VERSION 5.8 ;
BUSBITCHARS "[]" ;
DIVIDERCHAR "/" ;
UNITS
    DATABASE MICRONS 1000 ;
END UNITS

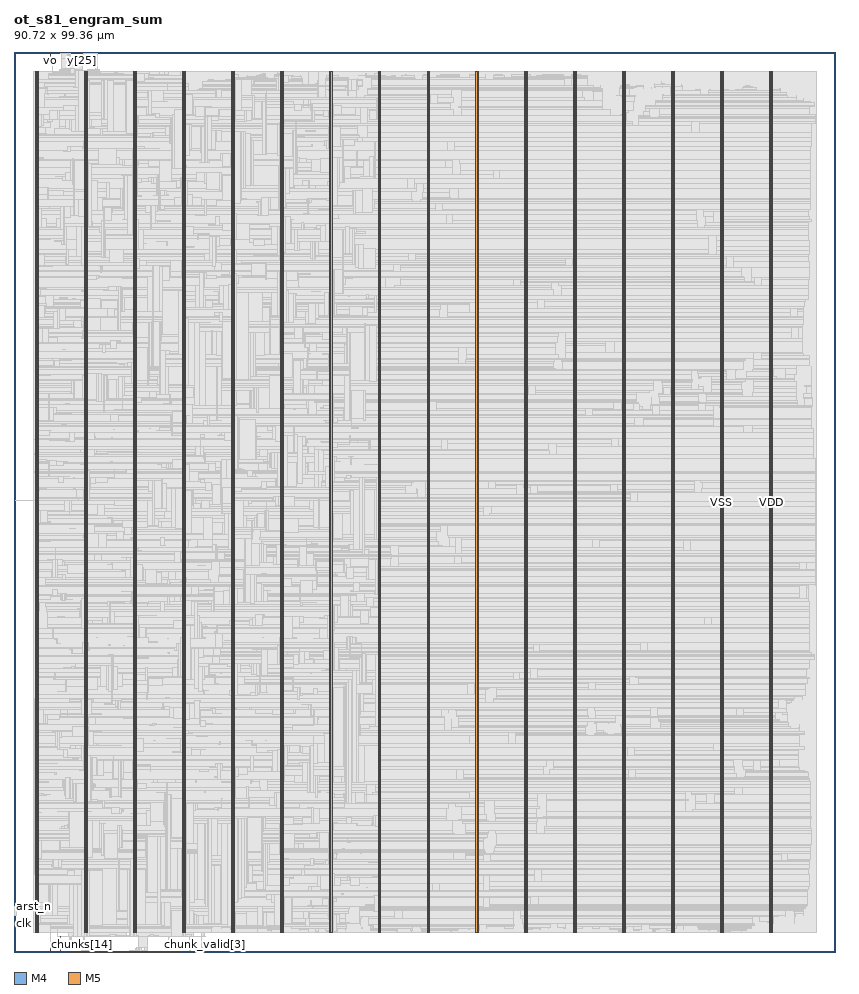
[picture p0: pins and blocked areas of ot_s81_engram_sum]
MACRO ot_s81_engram_sum
  FOREIGN ot_s81_engram_sum 0 0 ;
  CLASS BLOCK ;
  SIZE 90.72 BY 99.36 ;
  PIN arst_n
    DIRECTION INPUT ;
    USE SIGNAL ;
    PORT
      LAYER M4 ;
        RECT  0 4.992 0.084 5.016 ;
    END
  END arst_n
  PIN chunk_fault[0]
    DIRECTION INPUT ;
    USE SIGNAL ;
    PORT
      LAYER M5 ;
        RECT  19.392 0 19.416 0.084 ;
    END
  END chunk_fault[0]
  PIN chunk_fault[1]
    DIRECTION INPUT ;
    USE SIGNAL ;
    PORT
      LAYER M5 ;
        RECT  19.488 0 19.512 0.084 ;
    END
  END chunk_fault[1]
  PIN chunk_fault[2]
    DIRECTION INPUT ;
    USE SIGNAL ;
    PORT
      LAYER M5 ;
        RECT  19.584 0 19.608 0.084 ;
    END
  END chunk_fault[2]
  PIN chunk_fault[3]
    DIRECTION INPUT ;
    USE SIGNAL ;
    PORT
      LAYER M5 ;
        RECT  19.68 0 19.704 0.084 ;
    END
  END chunk_fault[3]
  PIN chunk_valid[0]
    DIRECTION INPUT ;
    USE SIGNAL ;
    PORT
      LAYER M5 ;
        RECT  20.736 0 20.76 0.084 ;
    END
  END chunk_valid[0]
  PIN chunk_valid[1]
    DIRECTION INPUT ;
    USE SIGNAL ;
    PORT
      LAYER M5 ;
        RECT  20.832 0 20.856 0.084 ;
    END
  END chunk_valid[1]
  PIN chunk_valid[2]
    DIRECTION INPUT ;
    USE SIGNAL ;
    PORT
      LAYER M5 ;
        RECT  20.928 0 20.952 0.084 ;
    END
  END chunk_valid[2]
  PIN chunk_valid[3]
    DIRECTION INPUT ;
    USE SIGNAL ;
    PORT
      LAYER M5 ;
        RECT  21.024 0 21.048 0.084 ;
    END
  END chunk_valid[3]
  PIN chunks[0]
    DIRECTION INPUT ;
    USE SIGNAL ;
    PORT
      LAYER M5 ;
        RECT  6.144 0 6.168 0.084 ;
    END
  END chunks[0]
  PIN chunks[100]
    DIRECTION INPUT ;
    USE SIGNAL ;
    PORT
      LAYER M5 ;
        RECT  15.744 0 15.768 0.084 ;
    END
  END chunks[100]
  PIN chunks[101]
    DIRECTION INPUT ;
    USE SIGNAL ;
    PORT
      LAYER M5 ;
        RECT  15.84 0 15.864 0.084 ;
    END
  END chunks[101]
  PIN chunks[102]
    DIRECTION INPUT ;
    USE SIGNAL ;
    PORT
      LAYER M5 ;
        RECT  15.936 0 15.96 0.084 ;
    END
  END chunks[102]
  PIN chunks[103]
    DIRECTION INPUT ;
    USE SIGNAL ;
    PORT
      LAYER M5 ;
        RECT  16.032 0 16.056 0.084 ;
    END
  END chunks[103]
  PIN chunks[104]
    DIRECTION INPUT ;
    USE SIGNAL ;
    PORT
      LAYER M5 ;
        RECT  16.128 0 16.152 0.084 ;
    END
  END chunks[104]
  PIN chunks[105]
    DIRECTION INPUT ;
    USE SIGNAL ;
    PORT
      LAYER M5 ;
        RECT  16.224 0 16.248 0.084 ;
    END
  END chunks[105]
  PIN chunks[106]
    DIRECTION INPUT ;
    USE SIGNAL ;
    PORT
      LAYER M5 ;
        RECT  16.32 0 16.344 0.084 ;
    END
  END chunks[106]
  PIN chunks[107]
    DIRECTION INPUT ;
    USE SIGNAL ;
    PORT
      LAYER M5 ;
        RECT  16.416 0 16.44 0.084 ;
    END
  END chunks[107]
  PIN chunks[108]
    DIRECTION INPUT ;
    USE SIGNAL ;
    PORT
      LAYER M5 ;
        RECT  16.512 0 16.536 0.084 ;
    END
  END chunks[108]
  PIN chunks[109]
    DIRECTION INPUT ;
    USE SIGNAL ;
    PORT
      LAYER M5 ;
        RECT  16.608 0 16.632 0.084 ;
    END
  END chunks[109]
  PIN chunks[10]
    DIRECTION INPUT ;
    USE SIGNAL ;
    PORT
      LAYER M5 ;
        RECT  7.104 0 7.128 0.084 ;
    END
  END chunks[10]
  PIN chunks[110]
    DIRECTION INPUT ;
    USE SIGNAL ;
    PORT
      LAYER M5 ;
        RECT  16.704 0 16.728 0.084 ;
    END
  END chunks[110]
  PIN chunks[111]
    DIRECTION INPUT ;
    USE SIGNAL ;
    PORT
      LAYER M5 ;
        RECT  16.8 0 16.824 0.084 ;
    END
  END chunks[111]
  PIN chunks[112]
    DIRECTION INPUT ;
    USE SIGNAL ;
    PORT
      LAYER M5 ;
        RECT  16.896 0 16.92 0.084 ;
    END
  END chunks[112]
  PIN chunks[113]
    DIRECTION INPUT ;
    USE SIGNAL ;
    PORT
      LAYER M5 ;
        RECT  16.992 0 17.016 0.084 ;
    END
  END chunks[113]
  PIN chunks[114]
    DIRECTION INPUT ;
    USE SIGNAL ;
    PORT
      LAYER M5 ;
        RECT  17.088 0 17.112 0.084 ;
    END
  END chunks[114]
  PIN chunks[115]
    DIRECTION INPUT ;
    USE SIGNAL ;
    PORT
      LAYER M5 ;
        RECT  17.184 0 17.208 0.084 ;
    END
  END chunks[115]
  PIN chunks[116]
    DIRECTION INPUT ;
    USE SIGNAL ;
    PORT
      LAYER M5 ;
        RECT  17.28 0 17.304 0.084 ;
    END
  END chunks[116]
  PIN chunks[117]
    DIRECTION INPUT ;
    USE SIGNAL ;
    PORT
      LAYER M5 ;
        RECT  17.376 0 17.4 0.084 ;
    END
  END chunks[117]
  PIN chunks[118]
    DIRECTION INPUT ;
    USE SIGNAL ;
    PORT
      LAYER M5 ;
        RECT  17.472 0 17.496 0.084 ;
    END
  END chunks[118]
  PIN chunks[119]
    DIRECTION INPUT ;
    USE SIGNAL ;
    PORT
      LAYER M5 ;
        RECT  17.568 0 17.592 0.084 ;
    END
  END chunks[119]
  PIN chunks[11]
    DIRECTION INPUT ;
    USE SIGNAL ;
    PORT
      LAYER M5 ;
        RECT  7.2 0 7.224 0.084 ;
    END
  END chunks[11]
  PIN chunks[120]
    DIRECTION INPUT ;
    USE SIGNAL ;
    PORT
      LAYER M5 ;
        RECT  17.664 0 17.688 0.084 ;
    END
  END chunks[120]
  PIN chunks[121]
    DIRECTION INPUT ;
    USE SIGNAL ;
    PORT
      LAYER M5 ;
        RECT  17.76 0 17.784 0.084 ;
    END
  END chunks[121]
  PIN chunks[122]
    DIRECTION INPUT ;
    USE SIGNAL ;
    PORT
      LAYER M5 ;
        RECT  17.856 0 17.88 0.084 ;
    END
  END chunks[122]
  PIN chunks[123]
    DIRECTION INPUT ;
    USE SIGNAL ;
    PORT
      LAYER M5 ;
        RECT  17.952 0 17.976 0.084 ;
    END
  END chunks[123]
  PIN chunks[124]
    DIRECTION INPUT ;
    USE SIGNAL ;
    PORT
      LAYER M5 ;
        RECT  18.048 0 18.072 0.084 ;
    END
  END chunks[124]
  PIN chunks[125]
    DIRECTION INPUT ;
    USE SIGNAL ;
    PORT
      LAYER M5 ;
        RECT  18.144 0 18.168 0.084 ;
    END
  END chunks[125]
  PIN chunks[126]
    DIRECTION INPUT ;
    USE SIGNAL ;
    PORT
      LAYER M5 ;
        RECT  18.24 0 18.264 0.084 ;
    END
  END chunks[126]
  PIN chunks[127]
    DIRECTION INPUT ;
    USE SIGNAL ;
    PORT
      LAYER M5 ;
        RECT  18.336 0 18.36 0.084 ;
    END
  END chunks[127]
  PIN chunks[12]
    DIRECTION INPUT ;
    USE SIGNAL ;
    PORT
      LAYER M5 ;
        RECT  7.296 0 7.32 0.084 ;
    END
  END chunks[12]
  PIN chunks[13]
    DIRECTION INPUT ;
    USE SIGNAL ;
    PORT
      LAYER M5 ;
        RECT  7.392 0 7.416 0.084 ;
    END
  END chunks[13]
  PIN chunks[14]
    DIRECTION INPUT ;
    USE SIGNAL ;
    PORT
      LAYER M5 ;
        RECT  7.488 0 7.512 0.084 ;
    END
  END chunks[14]
  PIN chunks[15]
    DIRECTION INPUT ;
    USE SIGNAL ;
    PORT
      LAYER M5 ;
        RECT  7.584 0 7.608 0.084 ;
    END
  END chunks[15]
  PIN chunks[16]
    DIRECTION INPUT ;
    USE SIGNAL ;
    PORT
      LAYER M5 ;
        RECT  7.68 0 7.704 0.084 ;
    END
  END chunks[16]
  PIN chunks[17]
    DIRECTION INPUT ;
    USE SIGNAL ;
    PORT
      LAYER M5 ;
        RECT  7.776 0 7.8 0.084 ;
    END
  END chunks[17]
  PIN chunks[18]
    DIRECTION INPUT ;
    USE SIGNAL ;
    PORT
      LAYER M5 ;
        RECT  7.872 0 7.896 0.084 ;
    END
  END chunks[18]
  PIN chunks[19]
    DIRECTION INPUT ;
    USE SIGNAL ;
    PORT
      LAYER M5 ;
        RECT  7.968 0 7.992 0.084 ;
    END
  END chunks[19]
  PIN chunks[1]
    DIRECTION INPUT ;
    USE SIGNAL ;
    PORT
      LAYER M5 ;
        RECT  6.24 0 6.264 0.084 ;
    END
  END chunks[1]
  PIN chunks[20]
    DIRECTION INPUT ;
    USE SIGNAL ;
    PORT
      LAYER M5 ;
        RECT  8.064 0 8.088 0.084 ;
    END
  END chunks[20]
  PIN chunks[21]
    DIRECTION INPUT ;
    USE SIGNAL ;
    PORT
      LAYER M5 ;
        RECT  8.16 0 8.184 0.084 ;
    END
  END chunks[21]
  PIN chunks[22]
    DIRECTION INPUT ;
    USE SIGNAL ;
    PORT
      LAYER M5 ;
        RECT  8.256 0 8.28 0.084 ;
    END
  END chunks[22]
  PIN chunks[23]
    DIRECTION INPUT ;
    USE SIGNAL ;
    PORT
      LAYER M5 ;
        RECT  8.352 0 8.376 0.084 ;
    END
  END chunks[23]
  PIN chunks[24]
    DIRECTION INPUT ;
    USE SIGNAL ;
    PORT
      LAYER M5 ;
        RECT  8.448 0 8.472 0.084 ;
    END
  END chunks[24]
  PIN chunks[25]
    DIRECTION INPUT ;
    USE SIGNAL ;
    PORT
      LAYER M5 ;
        RECT  8.544 0 8.568 0.084 ;
    END
  END chunks[25]
  PIN chunks[26]
    DIRECTION INPUT ;
    USE SIGNAL ;
    PORT
      LAYER M5 ;
        RECT  8.64 0 8.664 0.084 ;
    END
  END chunks[26]
  PIN chunks[27]
    DIRECTION INPUT ;
    USE SIGNAL ;
    PORT
      LAYER M5 ;
        RECT  8.736 0 8.76 0.084 ;
    END
  END chunks[27]
  PIN chunks[28]
    DIRECTION INPUT ;
    USE SIGNAL ;
    PORT
      LAYER M5 ;
        RECT  8.832 0 8.856 0.084 ;
    END
  END chunks[28]
  PIN chunks[29]
    DIRECTION INPUT ;
    USE SIGNAL ;
    PORT
      LAYER M5 ;
        RECT  8.928 0 8.952 0.084 ;
    END
  END chunks[29]
  PIN chunks[2]
    DIRECTION INPUT ;
    USE SIGNAL ;
    PORT
      LAYER M5 ;
        RECT  6.336 0 6.36 0.084 ;
    END
  END chunks[2]
  PIN chunks[30]
    DIRECTION INPUT ;
    USE SIGNAL ;
    PORT
      LAYER M5 ;
        RECT  9.024 0 9.048 0.084 ;
    END
  END chunks[30]
  PIN chunks[31]
    DIRECTION INPUT ;
    USE SIGNAL ;
    PORT
      LAYER M5 ;
        RECT  9.12 0 9.144 0.084 ;
    END
  END chunks[31]
  PIN chunks[32]
    DIRECTION INPUT ;
    USE SIGNAL ;
    PORT
      LAYER M5 ;
        RECT  9.216 0 9.24 0.084 ;
    END
  END chunks[32]
  PIN chunks[33]
    DIRECTION INPUT ;
    USE SIGNAL ;
    PORT
      LAYER M5 ;
        RECT  9.312 0 9.336 0.084 ;
    END
  END chunks[33]
  PIN chunks[34]
    DIRECTION INPUT ;
    USE SIGNAL ;
    PORT
      LAYER M5 ;
        RECT  9.408 0 9.432 0.084 ;
    END
  END chunks[34]
  PIN chunks[35]
    DIRECTION INPUT ;
    USE SIGNAL ;
    PORT
      LAYER M5 ;
        RECT  9.504 0 9.528 0.084 ;
    END
  END chunks[35]
  PIN chunks[36]
    DIRECTION INPUT ;
    USE SIGNAL ;
    PORT
      LAYER M5 ;
        RECT  9.6 0 9.624 0.084 ;
    END
  END chunks[36]
  PIN chunks[37]
    DIRECTION INPUT ;
    USE SIGNAL ;
    PORT
      LAYER M5 ;
        RECT  9.696 0 9.72 0.084 ;
    END
  END chunks[37]
  PIN chunks[38]
    DIRECTION INPUT ;
    USE SIGNAL ;
    PORT
      LAYER M5 ;
        RECT  9.792 0 9.816 0.084 ;
    END
  END chunks[38]
  PIN chunks[39]
    DIRECTION INPUT ;
    USE SIGNAL ;
    PORT
      LAYER M5 ;
        RECT  9.888 0 9.912 0.084 ;
    END
  END chunks[39]
  PIN chunks[3]
    DIRECTION INPUT ;
    USE SIGNAL ;
    PORT
      LAYER M5 ;
        RECT  6.432 0 6.456 0.084 ;
    END
  END chunks[3]
  PIN chunks[40]
    DIRECTION INPUT ;
    USE SIGNAL ;
    PORT
      LAYER M5 ;
        RECT  9.984 0 10.008 0.084 ;
    END
  END chunks[40]
  PIN chunks[41]
    DIRECTION INPUT ;
    USE SIGNAL ;
    PORT
      LAYER M5 ;
        RECT  10.08 0 10.104 0.084 ;
    END
  END chunks[41]
  PIN chunks[42]
    DIRECTION INPUT ;
    USE SIGNAL ;
    PORT
      LAYER M5 ;
        RECT  10.176 0 10.2 0.084 ;
    END
  END chunks[42]
  PIN chunks[43]
    DIRECTION INPUT ;
    USE SIGNAL ;
    PORT
      LAYER M5 ;
        RECT  10.272 0 10.296 0.084 ;
    END
  END chunks[43]
  PIN chunks[44]
    DIRECTION INPUT ;
    USE SIGNAL ;
    PORT
      LAYER M5 ;
        RECT  10.368 0 10.392 0.084 ;
    END
  END chunks[44]
  PIN chunks[45]
    DIRECTION INPUT ;
    USE SIGNAL ;
    PORT
      LAYER M5 ;
        RECT  10.464 0 10.488 0.084 ;
    END
  END chunks[45]
  PIN chunks[46]
    DIRECTION INPUT ;
    USE SIGNAL ;
    PORT
      LAYER M5 ;
        RECT  10.56 0 10.584 0.084 ;
    END
  END chunks[46]
  PIN chunks[47]
    DIRECTION INPUT ;
    USE SIGNAL ;
    PORT
      LAYER M5 ;
        RECT  10.656 0 10.68 0.084 ;
    END
  END chunks[47]
  PIN chunks[48]
    DIRECTION INPUT ;
    USE SIGNAL ;
    PORT
      LAYER M5 ;
        RECT  10.752 0 10.776 0.084 ;
    END
  END chunks[48]
  PIN chunks[49]
    DIRECTION INPUT ;
    USE SIGNAL ;
    PORT
      LAYER M5 ;
        RECT  10.848 0 10.872 0.084 ;
    END
  END chunks[49]
  PIN chunks[4]
    DIRECTION INPUT ;
    USE SIGNAL ;
    PORT
      LAYER M5 ;
        RECT  6.528 0 6.552 0.084 ;
    END
  END chunks[4]
  PIN chunks[50]
    DIRECTION INPUT ;
    USE SIGNAL ;
    PORT
      LAYER M5 ;
        RECT  10.944 0 10.968 0.084 ;
    END
  END chunks[50]
  PIN chunks[51]
    DIRECTION INPUT ;
    USE SIGNAL ;
    PORT
      LAYER M5 ;
        RECT  11.04 0 11.064 0.084 ;
    END
  END chunks[51]
  PIN chunks[52]
    DIRECTION INPUT ;
    USE SIGNAL ;
    PORT
      LAYER M5 ;
        RECT  11.136 0 11.16 0.084 ;
    END
  END chunks[52]
  PIN chunks[53]
    DIRECTION INPUT ;
    USE SIGNAL ;
    PORT
      LAYER M5 ;
        RECT  11.232 0 11.256 0.084 ;
    END
  END chunks[53]
  PIN chunks[54]
    DIRECTION INPUT ;
    USE SIGNAL ;
    PORT
      LAYER M5 ;
        RECT  11.328 0 11.352 0.084 ;
    END
  END chunks[54]
  PIN chunks[55]
    DIRECTION INPUT ;
    USE SIGNAL ;
    PORT
      LAYER M5 ;
        RECT  11.424 0 11.448 0.084 ;
    END
  END chunks[55]
  PIN chunks[56]
    DIRECTION INPUT ;
    USE SIGNAL ;
    PORT
      LAYER M5 ;
        RECT  11.52 0 11.544 0.084 ;
    END
  END chunks[56]
  PIN chunks[57]
    DIRECTION INPUT ;
    USE SIGNAL ;
    PORT
      LAYER M5 ;
        RECT  11.616 0 11.64 0.084 ;
    END
  END chunks[57]
  PIN chunks[58]
    DIRECTION INPUT ;
    USE SIGNAL ;
    PORT
      LAYER M5 ;
        RECT  11.712 0 11.736 0.084 ;
    END
  END chunks[58]
  PIN chunks[59]
    DIRECTION INPUT ;
    USE SIGNAL ;
    PORT
      LAYER M5 ;
        RECT  11.808 0 11.832 0.084 ;
    END
  END chunks[59]
  PIN chunks[5]
    DIRECTION INPUT ;
    USE SIGNAL ;
    PORT
      LAYER M5 ;
        RECT  6.624 0 6.648 0.084 ;
    END
  END chunks[5]
  PIN chunks[60]
    DIRECTION INPUT ;
    USE SIGNAL ;
    PORT
      LAYER M5 ;
        RECT  11.904 0 11.928 0.084 ;
    END
  END chunks[60]
  PIN chunks[61]
    DIRECTION INPUT ;
    USE SIGNAL ;
    PORT
      LAYER M5 ;
        RECT  12 0 12.024 0.084 ;
    END
  END chunks[61]
  PIN chunks[62]
    DIRECTION INPUT ;
    USE SIGNAL ;
    PORT
      LAYER M5 ;
        RECT  12.096 0 12.12 0.084 ;
    END
  END chunks[62]
  PIN chunks[63]
    DIRECTION INPUT ;
    USE SIGNAL ;
    PORT
      LAYER M5 ;
        RECT  12.192 0 12.216 0.084 ;
    END
  END chunks[63]
  PIN chunks[64]
    DIRECTION INPUT ;
    USE SIGNAL ;
    PORT
      LAYER M5 ;
        RECT  12.288 0 12.312 0.084 ;
    END
  END chunks[64]
  PIN chunks[65]
    DIRECTION INPUT ;
    USE SIGNAL ;
    PORT
      LAYER M5 ;
        RECT  12.384 0 12.408 0.084 ;
    END
  END chunks[65]
  PIN chunks[66]
    DIRECTION INPUT ;
    USE SIGNAL ;
    PORT
      LAYER M5 ;
        RECT  12.48 0 12.504 0.084 ;
    END
  END chunks[66]
  PIN chunks[67]
    DIRECTION INPUT ;
    USE SIGNAL ;
    PORT
      LAYER M5 ;
        RECT  12.576 0 12.6 0.084 ;
    END
  END chunks[67]
  PIN chunks[68]
    DIRECTION INPUT ;
    USE SIGNAL ;
    PORT
      LAYER M5 ;
        RECT  12.672 0 12.696 0.084 ;
    END
  END chunks[68]
  PIN chunks[69]
    DIRECTION INPUT ;
    USE SIGNAL ;
    PORT
      LAYER M5 ;
        RECT  12.768 0 12.792 0.084 ;
    END
  END chunks[69]
  PIN chunks[6]
    DIRECTION INPUT ;
    USE SIGNAL ;
    PORT
      LAYER M5 ;
        RECT  6.72 0 6.744 0.084 ;
    END
  END chunks[6]
  PIN chunks[70]
    DIRECTION INPUT ;
    USE SIGNAL ;
    PORT
      LAYER M5 ;
        RECT  12.864 0 12.888 0.084 ;
    END
  END chunks[70]
  PIN chunks[71]
    DIRECTION INPUT ;
    USE SIGNAL ;
    PORT
      LAYER M5 ;
        RECT  12.96 0 12.984 0.084 ;
    END
  END chunks[71]
  PIN chunks[72]
    DIRECTION INPUT ;
    USE SIGNAL ;
    PORT
      LAYER M5 ;
        RECT  13.056 0 13.08 0.084 ;
    END
  END chunks[72]
  PIN chunks[73]
    DIRECTION INPUT ;
    USE SIGNAL ;
    PORT
      LAYER M5 ;
        RECT  13.152 0 13.176 0.084 ;
    END
  END chunks[73]
  PIN chunks[74]
    DIRECTION INPUT ;
    USE SIGNAL ;
    PORT
      LAYER M5 ;
        RECT  13.248 0 13.272 0.084 ;
    END
  END chunks[74]
  PIN chunks[75]
    DIRECTION INPUT ;
    USE SIGNAL ;
    PORT
      LAYER M5 ;
        RECT  13.344 0 13.368 0.084 ;
    END
  END chunks[75]
  PIN chunks[76]
    DIRECTION INPUT ;
    USE SIGNAL ;
    PORT
      LAYER M5 ;
        RECT  13.44 0 13.464 0.084 ;
    END
  END chunks[76]
  PIN chunks[77]
    DIRECTION INPUT ;
    USE SIGNAL ;
    PORT
      LAYER M5 ;
        RECT  13.536 0 13.56 0.084 ;
    END
  END chunks[77]
  PIN chunks[78]
    DIRECTION INPUT ;
    USE SIGNAL ;
    PORT
      LAYER M5 ;
        RECT  13.632 0 13.656 0.084 ;
    END
  END chunks[78]
  PIN chunks[79]
    DIRECTION INPUT ;
    USE SIGNAL ;
    PORT
      LAYER M5 ;
        RECT  13.728 0 13.752 0.084 ;
    END
  END chunks[79]
  PIN chunks[7]
    DIRECTION INPUT ;
    USE SIGNAL ;
    PORT
      LAYER M5 ;
        RECT  6.816 0 6.84 0.084 ;
    END
  END chunks[7]
  PIN chunks[80]
    DIRECTION INPUT ;
    USE SIGNAL ;
    PORT
      LAYER M5 ;
        RECT  13.824 0 13.848 0.084 ;
    END
  END chunks[80]
  PIN chunks[81]
    DIRECTION INPUT ;
    USE SIGNAL ;
    PORT
      LAYER M5 ;
        RECT  13.92 0 13.944 0.084 ;
    END
  END chunks[81]
  PIN chunks[82]
    DIRECTION INPUT ;
    USE SIGNAL ;
    PORT
      LAYER M5 ;
        RECT  14.016 0 14.04 0.084 ;
    END
  END chunks[82]
  PIN chunks[83]
    DIRECTION INPUT ;
    USE SIGNAL ;
    PORT
      LAYER M5 ;
        RECT  14.112 0 14.136 0.084 ;
    END
  END chunks[83]
  PIN chunks[84]
    DIRECTION INPUT ;
    USE SIGNAL ;
    PORT
      LAYER M5 ;
        RECT  14.208 0 14.232 0.084 ;
    END
  END chunks[84]
  PIN chunks[85]
    DIRECTION INPUT ;
    USE SIGNAL ;
    PORT
      LAYER M5 ;
        RECT  14.304 0 14.328 0.084 ;
    END
  END chunks[85]
  PIN chunks[86]
    DIRECTION INPUT ;
    USE SIGNAL ;
    PORT
      LAYER M5 ;
        RECT  14.4 0 14.424 0.084 ;
    END
  END chunks[86]
  PIN chunks[87]
    DIRECTION INPUT ;
    USE SIGNAL ;
    PORT
      LAYER M5 ;
        RECT  14.496 0 14.52 0.084 ;
    END
  END chunks[87]
  PIN chunks[88]
    DIRECTION INPUT ;
    USE SIGNAL ;
    PORT
      LAYER M5 ;
        RECT  14.592 0 14.616 0.084 ;
    END
  END chunks[88]
  PIN chunks[89]
    DIRECTION INPUT ;
    USE SIGNAL ;
    PORT
      LAYER M5 ;
        RECT  14.688 0 14.712 0.084 ;
    END
  END chunks[89]
  PIN chunks[8]
    DIRECTION INPUT ;
    USE SIGNAL ;
    PORT
      LAYER M5 ;
        RECT  6.912 0 6.936 0.084 ;
    END
  END chunks[8]
  PIN chunks[90]
    DIRECTION INPUT ;
    USE SIGNAL ;
    PORT
      LAYER M5 ;
        RECT  14.784 0 14.808 0.084 ;
    END
  END chunks[90]
  PIN chunks[91]
    DIRECTION INPUT ;
    USE SIGNAL ;
    PORT
      LAYER M5 ;
        RECT  14.88 0 14.904 0.084 ;
    END
  END chunks[91]
  PIN chunks[92]
    DIRECTION INPUT ;
    USE SIGNAL ;
    PORT
      LAYER M5 ;
        RECT  14.976 0 15 0.084 ;
    END
  END chunks[92]
  PIN chunks[93]
    DIRECTION INPUT ;
    USE SIGNAL ;
    PORT
      LAYER M5 ;
        RECT  15.072 0 15.096 0.084 ;
    END
  END chunks[93]
  PIN chunks[94]
    DIRECTION INPUT ;
    USE SIGNAL ;
    PORT
      LAYER M5 ;
        RECT  15.168 0 15.192 0.084 ;
    END
  END chunks[94]
  PIN chunks[95]
    DIRECTION INPUT ;
    USE SIGNAL ;
    PORT
      LAYER M5 ;
        RECT  15.264 0 15.288 0.084 ;
    END
  END chunks[95]
  PIN chunks[96]
    DIRECTION INPUT ;
    USE SIGNAL ;
    PORT
      LAYER M5 ;
        RECT  15.36 0 15.384 0.084 ;
    END
  END chunks[96]
  PIN chunks[97]
    DIRECTION INPUT ;
    USE SIGNAL ;
    PORT
      LAYER M5 ;
        RECT  15.456 0 15.48 0.084 ;
    END
  END chunks[97]
  PIN chunks[98]
    DIRECTION INPUT ;
    USE SIGNAL ;
    PORT
      LAYER M5 ;
        RECT  15.552 0 15.576 0.084 ;
    END
  END chunks[98]
  PIN chunks[99]
    DIRECTION INPUT ;
    USE SIGNAL ;
    PORT
      LAYER M5 ;
        RECT  15.648 0 15.672 0.084 ;
    END
  END chunks[99]
  PIN chunks[9]
    DIRECTION INPUT ;
    USE SIGNAL ;
    PORT
      LAYER M5 ;
        RECT  7.008 0 7.032 0.084 ;
    END
  END chunks[9]
  PIN clk
    DIRECTION INPUT ;
    USE SIGNAL ;
    PORT
      LAYER M4 ;
        RECT  0 4.032 0.084 4.056 ;
    END
  END clk
  PIN fault
    DIRECTION OUTPUT ;
    USE SIGNAL ;
    PORT
      LAYER M5 ;
        RECT  9.12 99.276 9.144 99.36 ;
    END
    PORT
      LAYER M5 ;
        RECT  9.12 99.251 9.144 99.344 ;
    END
  END fault
  PIN go
    DIRECTION INPUT ;
    USE SIGNAL ;
    PORT
      LAYER M5 ;
        RECT  4.032 0 4.056 0.084 ;
    END
    PORT
      LAYER M5 ;
        RECT  4.032 0.016 4.056 0.611 ;
    END
  END go
  PIN v
    DIRECTION INPUT ;
    USE SIGNAL ;
    PORT
      LAYER M5 ;
        RECT  5.088 0 5.112 0.084 ;
    END
    PORT
      LAYER M5 ;
        RECT  5.088 0.016 5.112 1.763 ;
    END
  END v
  PIN vo
    DIRECTION OUTPUT ;
    USE SIGNAL ;
    PORT
      LAYER M5 ;
        RECT  4.032 99.276 4.056 99.36 ;
    END
    PORT
      LAYER M5 ;
        RECT  4.032 98.053 4.056 99.344 ;
    END
  END vo
  PIN y[0]
    DIRECTION OUTPUT ;
    USE SIGNAL ;
    PORT
      LAYER M5 ;
        RECT  5.088 99.276 5.112 99.36 ;
    END
  END y[0]
  PIN y[10]
    DIRECTION OUTPUT ;
    USE SIGNAL ;
    PORT
      LAYER M5 ;
        RECT  6.048 99.276 6.072 99.36 ;
    END
  END y[10]
  PIN y[11]
    DIRECTION OUTPUT ;
    USE SIGNAL ;
    PORT
      LAYER M5 ;
        RECT  6.144 99.276 6.168 99.36 ;
    END
  END y[11]
  PIN y[12]
    DIRECTION OUTPUT ;
    USE SIGNAL ;
    PORT
      LAYER M5 ;
        RECT  6.24 99.276 6.264 99.36 ;
    END
  END y[12]
  PIN y[13]
    DIRECTION OUTPUT ;
    USE SIGNAL ;
    PORT
      LAYER M5 ;
        RECT  6.336 99.276 6.36 99.36 ;
    END
  END y[13]
  PIN y[14]
    DIRECTION OUTPUT ;
    USE SIGNAL ;
    PORT
      LAYER M5 ;
        RECT  6.432 99.276 6.456 99.36 ;
    END
  END y[14]
  PIN y[15]
    DIRECTION OUTPUT ;
    USE SIGNAL ;
    PORT
      LAYER M5 ;
        RECT  6.528 99.276 6.552 99.36 ;
    END
  END y[15]
  PIN y[16]
    DIRECTION OUTPUT ;
    USE SIGNAL ;
    PORT
      LAYER M5 ;
        RECT  6.624 99.276 6.648 99.36 ;
    END
  END y[16]
  PIN y[17]
    DIRECTION OUTPUT ;
    USE SIGNAL ;
    PORT
      LAYER M5 ;
        RECT  6.72 99.276 6.744 99.36 ;
    END
  END y[17]
  PIN y[18]
    DIRECTION OUTPUT ;
    USE SIGNAL ;
    PORT
      LAYER M5 ;
        RECT  6.816 99.276 6.84 99.36 ;
    END
  END y[18]
  PIN y[19]
    DIRECTION OUTPUT ;
    USE SIGNAL ;
    PORT
      LAYER M5 ;
        RECT  6.912 99.276 6.936 99.36 ;
    END
  END y[19]
  PIN y[1]
    DIRECTION OUTPUT ;
    USE SIGNAL ;
    PORT
      LAYER M5 ;
        RECT  5.184 99.276 5.208 99.36 ;
    END
  END y[1]
  PIN y[20]
    DIRECTION OUTPUT ;
    USE SIGNAL ;
    PORT
      LAYER M5 ;
        RECT  7.008 99.276 7.032 99.36 ;
    END
  END y[20]
  PIN y[21]
    DIRECTION OUTPUT ;
    USE SIGNAL ;
    PORT
      LAYER M5 ;
        RECT  7.104 99.276 7.128 99.36 ;
    END
  END y[21]
  PIN y[22]
    DIRECTION OUTPUT ;
    USE SIGNAL ;
    PORT
      LAYER M5 ;
        RECT  7.2 99.276 7.224 99.36 ;
    END
  END y[22]
  PIN y[23]
    DIRECTION OUTPUT ;
    USE SIGNAL ;
    PORT
      LAYER M5 ;
        RECT  7.296 99.276 7.32 99.36 ;
    END
  END y[23]
  PIN y[24]
    DIRECTION OUTPUT ;
    USE SIGNAL ;
    PORT
      LAYER M5 ;
        RECT  7.392 99.276 7.416 99.36 ;
    END
  END y[24]
  PIN y[25]
    DIRECTION OUTPUT ;
    USE SIGNAL ;
    PORT
      LAYER M5 ;
        RECT  7.488 99.276 7.512 99.36 ;
    END
  END y[25]
  PIN y[26]
    DIRECTION OUTPUT ;
    USE SIGNAL ;
    PORT
      LAYER M5 ;
        RECT  7.584 99.276 7.608 99.36 ;
    END
  END y[26]
  PIN y[27]
    DIRECTION OUTPUT ;
    USE SIGNAL ;
    PORT
      LAYER M5 ;
        RECT  7.68 99.276 7.704 99.36 ;
    END
  END y[27]
  PIN y[28]
    DIRECTION OUTPUT ;
    USE SIGNAL ;
    PORT
      LAYER M5 ;
        RECT  7.776 99.276 7.8 99.36 ;
    END
  END y[28]
  PIN y[29]
    DIRECTION OUTPUT ;
    USE SIGNAL ;
    PORT
      LAYER M5 ;
        RECT  7.872 99.276 7.896 99.36 ;
    END
  END y[29]
  PIN y[2]
    DIRECTION OUTPUT ;
    USE SIGNAL ;
    PORT
      LAYER M5 ;
        RECT  5.28 99.276 5.304 99.36 ;
    END
  END y[2]
  PIN y[30]
    DIRECTION OUTPUT ;
    USE SIGNAL ;
    PORT
      LAYER M5 ;
        RECT  7.968 99.276 7.992 99.36 ;
    END
  END y[30]
  PIN y[31]
    DIRECTION OUTPUT ;
    USE SIGNAL ;
    PORT
      LAYER M5 ;
        RECT  8.064 99.276 8.088 99.36 ;
    END
  END y[31]
  PIN y[3]
    DIRECTION OUTPUT ;
    USE SIGNAL ;
    PORT
      LAYER M5 ;
        RECT  5.376 99.276 5.4 99.36 ;
    END
  END y[3]
  PIN y[4]
    DIRECTION OUTPUT ;
    USE SIGNAL ;
    PORT
      LAYER M5 ;
        RECT  5.472 99.276 5.496 99.36 ;
    END
  END y[4]
  PIN y[5]
    DIRECTION OUTPUT ;
    USE SIGNAL ;
    PORT
      LAYER M5 ;
        RECT  5.568 99.276 5.592 99.36 ;
    END
  END y[5]
  PIN y[6]
    DIRECTION OUTPUT ;
    USE SIGNAL ;
    PORT
      LAYER M5 ;
        RECT  5.664 99.276 5.688 99.36 ;
    END
  END y[6]
  PIN y[7]
    DIRECTION OUTPUT ;
    USE SIGNAL ;
    PORT
      LAYER M5 ;
        RECT  5.76 99.276 5.784 99.36 ;
    END
  END y[7]
  PIN y[8]
    DIRECTION OUTPUT ;
    USE SIGNAL ;
    PORT
      LAYER M5 ;
        RECT  5.856 99.276 5.88 99.36 ;
    END
  END y[8]
  PIN y[9]
    DIRECTION OUTPUT ;
    USE SIGNAL ;
    PORT
      LAYER M5 ;
        RECT  5.952 99.276 5.976 99.36 ;
    END
  END y[9]
  PIN VDD
    DIRECTION INOUT ;
    USE POWER ;
    PORT
      LAYER M5 ;
        RECT  83.592 2.151 83.712 97.209 ;
        RECT  78.192 2.151 78.312 97.209 ;
        RECT  72.792 2.151 72.912 97.209 ;
        RECT  67.392 2.151 67.512 97.209 ;
        RECT  61.992 2.151 62.112 97.209 ;
        RECT  56.592 2.151 56.712 97.209 ;
        RECT  51.192 2.151 51.312 97.209 ;
        RECT  45.792 2.151 45.912 97.209 ;
        RECT  40.392 2.151 40.512 97.209 ;
        RECT  34.992 2.151 35.112 97.209 ;
        RECT  29.592 2.151 29.712 97.209 ;
        RECT  24.192 2.151 24.312 97.209 ;
        RECT  18.792 2.151 18.912 97.209 ;
        RECT  13.392 2.151 13.512 97.209 ;
        RECT  7.992 2.151 8.112 97.209 ;
        RECT  2.592 2.151 2.712 97.209 ;
    END
  END VDD
  PIN VSS
    DIRECTION INOUT ;
    USE GROUND ;
    PORT
      LAYER M5 ;
        RECT  83.4 2.137 83.52 97.223 ;
        RECT  78 2.137 78.12 97.223 ;
        RECT  72.6 2.137 72.72 97.223 ;
        RECT  67.2 2.137 67.32 97.223 ;
        RECT  61.8 2.137 61.92 97.223 ;
        RECT  56.4 2.137 56.52 97.223 ;
        RECT  51 2.137 51.12 97.223 ;
        RECT  45.6 2.137 45.72 97.223 ;
        RECT  40.2 2.137 40.32 97.223 ;
        RECT  34.8 2.137 34.92 97.223 ;
        RECT  29.4 2.137 29.52 97.223 ;
        RECT  24 2.137 24.12 97.223 ;
        RECT  18.6 2.137 18.72 97.223 ;
        RECT  13.2 2.137 13.32 97.223 ;
        RECT  7.8 2.137 7.92 97.223 ;
        RECT  2.4 2.137 2.52 97.223 ;
    END
  END VSS
  # OT_OBS_CLOSED layer=M5 d_um=1.536 added=496
  OBS
    LAYER RVTN ;
     RECT  2.16 2.16 88.56 2.295 ;
     RECT  2.16 2.565 88.56 2.835 ;
     RECT  2.16 3.105 88.56 3.375 ;
     RECT  2.16 3.645 88.56 3.915 ;
     RECT  2.16 4.185 88.56 4.455 ;
     RECT  2.16 4.725 88.56 4.995 ;
     RECT  2.16 5.265 88.56 5.535 ;
     RECT  2.16 5.805 88.56 6.075 ;
     RECT  2.16 6.345 88.56 6.615 ;
     RECT  2.16 6.885 88.56 7.155 ;
     RECT  2.16 7.425 88.56 7.695 ;
     RECT  2.16 7.965 88.56 8.235 ;
     RECT  2.16 8.505 88.56 8.775 ;
     RECT  2.16 9.045 88.56 9.315 ;
     RECT  2.16 9.585 88.56 9.855 ;
     RECT  2.16 10.125 88.56 10.395 ;
     RECT  2.16 10.665 88.56 10.935 ;
     RECT  2.16 11.205 88.56 11.475 ;
     RECT  2.16 11.745 88.56 12.015 ;
     RECT  2.16 12.285 88.56 12.555 ;
     RECT  2.16 12.825 88.56 13.095 ;
     RECT  2.16 13.365 88.56 13.635 ;
     RECT  2.16 13.905 88.56 14.175 ;
     RECT  2.16 14.445 88.56 14.715 ;
     RECT  2.16 14.985 88.56 15.255 ;
     RECT  2.16 15.525 88.56 15.795 ;
     RECT  2.16 16.065 88.56 16.335 ;
     RECT  2.16 16.605 88.56 16.875 ;
     RECT  2.16 17.145 88.56 17.415 ;
     RECT  2.16 17.685 88.56 17.955 ;
     RECT  2.16 18.225 88.56 18.495 ;
     RECT  2.16 18.765 88.56 19.035 ;
     RECT  2.16 19.305 88.56 19.575 ;
     RECT  2.16 19.845 88.56 20.115 ;
     RECT  2.16 20.385 88.56 20.655 ;
     RECT  2.16 20.925 88.56 21.195 ;
     RECT  2.16 21.465 88.56 21.735 ;
     RECT  2.16 22.005 88.56 22.275 ;
     RECT  2.16 22.545 88.56 22.815 ;
     RECT  2.16 23.085 88.56 23.355 ;
     RECT  2.16 23.625 88.56 23.895 ;
     RECT  2.16 24.165 88.56 24.435 ;
     RECT  2.16 24.705 88.56 24.975 ;
     RECT  2.16 25.245 88.56 25.515 ;
     RECT  2.16 25.785 88.56 26.055 ;
     RECT  2.16 26.325 88.56 26.595 ;
     RECT  2.16 26.865 88.56 27.135 ;
     RECT  2.16 27.405 88.56 27.675 ;
     RECT  2.16 27.945 88.56 28.215 ;
     RECT  2.16 28.485 88.56 28.755 ;
     RECT  2.16 29.025 88.56 29.295 ;
     RECT  2.16 29.565 88.56 29.835 ;
     RECT  2.16 30.105 88.56 30.375 ;
     RECT  2.16 30.645 88.56 30.915 ;
     RECT  2.16 31.185 88.56 31.455 ;
     RECT  2.16 31.725 88.56 31.995 ;
     RECT  2.16 32.265 88.56 32.535 ;
     RECT  2.16 32.805 88.56 33.075 ;
     RECT  2.16 33.345 88.56 33.615 ;
     RECT  2.16 33.885 88.56 34.155 ;
     RECT  2.16 34.425 88.56 34.695 ;
     RECT  2.16 34.965 88.56 35.235 ;
     RECT  2.16 35.505 88.56 35.775 ;
     RECT  2.16 36.045 88.56 36.315 ;
     RECT  2.16 36.585 88.56 36.855 ;
     RECT  2.16 37.125 88.56 37.395 ;
     RECT  2.16 37.665 88.56 37.935 ;
     RECT  2.16 38.205 88.56 38.475 ;
     RECT  2.16 38.745 88.56 39.015 ;
     RECT  2.16 39.285 88.56 39.555 ;
     RECT  2.16 39.825 88.56 40.095 ;
     RECT  2.16 40.365 88.56 40.635 ;
     RECT  2.16 40.905 88.56 41.175 ;
     RECT  2.16 41.445 88.56 41.715 ;
     RECT  2.16 41.985 88.56 42.255 ;
     RECT  2.16 42.525 88.56 42.795 ;
     RECT  2.16 43.065 88.56 43.335 ;
     RECT  2.16 43.605 88.56 43.875 ;
     RECT  2.16 44.145 88.56 44.415 ;
     RECT  2.16 44.685 88.56 44.955 ;
     RECT  2.16 45.225 88.56 45.495 ;
     RECT  2.16 45.765 88.56 46.035 ;
     RECT  2.16 46.305 88.56 46.575 ;
     RECT  2.16 46.845 88.56 47.115 ;
     RECT  2.16 47.385 88.56 47.655 ;
     RECT  2.16 47.925 88.56 48.195 ;
     RECT  2.16 48.465 88.56 48.735 ;
     RECT  2.16 49.005 88.56 49.275 ;
     RECT  2.16 49.545 88.56 49.815 ;
     RECT  2.16 50.085 88.56 50.355 ;
     RECT  2.16 50.625 88.56 50.895 ;
     RECT  2.16 51.165 88.56 51.435 ;
     RECT  2.16 51.705 88.56 51.975 ;
     RECT  2.16 52.245 88.56 52.515 ;
     RECT  2.16 52.785 88.56 53.055 ;
     RECT  2.16 53.325 88.56 53.595 ;
     RECT  2.16 53.865 88.56 54.135 ;
     RECT  2.16 54.405 88.56 54.675 ;
     RECT  2.16 54.945 88.56 55.215 ;
     RECT  2.16 55.485 88.56 55.755 ;
     RECT  2.16 56.025 88.56 56.295 ;
     RECT  2.16 56.565 88.56 56.835 ;
     RECT  2.16 57.105 88.56 57.375 ;
     RECT  2.16 57.645 88.56 57.915 ;
     RECT  2.16 58.185 88.56 58.455 ;
     RECT  2.16 58.725 88.56 58.995 ;
     RECT  2.16 59.265 88.56 59.535 ;
     RECT  2.16 59.805 88.56 60.075 ;
     RECT  2.16 60.345 88.56 60.615 ;
     RECT  2.16 60.885 88.56 61.155 ;
     RECT  2.16 61.425 88.56 61.695 ;
     RECT  2.16 61.965 88.56 62.235 ;
     RECT  2.16 62.505 88.56 62.775 ;
     RECT  2.16 63.045 88.56 63.315 ;
     RECT  2.16 63.585 88.56 63.855 ;
     RECT  2.16 64.125 88.56 64.395 ;
     RECT  2.16 64.665 88.56 64.935 ;
     RECT  2.16 65.205 88.56 65.475 ;
     RECT  2.16 65.745 88.56 66.015 ;
     RECT  2.16 66.285 88.56 66.555 ;
     RECT  2.16 66.825 88.56 67.095 ;
     RECT  2.16 67.365 88.56 67.635 ;
     RECT  2.16 67.905 88.56 68.175 ;
     RECT  2.16 68.445 88.56 68.715 ;
     RECT  2.16 68.985 88.56 69.255 ;
     RECT  2.16 69.525 88.56 69.795 ;
     RECT  2.16 70.065 88.56 70.335 ;
     RECT  2.16 70.605 88.56 70.875 ;
     RECT  2.16 71.145 88.56 71.415 ;
     RECT  2.16 71.685 88.56 71.955 ;
     RECT  2.16 72.225 88.56 72.495 ;
     RECT  2.16 72.765 88.56 73.035 ;
     RECT  2.16 73.305 88.56 73.575 ;
     RECT  2.16 73.845 88.56 74.115 ;
     RECT  2.16 74.385 88.56 74.655 ;
     RECT  2.16 74.925 88.56 75.195 ;
     RECT  2.16 75.465 88.56 75.735 ;
     RECT  2.16 76.005 88.56 76.275 ;
     RECT  2.16 76.545 88.56 76.815 ;
     RECT  2.16 77.085 88.56 77.355 ;
     RECT  2.16 77.625 88.56 77.895 ;
     RECT  2.16 78.165 88.56 78.435 ;
     RECT  2.16 78.705 88.56 78.975 ;
     RECT  2.16 79.245 88.56 79.515 ;
     RECT  2.16 79.785 88.56 80.055 ;
     RECT  2.16 80.325 88.56 80.595 ;
     RECT  2.16 80.865 88.56 81.135 ;
     RECT  2.16 81.405 88.56 81.675 ;
     RECT  2.16 81.945 88.56 82.215 ;
     RECT  2.16 82.485 88.56 82.755 ;
     RECT  2.16 83.025 88.56 83.295 ;
     RECT  2.16 83.565 88.56 83.835 ;
     RECT  2.16 84.105 88.56 84.375 ;
     RECT  2.16 84.645 88.56 84.915 ;
     RECT  2.16 85.185 88.56 85.455 ;
     RECT  2.16 85.725 88.56 85.995 ;
     RECT  2.16 86.265 88.56 86.535 ;
     RECT  2.16 86.805 88.56 87.075 ;
     RECT  2.16 87.345 88.56 87.615 ;
     RECT  2.16 87.885 88.56 88.155 ;
     RECT  2.16 88.425 88.56 88.695 ;
     RECT  2.16 88.965 88.56 89.235 ;
     RECT  2.16 89.505 88.56 89.775 ;
     RECT  2.16 90.045 88.56 90.315 ;
     RECT  2.16 90.585 88.56 90.855 ;
     RECT  2.16 91.125 88.56 91.395 ;
     RECT  2.16 91.665 88.56 91.935 ;
     RECT  2.16 92.205 88.56 92.475 ;
     RECT  2.16 92.745 88.56 93.015 ;
     RECT  2.16 93.285 88.56 93.555 ;
     RECT  2.16 93.825 88.56 94.095 ;
     RECT  2.16 94.365 88.56 94.635 ;
     RECT  2.16 94.905 88.56 95.175 ;
     RECT  2.16 95.445 88.56 95.715 ;
     RECT  2.16 95.985 88.56 96.255 ;
     RECT  2.16 96.525 88.56 96.795 ;
     RECT  2.16 97.065 88.56 97.2 ;
    LAYER RVTP ;
     RECT  2.16 2.295 88.56 2.565 ;
     RECT  2.16 2.835 88.56 3.105 ;
     RECT  2.16 3.375 88.56 3.645 ;
     RECT  2.16 3.915 88.56 4.185 ;
     RECT  2.16 4.455 88.56 4.725 ;
     RECT  2.16 4.995 88.56 5.265 ;
     RECT  2.16 5.535 88.56 5.805 ;
     RECT  2.16 6.075 88.56 6.345 ;
     RECT  2.16 6.615 88.56 6.885 ;
     RECT  2.16 7.155 88.56 7.425 ;
     RECT  2.16 7.695 88.56 7.965 ;
     RECT  2.16 8.235 88.56 8.505 ;
     RECT  2.16 8.775 88.56 9.045 ;
     RECT  2.16 9.315 88.56 9.585 ;
     RECT  2.16 9.855 88.56 10.125 ;
     RECT  2.16 10.395 88.56 10.665 ;
     RECT  2.16 10.935 88.56 11.205 ;
     RECT  2.16 11.475 88.56 11.745 ;
     RECT  2.16 12.015 88.56 12.285 ;
     RECT  2.16 12.555 88.56 12.825 ;
     RECT  2.16 13.095 88.56 13.365 ;
     RECT  2.16 13.635 88.56 13.905 ;
     RECT  2.16 14.175 88.56 14.445 ;
     RECT  2.16 14.715 88.56 14.985 ;
     RECT  2.16 15.255 88.56 15.525 ;
     RECT  2.16 15.795 88.56 16.065 ;
     RECT  2.16 16.335 88.56 16.605 ;
     RECT  2.16 16.875 88.56 17.145 ;
     RECT  2.16 17.415 88.56 17.685 ;
     RECT  2.16 17.955 88.56 18.225 ;
     RECT  2.16 18.495 88.56 18.765 ;
     RECT  2.16 19.035 88.56 19.305 ;
     RECT  2.16 19.575 88.56 19.845 ;
     RECT  2.16 20.115 88.56 20.385 ;
     RECT  2.16 20.655 88.56 20.925 ;
     RECT  2.16 21.195 88.56 21.465 ;
     RECT  2.16 21.735 88.56 22.005 ;
     RECT  2.16 22.275 88.56 22.545 ;
     RECT  2.16 22.815 88.56 23.085 ;
     RECT  2.16 23.355 88.56 23.625 ;
     RECT  2.16 23.895 88.56 24.165 ;
     RECT  2.16 24.435 88.56 24.705 ;
     RECT  2.16 24.975 88.56 25.245 ;
     RECT  2.16 25.515 88.56 25.785 ;
     RECT  2.16 26.055 88.56 26.325 ;
     RECT  2.16 26.595 88.56 26.865 ;
     RECT  2.16 27.135 88.56 27.405 ;
     RECT  2.16 27.675 88.56 27.945 ;
     RECT  2.16 28.215 88.56 28.485 ;
     RECT  2.16 28.755 88.56 29.025 ;
     RECT  2.16 29.295 88.56 29.565 ;
     RECT  2.16 29.835 88.56 30.105 ;
     RECT  2.16 30.375 88.56 30.645 ;
     RECT  2.16 30.915 88.56 31.185 ;
     RECT  2.16 31.455 88.56 31.725 ;
     RECT  2.16 31.995 88.56 32.265 ;
     RECT  2.16 32.535 88.56 32.805 ;
     RECT  2.16 33.075 88.56 33.345 ;
     RECT  2.16 33.615 88.56 33.885 ;
     RECT  2.16 34.155 88.56 34.425 ;
     RECT  2.16 34.695 88.56 34.965 ;
     RECT  2.16 35.235 88.56 35.505 ;
     RECT  2.16 35.775 88.56 36.045 ;
     RECT  2.16 36.315 88.56 36.585 ;
     RECT  2.16 36.855 88.56 37.125 ;
     RECT  2.16 37.395 88.56 37.665 ;
     RECT  2.16 37.935 88.56 38.205 ;
     RECT  2.16 38.475 88.56 38.745 ;
     RECT  2.16 39.015 88.56 39.285 ;
     RECT  2.16 39.555 88.56 39.825 ;
     RECT  2.16 40.095 88.56 40.365 ;
     RECT  2.16 40.635 88.56 40.905 ;
     RECT  2.16 41.175 88.56 41.445 ;
     RECT  2.16 41.715 88.56 41.985 ;
     RECT  2.16 42.255 88.56 42.525 ;
     RECT  2.16 42.795 88.56 43.065 ;
     RECT  2.16 43.335 88.56 43.605 ;
     RECT  2.16 43.875 88.56 44.145 ;
     RECT  2.16 44.415 88.56 44.685 ;
     RECT  2.16 44.955 88.56 45.225 ;
     RECT  2.16 45.495 88.56 45.765 ;
     RECT  2.16 46.035 88.56 46.305 ;
     RECT  2.16 46.575 88.56 46.845 ;
     RECT  2.16 47.115 88.56 47.385 ;
     RECT  2.16 47.655 88.56 47.925 ;
     RECT  2.16 48.195 88.56 48.465 ;
     RECT  2.16 48.735 88.56 49.005 ;
     RECT  2.16 49.275 88.56 49.545 ;
     RECT  2.16 49.815 88.56 50.085 ;
     RECT  2.16 50.355 88.56 50.625 ;
     RECT  2.16 50.895 88.56 51.165 ;
     RECT  2.16 51.435 88.56 51.705 ;
     RECT  2.16 51.975 88.56 52.245 ;
     RECT  2.16 52.515 88.56 52.785 ;
     RECT  2.16 53.055 88.56 53.325 ;
     RECT  2.16 53.595 88.56 53.865 ;
     RECT  2.16 54.135 88.56 54.405 ;
     RECT  2.16 54.675 88.56 54.945 ;
     RECT  2.16 55.215 88.56 55.485 ;
     RECT  2.16 55.755 88.56 56.025 ;
     RECT  2.16 56.295 88.56 56.565 ;
     RECT  2.16 56.835 88.56 57.105 ;
     RECT  2.16 57.375 88.56 57.645 ;
     RECT  2.16 57.915 88.56 58.185 ;
     RECT  2.16 58.455 88.56 58.725 ;
     RECT  2.16 58.995 88.56 59.265 ;
     RECT  2.16 59.535 88.56 59.805 ;
     RECT  2.16 60.075 88.56 60.345 ;
     RECT  2.16 60.615 88.56 60.885 ;
     RECT  2.16 61.155 88.56 61.425 ;
     RECT  2.16 61.695 88.56 61.965 ;
     RECT  2.16 62.235 88.56 62.505 ;
     RECT  2.16 62.775 88.56 63.045 ;
     RECT  2.16 63.315 88.56 63.585 ;
     RECT  2.16 63.855 88.56 64.125 ;
     RECT  2.16 64.395 88.56 64.665 ;
     RECT  2.16 64.935 88.56 65.205 ;
     RECT  2.16 65.475 88.56 65.745 ;
     RECT  2.16 66.015 88.56 66.285 ;
     RECT  2.16 66.555 88.56 66.825 ;
     RECT  2.16 67.095 88.56 67.365 ;
     RECT  2.16 67.635 88.56 67.905 ;
     RECT  2.16 68.175 88.56 68.445 ;
     RECT  2.16 68.715 88.56 68.985 ;
     RECT  2.16 69.255 88.56 69.525 ;
     RECT  2.16 69.795 88.56 70.065 ;
     RECT  2.16 70.335 88.56 70.605 ;
     RECT  2.16 70.875 88.56 71.145 ;
     RECT  2.16 71.415 88.56 71.685 ;
     RECT  2.16 71.955 88.56 72.225 ;
     RECT  2.16 72.495 88.56 72.765 ;
     RECT  2.16 73.035 88.56 73.305 ;
     RECT  2.16 73.575 88.56 73.845 ;
     RECT  2.16 74.115 88.56 74.385 ;
     RECT  2.16 74.655 88.56 74.925 ;
     RECT  2.16 75.195 88.56 75.465 ;
     RECT  2.16 75.735 88.56 76.005 ;
     RECT  2.16 76.275 88.56 76.545 ;
     RECT  2.16 76.815 88.56 77.085 ;
     RECT  2.16 77.355 88.56 77.625 ;
     RECT  2.16 77.895 88.56 78.165 ;
     RECT  2.16 78.435 88.56 78.705 ;
     RECT  2.16 78.975 88.56 79.245 ;
     RECT  2.16 79.515 88.56 79.785 ;
     RECT  2.16 80.055 88.56 80.325 ;
     RECT  2.16 80.595 88.56 80.865 ;
     RECT  2.16 81.135 88.56 81.405 ;
     RECT  2.16 81.675 88.56 81.945 ;
     RECT  2.16 82.215 88.56 82.485 ;
     RECT  2.16 82.755 88.56 83.025 ;
     RECT  2.16 83.295 88.56 83.565 ;
     RECT  2.16 83.835 88.56 84.105 ;
     RECT  2.16 84.375 88.56 84.645 ;
     RECT  2.16 84.915 88.56 85.185 ;
     RECT  2.16 85.455 88.56 85.725 ;
     RECT  2.16 85.995 88.56 86.265 ;
     RECT  2.16 86.535 88.56 86.805 ;
     RECT  2.16 87.075 88.56 87.345 ;
     RECT  2.16 87.615 88.56 87.885 ;
     RECT  2.16 88.155 88.56 88.425 ;
     RECT  2.16 88.695 88.56 88.965 ;
     RECT  2.16 89.235 88.56 89.505 ;
     RECT  2.16 89.775 88.56 90.045 ;
     RECT  2.16 90.315 88.56 90.585 ;
     RECT  2.16 90.855 88.56 91.125 ;
     RECT  2.16 91.395 88.56 91.665 ;
     RECT  2.16 91.935 88.56 92.205 ;
     RECT  2.16 92.475 88.56 92.745 ;
     RECT  2.16 93.015 88.56 93.285 ;
     RECT  2.16 93.555 88.56 93.825 ;
     RECT  2.16 94.095 88.56 94.365 ;
     RECT  2.16 94.635 88.56 94.905 ;
     RECT  2.16 95.175 88.56 95.445 ;
     RECT  2.16 95.715 88.56 95.985 ;
     RECT  2.16 96.255 88.56 96.525 ;
     RECT  2.16 96.795 88.56 97.065 ;
    LAYER M1 ;
     RECT  2.16 2.151 88.56 97.209 ;
    LAYER M2 ;
     RECT  5.863 98.586 6.251 98.604 ;
     RECT  2.16 2.151 15.007 97.209 ;
     RECT  15.007 2.106 16.583 97.209 ;
     RECT  16.583 2.151 18.391 97.209 ;
     RECT  18.391 2.106 18.815 97.209 ;
     RECT  18.815 2.151 32.539 97.209 ;
     RECT  32.539 2.106 33.575 97.209 ;
     RECT  33.575 2.151 88.56 97.209 ;
    LAYER M3 ;
     RECT  7.776 0.091 7.794 0.139 ;
     RECT  14.4 0.091 14.418 0.139 ;
     RECT  7.776 0.139 8.37 0.187 ;
     RECT  7.776 0.187 8.442 0.365 ;
     RECT  7.776 0.365 7.794 0.523 ;
     RECT  14.4 0.139 14.706 0.523 ;
     RECT  6.12 0.571 6.39 1.675 ;
     RECT  6.12 1.675 6.93 1.723 ;
     RECT  7.668 0.523 7.794 1.723 ;
     RECT  13.752 0.523 14.706 1.723 ;
     RECT  17.136 1.147 17.154 1.723 ;
     RECT  19.404 0.091 19.422 1.723 ;
     RECT  20.736 0.523 20.754 1.723 ;
     RECT  4.824 1.723 4.842 2.191 ;
     RECT  6.012 1.723 12.402 2.191 ;
     RECT  13.176 1.723 19.854 2.191 ;
     RECT  20.736 1.723 21.078 2.191 ;
     RECT  33.552 2.101 33.57 2.227 ;
     RECT  34.815 2.143 34.905 2.227 ;
     RECT  34.488 2.227 34.905 2.251 ;
     RECT  35.712 2.191 35.73 2.251 ;
     RECT  78.015 2.143 78.105 2.293 ;
     RECT  24.015 2.143 24.105 2.299 ;
     RECT  42.3 2.227 42.318 2.299 ;
     RECT  45.615 2.143 45.705 2.299 ;
     RECT  51.015 2.143 51.105 2.299 ;
     RECT  67.215 2.143 67.305 2.299 ;
     RECT  78.015 2.293 78.426 2.299 ;
     RECT  28.404 2.191 28.422 2.335 ;
     RECT  40.215 2.143 40.305 2.335 ;
     RECT  43.92 2.299 43.938 2.335 ;
     RECT  45.036 2.299 45.705 2.335 ;
     RECT  48.24 2.299 48.33 2.335 ;
     RECT  72.615 2.143 72.705 2.335 ;
     RECT  80.352 2.299 80.37 2.335 ;
     RECT  4.032 0.571 4.05 2.371 ;
     RECT  34.488 2.251 35.73 2.371 ;
     RECT  39.816 2.335 40.305 2.371 ;
     RECT  41.184 2.335 41.202 2.371 ;
     RECT  42.264 2.299 42.318 2.371 ;
     RECT  43.776 2.335 43.938 2.371 ;
     RECT  45.036 2.335 46.314 2.371 ;
     RECT  47.988 2.335 48.33 2.371 ;
     RECT  51.015 2.299 51.174 2.371 ;
     RECT  69.048 2.335 69.066 2.371 ;
     RECT  70.488 2.299 70.794 2.371 ;
     RECT  77.652 2.299 79.11 2.371 ;
     RECT  80.352 2.335 80.874 2.371 ;
     RECT  2.415 2.143 2.505 2.413 ;
     RECT  29.415 2.143 29.505 2.413 ;
     RECT  39.384 2.371 40.305 2.413 ;
     RECT  41.184 2.371 42.318 2.413 ;
     RECT  56.415 2.143 56.505 2.413 ;
     RECT  61.815 2.143 61.905 2.413 ;
     RECT  66.708 2.299 67.305 2.413 ;
     RECT  72.072 2.335 72.705 2.413 ;
     RECT  83.415 2.143 83.505 2.413 ;
     RECT  28.008 2.335 28.422 2.461 ;
     RECT  45.036 2.371 48.942 2.461 ;
     RECT  70.488 2.371 70.866 2.461 ;
     RECT  77.652 2.371 80.874 2.461 ;
     RECT  68.364 2.371 69.066 2.491 ;
     RECT  28.008 2.461 28.494 2.497 ;
     RECT  29.415 2.413 29.697 2.497 ;
     RECT  31.536 2.371 31.554 2.497 ;
     RECT  39.384 2.413 42.318 2.497 ;
     RECT  56.415 2.413 56.697 2.497 ;
     RECT  76.68 2.371 76.77 2.497 ;
     RECT  77.508 2.461 80.874 2.497 ;
     RECT  24.015 2.299 24.462 2.533 ;
     RECT  31.464 2.497 31.554 2.533 ;
     RECT  32.544 2.101 32.562 2.533 ;
     RECT  58.032 2.497 58.05 2.533 ;
     RECT  66.708 2.413 67.497 2.533 ;
     RECT  75.816 2.497 75.834 2.533 ;
     RECT  76.572 2.497 80.874 2.533 ;
     RECT  23.94 2.533 24.462 2.569 ;
     RECT  26.856 2.299 26.874 2.569 ;
     RECT  28.008 2.497 29.697 2.569 ;
     RECT  39.384 2.497 42.39 2.569 ;
     RECT  61.815 2.413 62.097 2.569 ;
     RECT  72.072 2.413 72.897 2.569 ;
     RECT  31.464 2.533 32.562 2.605 ;
     RECT  39.384 2.569 42.858 2.605 ;
     RECT  43.776 2.371 43.974 2.605 ;
     RECT  45 2.461 49.122 2.605 ;
     RECT  50.22 2.497 50.238 2.605 ;
     RECT  51.015 2.371 51.354 2.605 ;
     RECT  65.7 2.533 67.497 2.605 ;
     RECT  70.488 2.461 71.298 2.605 ;
     RECT  72.072 2.569 73.17 2.605 ;
     RECT  75.528 2.533 80.874 2.605 ;
     RECT  3.996 2.371 4.05 2.641 ;
     RECT  4.824 2.191 21.762 2.641 ;
     RECT  23.904 2.569 25.182 2.641 ;
     RECT  26.352 2.569 26.91 2.641 ;
     RECT  28.008 2.569 29.79 2.641 ;
     RECT  30.6 2.605 32.562 2.641 ;
     RECT  33.3 2.227 33.57 2.641 ;
     RECT  34.344 2.371 35.73 2.641 ;
     RECT  36.576 2.371 36.594 2.641 ;
     RECT  54.72 2.605 55.134 2.641 ;
     RECT  56.415 2.497 57.294 2.641 ;
     RECT  58.032 2.533 58.086 2.641 ;
     RECT  60.624 2.605 60.642 2.641 ;
     RECT  64.584 2.569 64.602 2.641 ;
     RECT  70.344 2.605 73.17 2.641 ;
     RECT  75.528 2.605 81.234 2.641 ;
     RECT  58.968 2.641 58.986 2.725 ;
     RECT  3.996 2.641 21.798 2.731 ;
     RECT  22.896 2.641 22.914 2.731 ;
     RECT  23.904 2.641 29.79 2.731 ;
     RECT  56.232 2.641 58.086 2.731 ;
     RECT  58.968 2.725 59.202 2.731 ;
     RECT  60.624 2.641 60.894 2.731 ;
     RECT  75.528 2.641 81.378 2.731 ;
     RECT  38.412 2.641 38.43 2.759 ;
     RECT  3.996 2.731 21.942 2.767 ;
     RECT  54.144 2.641 55.134 2.767 ;
     RECT  61.815 2.569 62.73 2.767 ;
     RECT  63.864 2.641 64.602 2.767 ;
     RECT  3.996 2.767 22.158 2.803 ;
     RECT  22.896 2.731 29.79 2.803 ;
     RECT  30.6 2.641 36.738 2.803 ;
     RECT  39.384 2.605 43.974 2.803 ;
     RECT  44.856 2.605 51.354 2.803 ;
     RECT  65.7 2.605 67.59 2.803 ;
     RECT  68.364 2.491 69.282 2.803 ;
     RECT  52.164 2.641 52.182 2.839 ;
     RECT  53.388 2.767 55.134 2.839 ;
     RECT  61.815 2.767 64.926 2.839 ;
     RECT  65.7 2.803 69.282 2.839 ;
     RECT  75.456 2.731 81.378 2.839 ;
     RECT  73.944 2.497 73.962 2.875 ;
     RECT  75.456 2.839 81.45 2.875 ;
     RECT  39.384 2.803 51.354 2.911 ;
     RECT  52.164 2.839 55.134 2.911 ;
     RECT  70.2 2.641 73.17 2.911 ;
     RECT  73.944 2.875 81.702 2.911 ;
     RECT  39.132 2.911 51.354 3.019 ;
     RECT  52.164 2.911 55.242 3.019 ;
     RECT  56.232 2.731 59.202 3.019 ;
     RECT  61.815 2.839 69.282 3.019 ;
     RECT  70.2 2.911 81.702 3.019 ;
     RECT  39.132 3.019 55.242 3.029 ;
     RECT  3.996 2.803 36.738 3.037 ;
     RECT  2.415 2.413 2.697 3.073 ;
     RECT  3.636 3.037 36.738 3.073 ;
     RECT  59.976 2.731 60.894 3.109 ;
     RECT  38.268 2.875 38.286 3.145 ;
     RECT  56.196 3.019 59.202 3.145 ;
     RECT  59.94 3.109 60.894 3.145 ;
     RECT  83.415 2.413 83.697 3.145 ;
     RECT  61.815 3.019 81.702 3.173 ;
     RECT  2.415 3.073 36.738 3.181 ;
     RECT  56.196 3.145 60.894 3.181 ;
     RECT  61.815 3.173 81.522 3.181 ;
     RECT  37.98 3.145 38.286 3.197 ;
     RECT  2.415 3.181 37.026 3.245 ;
     RECT  83.415 3.145 83.826 3.307 ;
     RECT  83.232 3.307 83.826 3.343 ;
     RECT  82.656 3.343 83.826 3.415 ;
     RECT  56.124 3.181 81.522 3.649 ;
     RECT  39.132 3.029 55.134 3.677 ;
     RECT  2.415 3.245 36.63 3.685 ;
     RECT  56.016 3.649 81.522 3.685 ;
     RECT  38.088 3.197 38.286 3.721 ;
     RECT  2.34 3.685 36.63 3.725 ;
     RECT  55.872 3.685 81.522 3.725 ;
     RECT  38.088 3.721 38.322 3.883 ;
     RECT  39.132 3.677 41.994 3.883 ;
     RECT  55.908 3.725 81.522 3.955 ;
     RECT  82.26 3.415 83.826 3.955 ;
     RECT  86.148 3.181 86.166 3.955 ;
     RECT  55.908 3.955 84.366 4.081 ;
     RECT  85.176 3.955 85.194 4.081 ;
     RECT  32.652 3.725 36.63 4.261 ;
     RECT  86.148 3.955 86.274 4.261 ;
     RECT  87.12 4.081 87.138 4.261 ;
     RECT  2.34 3.725 31.914 4.459 ;
     RECT  32.652 4.261 36.918 4.459 ;
     RECT  86.148 4.261 87.138 4.495 ;
     RECT  42.84 3.677 55.134 4.531 ;
     RECT  55.908 4.081 85.194 4.531 ;
     RECT  42.84 4.531 85.194 4.603 ;
     RECT  86.076 4.495 87.138 4.603 ;
     RECT  38.088 3.883 41.994 4.621 ;
     RECT  42.84 4.603 87.138 4.621 ;
     RECT  38.088 4.621 87.138 4.729 ;
     RECT  2.34 4.459 36.918 4.765 ;
     RECT  2.304 4.765 36.918 4.801 ;
     RECT  38.088 4.729 87.21 4.801 ;
     RECT  38.088 4.801 87.354 4.919 ;
     RECT  2.304 4.801 36.99 5.063 ;
     RECT  2.415 5.063 36.99 5.071 ;
     RECT  38.088 4.919 51.786 5.071 ;
     RECT  52.524 4.919 87.354 5.071 ;
     RECT  52.524 5.071 87.498 5.161 ;
     RECT  52.524 5.161 87.57 5.189 ;
     RECT  52.524 5.189 57.042 5.297 ;
     RECT  2.415 5.071 51.786 6.007 ;
     RECT  52.524 5.297 56.97 6.007 ;
     RECT  2.415 6.007 56.97 6.115 ;
     RECT  2.415 6.115 57.078 6.151 ;
     RECT  57.888 5.189 87.57 6.151 ;
     RECT  2.415 6.151 87.606 6.691 ;
     RECT  2.415 6.691 87.642 6.809 ;
     RECT  52.524 6.809 87.642 6.853 ;
     RECT  52.524 6.853 87.75 7.231 ;
     RECT  2.415 6.809 46.206 7.591 ;
     RECT  47.016 6.809 51.786 7.591 ;
     RECT  52.524 7.231 87.786 7.763 ;
     RECT  2.415 7.591 51.786 8.473 ;
     RECT  52.524 7.763 57.474 8.473 ;
     RECT  58.212 7.763 87.786 8.501 ;
     RECT  2.415 8.473 57.474 8.509 ;
     RECT  2.304 8.509 57.474 9.085 ;
     RECT  58.212 8.501 87.75 9.085 ;
     RECT  2.304 9.085 87.75 9.247 ;
     RECT  2.304 9.247 87.786 9.661 ;
     RECT  2.304 9.661 87.822 9.959 ;
     RECT  52.596 9.959 87.822 10.049 ;
     RECT  85.428 10.049 87.822 10.201 ;
     RECT  2.304 9.959 51.822 10.253 ;
     RECT  49.824 10.253 51.822 10.705 ;
     RECT  49.824 10.705 51.858 10.741 ;
     RECT  52.596 10.049 84.69 10.741 ;
     RECT  49.824 10.741 84.69 10.831 ;
     RECT  85.428 10.201 87.93 10.831 ;
     RECT  49.824 10.831 87.93 10.895 ;
     RECT  2.304 10.253 48.546 11.011 ;
     RECT  49.824 10.895 52.038 11.011 ;
     RECT  2.304 11.011 52.038 11.129 ;
     RECT  52.884 10.895 87.93 11.129 ;
     RECT  2.304 11.129 51.966 11.201 ;
     RECT  2.304 11.201 51.93 11.273 ;
     RECT  53.028 11.129 87.93 11.543 ;
     RECT  53.208 11.543 87.93 11.741 ;
     RECT  53.28 11.741 87.93 11.911 ;
     RECT  2.304 11.273 51.822 12.253 ;
     RECT  2.304 12.253 51.858 12.289 ;
     RECT  2.232 12.289 51.858 12.487 ;
     RECT  2.232 12.487 52.002 12.551 ;
     RECT  2.304 12.551 52.002 12.631 ;
     RECT  2.304 12.631 52.326 13.019 ;
     RECT  49.824 13.019 52.326 13.051 ;
     RECT  2.304 13.019 48.582 13.055 ;
     RECT  53.28 11.911 88.002 13.055 ;
     RECT  53.28 13.055 57.726 13.063 ;
     RECT  2.304 13.055 48.51 13.091 ;
     RECT  53.136 13.063 57.726 13.091 ;
     RECT  49.824 13.051 52.398 13.199 ;
     RECT  2.304 13.091 48.366 13.441 ;
     RECT  49.86 13.199 52.398 13.441 ;
     RECT  53.136 13.091 57.69 13.441 ;
     RECT  58.572 13.055 88.002 13.441 ;
     RECT  58.572 13.441 88.074 13.595 ;
     RECT  58.572 13.595 87.966 13.865 ;
     RECT  58.716 13.865 87.966 13.901 ;
     RECT  49.86 13.441 57.69 14.215 ;
     RECT  49.536 14.215 57.69 14.369 ;
     RECT  53.136 14.369 57.69 14.377 ;
     RECT  2.232 13.441 48.366 14.491 ;
     RECT  49.536 14.369 52.362 14.491 ;
     RECT  2.232 14.491 52.362 14.525 ;
     RECT  49.032 14.525 52.362 14.549 ;
     RECT  49.032 14.549 52.11 14.639 ;
     RECT  58.752 13.901 87.966 14.719 ;
     RECT  2.232 14.525 47.79 14.747 ;
     RECT  53.136 14.377 57.762 14.779 ;
     RECT  58.752 14.719 88.038 14.779 ;
     RECT  53.136 14.779 88.038 14.819 ;
     RECT  58.428 14.819 88.038 14.909 ;
     RECT  2.304 14.747 47.79 14.945 ;
     RECT  49.428 14.639 52.11 15.179 ;
     RECT  53.136 14.819 57.654 15.331 ;
     RECT  58.788 14.909 87.93 15.521 ;
     RECT  74.952 15.521 87.93 15.719 ;
     RECT  2.304 14.945 47.754 15.871 ;
     RECT  53.028 15.331 57.654 15.871 ;
     RECT  53.028 15.871 57.978 16.025 ;
     RECT  49.428 15.179 51.894 16.027 ;
     RECT  49.032 16.027 51.894 16.069 ;
     RECT  48.96 16.069 51.894 16.105 ;
     RECT  75.204 15.719 87.93 16.367 ;
     RECT  2.304 15.871 47.97 16.411 ;
     RECT  48.744 16.105 51.894 16.411 ;
     RECT  2.304 16.411 51.894 16.501 ;
     RECT  77.292 16.367 87.93 16.529 ;
     RECT  75.204 16.367 76.482 16.637 ;
     RECT  2.304 16.501 51.93 16.673 ;
     RECT  39.6 16.673 51.93 16.681 ;
     RECT  53.028 16.025 57.798 16.681 ;
     RECT  58.788 15.521 74.106 16.681 ;
     RECT  58.788 16.681 74.466 16.877 ;
     RECT  39.6 16.681 57.798 16.943 ;
     RECT  50.976 16.943 57.798 16.951 ;
     RECT  77.364 16.529 87.93 17.339 ;
     RECT  75.204 16.637 76.41 17.347 ;
     RECT  80.388 17.339 87.93 17.375 ;
     RECT  74.844 17.347 76.41 17.467 ;
     RECT  77.364 17.339 79.542 17.467 ;
     RECT  50.976 16.951 57.834 17.491 ;
     RECT  58.788 16.877 74.106 17.491 ;
     RECT  39.6 16.943 50.238 17.609 ;
     RECT  39.96 17.609 50.238 17.761 ;
     RECT  50.976 17.491 74.106 17.761 ;
     RECT  74.844 17.467 79.542 17.761 ;
     RECT  2.304 16.673 38.862 17.879 ;
     RECT  27.972 17.879 38.862 18.121 ;
     RECT  39.96 17.761 79.542 18.121 ;
     RECT  80.424 17.375 87.93 18.121 ;
     RECT  2.304 17.879 27.198 18.149 ;
     RECT  27.972 18.121 38.898 18.535 ;
     RECT  39.96 18.121 87.93 18.535 ;
     RECT  27.972 18.535 87.93 18.797 ;
     RECT  27.972 18.797 87.786 18.995 ;
     RECT  2.304 18.149 27.09 19.075 ;
     RECT  27.972 18.995 48.798 19.075 ;
     RECT  49.608 18.995 87.786 19.103 ;
     RECT  49.608 19.103 87.678 19.229 ;
     RECT  49.608 19.229 79.794 19.265 ;
     RECT  80.676 19.229 87.678 19.337 ;
     RECT  49.608 19.265 67.806 19.643 ;
     RECT  68.58 19.265 79.794 19.679 ;
     RECT  80.712 19.337 87.678 19.841 ;
     RECT  80.712 19.841 87.642 19.913 ;
     RECT  80.712 19.913 87.246 20.039 ;
     RECT  82.44 20.039 87.246 20.075 ;
     RECT  59.148 19.643 67.806 20.119 ;
     RECT  68.58 19.679 79.578 20.119 ;
     RECT  2.304 19.075 48.798 20.152 ;
     RECT  49.608 19.643 58.41 20.152 ;
     RECT  59.148 20.119 79.578 20.183 ;
     RECT  80.712 20.039 81.594 20.191 ;
     RECT  59.58 20.183 79.578 20.345 ;
     RECT  82.44 20.075 86.706 20.381 ;
     RECT  80.496 20.191 81.594 20.425 ;
     RECT  59.58 20.345 79.542 20.453 ;
     RECT  2.304 20.152 58.41 20.461 ;
     RECT  82.44 20.381 86.562 20.489 ;
     RECT  2.304 20.461 58.77 21.091 ;
     RECT  59.58 20.453 79.47 21.091 ;
     RECT  80.424 20.425 81.594 21.127 ;
     RECT  82.44 20.489 83.79 21.127 ;
     RECT  80.424 21.127 83.79 21.235 ;
     RECT  84.528 20.489 86.562 21.235 ;
     RECT  2.304 21.091 79.47 21.271 ;
     RECT  80.424 21.235 86.562 21.271 ;
     RECT  2.304 21.271 86.562 21.659 ;
     RECT  68.544 21.659 86.562 21.775 ;
     RECT  68.544 21.775 86.634 22.235 ;
     RECT  78.015 22.235 86.634 22.351 ;
     RECT  68.544 22.235 77.202 22.549 ;
     RECT  2.304 21.659 67.77 22.621 ;
     RECT  68.508 22.549 77.202 22.621 ;
     RECT  78.015 22.351 87.282 22.739 ;
     RECT  2.304 22.621 77.202 22.981 ;
     RECT  78.015 22.739 86.742 22.981 ;
     RECT  2.304 22.981 86.742 23.009 ;
     RECT  2.304 23.009 54.594 23.045 ;
     RECT  55.404 23.009 86.742 23.855 ;
     RECT  2.304 23.045 50.274 23.863 ;
     RECT  51.015 23.045 54.594 23.863 ;
     RECT  55.404 23.855 63.27 23.963 ;
     RECT  64.08 23.855 86.742 23.963 ;
     RECT  66.24 23.963 86.742 24.061 ;
     RECT  66.24 24.061 87.282 24.089 ;
     RECT  64.08 23.963 65.502 24.125 ;
     RECT  66.24 24.089 66.258 24.131 ;
     RECT  64.296 24.125 65.502 24.161 ;
     RECT  55.404 23.963 63.126 24.169 ;
     RECT  67.068 24.089 87.282 24.173 ;
     RECT  2.304 23.863 54.594 24.205 ;
     RECT  55.368 24.169 63.126 24.205 ;
     RECT  64.296 24.161 65.25 24.233 ;
     RECT  67.068 24.173 87.246 24.359 ;
     RECT  2.304 24.205 63.126 24.503 ;
     RECT  64.296 24.233 65.034 24.503 ;
     RECT  67.068 24.359 86.706 24.665 ;
     RECT  48.312 24.503 63.126 24.737 ;
     RECT  86.616 24.665 86.706 24.773 ;
     RECT  67.068 24.665 70.29 24.871 ;
     RECT  71.424 24.665 85.77 24.899 ;
     RECT  49.104 24.737 63.126 24.907 ;
     RECT  49.104 24.907 63.198 25.051 ;
     RECT  2.304 24.503 47.538 25.079 ;
     RECT  71.424 24.899 85.554 25.079 ;
     RECT  86.688 24.773 86.706 25.079 ;
     RECT  66.96 24.871 70.29 25.169 ;
     RECT  71.424 25.079 85.518 25.169 ;
     RECT  64.296 24.503 64.314 25.213 ;
     RECT  64.08 25.213 64.314 25.285 ;
     RECT  65.628 25.249 65.646 25.285 ;
     RECT  71.424 25.169 85.482 25.313 ;
     RECT  64.08 25.285 64.89 25.321 ;
     RECT  65.628 25.285 66.402 25.321 ;
     RECT  71.424 25.313 85.374 25.411 ;
     RECT  71.172 25.411 85.374 25.439 ;
     RECT  49.104 25.051 63.306 25.483 ;
     RECT  64.08 25.321 66.402 25.483 ;
     RECT  71.172 25.439 84.51 25.555 ;
     RECT  48.312 24.737 48.33 25.709 ;
     RECT  71.1 25.555 84.51 25.709 ;
     RECT  49.104 25.483 66.402 25.781 ;
     RECT  2.304 25.079 8.226 25.861 ;
     RECT  8.964 25.079 47.538 25.861 ;
     RECT  67.215 25.169 70.29 25.861 ;
     RECT  71.1 25.709 84.078 25.861 ;
     RECT  2.304 25.861 47.538 25.979 ;
     RECT  67.215 25.861 84.078 25.979 ;
     RECT  49.104 25.781 63.378 25.987 ;
     RECT  5.94 25.979 47.538 26.015 ;
     RECT  71.064 25.979 84.078 26.087 ;
     RECT  48.852 25.987 63.378 26.093 ;
     RECT  64.224 25.781 66.402 26.095 ;
     RECT  67.215 25.979 70.29 26.095 ;
     RECT  85.356 25.439 85.374 26.257 ;
     RECT  84.888 26.257 85.374 26.401 ;
     RECT  84.888 26.401 85.446 26.477 ;
     RECT  80.496 26.087 84.078 26.491 ;
     RECT  84.888 26.477 85.338 26.491 ;
     RECT  64.224 26.095 70.29 26.635 ;
     RECT  48.852 26.093 63.306 26.671 ;
     RECT  5.94 26.015 47.142 26.761 ;
     RECT  47.916 26.401 47.934 26.761 ;
     RECT  48.708 26.671 63.306 26.761 ;
     RECT  5.904 26.761 47.142 26.779 ;
     RECT  47.916 26.761 63.306 26.779 ;
     RECT  2.304 25.979 5.166 26.797 ;
     RECT  5.904 26.779 63.306 26.797 ;
     RECT  80.496 26.491 85.338 26.861 ;
     RECT  71.064 26.087 79.758 26.905 ;
     RECT  80.496 26.861 84.402 26.905 ;
     RECT  2.304 26.797 63.306 26.941 ;
     RECT  64.116 26.635 70.29 26.941 ;
     RECT  71.064 26.905 84.402 26.941 ;
     RECT  85.32 26.861 85.338 27.481 ;
     RECT  85.32 27.481 85.662 27.595 ;
     RECT  2.304 26.941 84.402 27.599 ;
     RECT  85.32 27.595 85.842 27.715 ;
     RECT  85.176 27.715 85.842 27.751 ;
     RECT  52.884 27.599 84.402 27.841 ;
     RECT  85.176 27.751 86.022 27.841 ;
     RECT  52.884 27.841 86.022 27.941 ;
     RECT  2.304 27.599 52.038 27.977 ;
     RECT  53.244 27.941 86.022 27.985 ;
     RECT  53.244 27.985 86.13 28.255 ;
     RECT  87.048 27.883 87.066 28.255 ;
     RECT  53.244 28.255 87.066 28.291 ;
     RECT  2.415 27.977 52.038 28.409 ;
     RECT  50.868 28.409 52.038 28.957 ;
     RECT  53.244 28.291 87.39 28.985 ;
     RECT  50.868 28.957 52.254 29.101 ;
     RECT  50.868 29.101 52.506 29.191 ;
     RECT  53.244 28.985 63.45 29.191 ;
     RECT  2.415 28.409 50.094 29.489 ;
     RECT  64.188 28.985 87.39 29.525 ;
     RECT  2.415 29.489 24.678 29.549 ;
     RECT  25.488 29.489 50.094 29.605 ;
     RECT  50.868 29.191 63.45 29.605 ;
     RECT  68.976 29.525 87.39 29.659 ;
     RECT  25.488 29.605 63.45 29.707 ;
     RECT  64.188 29.525 67.914 29.707 ;
     RECT  25.488 29.707 67.914 30.065 ;
     RECT  68.976 29.659 87.57 30.145 ;
     RECT  68.976 30.145 87.642 30.181 ;
     RECT  55.836 30.065 67.914 30.209 ;
     RECT  2.415 29.549 24.297 30.271 ;
     RECT  68.976 30.181 87.786 30.299 ;
     RECT  68.976 30.299 87.498 30.307 ;
     RECT  2.415 30.271 24.354 30.343 ;
     RECT  2.415 30.343 24.426 30.379 ;
     RECT  57.78 30.209 67.914 30.415 ;
     RECT  68.652 30.307 87.498 30.415 ;
     RECT  2.415 30.379 24.714 30.451 ;
     RECT  25.488 30.065 55.098 30.451 ;
     RECT  2.415 30.451 55.098 30.883 ;
     RECT  55.836 30.209 57.042 30.883 ;
     RECT  57.78 30.415 87.498 31.189 ;
     RECT  57.78 31.189 87.57 31.261 ;
     RECT  2.415 30.883 57.042 31.339 ;
     RECT  57.78 31.261 87.786 31.339 ;
     RECT  2.415 31.339 87.786 31.805 ;
     RECT  22.68 31.805 87.786 32.341 ;
     RECT  2.415 31.805 21.906 32.575 ;
     RECT  22.68 32.341 88.326 32.575 ;
     RECT  2.415 32.575 88.326 32.729 ;
     RECT  22.824 32.729 88.326 32.801 ;
     RECT  22.824 32.801 88.038 33.035 ;
     RECT  22.824 33.035 87.786 33.143 ;
     RECT  58.068 33.143 87.786 33.305 ;
     RECT  2.415 32.729 22.014 33.511 ;
     RECT  22.824 33.143 57.33 33.511 ;
     RECT  2.415 33.511 57.33 33.611 ;
     RECT  22.968 33.611 57.33 33.925 ;
     RECT  58.068 33.305 69.138 33.925 ;
     RECT  22.968 33.925 69.138 34.117 ;
     RECT  69.912 33.305 87.786 34.117 ;
     RECT  2.415 33.611 22.194 35.203 ;
     RECT  22.968 34.117 87.786 35.203 ;
     RECT  2.415 35.203 87.786 35.741 ;
     RECT  3.672 35.741 87.786 35.851 ;
     RECT  3.672 35.851 87.822 36.149 ;
     RECT  3.672 36.149 76.266 36.931 ;
     RECT  77.04 36.149 87.822 36.931 ;
     RECT  3.672 36.931 87.822 37.561 ;
     RECT  2.415 35.741 2.697 37.705 ;
     RECT  3.6 37.561 87.822 37.859 ;
     RECT  3.6 37.859 19.35 38.137 ;
     RECT  20.232 37.859 87.822 38.165 ;
     RECT  20.232 38.165 38.862 38.399 ;
     RECT  3.528 38.137 19.35 38.435 ;
     RECT  2.415 37.705 2.79 38.551 ;
     RECT  3.528 38.435 17.694 38.551 ;
     RECT  37.116 38.399 38.862 38.669 ;
     RECT  39.672 38.165 87.822 38.717 ;
     RECT  18.576 38.435 19.35 38.779 ;
     RECT  20.232 38.399 36.342 38.779 ;
     RECT  39.672 38.717 87.714 38.975 ;
     RECT  38.664 38.669 38.862 39.181 ;
     RECT  39.672 38.975 86.706 39.181 ;
     RECT  2.415 38.551 17.694 39.289 ;
     RECT  18.576 38.779 36.342 39.289 ;
     RECT  2.415 39.289 36.342 39.325 ;
     RECT  37.116 38.669 37.818 39.325 ;
     RECT  2.415 39.325 37.818 39.515 ;
     RECT  20.412 39.515 37.818 39.559 ;
     RECT  38.664 39.181 86.706 39.559 ;
     RECT  87.516 38.975 87.714 40.219 ;
     RECT  2.415 39.515 19.638 40.369 ;
     RECT  20.412 39.559 86.706 40.369 ;
     RECT  2.415 40.369 86.706 40.441 ;
     RECT  87.48 40.219 87.714 40.441 ;
     RECT  2.415 40.441 87.714 40.469 ;
     RECT  3.456 40.469 87.714 40.559 ;
     RECT  3.492 40.559 87.714 40.603 ;
     RECT  88.488 40.441 88.506 40.603 ;
     RECT  3.492 40.603 88.506 40.829 ;
     RECT  3.492 40.829 21.69 41.135 ;
     RECT  3.492 41.135 21.474 41.171 ;
     RECT  2.415 40.469 2.697 41.371 ;
     RECT  3.492 41.171 17.082 41.371 ;
     RECT  22.572 40.829 88.506 41.405 ;
     RECT  22.572 41.405 35.766 41.513 ;
     RECT  22.716 41.513 35.766 41.639 ;
     RECT  2.415 41.371 17.082 42.061 ;
     RECT  17.82 41.171 21.474 42.061 ;
     RECT  36.612 41.405 88.506 42.151 ;
     RECT  2.415 42.061 21.474 42.187 ;
     RECT  36.18 42.151 88.506 42.215 ;
     RECT  36.18 42.215 86.706 42.323 ;
     RECT  22.716 41.639 35.442 42.421 ;
     RECT  36.18 42.323 36.378 42.421 ;
     RECT  37.188 42.323 86.706 42.593 ;
     RECT  42.48 42.593 86.706 42.863 ;
     RECT  49.356 42.863 86.706 42.961 ;
     RECT  87.516 42.215 88.506 42.961 ;
     RECT  2.415 42.187 21.762 43.025 ;
     RECT  18.432 43.025 21.762 43.105 ;
     RECT  22.716 42.421 36.378 43.105 ;
     RECT  2.415 43.025 17.694 43.169 ;
     RECT  18.432 43.105 36.378 43.243 ;
     RECT  18.432 43.243 36.45 43.331 ;
     RECT  23.184 43.331 36.45 43.411 ;
     RECT  37.188 42.593 41.598 43.411 ;
     RECT  23.184 43.411 41.598 43.483 ;
     RECT  23.184 43.483 41.634 43.609 ;
     RECT  42.48 42.863 48.618 43.609 ;
     RECT  49.356 42.961 88.506 43.609 ;
     RECT  23.184 43.609 88.506 43.799 ;
     RECT  23.184 43.799 41.634 43.835 ;
     RECT  2.415 43.169 8.91 43.915 ;
     RECT  9.684 43.169 17.694 43.915 ;
     RECT  2.415 43.915 17.694 43.951 ;
     RECT  42.48 43.799 88.506 43.979 ;
     RECT  18.432 43.331 22.266 44.149 ;
     RECT  23.184 43.835 41.598 44.149 ;
     RECT  2.376 43.951 17.694 44.221 ;
     RECT  18.432 44.149 41.598 44.221 ;
     RECT  49.428 43.979 88.506 44.339 ;
     RECT  49.428 44.339 73.89 44.609 ;
     RECT  2.376 44.221 41.598 44.645 ;
     RECT  20.016 44.645 41.598 44.681 ;
     RECT  20.016 44.681 26.19 44.753 ;
     RECT  27.108 44.681 41.598 44.789 ;
     RECT  42.48 43.979 48.69 44.789 ;
     RECT  27.324 44.789 41.598 44.875 ;
     RECT  42.48 44.789 47.286 44.875 ;
     RECT  27.324 44.875 47.286 44.915 ;
     RECT  27.324 44.915 46.818 45.329 ;
     RECT  2.376 44.645 19.278 45.391 ;
     RECT  64.656 44.609 73.89 45.463 ;
     RECT  74.664 44.339 88.506 45.463 ;
     RECT  2.376 45.391 19.494 45.491 ;
     RECT  12.06 45.491 19.494 45.499 ;
     RECT  20.232 44.753 26.19 45.499 ;
     RECT  27.324 45.329 46.638 45.535 ;
     RECT  12.06 45.499 26.19 45.571 ;
     RECT  27.252 45.535 46.638 45.571 ;
     RECT  49.428 44.609 63.918 45.571 ;
     RECT  64.656 45.463 88.506 45.571 ;
     RECT  27.144 45.571 46.638 45.725 ;
     RECT  48.06 44.789 48.69 45.769 ;
     RECT  47.952 45.769 48.69 45.805 ;
     RECT  49.428 45.571 88.506 45.805 ;
     RECT  47.952 45.805 88.506 45.931 ;
     RECT  2.376 45.491 11.286 45.959 ;
     RECT  12.06 45.571 26.37 46.067 ;
     RECT  2.415 45.959 11.286 46.253 ;
     RECT  8.856 46.253 11.286 46.381 ;
     RECT  12.06 46.067 12.222 46.381 ;
     RECT  12.96 46.067 26.37 46.381 ;
     RECT  27.216 45.725 46.638 46.381 ;
     RECT  12.96 46.381 26.442 46.651 ;
     RECT  27.216 46.381 47.034 46.651 ;
     RECT  8.856 46.381 12.222 46.921 ;
     RECT  12.96 46.651 47.034 46.921 ;
     RECT  8.856 46.921 47.034 47.047 ;
     RECT  47.88 45.931 88.506 47.047 ;
     RECT  2.415 46.253 8.097 47.155 ;
     RECT  8.856 47.047 88.506 47.155 ;
     RECT  2.412 47.155 88.506 47.357 ;
     RECT  2.415 47.357 88.506 47.885 ;
     RECT  17.388 47.885 88.506 48.191 ;
     RECT  2.415 47.885 16.65 48.227 ;
     RECT  2.415 48.227 9.198 48.271 ;
     RECT  52.524 48.191 88.506 48.425 ;
     RECT  10.044 48.227 16.65 48.661 ;
     RECT  17.388 48.191 51.786 48.661 ;
     RECT  10.044 48.661 51.786 48.929 ;
     RECT  20.556 48.929 51.786 49.171 ;
     RECT  52.74 48.425 88.506 49.171 ;
     RECT  2.376 48.271 9.198 49.351 ;
     RECT  10.044 48.929 19.818 49.351 ;
     RECT  20.556 49.171 88.506 49.739 ;
     RECT  2.376 49.351 19.818 49.855 ;
     RECT  20.556 49.739 68.058 49.855 ;
     RECT  2.376 49.855 68.058 50.045 ;
     RECT  2.415 50.045 68.058 50.153 ;
     RECT  45.468 50.153 68.058 50.549 ;
     RECT  56.304 50.549 68.058 50.585 ;
     RECT  7.632 50.153 44.55 50.657 ;
     RECT  57.78 50.585 68.058 50.701 ;
     RECT  68.796 49.739 88.506 50.701 ;
     RECT  57.78 50.701 88.506 50.729 ;
     RECT  57.78 50.729 75.114 50.855 ;
     RECT  44.388 50.657 44.55 51.005 ;
     RECT  2.415 50.153 6.894 51.061 ;
     RECT  7.632 50.657 43.254 51.061 ;
     RECT  44.388 51.005 44.442 51.089 ;
     RECT  66.636 50.855 75.114 51.089 ;
     RECT  44.388 51.089 44.406 51.125 ;
     RECT  45.468 50.549 55.458 51.125 ;
     RECT  75.888 50.729 88.506 51.125 ;
     RECT  2.415 51.061 43.254 51.293 ;
     RECT  56.304 50.585 57.006 51.331 ;
     RECT  33.912 51.293 43.254 51.475 ;
     RECT  33.912 51.475 43.398 51.511 ;
     RECT  53.208 51.125 55.458 51.511 ;
     RECT  56.232 51.331 57.006 51.511 ;
     RECT  57.78 50.855 65.862 51.511 ;
     RECT  53.208 51.511 55.494 51.601 ;
     RECT  56.232 51.511 65.862 51.601 ;
     RECT  53.208 51.601 65.862 51.637 ;
     RECT  66.636 51.089 75.078 51.637 ;
     RECT  33.912 51.511 43.938 51.871 ;
     RECT  75.996 51.125 88.506 51.871 ;
     RECT  33.912 51.871 44.154 51.899 ;
     RECT  34.02 51.899 44.154 51.907 ;
     RECT  34.02 51.907 44.37 51.943 ;
     RECT  45.468 51.125 52.434 51.943 ;
     RECT  53.208 51.637 75.078 51.943 ;
     RECT  34.02 51.943 52.434 51.979 ;
     RECT  53.172 51.943 75.078 51.979 ;
     RECT  34.02 51.979 75.078 52.051 ;
     RECT  75.816 51.871 88.506 52.051 ;
     RECT  2.415 51.293 33.174 52.321 ;
     RECT  2.376 52.321 33.174 52.825 ;
     RECT  2.34 52.825 33.174 52.861 ;
     RECT  34.02 52.051 88.506 52.861 ;
     RECT  2.34 52.861 88.506 52.979 ;
     RECT  2.34 52.979 33.174 53.015 ;
     RECT  2.34 53.015 21.438 53.021 ;
     RECT  22.248 53.015 33.174 53.021 ;
     RECT  33.948 52.979 88.506 53.021 ;
     RECT  22.248 53.021 32.418 53.159 ;
     RECT  2.376 53.021 21.438 53.249 ;
     RECT  2.415 53.249 21.438 53.905 ;
     RECT  22.248 53.159 26.946 53.905 ;
     RECT  28.008 53.159 32.418 53.905 ;
     RECT  2.415 53.905 32.418 54.031 ;
     RECT  33.156 53.021 33.174 54.031 ;
     RECT  34.2 53.021 88.506 54.437 ;
     RECT  2.415 54.031 33.174 54.707 ;
     RECT  2.415 54.707 27.126 54.955 ;
     RECT  34.2 54.437 88.254 54.977 ;
     RECT  27.936 54.707 33.174 55.049 ;
     RECT  2.34 54.955 27.126 55.175 ;
     RECT  34.2 54.977 59.166 55.409 ;
     RECT  34.2 55.409 59.022 55.417 ;
     RECT  33.984 55.417 59.022 55.445 ;
     RECT  2.415 55.175 27.126 55.489 ;
     RECT  27.936 55.049 32.418 55.489 ;
     RECT  33.984 55.445 58.986 55.517 ;
     RECT  33.156 55.049 33.174 55.525 ;
     RECT  33.984 55.517 47.142 55.525 ;
     RECT  2.415 55.489 32.418 55.831 ;
     RECT  33.156 55.525 47.142 55.831 ;
     RECT  59.904 54.977 88.254 55.859 ;
     RECT  47.88 55.517 58.986 56.191 ;
     RECT  59.904 55.859 66.006 56.191 ;
     RECT  2.415 55.831 47.142 56.533 ;
     RECT  47.88 56.191 66.006 56.533 ;
     RECT  2.415 56.533 66.006 56.587 ;
     RECT  2.376 56.587 66.006 56.731 ;
     RECT  66.78 55.859 88.254 56.731 ;
     RECT  2.376 56.731 88.254 57.371 ;
     RECT  81.54 57.371 88.254 57.839 ;
     RECT  2.376 57.371 80.55 58.019 ;
     RECT  2.376 58.019 77.202 58.109 ;
     RECT  77.976 58.019 80.55 58.117 ;
     RECT  81.54 57.839 88.074 58.117 ;
     RECT  2.415 58.109 68.526 58.379 ;
     RECT  2.415 58.379 18.99 58.559 ;
     RECT  69.48 58.109 77.202 58.765 ;
     RECT  77.976 58.117 88.074 58.765 ;
     RECT  69.48 58.765 88.074 58.919 ;
     RECT  19.728 58.379 68.526 58.963 ;
     RECT  69.48 58.919 77.238 58.963 ;
     RECT  19.728 58.963 77.238 58.973 ;
     RECT  11.484 58.559 18.99 59.189 ;
     RECT  19.728 58.973 77.202 59.225 ;
     RECT  19.728 59.225 63.054 59.297 ;
     RECT  63.828 59.225 77.202 59.333 ;
     RECT  2.415 58.559 10.602 59.341 ;
     RECT  11.484 59.189 18.897 59.341 ;
     RECT  19.728 59.297 32.49 59.369 ;
     RECT  2.415 59.341 18.897 59.611 ;
     RECT  33.408 59.297 63.054 59.729 ;
     RECT  63.828 59.333 70.47 59.765 ;
     RECT  2.376 59.611 18.897 59.789 ;
     RECT  71.208 59.333 77.202 59.801 ;
     RECT  69.084 59.765 70.47 59.837 ;
     RECT  63.828 59.765 68.346 59.873 ;
     RECT  19.728 59.369 32.382 59.999 ;
     RECT  46.656 59.729 63.054 60.043 ;
     RECT  63.828 59.873 66.15 60.043 ;
     RECT  77.976 58.919 88.074 60.151 ;
     RECT  77.94 60.151 88.074 60.241 ;
     RECT  69.084 59.837 69.354 60.269 ;
     RECT  76.32 59.801 77.202 60.349 ;
     RECT  77.94 60.241 88.11 60.349 ;
     RECT  76.32 60.349 88.11 60.377 ;
     RECT  70.236 59.837 70.47 60.379 ;
     RECT  71.208 59.801 75.546 60.379 ;
     RECT  69.084 60.269 69.102 60.413 ;
     RECT  70.236 60.379 75.546 60.413 ;
     RECT  70.38 60.413 75.546 60.419 ;
     RECT  2.415 59.789 18.897 60.427 ;
     RECT  19.728 59.999 32.346 60.427 ;
     RECT  67.068 59.873 68.346 60.523 ;
     RECT  71.208 60.419 75.546 60.547 ;
     RECT  76.32 60.377 86.49 60.547 ;
     RECT  71.208 60.547 86.49 60.575 ;
     RECT  67.068 60.523 68.994 60.653 ;
     RECT  33.408 59.729 45.897 60.655 ;
     RECT  46.656 60.043 66.15 60.691 ;
     RECT  67.068 60.653 68.67 60.691 ;
     RECT  71.244 60.575 86.49 60.719 ;
     RECT  33.228 60.655 45.897 60.763 ;
     RECT  46.656 60.691 68.67 60.763 ;
     RECT  71.244 60.719 75.69 60.809 ;
     RECT  76.5 60.719 86.49 60.917 ;
     RECT  2.415 60.427 32.346 60.925 ;
     RECT  33.228 60.763 68.67 60.925 ;
     RECT  2.415 60.925 68.67 60.953 ;
     RECT  2.415 60.953 18.897 60.961 ;
     RECT  2.376 60.961 18.897 61.079 ;
     RECT  87.228 60.377 88.11 61.159 ;
     RECT  70.38 60.419 70.398 61.259 ;
     RECT  87.192 61.159 88.11 61.259 ;
     RECT  76.5 60.917 86.382 61.277 ;
     RECT  71.244 60.809 75.618 61.339 ;
     RECT  19.8 60.953 68.67 61.493 ;
     RECT  71.1 61.339 75.618 61.493 ;
     RECT  76.5 61.277 80.478 61.501 ;
     RECT  71.1 61.493 71.694 61.619 ;
     RECT  87.192 61.259 88.074 61.619 ;
     RECT  19.8 61.493 56.754 61.655 ;
     RECT  72.432 61.493 75.618 61.663 ;
     RECT  76.356 61.501 80.478 61.663 ;
     RECT  57.6 61.493 68.67 61.735 ;
     RECT  72.432 61.663 80.478 61.757 ;
     RECT  57.6 61.735 69.102 61.771 ;
     RECT  81.54 61.277 86.382 61.799 ;
     RECT  2.376 61.079 14.958 61.861 ;
     RECT  15.732 61.079 18.897 61.861 ;
     RECT  2.376 61.861 18.897 61.889 ;
     RECT  57.6 61.771 70.11 62.041 ;
     RECT  76.968 61.757 80.478 62.045 ;
     RECT  72.432 61.757 76.086 62.069 ;
     RECT  81.612 61.799 86.382 62.159 ;
     RECT  2.415 61.889 18.897 62.275 ;
     RECT  19.8 61.655 32.346 62.275 ;
     RECT  71.64 61.619 71.694 62.275 ;
     RECT  72.432 62.069 74.79 62.275 ;
     RECT  75.528 62.069 76.086 62.429 ;
     RECT  75.528 62.429 75.762 62.435 ;
     RECT  81.684 62.159 86.382 62.437 ;
     RECT  87.48 61.619 88.074 62.437 ;
     RECT  87.228 62.437 88.074 62.537 ;
     RECT  33.192 61.655 56.754 62.545 ;
     RECT  57.6 62.041 70.614 62.545 ;
     RECT  87.228 62.537 87.246 62.573 ;
     RECT  2.415 62.275 32.346 62.581 ;
     RECT  33.192 62.545 70.614 62.581 ;
     RECT  71.64 62.275 74.79 62.581 ;
     RECT  76.968 62.045 80.334 62.609 ;
     RECT  75.528 62.435 75.546 62.699 ;
     RECT  2.415 62.581 70.614 62.815 ;
     RECT  71.604 62.581 74.79 62.851 ;
     RECT  77.004 62.609 80.334 62.851 ;
     RECT  81.684 62.437 86.418 62.969 ;
     RECT  71.46 62.851 74.79 63.013 ;
     RECT  77.004 62.851 80.406 63.013 ;
     RECT  2.376 62.815 70.614 63.049 ;
     RECT  71.46 63.013 74.862 63.049 ;
     RECT  2.376 63.049 74.862 63.197 ;
     RECT  77.004 63.013 80.766 63.211 ;
     RECT  81.684 62.969 86.202 63.211 ;
     RECT  77.004 63.211 86.202 63.239 ;
     RECT  79.632 63.239 86.202 63.275 ;
     RECT  80.892 63.275 86.202 63.311 ;
     RECT  85.068 63.311 86.202 63.347 ;
     RECT  75.6 63.319 75.834 63.391 ;
     RECT  77.004 63.239 78.606 63.553 ;
     RECT  80.892 63.311 84.15 63.581 ;
     RECT  75.6 63.391 75.87 63.589 ;
     RECT  76.968 63.553 78.606 63.589 ;
     RECT  2.376 63.197 74.754 63.779 ;
     RECT  85.14 63.347 86.202 63.787 ;
     RECT  75.6 63.589 78.606 63.823 ;
     RECT  80.892 63.581 83.898 64.049 ;
     RECT  75.492 63.823 78.606 64.057 ;
     RECT  14.688 63.779 74.754 64.201 ;
     RECT  75.492 64.057 78.678 64.201 ;
     RECT  79.632 63.275 79.65 64.201 ;
     RECT  14.688 64.201 78.678 64.301 ;
     RECT  60.588 64.301 78.678 64.315 ;
     RECT  79.632 64.201 79.722 64.315 ;
     RECT  2.376 63.779 13.95 64.355 ;
     RECT  81.54 64.049 83.898 64.355 ;
     RECT  60.588 64.315 79.722 64.363 ;
     RECT  85.14 63.787 86.382 64.459 ;
     RECT  14.688 64.301 59.814 64.463 ;
     RECT  81.612 64.355 83.898 64.471 ;
     RECT  84.996 64.459 86.382 64.471 ;
     RECT  2.415 64.355 13.95 64.555 ;
     RECT  14.688 64.463 59.598 64.555 ;
     RECT  88.056 62.537 88.074 64.589 ;
     RECT  2.415 64.555 59.598 64.625 ;
     RECT  81.612 64.471 86.382 64.741 ;
     RECT  4.968 64.625 59.598 65.021 ;
     RECT  60.588 64.363 80.586 65.209 ;
     RECT  49.896 65.021 59.598 65.245 ;
     RECT  60.444 65.209 80.586 65.281 ;
     RECT  49.896 65.245 59.634 65.371 ;
     RECT  60.444 65.281 80.766 65.371 ;
     RECT  4.968 65.021 49.122 65.399 ;
     RECT  49.896 65.371 80.766 65.399 ;
     RECT  81.612 64.741 87.786 65.399 ;
     RECT  81.612 65.399 81.774 65.435 ;
     RECT  50.004 65.399 80.766 65.479 ;
     RECT  81.612 65.435 81.63 65.479 ;
     RECT  50.004 65.479 81.63 65.549 ;
     RECT  2.415 64.625 4.23 65.551 ;
     RECT  4.968 65.399 49.086 65.551 ;
     RECT  82.548 65.399 87.786 65.551 ;
     RECT  82.548 65.551 87.858 65.813 ;
     RECT  50.004 65.549 60.138 65.975 ;
     RECT  82.548 65.813 87.138 66.083 ;
     RECT  60.876 65.549 81.63 66.181 ;
     RECT  82.548 66.083 87.066 66.181 ;
     RECT  60.876 66.181 87.066 66.209 ;
     RECT  2.415 65.551 49.086 66.245 ;
     RECT  33.408 66.245 49.086 66.715 ;
     RECT  50.004 65.975 59.778 66.715 ;
     RECT  60.876 66.209 65.25 66.991 ;
     RECT  2.415 66.245 32.67 67.171 ;
     RECT  33.408 66.715 59.778 67.171 ;
     RECT  60.876 66.991 65.286 67.171 ;
     RECT  2.415 67.171 59.778 67.243 ;
     RECT  66.348 66.209 87.066 67.405 ;
     RECT  60.876 67.171 65.322 67.441 ;
     RECT  66.096 67.405 87.066 67.441 ;
     RECT  60.876 67.441 87.066 67.709 ;
     RECT  2.415 67.243 60.03 67.981 ;
     RECT  2.415 67.981 60.102 68.251 ;
     RECT  2.376 68.251 60.102 68.341 ;
     RECT  60.876 67.709 85.842 68.341 ;
     RECT  2.376 68.341 85.842 68.369 ;
     RECT  2.415 68.369 85.842 68.971 ;
     RECT  86.616 67.709 87.066 68.971 ;
     RECT  2.415 68.971 87.066 68.981 ;
     RECT  7.452 68.981 87.066 69.017 ;
     RECT  2.415 68.981 6.714 69.089 ;
     RECT  2.415 69.089 6.57 69.331 ;
     RECT  7.488 69.017 87.066 69.331 ;
     RECT  2.34 69.331 6.57 69.835 ;
     RECT  7.488 69.331 87.138 69.835 ;
     RECT  2.34 69.835 87.138 70.097 ;
     RECT  2.34 70.097 46.998 70.109 ;
     RECT  2.415 70.109 46.998 70.133 ;
     RECT  47.844 70.097 87.138 70.133 ;
     RECT  47.844 70.133 85.77 70.565 ;
     RECT  86.508 70.133 87.138 70.681 ;
     RECT  11.124 70.133 46.998 70.951 ;
     RECT  86.508 70.681 87.174 70.951 ;
     RECT  2.415 70.133 10.314 71.041 ;
     RECT  51.015 70.565 85.77 71.069 ;
     RECT  58.536 71.069 85.77 71.077 ;
     RECT  86.508 70.951 87.21 71.077 ;
     RECT  2.376 71.041 10.314 71.117 ;
     RECT  2.415 71.117 10.314 71.221 ;
     RECT  11.124 70.951 47.07 71.221 ;
     RECT  58.536 71.077 87.21 71.221 ;
     RECT  2.415 71.221 47.07 71.249 ;
     RECT  47.844 70.565 50.274 71.455 ;
     RECT  4.32 71.249 47.07 71.467 ;
     RECT  47.808 71.455 50.274 71.467 ;
     RECT  2.415 71.249 3.546 71.609 ;
     RECT  4.32 71.467 50.274 71.645 ;
     RECT  4.356 71.645 50.274 71.689 ;
     RECT  51.015 71.069 57.798 71.689 ;
     RECT  58.536 71.221 87.282 71.761 ;
     RECT  4.356 71.689 57.798 72.031 ;
     RECT  58.536 71.761 87.426 72.031 ;
     RECT  2.415 71.609 3.438 72.391 ;
     RECT  4.356 72.031 87.678 72.455 ;
     RECT  2.376 72.391 3.438 72.461 ;
     RECT  2.415 72.461 3.438 72.499 ;
     RECT  4.356 72.455 59.598 72.499 ;
     RECT  2.415 72.499 59.598 73.085 ;
     RECT  60.48 72.455 87.678 73.273 ;
     RECT  2.415 73.085 59.382 73.373 ;
     RECT  60.444 73.273 87.678 73.531 ;
     RECT  41.976 73.373 59.382 73.535 ;
     RECT  60.156 73.531 87.678 73.535 ;
     RECT  41.976 73.535 55.134 73.607 ;
     RECT  55.872 73.535 59.382 73.921 ;
     RECT  60.156 73.535 81.738 73.921 ;
     RECT  55.872 73.921 81.738 74.039 ;
     RECT  82.476 73.535 87.678 74.281 ;
     RECT  42.696 73.607 55.134 74.299 ;
     RECT  55.872 74.039 80.658 74.299 ;
     RECT  2.415 73.373 41.022 74.425 ;
     RECT  81.396 74.039 81.738 74.425 ;
     RECT  82.476 74.281 87.786 74.425 ;
     RECT  2.415 74.425 41.346 74.461 ;
     RECT  42.696 74.299 80.658 74.461 ;
     RECT  2.415 74.461 80.658 74.489 ;
     RECT  2.415 74.489 80.514 74.621 ;
     RECT  2.415 74.621 80.37 75.155 ;
     RECT  2.415 75.155 41.922 75.227 ;
     RECT  42.696 75.155 80.37 75.533 ;
     RECT  79.416 75.533 80.37 75.541 ;
     RECT  81.396 74.425 87.786 75.541 ;
     RECT  2.415 75.227 22.122 75.821 ;
     RECT  42.696 75.533 78.606 75.821 ;
     RECT  22.86 75.227 41.922 75.901 ;
     RECT  42.696 75.821 60.894 75.901 ;
     RECT  3.42 75.821 22.122 76.171 ;
     RECT  22.86 75.901 60.894 76.171 ;
     RECT  79.416 75.541 87.786 76.271 ;
     RECT  3.42 76.171 60.894 76.301 ;
     RECT  44.352 76.301 60.894 76.585 ;
     RECT  61.632 75.821 78.606 76.585 ;
     RECT  44.352 76.585 78.606 76.819 ;
     RECT  79.416 76.271 87.75 76.819 ;
     RECT  3.42 76.301 43.542 76.829 ;
     RECT  44.352 76.819 87.75 77.009 ;
     RECT  77.58 77.009 87.75 77.017 ;
     RECT  2.415 75.821 2.697 77.035 ;
     RECT  3.42 76.829 37.674 77.035 ;
     RECT  38.448 76.829 43.542 77.089 ;
     RECT  44.352 77.009 76.662 77.089 ;
     RECT  2.415 77.035 37.674 77.125 ;
     RECT  77.58 77.017 87.786 77.431 ;
     RECT  2.376 77.125 37.674 77.557 ;
     RECT  38.448 77.089 76.662 77.557 ;
     RECT  77.58 77.431 87.822 77.891 ;
     RECT  77.58 77.891 87.786 78.539 ;
     RECT  2.376 77.557 76.662 78.773 ;
     RECT  2.415 78.773 76.662 79.051 ;
     RECT  77.58 78.539 87.75 79.051 ;
     RECT  2.415 79.051 87.75 79.745 ;
     RECT  2.415 79.745 87.714 79.979 ;
     RECT  76.212 79.979 87.714 80.249 ;
     RECT  2.415 79.979 75.474 80.381 ;
     RECT  76.356 80.249 87.714 80.591 ;
     RECT  77.976 80.591 87.714 80.671 ;
     RECT  48.456 80.381 75.474 80.789 ;
     RECT  77.976 80.671 88.002 80.825 ;
     RECT  77.976 80.825 87.786 81.203 ;
     RECT  76.356 80.591 77.202 81.211 ;
     RECT  2.415 80.381 47.718 81.373 ;
     RECT  48.456 80.789 75.294 81.373 ;
     RECT  76.104 81.211 77.202 81.715 ;
     RECT  77.976 81.203 87.714 81.715 ;
     RECT  2.415 81.373 75.294 81.869 ;
     RECT  47.304 81.869 75.294 82.021 ;
     RECT  76.104 81.715 87.714 82.021 ;
     RECT  2.415 81.869 46.566 82.109 ;
     RECT  2.415 82.109 39.006 82.283 ;
     RECT  39.78 82.109 46.566 82.687 ;
     RECT  47.304 82.021 87.894 82.687 ;
     RECT  39.78 82.687 87.894 82.829 ;
     RECT  2.415 82.283 8.19 83.029 ;
     RECT  9.072 82.283 39.006 83.029 ;
     RECT  39.78 82.829 44.046 83.029 ;
     RECT  2.415 83.029 44.046 83.069 ;
     RECT  44.856 82.829 87.894 83.129 ;
     RECT  45.144 83.129 87.894 83.219 ;
     RECT  45.144 83.219 48.186 83.261 ;
     RECT  45.144 83.261 48.114 83.837 ;
     RECT  2.415 83.069 43.866 83.995 ;
     RECT  45.252 83.837 48.114 84.331 ;
     RECT  49.032 83.219 87.894 84.331 ;
     RECT  2.415 83.995 44.442 84.335 ;
     RECT  44.244 84.335 44.442 84.811 ;
     RECT  45.252 84.331 87.894 84.811 ;
     RECT  2.415 84.335 43.434 85.351 ;
     RECT  44.244 84.811 87.894 85.351 ;
     RECT  2.415 85.351 87.894 85.379 ;
     RECT  2.415 85.379 52.902 85.793 ;
     RECT  49.32 85.793 52.902 86.305 ;
     RECT  53.64 85.379 87.894 86.305 ;
     RECT  2.415 85.793 48.402 86.621 ;
     RECT  49.32 86.305 87.894 87.079 ;
     RECT  2.415 86.621 47.646 87.421 ;
     RECT  48.384 86.621 48.402 87.421 ;
     RECT  2.415 87.421 48.402 87.547 ;
     RECT  49.212 87.079 87.894 87.547 ;
     RECT  2.415 87.547 87.894 88.493 ;
     RECT  48.672 88.493 87.894 88.897 ;
     RECT  2.415 88.493 47.898 89.437 ;
     RECT  48.672 88.897 88.002 89.437 ;
     RECT  2.415 89.437 88.002 89.885 ;
     RECT  2.415 89.885 38.142 90.113 ;
     RECT  2.415 90.113 38.034 90.239 ;
     RECT  2.415 90.239 3.546 90.311 ;
     RECT  39.06 89.885 88.002 90.419 ;
     RECT  4.428 90.239 37.926 90.959 ;
     RECT  2.415 90.311 3.438 91.057 ;
     RECT  5.076 90.959 37.926 91.157 ;
     RECT  39.06 90.419 74.754 91.193 ;
     RECT  9.648 91.157 37.926 91.195 ;
     RECT  39.06 91.193 68.238 91.195 ;
     RECT  68.976 91.193 74.754 91.201 ;
     RECT  75.672 90.419 88.002 91.471 ;
     RECT  9.648 91.195 68.238 91.499 ;
     RECT  2.415 91.057 4.014 91.589 ;
     RECT  68.976 91.201 74.826 91.705 ;
     RECT  75.672 91.471 88.434 91.705 ;
     RECT  38.988 91.499 68.238 91.733 ;
     RECT  3.744 91.589 4.014 91.741 ;
     RECT  3.744 91.741 4.302 91.861 ;
     RECT  5.076 91.157 8.586 91.861 ;
     RECT  3.744 91.861 8.586 91.939 ;
     RECT  9.648 91.499 38.214 91.939 ;
     RECT  68.976 91.705 88.434 91.975 ;
     RECT  68.94 91.975 88.434 92.129 ;
     RECT  68.94 92.129 70.29 92.273 ;
     RECT  71.1 92.129 88.434 92.273 ;
     RECT  38.988 91.733 67.626 92.309 ;
     RECT  68.94 92.273 70.182 92.381 ;
     RECT  2.415 91.589 3.006 92.395 ;
     RECT  3.744 91.939 38.214 92.395 ;
     RECT  38.988 92.309 48.546 92.399 ;
     RECT  49.428 92.309 67.626 92.399 ;
     RECT  66.996 92.399 67.626 92.435 ;
     RECT  71.316 92.273 88.434 92.471 ;
     RECT  67.215 92.435 67.626 92.641 ;
     RECT  69.48 92.381 70.182 92.813 ;
     RECT  67.215 92.641 67.842 92.947 ;
     RECT  49.428 92.399 65.826 92.975 ;
     RECT  49.428 92.975 65.43 93.047 ;
     RECT  38.988 92.399 48.474 93.053 ;
     RECT  69.768 92.813 70.182 93.091 ;
     RECT  71.316 92.471 87.822 93.091 ;
     RECT  2.415 92.395 38.214 93.209 ;
     RECT  3.42 93.209 38.214 93.217 ;
     RECT  38.988 93.053 48.222 93.217 ;
     RECT  3.42 93.217 48.222 93.245 ;
     RECT  49.428 93.047 64.926 93.253 ;
     RECT  69.768 93.091 87.822 93.361 ;
     RECT  49.032 93.253 64.926 93.389 ;
     RECT  69.768 93.361 88.326 93.479 ;
     RECT  70.092 93.479 88.326 93.485 ;
     RECT  32.688 93.245 48.222 93.659 ;
     RECT  46.764 93.659 48.222 93.793 ;
     RECT  70.812 93.485 88.326 93.821 ;
     RECT  67.215 92.947 68.382 93.901 ;
     RECT  70.812 93.821 87.894 93.929 ;
     RECT  49.428 93.389 64.926 94.019 ;
     RECT  70.812 93.929 87.21 94.019 ;
     RECT  70.812 94.019 70.83 94.055 ;
     RECT  71.64 94.019 87.21 94.055 ;
     RECT  3.42 93.245 31.914 94.063 ;
     RECT  32.688 93.659 45.99 94.063 ;
     RECT  87.192 94.055 87.21 94.199 ;
     RECT  3.42 94.063 45.99 94.289 ;
     RECT  46.764 93.793 48.474 94.289 ;
     RECT  49.428 94.019 62.982 94.289 ;
     RECT  71.64 94.055 86.382 94.361 ;
     RECT  67.215 93.901 68.526 94.405 ;
     RECT  67.104 94.405 68.634 94.555 ;
     RECT  38.7 94.289 45.99 94.559 ;
     RECT  66.564 94.555 68.634 94.559 ;
     RECT  71.64 94.361 85.446 94.559 ;
     RECT  86.364 94.361 86.382 94.559 ;
     RECT  66.564 94.559 68.526 94.595 ;
     RECT  72.432 94.559 85.446 94.595 ;
     RECT  71.64 94.559 71.658 94.637 ;
     RECT  72.432 94.595 85.338 94.637 ;
     RECT  38.988 94.559 45.99 94.651 ;
     RECT  46.764 94.289 48.258 94.651 ;
     RECT  3.42 94.289 33.534 94.739 ;
     RECT  76.68 94.637 85.338 94.937 ;
     RECT  63.972 94.019 64.926 94.945 ;
     RECT  3.456 94.739 33.534 95.099 ;
     RECT  76.68 94.937 84.654 95.099 ;
     RECT  72.432 94.637 75.798 95.135 ;
     RECT  76.68 95.099 78.93 95.135 ;
     RECT  79.668 95.099 82.206 95.135 ;
     RECT  49.428 94.289 62.802 95.143 ;
     RECT  63.9 94.945 64.926 95.143 ;
     RECT  75.204 95.135 75.798 95.171 ;
     RECT  76.752 95.135 76.914 95.171 ;
     RECT  78.015 95.135 78.858 95.171 ;
     RECT  79.704 95.135 81.99 95.171 ;
     RECT  83.376 95.099 84.654 95.171 ;
     RECT  38.988 94.651 48.258 95.179 ;
     RECT  20.268 95.099 33.534 95.207 ;
     RECT  34.344 94.289 37.854 95.215 ;
     RECT  75.204 95.171 75.222 95.243 ;
     RECT  76.896 95.171 76.914 95.243 ;
     RECT  78.015 95.171 78.606 95.243 ;
     RECT  83.415 95.171 84.654 95.243 ;
     RECT  38.988 95.179 48.366 95.251 ;
     RECT  49.428 95.143 64.926 95.251 ;
     RECT  66.816 94.595 67.986 95.341 ;
     RECT  20.52 95.207 33.534 95.369 ;
     RECT  38.988 95.251 64.926 95.369 ;
     RECT  84.456 95.243 84.654 95.369 ;
     RECT  66.816 95.341 68.022 95.371 ;
     RECT  39.42 95.369 64.782 95.405 ;
     RECT  66.816 95.371 68.418 95.405 ;
     RECT  70.344 95.368 70.362 95.405 ;
     RECT  80.388 95.171 81.99 95.405 ;
     RECT  80.388 95.405 81.486 95.477 ;
     RECT  66.996 95.405 68.418 95.485 ;
     RECT  66.996 95.485 68.742 95.513 ;
     RECT  72.432 95.135 73.854 95.513 ;
     RECT  80.532 95.477 81.486 95.513 ;
     RECT  3.456 95.099 19.314 95.521 ;
     RECT  20.772 95.369 33.534 95.521 ;
     RECT  34.344 95.215 38.07 95.521 ;
     RECT  68.724 95.513 68.742 95.521 ;
     RECT  69.48 95.341 69.498 95.521 ;
     RECT  70.704 95.449 70.794 95.521 ;
     RECT  71.568 95.467 71.586 95.521 ;
     RECT  72.432 95.513 72.954 95.521 ;
     RECT  80.748 95.513 81.486 95.549 ;
     RECT  20.772 95.521 38.43 95.639 ;
     RECT  39.42 95.405 63.99 95.639 ;
     RECT  64.764 95.405 64.782 95.639 ;
     RECT  66.996 95.513 67.95 95.639 ;
     RECT  68.724 95.521 69.498 95.639 ;
     RECT  80.748 95.549 81.198 95.639 ;
     RECT  39.42 95.639 60.786 95.675 ;
     RECT  68.976 95.639 69.426 95.675 ;
     RECT  73.692 95.513 73.854 95.675 ;
     RECT  20.772 95.639 33.498 95.747 ;
     RECT  67.215 95.639 67.95 95.747 ;
     RECT  70.704 95.521 72.954 95.747 ;
     RECT  73.692 95.675 73.71 95.747 ;
     RECT  20.772 95.747 32.526 95.819 ;
     RECT  3.42 95.521 19.314 95.909 ;
     RECT  33.264 95.747 33.498 95.909 ;
     RECT  70.704 95.747 70.722 95.909 ;
     RECT  71.46 95.747 71.838 95.909 ;
     RECT  2.415 93.209 2.697 96.025 ;
     RECT  3.42 95.909 18.897 96.025 ;
     RECT  71.46 95.909 71.478 96.053 ;
     RECT  20.772 95.819 31.806 96.089 ;
     RECT  34.416 95.639 38.43 96.179 ;
     RECT  21.348 96.089 31.806 96.251 ;
     RECT  33.48 95.909 33.498 96.251 ;
     RECT  21.42 96.251 22.05 96.287 ;
     RECT  39.42 95.675 60.75 96.287 ;
     RECT  34.416 96.179 37.062 96.317 ;
     RECT  2.415 96.025 18.897 96.323 ;
     RECT  21.42 96.287 21.438 96.323 ;
     RECT  23.4 96.251 31.806 96.323 ;
     RECT  37.872 96.179 38.43 96.323 ;
     RECT  39.42 96.287 52.038 96.323 ;
     RECT  23.724 96.323 31.806 96.359 ;
     RECT  34.416 96.317 36.99 96.359 ;
     RECT  34.416 96.359 36.918 96.449 ;
     RECT  37.872 96.323 37.89 96.449 ;
     RECT  52.956 96.287 60.75 96.457 ;
     RECT  61.56 95.639 63.306 96.457 ;
     RECT  3.78 96.323 18.897 96.485 ;
     RECT  24.015 96.359 31.806 96.485 ;
     RECT  39.42 96.323 44.334 96.485 ;
     RECT  39.42 96.485 44.226 96.493 ;
     RECT  38.808 96.493 44.226 96.509 ;
     RECT  24.015 96.485 28.026 96.521 ;
     RECT  45.072 96.323 52.038 96.521 ;
     RECT  34.488 96.449 36.918 96.557 ;
     RECT  50.184 96.521 51.297 96.557 ;
     RECT  24.015 96.521 27.738 96.593 ;
     RECT  45.072 96.521 49.158 96.593 ;
     RECT  52.956 96.457 63.306 96.593 ;
     RECT  46.62 96.593 49.158 96.605 ;
     RECT  25.668 96.593 27.738 96.629 ;
     RECT  28.8 96.485 31.734 96.629 ;
     RECT  38.808 96.509 42.066 96.629 ;
     RECT  54.936 96.593 63.306 96.629 ;
     RECT  3.816 96.485 18.897 96.719 ;
     RECT  25.74 96.629 25.758 96.719 ;
     RECT  28.8 96.629 30.834 96.719 ;
     RECT  31.608 96.629 31.626 96.719 ;
     RECT  34.488 96.557 35.874 96.719 ;
     RECT  38.808 96.629 40.986 96.719 ;
     RECT  41.724 96.629 42.066 96.719 ;
     RECT  42.804 96.509 44.226 96.719 ;
     RECT  50.256 96.557 51.297 96.719 ;
     RECT  52.956 96.593 54.126 96.719 ;
     RECT  61.524 96.629 63.306 96.719 ;
     RECT  17.892 96.719 18.897 96.755 ;
     RECT  26.748 96.629 27.738 96.755 ;
     RECT  30.636 96.719 30.654 96.755 ;
     RECT  34.488 96.719 35.097 96.755 ;
     RECT  41.724 96.719 41.742 96.755 ;
     RECT  42.804 96.719 43.326 96.755 ;
     RECT  44.208 96.719 44.226 96.755 ;
     RECT  52.956 96.719 54.018 96.755 ;
     RECT  61.56 96.719 63.306 96.755 ;
     RECT  38.808 96.719 40.77 96.791 ;
     RECT  45.072 96.593 45.897 96.791 ;
     RECT  57.708 96.629 60.678 96.791 ;
     RECT  46.656 96.605 49.158 96.8 ;
     RECT  3.816 96.719 17.082 96.827 ;
     RECT  47.088 96.8 49.158 96.827 ;
     RECT  52.02 96.521 52.038 96.827 ;
     RECT  53.028 96.755 53.946 96.827 ;
     RECT  54.936 96.629 56.97 96.827 ;
     RECT  58.392 96.791 60.678 96.845 ;
     RECT  3.816 96.827 13.77 96.863 ;
     RECT  14.544 96.827 16.074 96.863 ;
     RECT  27.108 96.755 27.738 96.863 ;
     RECT  47.16 96.827 47.43 96.863 ;
     RECT  48.744 96.827 49.158 96.863 ;
     RECT  50.292 96.719 51.297 96.863 ;
     RECT  53.028 96.827 53.406 96.863 ;
     RECT  54.936 96.827 56.718 96.863 ;
     RECT  58.788 96.845 60.678 96.863 ;
     RECT  61.56 96.755 62.514 96.863 ;
     RECT  45.18 96.791 45.897 96.893 ;
     RECT  54.936 96.863 56.697 96.893 ;
     RECT  3.816 96.863 13.698 96.899 ;
     RECT  24.015 96.593 24.822 96.899 ;
     RECT  27.144 96.863 27.738 96.899 ;
     RECT  28.8 96.719 29.697 96.899 ;
     RECT  43.2 96.755 43.326 96.899 ;
     RECT  47.16 96.863 47.178 96.899 ;
     RECT  49.14 96.863 49.158 96.899 ;
     RECT  53.172 96.863 53.19 96.899 ;
     RECT  54.936 96.893 54.954 96.899 ;
     RECT  55.908 96.893 56.697 96.899 ;
     RECT  58.788 96.863 59.706 96.899 ;
     RECT  60.516 96.863 60.678 96.899 ;
     RECT  61.815 96.863 62.514 96.899 ;
     RECT  13.215 96.899 13.698 96.941 ;
     RECT  2.415 96.323 2.697 96.947 ;
     RECT  18.615 96.755 18.897 96.947 ;
     RECT  24.015 96.899 24.297 96.947 ;
     RECT  29.088 96.899 29.697 96.947 ;
     RECT  34.815 96.755 35.097 96.947 ;
     RECT  39.744 96.791 40.497 96.947 ;
     RECT  45.615 96.893 45.897 96.947 ;
     RECT  51.015 96.863 51.297 96.947 ;
     RECT  56.415 96.899 56.697 96.947 ;
     RECT  61.815 96.899 62.097 96.947 ;
     RECT  67.215 95.747 67.497 96.947 ;
     RECT  72.615 95.747 72.897 96.947 ;
     RECT  78.015 95.243 78.297 96.947 ;
     RECT  83.415 95.243 83.697 96.947 ;
     RECT  3.816 96.899 12.114 96.989 ;
     RECT  14.544 96.863 14.85 96.989 ;
     RECT  27.432 96.899 27.738 96.989 ;
     RECT  38.808 96.791 38.97 96.989 ;
     RECT  39.744 96.947 40.305 96.989 ;
     RECT  3.816 96.989 9.558 97.025 ;
     RECT  13.215 96.941 13.554 97.025 ;
     RECT  27.72 96.989 27.738 97.025 ;
     RECT  38.808 96.989 38.826 97.025 ;
     RECT  40.14 96.989 40.305 97.025 ;
     RECT  4.212 97.025 9.558 97.061 ;
     RECT  16.056 96.863 16.074 97.061 ;
     RECT  11.124 96.989 11.394 97.097 ;
     RECT  40.176 97.025 40.305 97.097 ;
     RECT  17.064 96.827 17.082 97.133 ;
     RECT  5.076 97.061 9.558 97.169 ;
     RECT  29.088 96.947 29.505 97.169 ;
     RECT  2.415 96.947 2.505 97.217 ;
     RECT  13.215 97.025 13.305 97.217 ;
     RECT  18.615 96.947 18.705 97.217 ;
     RECT  24.015 96.947 24.105 97.217 ;
     RECT  29.415 97.169 29.505 97.217 ;
     RECT  34.815 96.947 34.905 97.217 ;
     RECT  40.215 97.097 40.305 97.217 ;
     RECT  45.615 96.947 45.705 97.217 ;
     RECT  51.015 96.947 51.105 97.217 ;
     RECT  56.415 96.947 56.505 97.217 ;
     RECT  61.815 96.947 61.905 97.217 ;
     RECT  67.215 96.947 67.305 97.217 ;
     RECT  72.615 96.947 72.705 97.217 ;
     RECT  78.015 96.947 78.105 97.217 ;
     RECT  83.415 96.947 83.505 97.217 ;
     RECT  5.076 97.169 9.414 97.325 ;
     RECT  8.532 97.325 9.414 97.373 ;
     RECT  5.076 97.325 7.542 97.469 ;
     RECT  8.532 97.373 9.198 97.469 ;
     RECT  4.212 97.061 4.23 98.093 ;
     RECT  5.22 97.469 7.542 98.669 ;
     RECT  9 97.469 9.198 99.197 ;
     RECT  5.22 98.669 6.246 99.245 ;
     RECT  9.18 99.197 9.198 99.245 ;
    LAYER M4 ;
     RECT  0.06 4.032 0.227 5.016 ;
     RECT  0.227 4.992 2.365 5.016 ;
     RECT  2.293 52.992 2.365 53.016 ;
     RECT  2.365 4.128 2.408 5.016 ;
     RECT  2.293 14.64 2.408 14.664 ;
     RECT  2.401 47.328 2.408 47.352 ;
     RECT  2.365 48.672 2.408 48.696 ;
     RECT  0.181 49.824 2.408 49.848 ;
     RECT  2.365 52.464 2.408 53.016 ;
     RECT  2.293 54.96 2.408 54.984 ;
     RECT  2.293 56.592 2.408 56.616 ;
     RECT  2.365 59.76 2.408 59.784 ;
     RECT  2.365 61.632 2.408 61.656 ;
     RECT  2.329 70.08 2.408 70.104 ;
     RECT  2.365 71.088 2.408 71.112 ;
     RECT  2.365 72.432 2.408 72.456 ;
     RECT  2.408 2.148 2.512 97.212 ;
     RECT  2.512 2.418 2.704 96.942 ;
     RECT  2.704 50.928 2.819 51.24 ;
     RECT  2.704 75.648 2.819 75.816 ;
     RECT  2.704 77.04 2.819 77.064 ;
     RECT  2.704 3.12 2.915 4.152 ;
     RECT  2.704 72.432 2.915 73.272 ;
     RECT  2.704 47.328 2.945 48.696 ;
     RECT  2.915 3.12 2.953 4.008 ;
     RECT  2.704 15.408 2.981 15.432 ;
     RECT  2.704 17.232 2.981 17.496 ;
     RECT  2.704 79.968 3.004 82.104 ;
     RECT  2.704 91.152 3.017 92.424 ;
     RECT  2.704 10.368 3.053 12.264 ;
     RECT  2.704 67.248 3.197 68.856 ;
     RECT  3.017 91.2 3.241 92.424 ;
     RECT  2.981 17.28 3.269 17.496 ;
     RECT  2.704 25.2 3.305 26.808 ;
     RECT  2.704 87.648 3.305 87.672 ;
     RECT  2.704 70.08 3.377 71.352 ;
     RECT  3.377 70.464 3.436 71.352 ;
     RECT  3.305 25.2 3.493 26.232 ;
     RECT  3.269 17.28 3.557 17.4 ;
     RECT  3.004 79.968 3.557 80.952 ;
     RECT  2.819 51.216 3.587 51.24 ;
     RECT  2.704 54.192 3.593 54.408 ;
     RECT  2.915 73.248 3.629 73.272 ;
     RECT  2.704 83.616 3.685 84.36 ;
     RECT  2.704 43.248 3.733 43.272 ;
     RECT  2.704 95.376 3.733 95.4 ;
     RECT  3.493 25.2 3.737 26.184 ;
     RECT  2.945 47.472 3.737 48.696 ;
     RECT  3.733 94.704 3.737 95.4 ;
     RECT  2.704 58.656 3.769 60.168 ;
     RECT  2.704 61.632 3.769 61.656 ;
     RECT  3.685 83.184 3.772 84.36 ;
     RECT  2.704 52.464 3.788 52.488 ;
     RECT  2.704 32.64 3.809 32.664 ;
     RECT  3.788 52.464 3.836 52.584 ;
     RECT  3.593 54.192 3.836 54.216 ;
     RECT  2.704 5.52 3.841 7.464 ;
     RECT  2.704 18.768 3.845 18.792 ;
     RECT  3.197 67.296 3.845 68.856 ;
     RECT  3.772 83.472 3.845 84.36 ;
     RECT  3.737 94.704 3.845 94.728 ;
     RECT  2.704 56.976 3.881 57.576 ;
     RECT  3.836 52.464 3.923 54.216 ;
     RECT  3.841 5.28 3.949 7.464 ;
     RECT  3.004 82.08 3.949 82.104 ;
     RECT  3.241 91.92 3.949 92.424 ;
     RECT  3.769 58.656 3.961 61.656 ;
     RECT  3.737 47.472 3.985 47.496 ;
     RECT  3.949 4.992 3.989 7.464 ;
     RECT  2.704 38.928 3.989 39.336 ;
     RECT  2.704 63.648 3.989 63.672 ;
     RECT  3.557 17.376 4.025 17.4 ;
     RECT  2.704 45.36 4.025 45.384 ;
     RECT  3.985 47.28 4.025 47.496 ;
     RECT  2.704 78.624 4.025 78.648 ;
     RECT  2.704 41.376 4.093 41.4 ;
     RECT  3.697 14.736 4.097 14.76 ;
     RECT  4.021 0.576 4.105 0.6 ;
     RECT  2.704 19.776 4.129 19.8 ;
     RECT  4.129 9.648 4.165 9.672 ;
     RECT  3.881 57.552 4.169 57.576 ;
     RECT  4.165 9.456 4.201 9.672 ;
     RECT  2.704 34.608 4.237 34.632 ;
     RECT  2.704 35.712 4.237 35.736 ;
     RECT  4.093 41.376 4.237 42.168 ;
     RECT  3.733 43.248 4.237 43.368 ;
     RECT  4.021 98.064 4.241 98.088 ;
     RECT  2.953 3.984 4.273 4.008 ;
     RECT  3.989 4.992 4.273 7.416 ;
     RECT  3.989 39.312 4.273 39.336 ;
     RECT  2.819 75.648 4.277 75.672 ;
     RECT  3.961 58.656 4.313 60.168 ;
     RECT  4.201 9.456 4.345 10.2 ;
     RECT  4.237 34.608 4.349 35.736 ;
     RECT  4.025 47.28 4.349 47.304 ;
     RECT  2.704 64.752 4.357 65.352 ;
     RECT  4.345 30.192 4.381 30.216 ;
     RECT  3.845 68.832 4.381 68.856 ;
     RECT  3.436 70.464 4.381 70.68 ;
     RECT  2.704 28.416 4.403 28.44 ;
     RECT  4.129 63.216 4.403 63.24 ;
     RECT  4.381 30.048 4.417 30.216 ;
     RECT  4.357 64.56 4.444 65.352 ;
     RECT  4.129 19.776 4.453 19.848 ;
     RECT  4.349 34.608 4.489 34.632 ;
     RECT  4.417 30.048 4.529 30.792 ;
     RECT  2.704 22.704 4.549 22.728 ;
     RECT  4.237 41.376 4.549 43.368 ;
     RECT  4.237 44.688 4.549 44.712 ;
     RECT  4.549 22.704 4.597 23.208 ;
     RECT  4.237 24.336 4.597 24.36 ;
     RECT  4.549 41.376 4.601 44.712 ;
     RECT  4.601 44.304 4.636 44.712 ;
     RECT  3.923 53.664 4.637 54.216 ;
     RECT  4.453 19.584 4.673 19.848 ;
     RECT  3.557 79.968 4.705 80.088 ;
     RECT  4.673 19.584 4.709 19.608 ;
     RECT  4.313 59.424 4.709 60.168 ;
     RECT  4.489 34.512 4.741 34.632 ;
     RECT  4.597 22.704 4.777 24.36 ;
     RECT  3.845 67.296 4.78 67.8 ;
     RECT  4.273 3.984 4.781 7.416 ;
     RECT  4.381 68.832 4.813 70.68 ;
     RECT  3.949 91.92 4.813 92.952 ;
     RECT  4.741 34.08 4.817 34.632 ;
     RECT  4.273 39.312 4.817 40.056 ;
     RECT  4.601 41.376 4.817 43.32 ;
     RECT  2.704 20.832 4.835 20.856 ;
     RECT  3.923 52.464 4.921 52.488 ;
     RECT  4.345 9.312 4.957 10.2 ;
     RECT  3.053 11.232 4.993 12.264 ;
     RECT  4.813 68.832 5.033 71.064 ;
     RECT  4.813 91.872 5.033 92.952 ;
     RECT  3.737 25.632 5.069 26.184 ;
     RECT  4.78 67.296 5.069 67.32 ;
     RECT  4.777 22.32 5.075 24.36 ;
     RECT  5.069 26.16 5.101 26.184 ;
     RECT  4.705 79.968 5.101 81 ;
     RECT  3.949 82.08 5.101 82.296 ;
     RECT  4.817 39.312 5.137 39.528 ;
     RECT  5.101 79.968 5.137 82.296 ;
     RECT  4.993 11.232 5.141 12.312 ;
     RECT  5.101 26.16 5.141 26.28 ;
     RECT  4.817 34.08 5.177 34.104 ;
     RECT  5.137 38.928 5.209 39.528 ;
     RECT  4.957 9.312 5.213 10.248 ;
     RECT  5.075 23.712 5.249 24.36 ;
     RECT  5.065 97.44 5.269 97.464 ;
     RECT  4.993 13.584 5.281 13.608 ;
     RECT  4.525 78.48 5.281 78.504 ;
     RECT  5.209 38.832 5.317 39.528 ;
     RECT  4.633 85.632 5.353 85.656 ;
     RECT  5.213 10.128 5.357 10.248 ;
     RECT  4.817 42.72 5.357 43.32 ;
     RECT  5.269 97.44 5.365 97.512 ;
     RECT  5.101 19.056 5.389 19.08 ;
     RECT  4.817 41.376 5.389 41.64 ;
     RECT  3.845 83.472 5.411 84.024 ;
     RECT  5.281 78.096 5.425 78.504 ;
     RECT  5.137 79.728 5.425 82.296 ;
     RECT  5.365 97.44 5.425 97.56 ;
     RECT  4.921 51.84 5.465 52.488 ;
     RECT  5.389 18.144 5.497 19.08 ;
     RECT  5.075 22.32 5.497 22.344 ;
     RECT  4.309 88.512 5.497 88.536 ;
     RECT  5.033 92.928 5.497 92.952 ;
     RECT  4.637 53.664 5.501 54.168 ;
     RECT  4.777 37.056 5.537 37.08 ;
     RECT  5.357 42.72 5.537 43.128 ;
     RECT  5.497 17.952 5.569 19.08 ;
     RECT  5.317 38.784 5.573 39.528 ;
     RECT  5.281 13.584 5.605 13.896 ;
     RECT  3.737 48.672 5.605 48.696 ;
     RECT  2.704 49.824 5.605 49.848 ;
     RECT  4.993 94.416 5.605 94.44 ;
     RECT  5.425 78.096 5.609 82.296 ;
     RECT  5.569 17.232 5.641 19.08 ;
     RECT  5.353 85.152 5.641 85.656 ;
     RECT  5.357 10.224 5.645 10.248 ;
     RECT  5.573 38.832 5.645 39.528 ;
     RECT  5.389 41.136 5.645 41.64 ;
     RECT  5.033 69.696 5.645 71.064 ;
     RECT  5.641 16.944 5.677 19.08 ;
     RECT  4.057 76.752 5.677 76.776 ;
     RECT  5.033 91.872 5.677 91.896 ;
     RECT  3.913 56.496 5.701 56.52 ;
     RECT  4.777 28.752 5.713 28.776 ;
     RECT  4.529 30.048 5.713 30.072 ;
     RECT  5.165 99.216 5.716 99.24 ;
     RECT  5.389 66.48 5.717 66.504 ;
     RECT  5.605 94.416 5.717 94.632 ;
     RECT  5.713 28.752 5.753 30.072 ;
     RECT  5.645 38.928 5.753 39.528 ;
     RECT  5.209 58.176 5.753 58.2 ;
     RECT  5.677 75.936 5.756 76.776 ;
     RECT  5.609 78.096 5.756 80.088 ;
     RECT  5.756 75.936 5.843 80.088 ;
     RECT  5.605 13.584 5.857 13.992 ;
     RECT  5.537 42.72 5.857 42.744 ;
     RECT  5.497 88.368 5.857 88.536 ;
     RECT  5.501 54.144 5.861 54.168 ;
     RECT  4.781 3.984 5.893 4.008 ;
     RECT  5.716 99.168 5.893 99.24 ;
     RECT  5.065 72.192 5.897 72.216 ;
     RECT  5.497 21.456 5.933 22.344 ;
     RECT  5.857 13.584 5.965 14.088 ;
     RECT  4.789 15.504 5.965 15.528 ;
     RECT  5.893 98.64 6.037 99.24 ;
     RECT  5.843 75.936 6.041 77.592 ;
     RECT  5.965 13.584 6.073 15.528 ;
     RECT  5.425 97.392 6.073 97.56 ;
     RECT  5.677 60.48 6.077 60.504 ;
     RECT  5.605 48.672 6.085 49.848 ;
     RECT  6.073 96.96 6.133 97.56 ;
     RECT  6.037 98.592 6.133 99.24 ;
     RECT  5.893 3.072 6.145 4.008 ;
     RECT  4.781 4.992 6.145 7.416 ;
     RECT  5.677 16.944 6.145 19.224 ;
     RECT  5.701 56.4 6.145 56.52 ;
     RECT  5.465 52.464 6.149 52.488 ;
     RECT  6.085 48.24 6.172 49.848 ;
     RECT  5.141 11.52 6.181 12.312 ;
     RECT  6.073 13.536 6.181 15.528 ;
     RECT  6.145 27.696 6.181 27.72 ;
     RECT  5.677 90.912 6.181 91.896 ;
     RECT  5.609 81.12 6.185 82.296 ;
     RECT  6.181 22.464 6.217 22.488 ;
     RECT  5.857 88.368 6.221 88.92 ;
     RECT  6.145 16.944 6.257 19.32 ;
     RECT  6.133 96.96 6.257 99.24 ;
     RECT  3.961 61.632 6.277 61.656 ;
     RECT  6.109 0.576 6.289 0.6 ;
     RECT  4.813 1.728 6.289 1.752 ;
     RECT  5.641 85.152 6.289 86.04 ;
     RECT  6.217 87.36 6.289 87.384 ;
     RECT  6.172 48.672 6.293 49.848 ;
     RECT  4.444 65.328 6.323 65.352 ;
     RECT  5.425 31.392 6.325 31.416 ;
     RECT  6.181 90.816 6.325 91.896 ;
     RECT  6.325 31.392 6.361 31.512 ;
     RECT  6.073 33.36 6.361 33.384 ;
     RECT  6.277 61.632 6.361 61.752 ;
     RECT  6.277 63.072 6.361 63.096 ;
     RECT  6.289 0.576 6.373 1.752 ;
     RECT  4.709 59.424 6.401 59.448 ;
     RECT  6.289 85.152 6.433 87.384 ;
     RECT  6.373 0.576 6.467 0.6 ;
     RECT  5.933 21.456 6.469 21.48 ;
     RECT  5.753 38.928 6.473 38.952 ;
     RECT  6.373 1.68 6.505 1.752 ;
     RECT  5.249 23.808 6.505 24.36 ;
     RECT  6.257 16.944 6.509 19.08 ;
     RECT  6.361 32.976 6.509 33.384 ;
     RECT  6.505 1.68 6.541 1.8 ;
     RECT  6.145 3.072 6.541 7.416 ;
     RECT  6.509 16.944 6.541 18.6 ;
     RECT  6.361 61.632 6.541 63.096 ;
     RECT  6.433 84.72 6.545 87.624 ;
     RECT  5.411 83.472 6.565 83.496 ;
     RECT  6.545 84.72 6.565 87.384 ;
     RECT  6.185 81.312 6.613 82.296 ;
     RECT  6.565 83.472 6.613 87.384 ;
     RECT  5.893 8.448 6.649 9.048 ;
     RECT  6.565 59.808 6.653 59.832 ;
     RECT  6.145 56.4 6.659 57.384 ;
     RECT  6.257 96.96 6.659 97.56 ;
     RECT  6.613 81.312 6.689 87.384 ;
     RECT  6.613 52.416 6.697 52.44 ;
     RECT  6.659 56.544 6.697 57.384 ;
     RECT  6.541 60.96 6.707 63.096 ;
     RECT  6.659 96.96 6.709 97.512 ;
     RECT  6.361 31.248 6.725 31.512 ;
     RECT  6.709 96.912 6.725 97.512 ;
     RECT  6.541 51.168 6.761 51.192 ;
     RECT  6.505 72.144 6.761 72.168 ;
     RECT  6.217 22.464 6.793 22.776 ;
     RECT  6.325 90.624 6.793 91.896 ;
     RECT  6.577 95.472 6.805 95.496 ;
     RECT  6.725 96.912 6.805 97.32 ;
     RECT  6.541 16.656 6.829 18.6 ;
     RECT  6.725 31.392 6.829 31.512 ;
     RECT  6.793 90.576 6.829 91.896 ;
     RECT  5.497 92.928 6.829 93.432 ;
     RECT  6.109 46.752 6.841 46.776 ;
     RECT  6.829 16.608 6.901 18.6 ;
     RECT  6.041 76.752 6.901 77.592 ;
     RECT  5.843 78.624 6.901 80.088 ;
     RECT  6.541 1.68 7.043 7.416 ;
     RECT  5.717 94.416 7.093 94.44 ;
     RECT  6.805 95.472 7.093 97.32 ;
     RECT  6.469 21.408 7.117 21.48 ;
     RECT  6.293 49.824 7.153 49.848 ;
     RECT  6.689 81.312 7.153 83.064 ;
     RECT  6.829 90.576 7.153 93.432 ;
     RECT  7.093 94.416 7.153 97.32 ;
     RECT  7.045 37.92 7.189 37.944 ;
     RECT  7.117 20.16 7.225 20.184 ;
     RECT  6.181 27.696 7.297 27.912 ;
     RECT  7.189 37.056 7.297 37.944 ;
     RECT  6.109 71.136 7.297 71.16 ;
     RECT  6.469 55.152 7.369 55.176 ;
     RECT  7.043 1.728 7.405 7.416 ;
     RECT  6.649 8.448 7.405 9.096 ;
     RECT  7.117 21.168 7.405 21.48 ;
     RECT  6.793 22.464 7.405 22.824 ;
     RECT  6.901 76.752 7.405 80.088 ;
     RECT  5.645 69.696 7.436 70.104 ;
     RECT  5.141 26.256 7.441 26.28 ;
     RECT  7.297 27.696 7.441 27.96 ;
     RECT  4.349 35.712 7.441 35.736 ;
     RECT  7.297 37.056 7.441 38.808 ;
     RECT  7.441 35.712 7.477 38.808 ;
     RECT  6.509 32.976 7.513 33 ;
     RECT  7.441 67.776 7.513 67.8 ;
     RECT  6.257 98.64 7.573 98.664 ;
     RECT  7.513 32.976 7.585 33.288 ;
     RECT  6.707 61.056 7.585 63.096 ;
     RECT  6.221 88.896 7.585 88.92 ;
     RECT  7.153 49.824 7.621 50.04 ;
     RECT  7.585 88.704 7.621 88.92 ;
     RECT  7.477 0.096 7.628 0.12 ;
     RECT  7.225 20.064 7.657 20.184 ;
     RECT  7.405 21.168 7.657 22.824 ;
     RECT  7.513 67.776 7.657 68.664 ;
     RECT  7.436 69.648 7.657 70.104 ;
     RECT  7.573 98.64 7.669 99.096 ;
     RECT  7.549 45.744 7.693 45.768 ;
     RECT  7.477 72.96 7.693 73.032 ;
     RECT  7.628 0.096 7.715 0.552 ;
     RECT  7.715 0.096 7.805 0.36 ;
     RECT  7.405 1.728 7.808 9.096 ;
     RECT  6.181 11.52 7.808 15.528 ;
     RECT  6.901 16.56 7.808 18.6 ;
     RECT  7.657 20.064 7.808 22.824 ;
     RECT  6.505 23.808 7.808 24.936 ;
     RECT  7.441 26.256 7.808 27.96 ;
     RECT  5.753 29.328 7.808 30.072 ;
     RECT  6.829 31.392 7.808 31.8 ;
     RECT  7.585 32.976 7.808 34.152 ;
     RECT  7.477 35.712 7.808 39 ;
     RECT  5.857 41.76 7.808 42.744 ;
     RECT  4.636 44.688 7.808 44.712 ;
     RECT  7.693 45.744 7.808 46.248 ;
     RECT  6.293 48.672 7.808 48.696 ;
     RECT  7.621 49.824 7.808 50.664 ;
     RECT  7.333 53.808 7.808 53.832 ;
     RECT  7.369 55.152 7.808 55.512 ;
     RECT  6.697 56.832 7.808 57.384 ;
     RECT  7.585 61.056 7.808 63.624 ;
     RECT  7.657 67.776 7.808 70.104 ;
     RECT  7.297 71.136 7.808 71.928 ;
     RECT  7.693 72.96 7.808 73.128 ;
     RECT  7.405 75.84 7.808 80.088 ;
     RECT  7.153 81.168 7.808 83.064 ;
     RECT  6.689 84.192 7.808 87.384 ;
     RECT  7.621 88.704 7.808 89.544 ;
     RECT  7.153 90.576 7.808 97.32 ;
     RECT  7.669 98.64 7.907 99.24 ;
     RECT  7.808 1.728 8.053 97.32 ;
     RECT  8.053 1.728 8.104 97.368 ;
     RECT  8.104 97.296 8.129 97.368 ;
     RECT  8.129 97.344 8.149 97.368 ;
     RECT  8.104 10.464 8.165 15.528 ;
     RECT  7.907 99.12 8.195 99.24 ;
     RECT  8.104 22.8 8.201 24.936 ;
     RECT  8.104 33.264 8.201 34.152 ;
     RECT  8.104 36.24 8.201 36.648 ;
     RECT  8.104 80.064 8.237 87.384 ;
     RECT  8.104 1.728 8.291 9.048 ;
     RECT  8.104 49.824 8.304 53.112 ;
     RECT  8.304 50.832 8.309 53.112 ;
     RECT  8.104 90.864 8.309 96.264 ;
     RECT  8.201 33.264 8.345 33.624 ;
     RECT  8.309 51.216 8.345 53.112 ;
     RECT  8.309 92.64 8.381 96.264 ;
     RECT  7.805 0.144 8.425 0.36 ;
     RECT  8.425 0.192 8.453 0.36 ;
     RECT  8.104 16.608 8.453 21.72 ;
     RECT  8.453 0.192 8.483 0.312 ;
     RECT  8.345 51.216 8.489 52.44 ;
     RECT  8.483 0.192 8.497 0.216 ;
     RECT  8.104 26.256 8.525 27.912 ;
     RECT  8.237 80.064 8.561 87 ;
     RECT  8.149 97.344 8.561 97.464 ;
     RECT  8.561 80.064 8.579 85.944 ;
     RECT  8.165 15.504 8.597 15.528 ;
     RECT  8.453 16.608 8.597 21.432 ;
     RECT  8.579 81.84 8.597 85.944 ;
     RECT  8.597 17.904 8.633 21.432 ;
     RECT  8.201 36.24 8.669 36.6 ;
     RECT  8.165 10.464 8.705 14.472 ;
     RECT  8.579 80.064 8.705 80.664 ;
     RECT  8.633 17.904 8.741 18.552 ;
     RECT  8.201 22.8 8.741 24.312 ;
     RECT  8.525 27.696 8.777 27.912 ;
     RECT  8.777 27.696 8.813 27.72 ;
     RECT  8.104 54.672 8.849 55.512 ;
     RECT  8.741 18.192 8.885 18.552 ;
     RECT  8.104 56.592 8.885 57.336 ;
     RECT  8.309 90.864 8.885 91.08 ;
     RECT  8.885 18.192 8.993 18.456 ;
     RECT  8.489 51.696 8.993 52.44 ;
     RECT  8.104 47.856 9.029 47.88 ;
     RECT  8.885 56.592 9.029 56.904 ;
     RECT  8.195 99.168 9.029 99.24 ;
     RECT  8.849 55.008 9.101 55.512 ;
     RECT  8.104 74.208 9.101 74.664 ;
     RECT  8.741 22.8 9.109 23.016 ;
     RECT  8.104 60.96 9.133 63.816 ;
     RECT  9.029 56.592 9.137 56.616 ;
     RECT  8.633 19.536 9.155 21.432 ;
     RECT  9.155 19.536 9.173 21.144 ;
     RECT  8.104 28.992 9.173 30.36 ;
     RECT  9.173 29.088 9.209 30.36 ;
     RECT  9.029 99.216 9.209 99.24 ;
     RECT  8.597 16.608 9.245 16.824 ;
     RECT  8.993 18.192 9.245 18.216 ;
     RECT  9.097 34.752 9.245 34.776 ;
     RECT  8.597 81.84 9.245 85.224 ;
     RECT  8.561 86.976 9.277 87 ;
     RECT  8.104 88.704 9.277 88.728 ;
     RECT  9.109 22.752 9.281 23.016 ;
     RECT  8.104 44.688 9.317 46.248 ;
     RECT  9.133 60.816 9.349 63.816 ;
     RECT  9.101 74.352 9.353 74.664 ;
     RECT  8.104 66.576 9.385 66.6 ;
     RECT  9.353 74.496 9.389 74.664 ;
     RECT  8.104 65.04 9.421 65.064 ;
     RECT  8.705 11.424 9.425 14.472 ;
     RECT  8.561 97.344 9.425 97.368 ;
     RECT  8.741 24.192 9.453 24.312 ;
     RECT  8.345 33.6 9.461 33.624 ;
     RECT  9.389 74.592 9.461 74.664 ;
     RECT  8.705 80.064 9.493 80.136 ;
     RECT  8.104 68.64 9.529 70.008 ;
     RECT  9.421 75.648 9.529 75.672 ;
     RECT  8.885 90.864 9.529 90.888 ;
     RECT  9.209 29.328 9.565 30.36 ;
     RECT  8.104 31.44 9.565 31.608 ;
     RECT  8.104 71.088 9.569 72.12 ;
     RECT  9.529 74.976 9.641 75.672 ;
     RECT  8.104 77.376 9.665 78.408 ;
     RECT  9.425 11.424 9.673 14.232 ;
     RECT  8.381 92.64 9.673 95.784 ;
     RECT  9.569 71.088 9.677 72.024 ;
     RECT  9.493 79.44 9.685 80.136 ;
     RECT  9.665 76.704 9.709 78.408 ;
     RECT  9.685 79.44 9.709 80.76 ;
     RECT  9.673 92.064 9.709 95.784 ;
     RECT  9.453 24.288 9.713 24.312 ;
     RECT  8.525 26.256 9.713 26.28 ;
     RECT  9.349 60.816 9.713 63.864 ;
     RECT  9.641 75.12 9.731 75.672 ;
     RECT  9.421 64.992 9.749 65.064 ;
     RECT  8.291 2.88 9.781 9.048 ;
     RECT  9.245 81.84 9.785 83.256 ;
     RECT  9.529 90.192 9.785 90.888 ;
     RECT  9.245 16.608 9.817 16.68 ;
     RECT  8.669 36.24 9.817 36.552 ;
     RECT  9.385 66.576 9.817 67.08 ;
     RECT  9.781 2.88 9.821 9.192 ;
     RECT  9.709 92.064 9.853 96.264 ;
     RECT  9.673 10.608 9.857 14.232 ;
     RECT  9.173 19.536 9.857 21.096 ;
     RECT  8.104 59.568 9.877 59.592 ;
     RECT  9.713 60.816 9.877 63.768 ;
     RECT  9.709 76.704 9.889 80.76 ;
     RECT  9.785 81.84 9.889 82.2 ;
     RECT  9.877 59.568 9.893 63.768 ;
     RECT  9.817 15.936 9.965 16.68 ;
     RECT  9.889 76.704 9.965 82.2 ;
     RECT  9.893 59.568 9.997 63.624 ;
     RECT  9.853 92.016 9.997 96.264 ;
     RECT  9.997 59.52 10.001 63.624 ;
     RECT  9.997 91.872 10.021 96.264 ;
     RECT  9.857 10.608 10.033 13.08 ;
     RECT  8.291 1.728 10.044 1.8 ;
     RECT  10.069 18 10.105 18.024 ;
     RECT  9.857 14.208 10.109 14.232 ;
     RECT  9.817 66.24 10.145 67.08 ;
     RECT  9.965 76.704 10.145 79.752 ;
     RECT  9.565 29.328 10.177 31.608 ;
     RECT  9.317 44.688 10.217 46.152 ;
     RECT  10.001 60.864 10.217 63.624 ;
     RECT  9.785 83.232 10.249 83.256 ;
     RECT  9.245 84.288 10.249 84.936 ;
     RECT  10.217 46.128 10.289 46.152 ;
     RECT  8.993 51.888 10.289 52.44 ;
     RECT  10.217 60.912 10.289 63.624 ;
     RECT  9.853 38.16 10.321 38.184 ;
     RECT  9.785 90.528 10.321 90.888 ;
     RECT  10.021 91.872 10.321 96.36 ;
     RECT  9.817 36.24 10.325 36.984 ;
     RECT  9.101 55.008 10.361 55.272 ;
     RECT  10.321 90.528 10.361 96.36 ;
     RECT  10.177 28.944 10.393 31.608 ;
     RECT  9.853 73.008 10.393 73.032 ;
     RECT  10.289 60.912 10.397 63.24 ;
     RECT  10.044 1.728 10.501 1.848 ;
     RECT  10.001 59.52 10.505 59.544 ;
     RECT  10.249 83.232 10.505 84.936 ;
     RECT  10.105 17.904 10.537 18.024 ;
     RECT  9.997 27.36 10.537 27.384 ;
     RECT  10.325 36.288 10.573 36.984 ;
     RECT  10.321 38.16 10.573 38.712 ;
     RECT  10.145 76.704 10.573 77.592 ;
     RECT  10.465 33.888 10.613 33.912 ;
     RECT  10.573 36.288 10.613 38.712 ;
     RECT  10.537 17.088 10.645 18.024 ;
     RECT  10.145 66.576 10.681 67.08 ;
     RECT  10.537 27.36 10.717 27.432 ;
     RECT  10.393 28.752 10.717 31.608 ;
     RECT  9.965 80.736 10.721 82.2 ;
     RECT  10.717 27.36 10.753 31.608 ;
     RECT  10.393 32.784 10.753 32.808 ;
     RECT  10.645 17.088 10.757 18.168 ;
     RECT  9.965 15.936 10.789 16.008 ;
     RECT  10.357 42.768 10.789 42.792 ;
     RECT  10.285 47.904 10.789 47.928 ;
     RECT  10.789 42.768 10.825 42.984 ;
     RECT  9.749 65.04 10.825 65.064 ;
     RECT  10.721 81.648 10.829 82.2 ;
     RECT  10.789 47.232 10.835 47.928 ;
     RECT  9.857 19.776 10.861 21.096 ;
     RECT  10.753 27.36 10.865 32.808 ;
     RECT  10.609 54.144 10.865 54.168 ;
     RECT  10.865 27.36 10.901 27.816 ;
     RECT  10.825 42.24 10.901 42.984 ;
     RECT  10.753 56.832 10.901 56.856 ;
     RECT  10.861 19.2 10.933 21.096 ;
     RECT  10.865 28.944 10.937 32.808 ;
     RECT  10.835 47.232 10.937 47.688 ;
     RECT  10.361 90.528 10.937 96.264 ;
     RECT  10.937 32.784 10.973 32.808 ;
     RECT  10.933 19.2 11.017 21.672 ;
     RECT  10.825 35.136 11.081 35.16 ;
     RECT  10.289 52.416 11.113 52.44 ;
     RECT  10.613 36.288 11.117 37.608 ;
     RECT  11.113 52.416 11.123 53.256 ;
     RECT  11.036 57.696 11.123 57.72 ;
     RECT  8.304 49.824 11.149 49.848 ;
     RECT  10.901 27.36 11.185 27.72 ;
     RECT  10.501 1.728 11.221 1.896 ;
     RECT  10.393 73.008 11.269 73.464 ;
     RECT  9.731 75.12 11.315 75.144 ;
     RECT  11.221 1.728 11.333 1.944 ;
     RECT  9.821 3.072 11.333 9.192 ;
     RECT  10.825 64.992 11.333 65.064 ;
     RECT  10.681 66.576 11.333 67.464 ;
     RECT  9.277 86.976 11.333 88.728 ;
     RECT  10.397 61.152 11.365 63.24 ;
     RECT  10.033 10.368 11.401 13.08 ;
     RECT  10.937 28.944 11.405 31.512 ;
     RECT  9.529 68.64 11.437 70.104 ;
     RECT  9.677 71.088 11.437 71.976 ;
     RECT  11.401 10.368 11.441 13.992 ;
     RECT  11.185 27.12 11.473 27.72 ;
     RECT  11.405 28.944 11.477 30.744 ;
     RECT  10.757 17.136 11.509 18.168 ;
     RECT  11.017 19.2 11.509 21.096 ;
     RECT  11.333 4.56 11.516 9.192 ;
     RECT  11.365 61.056 11.545 63.24 ;
     RECT  11.437 68.64 11.545 71.976 ;
     RECT  11.269 73.008 11.545 73.512 ;
     RECT  9.281 22.752 11.557 22.776 ;
     RECT  11.473 26.928 11.581 27.72 ;
     RECT  11.333 86.976 11.593 87.672 ;
     RECT  11.516 4.56 11.603 10.344 ;
     RECT  11.603 4.56 11.621 9.144 ;
     RECT  10.789 15.264 11.657 16.008 ;
     RECT  11.557 22.752 11.657 22.824 ;
     RECT  10.901 42.24 11.689 42.264 ;
     RECT  10.361 55.248 11.689 55.272 ;
     RECT  11.441 11.376 11.693 13.992 ;
     RECT  11.509 17.136 11.725 21.096 ;
     RECT  10.829 82.176 11.725 82.2 ;
     RECT  10.505 83.232 11.725 84.312 ;
     RECT  11.545 68.64 11.747 73.512 ;
     RECT  11.581 26.784 11.801 27.72 ;
     RECT  11.333 67.44 11.801 67.464 ;
     RECT  11.689 42.192 11.833 42.264 ;
     RECT  11.657 15.264 11.837 15.864 ;
     RECT  11.693 11.52 11.843 13.992 ;
     RECT  11.801 27.696 11.869 27.72 ;
     RECT  11.725 17.04 11.873 21.096 ;
     RECT  11.747 70.704 11.873 73.512 ;
     RECT  11.873 18 11.881 21.096 ;
     RECT  11.657 22.752 11.909 22.776 ;
     RECT  10.937 47.664 11.941 47.688 ;
     RECT  11.077 59.856 11.941 59.88 ;
     RECT  11.545 61.056 11.941 63.528 ;
     RECT  11.593 86.976 11.977 87.48 ;
     RECT  11.843 11.52 11.981 13.56 ;
     RECT  11.837 15.504 11.981 15.864 ;
     RECT  11.477 29.28 11.981 30.744 ;
     RECT  11.725 82.176 12.013 84.312 ;
     RECT  11.981 12.288 12.017 13.56 ;
     RECT  11.689 55.2 12.017 55.272 ;
     RECT  11.873 70.704 12.017 73.272 ;
     RECT  11.941 59.856 12.025 63.528 ;
     RECT  10.573 76.128 12.035 77.592 ;
     RECT  11.981 15.504 12.053 15.768 ;
     RECT  12.013 81.936 12.085 84.312 ;
     RECT  11.833 85.68 12.085 85.704 ;
     RECT  11.881 19.2 12.089 21.096 ;
     RECT  11.653 64.896 12.157 64.92 ;
     RECT  11.977 80.88 12.157 80.904 ;
     RECT  12.085 81.936 12.157 85.704 ;
     RECT  12.025 61.44 12.161 63.528 ;
     RECT  10.613 38.688 12.229 38.712 ;
     RECT  11.123 53.232 12.229 53.256 ;
     RECT  11.977 86.832 12.229 87.48 ;
     RECT  12.121 33.84 12.233 33.864 ;
     RECT  12.017 70.704 12.233 72.264 ;
     RECT  11.833 42.096 12.301 42.264 ;
     RECT  12.229 53.232 12.301 53.304 ;
     RECT  10.937 90.528 12.337 95.784 ;
     RECT  11.869 43.536 12.409 43.56 ;
     RECT  12.301 53.088 12.409 53.304 ;
     RECT  12.337 90.528 12.409 96.264 ;
     RECT  12.157 64.656 12.553 64.92 ;
     RECT  10.145 79.248 12.553 79.752 ;
     RECT  12.157 80.88 12.553 85.704 ;
     RECT  11.333 3.072 12.565 3.576 ;
     RECT  11.621 4.56 12.565 9.096 ;
     RECT  12.565 3.072 12.581 9.096 ;
     RECT  11.333 1.728 12.697 1.8 ;
     RECT  12.581 2.832 12.697 9.096 ;
     RECT  12.697 1.728 12.812 9.096 ;
     RECT  11.603 10.32 12.812 10.344 ;
     RECT  12.301 41.376 12.841 42.264 ;
     RECT  12.409 43.248 12.841 43.56 ;
     RECT  12.229 38.496 12.877 38.712 ;
     RECT  12.877 38.496 12.949 38.808 ;
     RECT  11.869 39.792 12.949 39.816 ;
     RECT  12.161 62.736 13.021 63.528 ;
     RECT  12.553 64.656 13.021 65.064 ;
     RECT  12.229 86.784 13.045 87.48 ;
     RECT  11.333 88.704 13.045 88.728 ;
     RECT  12.089 19.872 13.093 21.096 ;
     RECT  12.949 38.496 13.093 39.816 ;
     RECT  11.747 68.64 13.093 69.528 ;
     RECT  12.553 79.248 13.093 85.704 ;
     RECT  13.045 86.784 13.093 88.728 ;
     RECT  11.149 49.248 13.165 49.848 ;
     RECT  13.021 62.736 13.201 65.064 ;
     RECT  12.913 66.288 13.201 66.312 ;
     RECT  12.812 1.728 13.208 10.344 ;
     RECT  12.017 12.288 13.208 13.032 ;
     RECT  12.913 15.312 13.208 15.336 ;
     RECT  11.881 18 13.208 18.024 ;
     RECT  13.093 19.056 13.208 21.096 ;
     RECT  12.049 25.728 13.208 25.752 ;
     RECT  11.869 27.696 13.208 27.912 ;
     RECT  11.981 30.048 13.208 30.744 ;
     RECT  12.553 34.8 13.208 34.824 ;
     RECT  11.117 36.288 13.208 37.08 ;
     RECT  13.093 38.16 13.208 39.816 ;
     RECT  12.841 41.376 13.208 43.56 ;
     RECT  10.217 44.688 13.208 44.712 ;
     RECT  12.877 45.696 13.208 45.72 ;
     RECT  11.941 46.896 13.208 47.688 ;
     RECT  13.165 48.672 13.208 49.848 ;
     RECT  12.409 52.8 13.208 53.304 ;
     RECT  12.017 55.2 13.208 55.224 ;
     RECT  12.025 59.856 13.208 59.88 ;
     RECT  12.161 61.44 13.208 61.464 ;
     RECT  13.201 62.736 13.208 66.312 ;
     RECT  13.093 68.208 13.208 69.528 ;
     RECT  12.233 70.896 13.208 72.264 ;
     RECT  12.017 73.248 13.208 73.272 ;
     RECT  11.977 74.4 13.208 74.472 ;
     RECT  12.035 76.512 13.208 76.584 ;
     RECT  12.035 77.568 13.208 77.592 ;
     RECT  13.093 79.248 13.208 88.728 ;
     RECT  12.409 90.336 13.208 96.264 ;
     RECT  13.208 1.728 13.312 97.212 ;
     RECT  12.757 0.144 13.429 0.168 ;
     RECT  13.312 1.728 13.504 96.942 ;
     RECT  13.429 0.144 13.525 0.36 ;
     RECT  13.504 53.376 13.565 53.4 ;
     RECT  13.504 62.976 13.565 66.744 ;
     RECT  13.504 55.2 13.601 55.224 ;
     RECT  13.504 83.424 13.601 87.384 ;
     RECT  13.504 18 13.619 19.08 ;
     RECT  13.504 24.624 13.619 24.648 ;
     RECT  13.601 83.424 13.619 85.416 ;
     RECT  13.601 86.448 13.637 87.384 ;
     RECT  13.504 45.552 13.667 45.576 ;
     RECT  13.504 90.048 13.673 92.28 ;
     RECT  13.504 44.352 13.708 44.568 ;
     RECT  13.637 86.832 13.709 87.384 ;
     RECT  13.504 1.728 13.715 1.8 ;
     RECT  13.525 0.144 13.741 0.456 ;
     RECT  13.504 57.504 13.745 57.528 ;
     RECT  13.673 91.584 13.745 92.28 ;
     RECT  13.504 34.752 13.763 37.128 ;
     RECT  13.504 77.568 13.781 80.904 ;
     RECT  13.763 34.752 13.804 36.12 ;
     RECT  13.741 0.144 13.813 0.552 ;
     RECT  13.504 75.408 13.817 76.536 ;
     RECT  13.619 83.424 14.033 83.544 ;
     RECT  13.813 0.096 14.051 0.552 ;
     RECT  14.033 83.52 14.069 83.544 ;
     RECT  13.619 84.96 14.069 85.416 ;
     RECT  13.504 60.72 14.092 61.272 ;
     RECT  13.708 44.352 14.105 44.376 ;
     RECT  13.504 41.04 14.141 42.792 ;
     RECT  14.141 41.04 14.285 42.504 ;
     RECT  13.504 22.128 14.291 23.544 ;
     RECT  13.781 77.568 14.339 79.752 ;
     RECT  13.504 88.704 14.357 88.92 ;
     RECT  13.504 96.144 14.357 96.936 ;
     RECT  14.051 0.096 14.429 0.168 ;
     RECT  13.504 10.416 14.497 11.16 ;
     RECT  13.504 12.768 14.497 12.888 ;
     RECT  13.504 30 14.497 30.6 ;
     RECT  13.504 82.272 14.497 82.44 ;
     RECT  13.504 3.072 14.501 9.144 ;
     RECT  14.285 41.04 14.533 42.264 ;
     RECT  13.804 34.752 14.537 35.88 ;
     RECT  13.504 33.648 14.573 33.672 ;
     RECT  14.537 34.752 14.579 35.688 ;
     RECT  14.339 78.192 14.579 78.216 ;
     RECT  13.817 75.792 14.581 76.344 ;
     RECT  13.504 13.92 14.605 15.336 ;
     RECT  13.504 28.656 14.605 28.68 ;
     RECT  13.619 18 14.609 18.552 ;
     RECT  14.501 6.528 14.641 9.144 ;
     RECT  14.497 10.416 14.641 12.888 ;
     RECT  13.504 93.312 14.677 93.336 ;
     RECT  14.605 27.888 14.689 28.68 ;
     RECT  13.504 46.896 14.713 47.544 ;
     RECT  13.504 48.672 14.713 49.848 ;
     RECT  13.504 70.656 14.713 72.216 ;
     RECT  13.504 73.392 14.713 73.416 ;
     RECT  14.429 0.144 14.717 0.168 ;
     RECT  14.497 30 14.723 31.368 ;
     RECT  14.713 46.896 14.753 49.848 ;
     RECT  13.565 63.072 14.76 66.744 ;
     RECT  14.689 28.656 14.773 28.68 ;
     RECT  14.723 30 14.773 30.168 ;
     RECT  14.713 70.656 14.785 73.416 ;
     RECT  14.497 74.592 14.785 74.616 ;
     RECT  13.504 94.32 14.785 94.872 ;
     RECT  14.641 6.528 14.789 12.888 ;
     RECT  13.504 38.16 14.789 38.52 ;
     RECT  14.357 96.48 14.819 96.936 ;
     RECT  14.76 62.688 14.821 66.744 ;
     RECT  13.504 67.824 14.821 69.528 ;
     RECT  13.709 87.024 14.821 87.384 ;
     RECT  14.785 94.32 14.821 94.968 ;
     RECT  14.579 34.752 14.857 34.776 ;
     RECT  14.789 38.496 14.857 38.52 ;
     RECT  13.504 51.36 14.857 52.008 ;
     RECT  14.069 85.104 14.857 85.416 ;
     RECT  14.677 92.496 14.857 93.336 ;
     RECT  14.821 94.32 14.857 95.16 ;
     RECT  14.819 96.48 14.861 96.84 ;
     RECT  13.715 1.728 14.869 1.752 ;
     RECT  14.821 62.688 14.889 69.528 ;
     RECT  14.773 28.656 14.897 30.168 ;
     RECT  13.504 32.448 14.897 32.472 ;
     RECT  14.857 34.224 14.897 34.776 ;
     RECT  14.889 63.168 14.905 69.528 ;
     RECT  14.869 1.728 14.965 1.8 ;
     RECT  13.504 20.64 15.001 20.664 ;
     RECT  15.001 20.496 15.02 20.664 ;
     RECT  14.605 13.92 15.041 15.672 ;
     RECT  14.929 57.744 15.041 57.768 ;
     RECT  14.965 1.728 15.061 1.848 ;
     RECT  15.041 14.448 15.061 15.672 ;
     RECT  14.339 79.728 15.068 79.752 ;
     RECT  15.02 19.968 15.107 20.664 ;
     RECT  15.068 79.728 15.109 80.184 ;
     RECT  14.497 81.6 15.109 82.44 ;
     RECT  13.673 90.048 15.116 90.36 ;
     RECT  15.109 79.728 15.149 82.44 ;
     RECT  15.149 80.16 15.155 82.44 ;
     RECT  14.905 64.656 15.181 69.528 ;
     RECT  14.857 85.104 15.181 85.464 ;
     RECT  14.857 92.496 15.203 95.16 ;
     RECT  14.965 25.056 15.289 25.08 ;
     RECT  14.785 70.656 15.289 74.616 ;
     RECT  14.581 75.792 15.289 75.816 ;
     RECT  14.753 47.088 15.325 49.848 ;
     RECT  14.857 50.832 15.325 52.008 ;
     RECT  15.181 64.656 15.325 69.576 ;
     RECT  15.289 70.656 15.325 75.816 ;
     RECT  15.116 89.952 15.325 90.36 ;
     RECT  15.181 84.816 15.349 85.464 ;
     RECT  15.325 89.952 15.395 90.504 ;
     RECT  15.061 1.728 15.401 1.896 ;
     RECT  15.217 18.672 15.433 18.696 ;
     RECT  15.325 64.656 15.437 75.816 ;
     RECT  14.861 96.48 15.437 96.504 ;
     RECT  15.289 25.056 15.545 25.272 ;
     RECT  15.325 47.088 15.545 52.008 ;
     RECT  15.155 80.4 15.581 82.44 ;
     RECT  15.203 92.496 15.613 92.52 ;
     RECT  15.397 23.328 15.653 23.352 ;
     RECT  15.545 25.248 15.689 25.272 ;
     RECT  14.533 40.656 15.689 42.264 ;
     RECT  14.092 61.056 15.721 61.272 ;
     RECT  15.361 83.52 15.757 83.544 ;
     RECT  15.349 84.816 15.757 85.512 ;
     RECT  13.763 37.104 15.761 37.128 ;
     RECT  15.721 61.056 15.761 61.56 ;
     RECT  14.501 3.072 15.829 5.496 ;
     RECT  14.789 6.528 15.829 12.792 ;
     RECT  15.433 18.672 15.833 19.032 ;
     RECT  14.905 63.168 15.865 63.576 ;
     RECT  15.757 83.52 15.865 85.512 ;
     RECT  15.581 80.4 15.869 80.712 ;
     RECT  15.581 81.792 15.869 82.44 ;
     RECT  14.897 34.224 15.877 34.248 ;
     RECT  15.545 47.088 15.901 47.88 ;
     RECT  15.901 46.848 15.905 47.88 ;
     RECT  15.905 46.848 15.941 47.736 ;
     RECT  15.869 81.984 15.973 82.44 ;
     RECT  15.865 83.52 15.973 85.704 ;
     RECT  15.401 1.728 15.977 1.848 ;
     RECT  14.357 88.704 16.013 88.728 ;
     RECT  15.761 61.536 16.021 61.56 ;
     RECT  15.865 62.64 16.021 63.576 ;
     RECT  15.437 64.656 16.021 69.576 ;
     RECT  15.757 57.6 16.045 57.624 ;
     RECT  15.973 81.984 16.049 85.704 ;
     RECT  16.045 57.552 16.081 57.624 ;
     RECT  16.049 85.104 16.081 85.704 ;
     RECT  14.821 86.688 16.081 87.384 ;
     RECT  15.437 70.656 16.085 75.816 ;
     RECT  15.613 92.16 16.085 92.52 ;
     RECT  15.829 3.072 16.121 12.792 ;
     RECT  16.021 61.536 16.157 69.576 ;
     RECT  16.049 81.984 16.157 84.12 ;
     RECT  14.857 38.496 16.189 38.712 ;
     RECT  16.121 6.48 16.193 12.792 ;
     RECT  16.189 44.88 16.225 44.904 ;
     RECT  15.941 46.848 16.265 47.544 ;
     RECT  15.545 48.96 16.297 52.008 ;
     RECT  16.157 67.536 16.3 69.576 ;
     RECT  15.689 40.656 16.301 41.928 ;
     RECT  16.121 3.072 16.309 5.448 ;
     RECT  15.793 53.856 16.333 53.88 ;
     RECT  16.297 26.88 16.369 26.904 ;
     RECT  14.897 29.472 16.373 30.168 ;
     RECT  16.085 70.656 16.373 75.672 ;
     RECT  16.373 70.656 16.409 73.08 ;
     RECT  16.3 68.16 16.441 69.576 ;
     RECT  16.409 70.656 16.441 73.032 ;
     RECT  16.297 48.96 16.445 52.2 ;
     RECT  15.061 14.448 16.477 16.536 ;
     RECT  16.373 30.144 16.481 30.168 ;
     RECT  16.369 26.832 16.517 27.384 ;
     RECT  15.203 93.888 16.517 95.16 ;
     RECT  15.107 20.496 16.589 20.52 ;
     RECT  16.189 37.584 16.589 38.712 ;
     RECT  16.225 44.88 16.589 45.816 ;
     RECT  16.477 14.112 16.604 16.536 ;
     RECT  16.604 13.872 16.621 16.536 ;
     RECT  15.685 17.616 16.621 17.64 ;
     RECT  16.517 26.832 16.621 27.096 ;
     RECT  16.157 83.52 16.622 84.12 ;
     RECT  16.309 2.88 16.652 5.448 ;
     RECT  16.157 81.984 16.661 82.44 ;
     RECT  15.395 90.096 16.693 90.504 ;
     RECT  16.589 44.88 16.697 44.904 ;
     RECT  16.193 6.912 16.757 12.792 ;
     RECT  16.621 13.872 16.757 17.64 ;
     RECT  16.157 61.536 16.769 66.36 ;
     RECT  16.757 6.912 16.789 17.64 ;
     RECT  15.833 18.672 16.789 18.696 ;
     RECT  16.445 48.96 16.841 51.72 ;
     RECT  16.841 48.96 16.873 51.144 ;
     RECT  16.333 53.52 16.873 53.88 ;
     RECT  15.685 78.432 16.873 78.456 ;
     RECT  16.622 83.568 16.877 84.12 ;
     RECT  16.789 6.912 16.913 18.696 ;
     RECT  16.661 82.272 16.913 82.44 ;
     RECT  16.301 40.656 16.945 41.112 ;
     RECT  16.517 95.136 16.945 95.16 ;
     RECT  16.873 78 16.949 78.456 ;
     RECT  16.589 38.4 16.981 38.712 ;
     RECT  16.949 78 16.985 78.024 ;
     RECT  16.517 93.888 16.985 93.912 ;
     RECT  16.945 95.136 16.985 95.928 ;
     RECT  16.981 34.608 17.068 34.632 ;
     RECT  15.977 1.728 17.077 1.752 ;
     RECT  16.981 33.072 17.077 33.096 ;
     RECT  16.873 53.424 17.089 53.88 ;
     RECT  16.769 61.536 17.093 64.68 ;
     RECT  16.877 83.568 17.093 83.592 ;
     RECT  16.945 40.608 17.123 41.112 ;
     RECT  16.373 74.112 17.129 75.672 ;
     RECT  16.621 26.784 17.161 27.096 ;
     RECT  16.693 90.096 17.161 91.176 ;
     RECT  17.077 32.976 17.164 33.096 ;
     RECT  16.981 38.4 17.164 39.288 ;
     RECT  17.077 1.152 17.165 1.752 ;
     RECT  17.161 25.872 17.165 27.096 ;
     RECT  17.123 40.608 17.165 40.68 ;
     RECT  16.769 66 17.165 66.36 ;
     RECT  16.513 60.528 17.197 60.552 ;
     RECT  17.093 61.536 17.197 61.56 ;
     RECT  16.765 28.128 17.201 28.152 ;
     RECT  16.652 2.832 17.229 5.448 ;
     RECT  17.089 53.328 17.237 53.88 ;
     RECT  17.197 60.528 17.237 61.56 ;
     RECT  15.869 80.688 17.237 80.712 ;
     RECT  17.165 40.608 17.273 40.632 ;
     RECT  17.129 74.592 17.273 75.672 ;
     RECT  17.273 75.12 17.276 75.672 ;
     RECT  17.276 75.12 17.305 75.96 ;
     RECT  17.161 89.28 17.305 91.176 ;
     RECT  16.085 92.16 17.305 92.184 ;
     RECT  16.913 6.912 17.309 17.352 ;
     RECT  16.081 57.552 17.317 57.864 ;
     RECT  17.305 59.328 17.317 59.352 ;
     RECT  17.309 12.624 17.345 17.352 ;
     RECT  17.237 60.528 17.363 61.08 ;
     RECT  17.165 1.728 17.365 1.752 ;
     RECT  17.229 2.832 17.365 4.536 ;
     RECT  16.265 46.848 17.377 47.496 ;
     RECT  16.873 48.672 17.377 51.144 ;
     RECT  17.317 57.552 17.377 59.352 ;
     RECT  16.081 85.104 17.377 87.384 ;
     RECT  17.305 89.28 17.377 92.184 ;
     RECT  17.377 85.104 17.417 92.184 ;
     RECT  17.377 57.024 17.489 59.352 ;
     RECT  16.657 30.432 17.521 30.456 ;
     RECT  17.237 53.424 17.521 53.88 ;
     RECT  17.489 58.512 17.521 59.352 ;
     RECT  17.417 86.496 17.521 92.184 ;
     RECT  17.165 25.872 17.557 27.048 ;
     RECT  16.92 35.664 17.593 35.688 ;
     RECT  17.593 35.664 17.633 36.648 ;
     RECT  17.521 86.496 17.701 92.424 ;
     RECT  16.913 82.416 17.737 82.44 ;
     RECT  17.701 86.496 17.737 92.76 ;
     RECT  17.377 46.848 17.845 51.144 ;
     RECT  16.913 18.672 17.881 18.696 ;
     RECT  17.417 85.104 17.941 85.128 ;
     RECT  17.737 33.312 17.953 33.624 ;
     RECT  17.521 30.432 18.025 31.416 ;
     RECT  17.309 6.912 18.097 11.4 ;
     RECT  16.441 68.16 18.133 73.032 ;
     RECT  17.165 66 18.169 66.024 ;
     RECT  18.133 67.488 18.169 73.032 ;
     RECT  18.025 30.432 18.205 32.28 ;
     RECT  17.953 33.312 18.205 34.104 ;
     RECT  18.205 30.432 18.332 34.104 ;
     RECT  18.332 30.432 18.373 34.44 ;
     RECT  17.485 22.08 18.385 22.104 ;
     RECT  16.801 23.52 18.385 23.544 ;
     RECT  17.941 84.432 18.385 85.128 ;
     RECT  17.737 82.416 18.457 83.256 ;
     RECT  18.385 84.432 18.457 85.512 ;
     RECT  17.305 75.12 18.469 76.392 ;
     RECT  18.097 6.864 18.493 11.4 ;
     RECT  17.164 38.4 18.565 38.712 ;
     RECT  17.365 1.728 18.608 4.536 ;
     RECT  18.493 6.288 18.608 11.4 ;
     RECT  17.345 12.624 18.608 16.92 ;
     RECT  17.881 18.672 18.608 19.032 ;
     RECT  18.385 22.08 18.608 23.544 ;
     RECT  17.593 24.768 18.608 24.792 ;
     RECT  17.557 25.776 18.608 27.048 ;
     RECT  17.953 28.416 18.608 28.44 ;
     RECT  18.373 30.432 18.608 34.68 ;
     RECT  17.633 35.712 18.608 36.648 ;
     RECT  18.565 38.16 18.608 38.712 ;
     RECT  18.349 40.896 18.608 40.92 ;
     RECT  17.845 46.8 18.608 51.144 ;
     RECT  17.521 53.424 18.608 54.408 ;
     RECT  17.489 57.024 18.608 57.192 ;
     RECT  17.521 58.512 18.608 59.64 ;
     RECT  17.093 62.64 18.608 64.68 ;
     RECT  18.169 66 18.608 73.032 ;
     RECT  18.469 74.4 18.608 76.392 ;
     RECT  17.125 79.056 18.608 79.08 ;
     RECT  18.601 80.112 18.608 80.136 ;
     RECT  18.457 82.416 18.608 85.512 ;
     RECT  17.737 86.496 18.608 93.048 ;
     RECT  16.985 95.904 18.608 95.928 ;
     RECT  18.608 1.728 18.712 97.212 ;
     RECT  18.712 1.728 18.904 96.942 ;
     RECT  18.904 87.936 18.929 94.632 ;
     RECT  18.904 77.76 18.965 80.136 ;
     RECT  18.904 82.416 18.965 85.512 ;
     RECT  18.904 3.024 19.001 16.392 ;
     RECT  18.904 40.896 19.001 41.4 ;
     RECT  19.001 41.376 19.037 41.4 ;
     RECT  18.904 86.592 19.073 86.856 ;
     RECT  18.965 82.416 19.181 85.128 ;
     RECT  18.904 24.096 19.261 24.504 ;
     RECT  18.904 62.544 19.276 69.96 ;
     RECT  18.929 87.936 19.361 91.368 ;
     RECT  18.904 25.632 19.369 27.48 ;
     RECT  18.904 59.184 19.379 59.208 ;
     RECT  19.001 3.024 19.397 10.872 ;
     RECT  18.904 51.984 19.427 53.784 ;
     RECT  19.349 0.096 19.433 0.12 ;
     RECT  18.904 30.048 19.469 36.024 ;
     RECT  19.073 86.592 19.505 86.616 ;
     RECT  18.904 21.744 19.541 22.584 ;
     RECT  18.904 37.152 19.541 38.808 ;
     RECT  19.361 88.56 19.577 91.368 ;
     RECT  18.904 46.176 19.613 50.952 ;
     RECT  19.577 88.752 19.613 91.368 ;
     RECT  18.904 1.728 19.649 1.944 ;
     RECT  19.469 30.048 19.649 33.624 ;
     RECT  19.261 24.096 19.685 24.12 ;
     RECT  19.613 49.296 19.721 50.952 ;
     RECT  19.181 82.416 19.721 83.64 ;
     RECT  18.929 92.448 19.721 94.632 ;
     RECT  19.721 92.448 19.793 94.104 ;
     RECT  19.721 49.536 19.829 50.952 ;
     RECT  18.965 77.76 19.829 77.88 ;
     RECT  19.397 3.024 19.865 4.536 ;
     RECT  19.001 11.952 19.865 16.392 ;
     RECT  18.965 79.152 19.865 80.136 ;
     RECT  19.369 25.728 19.897 27.48 ;
     RECT  19.649 30.048 19.897 33.528 ;
     RECT  19.469 34.656 19.897 36.024 ;
     RECT  19.541 37.152 19.897 38.712 ;
     RECT  18.904 54.864 19.897 54.888 ;
     RECT  19.397 5.52 19.901 10.872 ;
     RECT  18.904 60.432 19.909 61.224 ;
     RECT  19.909 60.288 19.933 61.224 ;
     RECT  19.276 62.544 19.933 69.528 ;
     RECT  19.865 3.024 19.937 4.248 ;
     RECT  19.829 77.856 19.937 77.88 ;
     RECT  18.904 76.368 19.973 76.392 ;
     RECT  18.904 19.008 20.005 19.032 ;
     RECT  19.865 15.648 20.009 16.392 ;
     RECT  19.897 54.864 20.041 55.176 ;
     RECT  18.904 71.136 20.077 71.832 ;
     RECT  18.904 72.96 20.077 73.56 ;
     RECT  19.793 92.448 20.077 93.336 ;
     RECT  19.829 49.536 20.081 50.04 ;
     RECT  19.937 3.024 20.117 4.104 ;
     RECT  20.005 18.768 20.117 19.032 ;
     RECT  19.181 85.104 20.149 85.128 ;
     RECT  20.117 19.008 20.153 19.032 ;
     RECT  19.865 79.152 20.221 79.272 ;
     RECT  19.901 5.808 20.257 10.872 ;
     RECT  19.865 11.952 20.257 14.136 ;
     RECT  20.009 15.696 20.261 16.392 ;
     RECT  19.897 34.656 20.297 38.712 ;
     RECT  19.897 29.088 20.329 33.528 ;
     RECT  20.257 42.624 20.365 42.648 ;
     RECT  19.427 51.984 20.369 53.016 ;
     RECT  20.221 78.624 20.369 79.272 ;
     RECT  20.117 3.024 20.405 4.008 ;
     RECT  20.329 28.8 20.405 33.528 ;
     RECT  19.933 60.288 20.441 69.528 ;
     RECT  20.365 20.112 20.473 20.136 ;
     RECT  19.897 25.728 20.473 27.72 ;
     RECT  20.077 71.136 20.473 73.56 ;
     RECT  18.904 74.832 20.473 75.048 ;
     RECT  20.473 25.248 20.477 27.72 ;
     RECT  20.297 34.656 20.477 37.176 ;
     RECT  20.041 54.864 20.54 55.752 ;
     RECT  19.541 21.744 20.549 22.344 ;
     RECT  20.477 25.248 20.549 26.712 ;
     RECT  20.549 25.248 20.581 25.512 ;
     RECT  20.369 51.984 20.581 52.2 ;
     RECT  19.613 88.752 20.581 91.176 ;
     RECT  20.477 27.696 20.585 27.72 ;
     RECT  20.54 54.864 20.617 56.664 ;
     RECT  20.617 54.864 20.627 57.144 ;
     RECT  20.509 87.168 20.689 87.192 ;
     RECT  20.581 88.224 20.689 91.176 ;
     RECT  20.477 34.656 20.693 36.36 ;
     RECT  19.721 82.416 20.693 83.352 ;
     RECT  20.081 49.536 20.725 49.848 ;
     RECT  20.684 0.528 20.771 0.552 ;
     RECT  20.405 28.8 20.837 31.512 ;
     RECT  20.693 34.656 20.837 36.168 ;
     RECT  20.837 28.8 20.869 29.016 ;
     RECT  19.613 46.176 20.869 47.928 ;
     RECT  20.627 54.864 20.869 55.752 ;
     RECT  20.405 32.544 20.873 33.528 ;
     RECT  20.365 42.624 20.873 42.696 ;
     RECT  20.473 95.136 20.873 95.16 ;
     RECT  19.649 1.728 20.88 1.752 ;
     RECT  18.904 58.128 20.905 58.152 ;
     RECT  20.837 34.656 20.909 34.824 ;
     RECT  20.869 54.48 20.909 55.752 ;
     RECT  20.405 3.072 20.915 4.008 ;
     RECT  20.869 28.56 20.915 29.016 ;
     RECT  20.473 71.136 20.945 75.048 ;
     RECT  20.869 77.136 20.977 77.16 ;
     RECT  20.077 81.312 20.977 81.336 ;
     RECT  20.693 82.416 20.977 83.112 ;
     RECT  20.689 87.168 20.977 91.176 ;
     RECT  20.077 92.256 20.977 93.336 ;
     RECT  20.88 1.728 20.981 1.8 ;
     RECT  20.627 56.832 20.981 57.144 ;
     RECT  20.401 39.888 21.013 39.912 ;
     RECT  20.581 51.792 21.017 52.2 ;
     RECT  20.981 57.024 21.017 57.144 ;
     RECT  20.945 73.488 21.017 75.048 ;
     RECT  20.915 28.56 21.053 28.92 ;
     RECT  20.837 30.048 21.053 31.512 ;
     RECT  20.257 5.808 21.085 14.136 ;
     RECT  20.909 54.48 21.085 55.176 ;
     RECT  20.149 85.104 21.085 86.04 ;
     RECT  20.981 1.728 21.089 1.752 ;
     RECT  21.085 54.144 21.109 55.176 ;
     RECT  21.013 17.664 21.125 17.688 ;
     RECT  20.549 22.32 21.125 22.344 ;
     RECT  20.909 34.656 21.125 34.68 ;
     RECT  20.945 71.136 21.125 72.456 ;
     RECT  20.977 87.168 21.125 93.336 ;
     RECT  21.109 53.952 21.155 55.176 ;
     RECT  21.017 51.792 21.157 51.816 ;
     RECT  20.581 24.864 21.161 25.512 ;
     RECT  20.837 35.904 21.161 36.168 ;
     RECT  20.873 42.672 21.161 42.696 ;
     RECT  20.441 60.288 21.161 68.52 ;
     RECT  21.085 5.376 21.193 14.136 ;
     RECT  20.977 81.312 21.197 83.112 ;
     RECT  21.017 74.4 21.269 75.048 ;
     RECT  20.261 15.696 21.301 15.72 ;
     RECT  21.085 84.864 21.301 86.04 ;
     RECT  21.161 35.904 21.341 35.928 ;
     RECT  20.905 58.128 21.373 58.728 ;
     RECT  20.185 23.76 21.377 23.784 ;
     RECT  21.193 5.04 21.409 14.136 ;
     RECT  21.125 87.168 21.413 92.28 ;
     RECT  20.297 38.448 21.445 38.712 ;
     RECT  21.301 15.696 21.449 15.768 ;
     RECT  21.053 28.896 21.449 28.92 ;
     RECT  20.915 3.168 21.481 4.008 ;
     RECT  21.409 5.04 21.481 14.712 ;
     RECT  20.473 19.968 21.485 20.136 ;
     RECT  21.053 30.576 21.517 31.512 ;
     RECT  20.369 79.248 21.553 79.272 ;
     RECT  21.155 55.152 21.557 55.176 ;
     RECT  20.977 76.368 21.589 77.16 ;
     RECT  21.553 78.912 21.589 79.272 ;
     RECT  21.517 30.576 21.593 31.896 ;
     RECT  20.725 49.008 21.593 49.848 ;
     RECT  21.373 58.128 21.593 59.256 ;
     RECT  21.589 76.368 21.593 79.272 ;
     RECT  21.413 87.168 21.593 87.432 ;
     RECT  20.549 26.64 21.733 26.712 ;
     RECT  20.441 69.504 21.737 69.528 ;
     RECT  21.445 38.448 21.769 38.76 ;
     RECT  21.593 31.776 21.773 31.896 ;
     RECT  21.157 50.976 21.773 51.816 ;
     RECT  21.413 88.608 21.773 92.28 ;
     RECT  21.481 3.168 21.809 14.712 ;
     RECT  21.125 93.312 21.809 93.336 ;
     RECT  21.161 66 21.836 68.52 ;
     RECT  21.733 26.64 21.877 26.904 ;
     RECT  21.125 71.136 21.881 71.88 ;
     RECT  21.877 44.208 21.913 44.232 ;
     RECT  20.869 45.552 21.913 47.928 ;
     RECT  21.593 49.44 21.913 49.848 ;
     RECT  21.773 50.976 21.913 51.624 ;
     RECT  21.161 25.248 21.917 25.272 ;
     RECT  21.913 44.208 21.923 47.928 ;
     RECT  21.836 66 21.923 68.664 ;
     RECT  21.593 76.368 21.949 78.936 ;
     RECT  21.923 44.208 21.953 47.592 ;
     RECT  21.013 39.888 21.985 40.056 ;
     RECT  21.769 37.584 22.057 38.76 ;
     RECT  21.985 39.744 22.057 40.056 ;
     RECT  22.057 37.584 22.076 40.056 ;
     RECT  22.076 37.584 22.097 40.44 ;
     RECT  22.097 38.4 22.163 40.44 ;
     RECT  21.809 3.168 22.165 9.528 ;
     RECT  21.449 15.744 22.165 15.768 ;
     RECT  21.593 30.576 22.165 30.6 ;
     RECT  22.093 70.56 22.165 70.584 ;
     RECT  22.165 29.616 22.211 30.6 ;
     RECT  21.625 20.352 22.237 20.472 ;
     RECT  21.953 44.208 22.237 45 ;
     RECT  21.155 53.952 22.237 54.168 ;
     RECT  22.201 94.56 22.237 94.584 ;
     RECT  21.949 75.648 22.259 78.936 ;
     RECT  21.445 80.256 22.261 80.28 ;
     RECT  21.877 26.352 22.277 26.904 ;
     RECT  21.773 88.608 22.277 90.744 ;
     RECT  21.197 82.416 22.307 83.112 ;
     RECT  21.593 58.704 22.309 59.256 ;
     RECT  21.161 60.288 22.309 64.68 ;
     RECT  21.923 66 22.309 68.52 ;
     RECT  22.237 94.32 22.309 95.112 ;
     RECT  22.237 43.248 22.313 45 ;
     RECT  21.269 74.4 22.313 74.664 ;
     RECT  22.259 76.176 22.313 78.936 ;
     RECT  22.313 74.64 22.349 74.664 ;
     RECT  22.313 77.136 22.349 78.936 ;
     RECT  22.277 89.424 22.349 90.744 ;
     RECT  22.129 35.328 22.381 35.352 ;
     RECT  22.381 35.328 22.421 36.12 ;
     RECT  22.309 58.704 22.421 64.68 ;
     RECT  21.809 10.608 22.457 14.712 ;
     RECT  22.313 43.248 22.457 44.664 ;
     RECT  22.421 60.192 22.457 64.68 ;
     RECT  22.165 15.744 22.46 16.008 ;
     RECT  22.129 19.296 22.489 19.368 ;
     RECT  22.237 20.352 22.489 20.76 ;
     RECT  21.773 91.776 22.529 92.28 ;
     RECT  22.46 15.6 22.547 16.008 ;
     RECT  21.881 71.616 22.561 71.88 ;
     RECT  22.021 72.912 22.561 72.936 ;
     RECT  22.211 29.616 22.565 29.64 ;
     RECT  22.529 92.208 22.597 92.28 ;
     RECT  21.301 84.144 22.633 86.04 ;
     RECT  22.349 77.904 22.637 78.936 ;
     RECT  22.261 80.256 22.643 81.24 ;
     RECT  22.597 92.208 22.673 93 ;
     RECT  22.637 77.904 22.681 78.024 ;
     RECT  22.597 22.896 22.705 22.92 ;
     RECT  22.417 56.976 22.705 57 ;
     RECT  22.165 70.224 22.705 70.584 ;
     RECT  22.561 71.616 22.741 72.936 ;
     RECT  22.705 22.896 22.745 23.208 ;
     RECT  22.237 53.472 22.777 54.168 ;
     RECT  22.165 3.12 22.813 9.528 ;
     RECT  21.913 49.44 22.813 51.624 ;
     RECT  22.777 52.896 22.813 54.168 ;
     RECT  21.593 87.408 22.813 87.432 ;
     RECT  22.489 19.056 22.817 20.76 ;
     RECT  22.745 23.184 22.817 23.208 ;
     RECT  22.813 3.12 22.849 9.624 ;
     RECT  22.457 43.248 22.853 43.272 ;
     RECT  22.457 60.384 22.853 64.68 ;
     RECT  22.633 84.096 22.853 86.04 ;
     RECT  22.349 89.472 22.853 90.744 ;
     RECT  22.309 94.32 22.853 95.208 ;
     RECT  21.773 31.776 22.885 31.8 ;
     RECT  22.421 58.704 22.889 58.728 ;
     RECT  22.547 15.984 22.892 16.008 ;
     RECT  22.885 48.432 22.921 48.456 ;
     RECT  22.813 49.44 22.921 54.168 ;
     RECT  22.921 48.432 22.925 54.168 ;
     RECT  22.849 3.072 22.957 9.624 ;
     RECT  22.457 10.608 22.957 14.136 ;
     RECT  22.925 52.32 22.957 54.168 ;
     RECT  22.705 56.976 22.957 57.144 ;
     RECT  22.853 63.36 22.957 64.68 ;
     RECT  22.309 65.904 22.957 68.52 ;
     RECT  22.892 15.984 22.961 16.968 ;
     RECT  22.277 26.352 22.961 26.376 ;
     RECT  22.813 30.72 22.961 30.744 ;
     RECT  22.961 16.944 22.979 16.968 ;
     RECT  22.957 63.36 22.993 68.52 ;
     RECT  22.705 69.552 22.993 70.584 ;
     RECT  22.817 20.064 22.997 20.76 ;
     RECT  22.925 48.432 23.027 51.288 ;
     RECT  21.953 46.176 23.029 47.4 ;
     RECT  22.643 80.256 23.029 80.376 ;
     RECT  22.813 87.408 23.029 88.104 ;
     RECT  22.993 63.36 23.033 70.584 ;
     RECT  22.307 82.992 23.065 83.112 ;
     RECT  22.853 84.096 23.065 85.752 ;
     RECT  23.027 48.432 23.101 48.456 ;
     RECT  22.741 71.616 23.101 73.608 ;
     RECT  22.163 38.4 23.137 39.816 ;
     RECT  22.957 56.976 23.209 57.336 ;
     RECT  23.029 46.128 23.221 47.4 ;
     RECT  23.101 48.384 23.221 48.456 ;
     RECT  22.957 52.32 23.461 54.36 ;
     RECT  22.885 31.728 23.533 31.8 ;
     RECT  22.957 3.072 23.569 14.136 ;
     RECT  23.101 70.896 23.641 73.608 ;
     RECT  22.457 44.448 23.701 44.664 ;
     RECT  23.221 46.128 23.701 48.456 ;
     RECT  23.137 38.4 23.749 39.864 ;
     RECT  22.421 36.096 23.785 36.12 ;
     RECT  22.921 74.736 23.785 74.76 ;
     RECT  23.785 28.8 23.821 28.824 ;
     RECT  22.681 78 23.893 78.024 ;
     RECT  23.029 86.736 23.893 88.104 ;
     RECT  23.893 78 23.965 78.648 ;
     RECT  23.893 86.736 24.001 88.152 ;
     RECT  22.853 89.472 24.001 90.552 ;
     RECT  22.853 94.32 24.001 95.16 ;
     RECT  23.569 2.784 24.008 14.136 ;
     RECT  22.885 18.768 24.008 18.792 ;
     RECT  22.997 20.064 24.008 20.376 ;
     RECT  23.821 28.272 24.008 28.824 ;
     RECT  23.533 31.488 24.008 31.8 ;
     RECT  23.209 34.368 24.008 34.392 ;
     RECT  23.785 36.096 24.008 36.6 ;
     RECT  23.749 38.4 24.008 40.392 ;
     RECT  23.965 43.344 24.008 43.368 ;
     RECT  23.701 44.448 24.008 48.456 ;
     RECT  23.027 49.488 24.008 51.288 ;
     RECT  23.461 52.32 24.008 54.408 ;
     RECT  23.209 56.448 24.008 57.336 ;
     RECT  22.853 60.384 24.008 61.992 ;
     RECT  23.033 63.36 24.008 69.576 ;
     RECT  23.641 70.896 24.008 73.704 ;
     RECT  23.785 74.736 24.008 75.24 ;
     RECT  23.965 77.04 24.008 78.648 ;
     RECT  23.029 79.68 24.008 80.376 ;
     RECT  23.065 82.992 24.008 85.752 ;
     RECT  24.001 86.736 24.008 90.552 ;
     RECT  22.673 92.256 24.008 93 ;
     RECT  24.001 94.32 24.008 95.784 ;
     RECT  24.008 2.148 24.112 97.212 ;
     RECT  24.112 2.418 24.304 96.942 ;
     RECT  24.304 63.216 24.329 77.544 ;
     RECT  24.304 16.992 24.401 20.376 ;
     RECT  24.304 91.632 24.401 96.312 ;
     RECT  24.304 2.88 24.419 4.392 ;
     RECT  24.401 92.832 24.437 96.312 ;
     RECT  24.304 21.696 24.473 21.72 ;
     RECT  24.304 60.384 24.515 61.944 ;
     RECT  24.329 75.984 24.545 77.544 ;
     RECT  24.329 63.216 24.563 74.904 ;
     RECT  24.304 78.624 24.563 81.48 ;
     RECT  24.304 26.784 24.581 26.856 ;
     RECT  24.563 63.216 24.581 74.664 ;
     RECT  24.563 78.624 24.604 81.432 ;
     RECT  24.304 28.272 24.653 31.896 ;
     RECT  24.304 38.4 24.653 40.104 ;
     RECT  24.653 28.272 24.689 29.544 ;
     RECT  24.689 29.52 24.707 29.544 ;
     RECT  24.304 5.472 24.725 14.712 ;
     RECT  24.304 53.28 24.725 59.256 ;
     RECT  24.581 73.824 24.761 74.664 ;
     RECT  24.401 19.392 24.769 20.376 ;
     RECT  24.725 53.28 24.797 58.92 ;
     RECT  24.725 5.568 24.833 14.712 ;
     RECT  24.797 54.384 24.941 58.92 ;
     RECT  24.304 82.656 24.995 90.552 ;
     RECT  24.653 30.816 25.049 31.896 ;
     RECT  24.833 5.856 25.091 14.712 ;
     RECT  24.545 75.984 25.091 76.392 ;
     RECT  24.995 82.992 25.091 90.552 ;
     RECT  25.091 6 25.121 14.712 ;
     RECT  24.304 50.88 25.121 51.24 ;
     RECT  24.797 53.28 25.121 53.352 ;
     RECT  24.437 92.928 25.121 96.312 ;
     RECT  24.545 77.52 25.129 77.544 ;
     RECT  25.121 92.928 25.157 93.24 ;
     RECT  24.761 74.448 25.193 74.664 ;
     RECT  25.091 84.288 25.301 90.552 ;
     RECT  24.653 38.64 25.333 40.104 ;
     RECT  24.304 41.088 25.333 42.216 ;
     RECT  24.304 46.848 25.337 49.848 ;
     RECT  24.304 15.888 25.405 15.912 ;
     RECT  25.121 53.28 25.409 53.304 ;
     RECT  25.333 38.64 25.441 42.216 ;
     RECT  24.304 43.344 25.441 45.624 ;
     RECT  24.401 91.632 25.441 91.704 ;
     RECT  25.157 92.928 25.441 92.952 ;
     RECT  25.405 15.888 25.445 16.008 ;
     RECT  25.121 51.168 25.445 51.24 ;
     RECT  25.121 6.048 25.481 14.712 ;
     RECT  25.481 6.048 25.517 6.072 ;
     RECT  25.301 84.336 25.517 90.552 ;
     RECT  25.441 38.64 25.571 45.624 ;
     RECT  25.481 7.152 25.625 14.712 ;
     RECT  25.337 46.848 25.625 48.168 ;
     RECT  24.419 2.88 25.657 4.248 ;
     RECT  24.401 16.992 25.669 18.216 ;
     RECT  25.091 83.04 25.697 83.208 ;
     RECT  25.441 91.632 25.697 92.952 ;
     RECT  25.625 7.728 25.769 14.712 ;
     RECT  25.769 11.136 25.801 14.712 ;
     RECT  25.769 7.728 25.805 10.152 ;
     RECT  24.769 19.632 25.805 20.376 ;
     RECT  25.091 75.984 25.873 76.008 ;
     RECT  25.669 16.992 25.877 18.264 ;
     RECT  25.445 15.984 25.909 16.008 ;
     RECT  25.877 16.992 25.909 17.064 ;
     RECT  25.805 7.728 25.913 9.912 ;
     RECT  25.337 49.2 25.913 49.848 ;
     RECT  24.581 63.216 25.913 72.84 ;
     RECT  25.909 15.984 25.955 17.064 ;
     RECT  24.304 36.528 25.981 36.6 ;
     RECT  25.955 16.56 25.996 17.064 ;
     RECT  24.604 78.624 26.005 80.376 ;
     RECT  25.049 31.68 26.017 31.896 ;
     RECT  25.981 36.528 26.017 36.696 ;
     RECT  24.515 60.528 26.017 61.944 ;
     RECT  26.005 78.384 26.021 80.376 ;
     RECT  26.021 78.384 26.051 80.28 ;
     RECT  24.581 26.784 26.053 26.808 ;
     RECT  25.517 84.624 26.057 90.312 ;
     RECT  26.017 60 26.089 61.944 ;
     RECT  25.913 63.216 26.093 68.424 ;
     RECT  25.805 19.968 26.161 20.376 ;
     RECT  26.125 21.648 26.161 21.672 ;
     RECT  24.689 28.272 26.161 28.296 ;
     RECT  25.571 38.64 26.161 41.64 ;
     RECT  26.053 26.784 26.165 26.952 ;
     RECT  25.697 91.776 26.173 92.952 ;
     RECT  25.571 42.72 26.197 45.624 ;
     RECT  25.625 46.848 26.197 47.592 ;
     RECT  25.193 74.64 26.197 74.664 ;
     RECT  25.873 75.936 26.197 76.008 ;
     RECT  26.057 84.624 26.201 89.88 ;
     RECT  25.585 23.376 26.225 23.4 ;
     RECT  26.017 31.536 26.233 31.896 ;
     RECT  26.089 60 26.233 61.992 ;
     RECT  26.197 74.64 26.237 76.008 ;
     RECT  26.089 18.624 26.243 18.984 ;
     RECT  26.197 42.72 26.243 47.592 ;
     RECT  25.913 49.536 26.273 49.848 ;
     RECT  25.121 94.512 26.273 96.312 ;
     RECT  26.243 18.816 26.284 18.984 ;
     RECT  26.225 22.752 26.291 23.4 ;
     RECT  26.243 46.224 26.309 47.592 ;
     RECT  25.765 52.464 26.309 53.112 ;
     RECT  26.173 91.968 26.341 92.952 ;
     RECT  26.273 94.512 26.341 94.584 ;
     RECT  25.913 7.728 26.345 9.576 ;
     RECT  26.017 36.048 26.377 36.696 ;
     RECT  26.093 63.504 26.417 68.424 ;
     RECT  26.201 84.624 26.417 89.544 ;
     RECT  26.233 60 26.449 62.04 ;
     RECT  26.273 95.808 26.453 96.312 ;
     RECT  26.233 30.672 26.485 31.896 ;
     RECT  26.051 78.384 26.485 78.744 ;
     RECT  26.161 19.968 26.489 21.672 ;
     RECT  26.485 78.048 26.489 78.744 ;
     RECT  26.449 60 26.521 62.232 ;
     RECT  26.161 38.448 26.561 41.64 ;
     RECT  26.341 91.968 26.561 94.584 ;
     RECT  26.453 95.904 26.561 96.312 ;
     RECT  26.309 46.848 26.593 47.592 ;
     RECT  26.165 26.784 26.629 26.808 ;
     RECT  26.417 63.504 26.633 68.376 ;
     RECT  26.161 28.272 26.665 28.632 ;
     RECT  26.665 28.272 26.701 28.68 ;
     RECT  26.377 36.048 26.701 36.936 ;
     RECT  26.309 52.464 26.705 52.824 ;
     RECT  24.941 54.384 26.705 58.824 ;
     RECT  26.291 22.752 26.725 22.92 ;
     RECT  26.345 7.728 26.737 7.8 ;
     RECT  26.593 46.848 26.737 47.976 ;
     RECT  26.521 60 26.737 62.328 ;
     RECT  26.705 54.384 26.741 58.056 ;
     RECT  26.725 21.984 26.771 22.92 ;
     RECT  26.485 30.624 26.773 31.896 ;
     RECT  26.741 56.016 26.777 58.056 ;
     RECT  26.377 33.408 26.809 33.432 ;
     RECT  26.561 38.688 26.813 41.64 ;
     RECT  26.777 56.016 26.813 56.952 ;
     RECT  26.633 63.504 26.813 64.68 ;
     RECT  26.561 96.288 26.813 96.312 ;
     RECT  25.657 2.88 26.845 4.488 ;
     RECT  26.701 28.272 26.849 29.544 ;
     RECT  24.604 81.408 26.881 81.432 ;
     RECT  26.737 46.848 26.917 48.312 ;
     RECT  26.705 52.464 26.921 52.488 ;
     RECT  26.813 56.592 26.921 56.952 ;
     RECT  26.881 81.36 27.025 81.432 ;
     RECT  26.773 82.8 27.025 82.824 ;
     RECT  26.737 59.616 27.029 62.328 ;
     RECT  26.849 28.512 27.061 29.544 ;
     RECT  26.773 30.576 27.061 31.896 ;
     RECT  26.284 18.816 27.065 18.84 ;
     RECT  26.813 41.616 27.065 41.64 ;
     RECT  27.061 28.512 27.101 31.896 ;
     RECT  26.243 42.72 27.101 45.144 ;
     RECT  27.101 28.608 27.173 31.896 ;
     RECT  26.921 56.928 27.209 56.952 ;
     RECT  25.445 51.168 27.241 51.192 ;
     RECT  27.025 81.36 27.241 82.824 ;
     RECT  27.173 30.576 27.277 31.896 ;
     RECT  26.809 33.168 27.277 33.432 ;
     RECT  26.345 8.976 27.313 9.576 ;
     RECT  25.801 11.136 27.313 14.808 ;
     RECT  27.241 51.168 27.313 51.432 ;
     RECT  27.241 81.36 27.313 83.064 ;
     RECT  26.561 91.968 27.313 93.864 ;
     RECT  26.813 38.688 27.317 40.632 ;
     RECT  27.101 42.96 27.317 45.144 ;
     RECT  27.313 8.928 27.349 14.808 ;
     RECT  26.417 88.032 27.385 89.544 ;
     RECT  27.349 8.928 27.389 14.856 ;
     RECT  26.701 36.048 27.389 37.224 ;
     RECT  25.913 69.6 27.389 72.84 ;
     RECT  27.385 88.032 27.389 90.36 ;
     RECT  26.845 2.88 27.425 5.064 ;
     RECT  27.389 88.08 27.457 90.36 ;
     RECT  27.313 91.872 27.457 93.864 ;
     RECT  26.737 6.912 27.493 7.8 ;
     RECT  27.389 8.928 27.493 11.976 ;
     RECT  27.425 2.88 27.529 4.392 ;
     RECT  26.741 54.384 27.529 54.408 ;
     RECT  27.389 13.296 27.533 14.856 ;
     RECT  27.317 38.688 27.533 40.536 ;
     RECT  27.421 34.752 27.569 34.776 ;
     RECT  27.389 36.864 27.569 37.224 ;
     RECT  27.317 43.056 27.569 45.144 ;
     RECT  26.917 46.848 27.601 48.456 ;
     RECT  27.569 37.056 27.605 37.224 ;
     RECT  26.633 65.856 27.605 68.376 ;
     RECT  26.489 78.048 27.641 78.648 ;
     RECT  27.533 13.584 27.713 14.856 ;
     RECT  27.457 88.08 27.733 93.864 ;
     RECT  27.493 6.912 27.749 11.976 ;
     RECT  27.601 46.848 27.781 48.792 ;
     RECT  26.237 74.64 27.781 75.96 ;
     RECT  27.713 13.584 27.785 14.808 ;
     RECT  27.529 2.832 27.821 4.392 ;
     RECT  27.173 28.608 27.821 29.544 ;
     RECT  27.313 51.168 27.821 51.96 ;
     RECT  27.781 74.208 27.821 75.96 ;
     RECT  27.821 74.208 27.827 75.672 ;
     RECT  27.733 88.08 27.827 94.824 ;
     RECT  27.781 46.512 27.845 48.792 ;
     RECT  26.273 49.824 27.845 49.848 ;
     RECT  27.313 41.712 27.857 41.736 ;
     RECT  27.827 74.208 27.865 75.144 ;
     RECT  27.853 5.76 27.889 5.88 ;
     RECT  27.827 88.176 27.889 94.824 ;
     RECT  27.817 23.328 27.901 23.352 ;
     RECT  27.569 43.056 27.901 45 ;
     RECT  27.889 88.176 27.923 95.16 ;
     RECT  27.845 46.512 27.929 49.848 ;
     RECT  27.923 88.176 27.929 92.328 ;
     RECT  27.923 93.6 27.929 95.16 ;
     RECT  27.529 54.144 27.961 54.408 ;
     RECT  27.889 57.984 27.961 58.008 ;
     RECT  27.929 92.304 27.964 92.328 ;
     RECT  27.533 38.688 27.965 39.912 ;
     RECT  26.771 21.984 27.997 22.008 ;
     RECT  27.749 7.344 28.001 11.976 ;
     RECT  27.821 28.608 28.001 28.632 ;
     RECT  27.277 30.576 28.037 33.432 ;
     RECT  27.929 46.512 28.073 48.792 ;
     RECT  27.313 81.36 28.109 83.256 ;
     RECT  25.996 17.04 28.177 17.064 ;
     RECT  26.051 79.824 28.181 80.28 ;
     RECT  26.813 63.504 28.213 63.528 ;
     RECT  27.605 66 28.213 68.376 ;
     RECT  27.389 69.6 28.213 71.16 ;
     RECT  27.961 54.144 28.249 54.984 ;
     RECT  27.029 60 28.249 62.328 ;
     RECT  28.213 63.504 28.249 63.624 ;
     RECT  28.001 9.936 28.259 11.976 ;
     RECT  28.249 53.52 28.285 54.984 ;
     RECT  28.109 81.936 28.289 83.256 ;
     RECT  28.213 66 28.3 71.16 ;
     RECT  27.965 39.888 28.361 39.912 ;
     RECT  27.889 5.76 28.393 6.312 ;
     RECT  26.489 19.968 28.405 20.376 ;
     RECT  28.285 53.52 28.429 55.128 ;
     RECT  28.3 70.272 28.429 71.16 ;
     RECT  27.389 72.288 28.429 72.84 ;
     RECT  27.641 78.144 28.429 78.648 ;
     RECT  28.181 79.824 28.429 80.04 ;
     RECT  27.929 49.824 28.501 49.848 ;
     RECT  26.629 26.304 28.537 26.808 ;
     RECT  27.961 56.544 28.537 56.568 ;
     RECT  27.961 57.552 28.537 58.008 ;
     RECT  28.405 19.968 28.549 20.424 ;
     RECT  27.997 21.984 28.549 22.248 ;
     RECT  28.501 49.824 28.609 49.944 ;
     RECT  27.901 43.056 28.681 43.704 ;
     RECT  28.429 53.328 28.717 55.128 ;
     RECT  28.177 16.128 28.748 17.064 ;
     RECT  27.821 2.88 28.753 4.392 ;
     RECT  28.393 5.424 28.753 6.312 ;
     RECT  27.821 51.36 28.825 51.96 ;
     RECT  28.537 56.544 28.837 58.008 ;
     RECT  28.837 56.496 28.861 58.008 ;
     RECT  28.861 56.352 28.885 58.008 ;
     RECT  28.609 49.824 28.897 50.328 ;
     RECT  28.825 51.36 28.969 52.2 ;
     RECT  26.813 64.656 28.969 64.68 ;
     RECT  27.929 95.136 28.969 95.16 ;
     RECT  28.321 96.432 28.969 96.456 ;
     RECT  28.748 16.128 29.029 17.592 ;
     RECT  28.681 42.768 29.029 43.704 ;
     RECT  27.901 44.976 29.029 45 ;
     RECT  28.037 31.728 29.036 33.432 ;
     RECT  28.969 51.36 29.041 52.296 ;
     RECT  28.717 53.328 29.041 55.176 ;
     RECT  28.429 70.272 29.041 72.84 ;
     RECT  27.865 74.304 29.041 75.144 ;
     RECT  27.929 88.176 29.041 91.32 ;
     RECT  28.549 19.968 29.077 22.248 ;
     RECT  28.429 78.144 29.077 80.04 ;
     RECT  26.449 76.944 29.125 76.968 ;
     RECT  29.077 78 29.125 80.04 ;
     RECT  28.289 81.984 29.149 83.256 ;
     RECT  26.417 84.624 29.149 86.856 ;
     RECT  28.969 64.608 29.185 64.68 ;
     RECT  28.897 49.296 29.221 50.328 ;
     RECT  28.969 95.136 29.221 96.456 ;
     RECT  28.259 10.8 29.269 11.976 ;
     RECT  27.785 13.584 29.269 14.232 ;
     RECT  29.149 81.984 29.293 86.856 ;
     RECT  29.041 87.936 29.293 91.32 ;
     RECT  28.3 66 29.329 68.952 ;
     RECT  29.041 70.272 29.329 75.144 ;
     RECT  29.036 31.728 29.365 33.816 ;
     RECT  29.125 76.944 29.365 80.04 ;
     RECT  29.293 81.984 29.365 91.32 ;
     RECT  28.753 2.88 29.408 6.312 ;
     RECT  28.001 7.344 29.408 8.52 ;
     RECT  29.269 10.8 29.408 14.232 ;
     RECT  29.029 15.84 29.408 17.592 ;
     RECT  28.933 18.816 29.408 18.84 ;
     RECT  29.077 19.968 29.408 22.344 ;
     RECT  28.537 26.208 29.408 26.808 ;
     RECT  28.037 30.576 29.408 30.744 ;
     RECT  29.365 31.728 29.408 34.776 ;
     RECT  27.605 37.056 29.408 37.08 ;
     RECT  27.965 38.688 29.408 38.712 ;
     RECT  28.969 40.416 29.408 40.44 ;
     RECT  29.029 42.768 29.408 45 ;
     RECT  28.073 46.512 29.408 47.88 ;
     RECT  29.221 49.248 29.408 50.328 ;
     RECT  29.041 51.36 29.408 55.176 ;
     RECT  28.885 56.352 29.408 58.152 ;
     RECT  28.249 60 29.408 63.624 ;
     RECT  29.185 64.608 29.408 64.968 ;
     RECT  29.329 66 29.408 75.144 ;
     RECT  29.365 76.464 29.408 80.04 ;
     RECT  29.365 81.984 29.408 91.608 ;
     RECT  27.929 93.6 29.408 93.864 ;
     RECT  29.221 95.136 29.408 96.744 ;
     RECT  29.408 2.148 29.512 97.212 ;
     RECT  29.512 2.418 29.704 96.942 ;
     RECT  29.704 10.32 29.729 13.08 ;
     RECT  29.704 77.28 29.729 86.472 ;
     RECT  29.704 91.584 29.765 93.864 ;
     RECT  29.704 63.408 29.801 66.6 ;
     RECT  29.765 92.784 29.801 93.864 ;
     RECT  29.704 60 29.837 60.456 ;
     RECT  29.704 3.072 29.873 6.024 ;
     RECT  29.765 91.584 29.873 91.752 ;
     RECT  29.704 18.816 29.909 22.824 ;
     RECT  29.729 77.28 29.981 81.24 ;
     RECT  29.729 82.224 29.981 86.472 ;
     RECT  29.704 44.976 30.053 45 ;
     RECT  29.981 82.224 30.089 82.776 ;
     RECT  29.704 69.456 30.125 75.144 ;
     RECT  30.089 82.224 30.131 82.728 ;
     RECT  29.704 51.36 30.179 57 ;
     RECT  29.909 20.544 30.227 22.824 ;
     RECT  29.704 32.832 30.233 33.048 ;
     RECT  30.125 69.456 30.275 73.08 ;
     RECT  29.729 10.32 30.341 10.344 ;
     RECT  29.704 95.952 30.341 96.744 ;
     RECT  29.704 7.392 30.419 8.184 ;
     RECT  30.227 22.032 30.449 22.824 ;
     RECT  29.981 83.76 30.449 86.472 ;
     RECT  29.981 78.192 30.563 81.24 ;
     RECT  30.563 78.192 30.593 80.904 ;
     RECT  29.873 3.12 30.629 6.024 ;
     RECT  29.704 40.368 30.629 41.256 ;
     RECT  29.837 60.432 30.629 60.456 ;
     RECT  30.593 80.832 30.629 80.904 ;
     RECT  30.341 96.336 30.665 96.744 ;
     RECT  29.704 28.8 30.697 28.824 ;
     RECT  29.704 30.24 30.697 30.264 ;
     RECT  29.704 61.632 30.697 62.136 ;
     RECT  30.629 3.12 30.701 5.88 ;
     RECT  29.704 24.48 30.709 24.792 ;
     RECT  30.701 3.12 30.737 5.832 ;
     RECT  29.801 63.408 30.748 66.024 ;
     RECT  30.709 24.48 30.755 25.08 ;
     RECT  29.704 87.84 30.757 90.408 ;
     RECT  30.737 5.808 30.773 5.832 ;
     RECT  29.704 34.656 30.773 37.08 ;
     RECT  30.419 8.16 30.805 8.184 ;
     RECT  30.697 28.8 30.805 30.264 ;
     RECT  29.704 31.44 30.805 31.464 ;
     RECT  30.233 32.832 30.805 32.856 ;
     RECT  29.704 14.112 30.809 14.808 ;
     RECT  30.805 28.8 30.809 30.456 ;
     RECT  30.275 69.456 30.809 72.648 ;
     RECT  30.629 80.88 30.809 80.904 ;
     RECT  30.805 8.16 30.845 8.52 ;
     RECT  29.801 93.6 30.845 93.864 ;
     RECT  30.805 31.44 30.851 32.856 ;
     RECT  30.449 84.384 30.851 86.472 ;
     RECT  30.697 61.632 30.853 62.28 ;
     RECT  30.748 63.408 30.853 65.352 ;
     RECT  30.179 55.152 30.86 57 ;
     RECT  29.704 58.128 30.86 58.152 ;
     RECT  29.704 26.304 30.877 26.76 ;
     RECT  30.851 85.968 30.901 86.472 ;
     RECT  30.757 87.84 30.901 90.696 ;
     RECT  29.704 67.68 30.913 68.184 ;
     RECT  29.704 49.2 30.917 50.28 ;
     RECT  30.86 55.152 30.947 58.152 ;
     RECT  29.909 18.816 30.949 19.512 ;
     RECT  29.729 11.376 30.953 13.08 ;
     RECT  30.851 84.384 30.995 84.648 ;
     RECT  30.593 78.192 31.021 79.752 ;
     RECT  30.877 26.304 31.025 26.808 ;
     RECT  30.901 85.968 31.045 90.696 ;
     RECT  29.873 91.728 31.045 91.752 ;
     RECT  30.901 59.856 31.061 59.88 ;
     RECT  30.809 70.08 31.097 72.648 ;
     RECT  30.805 95.136 31.097 95.16 ;
     RECT  30.179 51.36 31.133 54.024 ;
     RECT  31.097 72.48 31.133 72.648 ;
     RECT  31.097 70.08 31.169 71.4 ;
     RECT  31.133 72.48 31.169 72.504 ;
     RECT  31.045 85.968 31.169 91.752 ;
     RECT  30.665 96.336 31.169 96.36 ;
     RECT  31.169 85.968 31.187 90.168 ;
     RECT  30.773 34.656 31.205 34.68 ;
     RECT  30.947 58.128 31.205 58.152 ;
     RECT  31.187 90 31.241 90.168 ;
     RECT  31.133 51.744 31.265 54.024 ;
     RECT  30.947 55.152 31.265 57.144 ;
     RECT  31.021 77.472 31.313 79.752 ;
     RECT  30.125 74.112 31.331 75.144 ;
     RECT  31.187 85.968 31.331 88.92 ;
     RECT  30.809 28.8 31.333 29.208 ;
     RECT  29.704 42.816 31.333 43.32 ;
     RECT  31.265 51.744 31.349 57.144 ;
     RECT  31.331 87.216 31.349 88.92 ;
     RECT  31.331 74.112 31.381 74.856 ;
     RECT  30.953 11.376 31.385 11.976 ;
     RECT  31.333 42.48 31.42 43.32 ;
     RECT  29.704 46.32 31.421 47.88 ;
     RECT  31.381 73.488 31.427 74.856 ;
     RECT  30.851 31.728 31.457 32.856 ;
     RECT  31.427 73.488 31.468 73.512 ;
     RECT  31.42 42.672 31.477 43.32 ;
     RECT  30.697 44.736 31.477 44.76 ;
     RECT  29.704 15.984 31.484 16.008 ;
     RECT  31.457 31.872 31.484 32.856 ;
     RECT  30.629 40.368 31.489 40.392 ;
     RECT  31.025 26.736 31.493 26.808 ;
     RECT  31.333 27.888 31.493 29.208 ;
     RECT  30.227 20.544 31.525 20.856 ;
     RECT  30.449 22.032 31.525 22.776 ;
     RECT  31.349 87.216 31.529 87.768 ;
     RECT  29.704 38.688 31.532 38.856 ;
     RECT  30.773 35.856 31.565 37.08 ;
     RECT  31.313 77.472 31.565 78.456 ;
     RECT  31.484 15.984 31.571 16.44 ;
     RECT  31.484 31.872 31.571 33.528 ;
     RECT  31.532 38.688 31.573 39.192 ;
     RECT  31.489 40.272 31.573 40.392 ;
     RECT  30.853 61.632 31.612 65.352 ;
     RECT  31.573 38.688 31.621 40.392 ;
     RECT  31.241 90 31.637 90.072 ;
     RECT  31.621 38.208 31.667 41.064 ;
     RECT  31.525 21.984 31.673 22.776 ;
     RECT  31.493 28.368 31.673 29.208 ;
     RECT  30.809 30.432 31.673 30.456 ;
     RECT  30.845 8.496 31.741 8.52 ;
     RECT  30.921 92.928 31.745 93.528 ;
     RECT  31.313 79.728 31.765 79.752 ;
     RECT  30.809 14.112 31.813 14.232 ;
     RECT  30.949 18.672 31.813 19.512 ;
     RECT  31.525 20.544 31.813 20.952 ;
     RECT  31.673 21.984 31.813 22.68 ;
     RECT  30.913 67.68 31.813 69 ;
     RECT  31.349 51.744 31.817 56.904 ;
     RECT  31.612 61.632 31.841 63.24 ;
     RECT  31.817 51.744 31.853 54.696 ;
     RECT  31.813 14.112 31.859 14.808 ;
     RECT  31.673 28.368 31.859 28.488 ;
     RECT  31.667 38.208 31.859 38.568 ;
     RECT  30.995 84.576 31.885 84.648 ;
     RECT  31.612 64.32 31.921 65.352 ;
     RECT  31.385 11.376 31.925 11.928 ;
     RECT  31.841 61.536 31.925 63.24 ;
     RECT  31.565 36.336 31.961 37.08 ;
     RECT  31.925 62.112 31.961 63.192 ;
     RECT  31.813 67.296 31.961 69 ;
     RECT  30.737 3.696 31.997 4.488 ;
     RECT  31.961 36.336 31.997 36.36 ;
     RECT  31.921 64.32 31.997 65.544 ;
     RECT  31.765 79.728 31.997 80.52 ;
     RECT  31.571 31.872 32.033 33.144 ;
     RECT  31.637 90.048 32.033 90.072 ;
     RECT  31.997 79.728 32.044 80.328 ;
     RECT  31.741 8.496 32.065 9.144 ;
     RECT  32.065 8.496 32.101 9.528 ;
     RECT  31.961 67.296 32.101 68.28 ;
     RECT  32.101 8.4 32.105 9.528 ;
     RECT  31.817 55.872 32.141 56.904 ;
     RECT  32.101 66.72 32.141 68.28 ;
     RECT  31.853 52.704 32.147 54.696 ;
     RECT  31.169 70.08 32.173 70.728 ;
     RECT  32.147 54.672 32.177 54.696 ;
     RECT  31.997 3.696 32.209 3.72 ;
     RECT  31.997 64.416 32.249 65.544 ;
     RECT  31.477 42.672 32.252 44.76 ;
     RECT  30.131 82.656 32.281 82.728 ;
     RECT  32.141 55.872 32.285 56.424 ;
     RECT  31.529 87.216 32.285 87.576 ;
     RECT  32.252 42.672 32.339 45.672 ;
     RECT  31.925 11.376 32.389 11.4 ;
     RECT  32.285 56.208 32.393 56.424 ;
     RECT  31.957 81.504 32.425 81.528 ;
     RECT  32.281 82.656 32.425 83.064 ;
     RECT  32.147 52.704 32.429 53.592 ;
     RECT  32.249 64.656 32.429 65.544 ;
     RECT  32.417 17.664 32.437 17.688 ;
     RECT  31.813 18.672 32.437 20.952 ;
     RECT  32.429 65.328 32.437 65.544 ;
     RECT  32.141 66.72 32.437 66.744 ;
     RECT  32.437 65.328 32.483 66.744 ;
     RECT  31.741 27.312 32.497 27.336 ;
     RECT  32.105 8.4 32.501 8.52 ;
     RECT  31.961 62.592 32.501 63.192 ;
     RECT  32.425 81.504 32.509 83.208 ;
     RECT  32.483 65.328 32.531 66.12 ;
     RECT  32.141 68.16 32.531 68.28 ;
     RECT  31.669 6.816 32.533 6.84 ;
     RECT  32.173 69.408 32.533 70.728 ;
     RECT  31.885 84.576 32.533 85.128 ;
     RECT  31.169 91.728 32.533 91.752 ;
     RECT  32.393 56.208 32.537 56.232 ;
     RECT  32.437 17.664 32.569 20.952 ;
     RECT  31.813 21.936 32.569 22.68 ;
     RECT  32.509 81.504 32.573 81.528 ;
     RECT  32.533 84.336 32.579 85.128 ;
     RECT  30.953 13.056 32.605 13.08 ;
     RECT  32.209 2.832 32.609 3.72 ;
     RECT  32.033 32.304 32.609 33.144 ;
     RECT  32.044 79.728 32.609 79.752 ;
     RECT  32.509 82.656 32.609 83.208 ;
     RECT  30.917 49.2 32.641 49.848 ;
     RECT  31.565 77.52 32.713 78.456 ;
     RECT  32.531 66.096 32.717 66.12 ;
     RECT  32.569 17.664 32.725 22.68 ;
     RECT  32.497 26.784 32.725 27.336 ;
     RECT  32.105 9.504 32.749 9.528 ;
     RECT  31.745 93.504 32.749 93.528 ;
     RECT  31.427 74.832 32.753 74.856 ;
     RECT  32.437 15.888 32.773 15.912 ;
     RECT  32.389 5.136 32.78 5.16 ;
     RECT  32.533 6.816 32.789 7.272 ;
     RECT  32.533 91.728 32.821 91.848 ;
     RECT  32.749 92.928 32.821 93.528 ;
     RECT  32.339 45.024 32.825 45.288 ;
     RECT  32.609 82.704 32.825 83.208 ;
     RECT  31.349 88.896 32.828 88.92 ;
     RECT  32.78 5.136 32.867 5.736 ;
     RECT  32.725 30.72 32.867 30.744 ;
     RECT  31.859 14.208 32.869 14.808 ;
     RECT  32.773 15.888 32.869 15.96 ;
     RECT  31.331 86.208 32.869 86.232 ;
     RECT  32.285 87.216 32.869 87.48 ;
     RECT  32.725 26.16 32.897 27.336 ;
     RECT  32.828 88.896 32.915 89.112 ;
     RECT  32.821 91.728 32.915 93.528 ;
     RECT  32.713 76.56 32.929 78.456 ;
     RECT  32.725 33.648 32.933 33.672 ;
     RECT  32.867 5.136 32.972 5.16 ;
     RECT  31.667 39.6 33.005 41.064 ;
     RECT  32.915 88.896 33.005 88.92 ;
     RECT  31.421 47.04 33.013 47.88 ;
     RECT  32.972 4.848 33.059 5.16 ;
     RECT  32.725 17.664 33.059 22.824 ;
     RECT  33.059 20.832 33.061 22.824 ;
     RECT  32.929 23.904 33.061 23.928 ;
     RECT  30.755 25.056 33.061 25.08 ;
     RECT  32.897 26.16 33.061 26.76 ;
     RECT  32.609 32.304 33.061 32.376 ;
     RECT  31.859 28.464 33.073 28.488 ;
     RECT  33.013 46.848 33.073 47.88 ;
     RECT  32.641 48.864 33.073 49.848 ;
     RECT  32.749 9.504 33.107 10.296 ;
     RECT  33.061 20.832 33.107 23.928 ;
     RECT  33.061 31.872 33.107 32.376 ;
     RECT  33.107 9.504 33.113 10.2 ;
     RECT  32.869 14.208 33.113 15.96 ;
     RECT  33.061 25.056 33.113 26.76 ;
     RECT  32.339 42.672 33.113 43.944 ;
     RECT  33.113 9.696 33.149 10.2 ;
     RECT  33.113 25.104 33.149 26.76 ;
     RECT  33.107 31.872 33.149 32.328 ;
     RECT  32.929 76.32 33.185 78.456 ;
     RECT  32.915 91.728 33.221 92.952 ;
     RECT  33.113 42.672 33.253 43.368 ;
     RECT  32.209 90.624 33.257 90.648 ;
     RECT  33.185 76.56 33.293 78.456 ;
     RECT  33.059 17.664 33.325 19.512 ;
     RECT  32.609 2.832 33.329 2.856 ;
     RECT  32.533 69.408 33.329 71.64 ;
     RECT  32.579 84.336 33.329 84.6 ;
     RECT  33.145 79.824 33.361 79.992 ;
     RECT  33.005 39.984 33.397 41.064 ;
     RECT  33.253 42.144 33.397 43.368 ;
     RECT  32.605 12.624 33.433 13.08 ;
     RECT  32.501 63.168 33.433 63.192 ;
     RECT  31.859 38.544 33.437 38.568 ;
     RECT  32.825 83.04 33.437 83.208 ;
     RECT  33.397 39.984 33.443 43.368 ;
     RECT  33.325 17.088 33.473 19.512 ;
     RECT  32.825 45.024 33.473 45.048 ;
     RECT  33.443 40.416 33.484 42.168 ;
     RECT  33.433 12.624 33.493 13.176 ;
     RECT  32.789 7.248 33.505 7.272 ;
     RECT  32.501 8.4 33.505 8.424 ;
     RECT  33.433 63.168 33.505 64.152 ;
     RECT  33.073 28.464 33.509 29.064 ;
     RECT  33.473 17.664 33.545 19.512 ;
     RECT  33.107 20.832 33.545 23.064 ;
     RECT  33.149 25.104 33.545 26.04 ;
     RECT  33.505 63.072 33.545 64.152 ;
     RECT  33.073 46.848 33.577 49.848 ;
     RECT  33.545 25.68 33.617 26.04 ;
     RECT  33.329 69.936 33.617 71.64 ;
     RECT  33.293 76.896 33.635 78.456 ;
     RECT  33.577 46.704 33.644 49.848 ;
     RECT  32.389 11.328 33.653 11.4 ;
     RECT  33.653 11.376 33.683 11.4 ;
     RECT  33.545 18.768 33.683 19.512 ;
     RECT  33.493 12.528 33.685 13.176 ;
     RECT  33.061 34.56 33.685 34.584 ;
     RECT  33.113 14.208 33.689 15.816 ;
     RECT  33.644 46.704 33.689 50.136 ;
     RECT  33.685 34.56 33.731 35.736 ;
     RECT  33.689 46.848 33.731 50.136 ;
     RECT  32.531 68.16 33.757 68.184 ;
     RECT  33.505 7.248 33.793 8.424 ;
     RECT  33.635 78.432 33.793 78.456 ;
     RECT  33.361 79.824 33.793 80.232 ;
     RECT  33.545 17.664 33.797 17.688 ;
     RECT  33.361 74.592 33.797 74.616 ;
     RECT  32.869 86.208 33.829 87.48 ;
     RECT  32.821 72.912 33.833 72.936 ;
     RECT  33.829 56.352 33.901 56.376 ;
     RECT  33.793 60.048 33.937 60.072 ;
     RECT  33.545 63.072 34.009 63.096 ;
     RECT  33.059 5.136 34.021 5.16 ;
     RECT  33.757 68.16 34.045 68.424 ;
     RECT  33.149 32.256 34.117 32.328 ;
     RECT  33.937 60.048 34.153 60.12 ;
     RECT  34.045 66 34.153 66.024 ;
     RECT  33.149 9.696 34.165 9.72 ;
     RECT  33.221 92.496 34.189 92.952 ;
     RECT  33.545 20.928 34.261 23.064 ;
     RECT  34.153 24.096 34.261 24.12 ;
     RECT  33.685 36.768 34.297 36.792 ;
     RECT  34.153 88.992 34.297 89.016 ;
     RECT  34.297 36.768 34.333 36.888 ;
     RECT  33.617 70.32 34.333 71.64 ;
     RECT  33.901 31.104 34.369 31.128 ;
     RECT  33.505 51.264 34.369 51.288 ;
     RECT  32.429 52.704 34.369 53.016 ;
     RECT  33.793 78.432 34.369 80.232 ;
     RECT  34.165 9.696 34.405 9.96 ;
     RECT  34.369 51.264 34.405 53.016 ;
     RECT  34.117 58.704 34.405 58.728 ;
     RECT  33.437 83.088 34.477 83.208 ;
     RECT  34.297 88.992 34.549 89.544 ;
     RECT  33.731 34.656 34.585 35.736 ;
     RECT  34.333 36.768 34.585 37.128 ;
     RECT  33.329 84.576 34.621 84.6 ;
     RECT  34.333 70.32 34.693 72.84 ;
     RECT  34.549 88.752 34.693 89.544 ;
     RECT  33.545 64.128 34.729 64.152 ;
     RECT  34.153 65.952 34.729 66.024 ;
     RECT  34.657 3.984 34.765 4.008 ;
     RECT  34.021 5.136 34.765 5.88 ;
     RECT  34.405 9.696 34.765 10.104 ;
     RECT  33.685 11.424 34.765 13.176 ;
     RECT  34.693 88.752 34.765 90.36 ;
     RECT  34.189 92.208 34.765 92.952 ;
     RECT  33.613 81.984 34.801 82.008 ;
     RECT  34.477 82.992 34.801 83.208 ;
     RECT  34.477 2.256 34.808 2.28 ;
     RECT  34.765 3.6 34.808 5.88 ;
     RECT  33.793 6.864 34.808 8.424 ;
     RECT  34.765 9.696 34.808 13.176 ;
     RECT  33.689 14.784 34.808 15.816 ;
     RECT  34.477 17.616 34.808 17.64 ;
     RECT  33.683 19.344 34.808 19.512 ;
     RECT  34.261 20.928 34.808 24.12 ;
     RECT  33.617 26.016 34.808 26.04 ;
     RECT  33.509 28.464 34.808 28.728 ;
     RECT  34.369 29.76 34.808 29.784 ;
     RECT  34.369 31.104 34.808 31.224 ;
     RECT  34.117 32.256 34.808 33.288 ;
     RECT  34.585 34.656 34.808 37.128 ;
     RECT  33.484 40.416 34.808 40.44 ;
     RECT  33.484 41.952 34.808 42.168 ;
     RECT  33.443 43.248 34.808 43.368 ;
     RECT  33.731 46.848 34.808 49.848 ;
     RECT  34.405 51.264 34.808 53.592 ;
     RECT  33.901 56.256 34.808 56.376 ;
     RECT  34.405 58.416 34.808 58.728 ;
     RECT  34.153 60.048 34.808 60.312 ;
     RECT  34.009 62.496 34.808 63.096 ;
     RECT  34.729 64.128 34.808 66.024 ;
     RECT  34.045 67.584 34.808 68.424 ;
     RECT  34.693 70.08 34.808 72.84 ;
     RECT  33.635 76.896 34.808 77.112 ;
     RECT  34.369 78.432 34.808 80.376 ;
     RECT  34.801 81.984 34.808 83.208 ;
     RECT  34.621 84.576 34.808 85.032 ;
     RECT  33.829 86.016 34.808 87.576 ;
     RECT  34.765 88.752 34.808 91.176 ;
     RECT  34.765 92.16 34.808 92.952 ;
     RECT  34.693 95.136 34.808 95.16 ;
     RECT  34.808 2.148 34.912 97.212 ;
     RECT  34.912 2.256 35.104 96.942 ;
     RECT  35.104 17.088 35.165 17.64 ;
     RECT  35.104 2.256 35.219 5.928 ;
     RECT  35.104 13.488 35.219 14.28 ;
     RECT  35.104 18.768 35.219 29.16 ;
     RECT  35.104 58.416 35.219 61.512 ;
     RECT  35.104 70.08 35.219 75.384 ;
     RECT  35.104 92.16 35.219 93.528 ;
     RECT  35.219 60 35.237 61.512 ;
     RECT  35.104 10.272 35.267 10.872 ;
     RECT  35.104 45.36 35.267 48.408 ;
     RECT  35.219 92.496 35.273 93.528 ;
     RECT  35.104 31.104 35.309 38.232 ;
     RECT  35.309 31.104 35.345 34.152 ;
     RECT  35.219 70.32 35.345 75.384 ;
     RECT  35.165 17.088 35.353 17.544 ;
     RECT  35.104 51.984 35.363 54.696 ;
     RECT  35.363 53.568 35.381 54.696 ;
     RECT  35.237 60 35.381 60.072 ;
     RECT  35.104 7.392 35.389 8.664 ;
     RECT  35.309 35.52 35.417 38.232 ;
     RECT  35.219 5.616 35.555 5.928 ;
     RECT  35.267 10.272 35.569 10.824 ;
     RECT  35.219 2.256 35.597 4.104 ;
     RECT  35.381 54.144 35.603 54.696 ;
     RECT  35.345 70.32 35.633 71.64 ;
     RECT  35.104 55.728 35.669 56.28 ;
     RECT  35.417 36.336 35.699 38.232 ;
     RECT  35.104 82.416 35.74 87.672 ;
     RECT  35.219 58.416 35.741 59.016 ;
     RECT  35.219 14.208 35.747 14.28 ;
     RECT  35.569 10.8 35.749 10.824 ;
     RECT  35.345 31.104 35.813 33.624 ;
     RECT  35.104 80.928 35.849 81.384 ;
     RECT  35.813 31.104 35.885 32.376 ;
     RECT  35.74 84.528 35.891 87.672 ;
     RECT  35.597 3.168 35.921 4.104 ;
     RECT  35.849 80.928 35.921 80.952 ;
     RECT  35.389 7.392 36.035 8.232 ;
     RECT  35.603 54.144 36.065 54.168 ;
     RECT  35.104 88.944 36.065 91.176 ;
     RECT  35.699 37.056 36.092 38.232 ;
     RECT  36.092 37.056 36.097 38.424 ;
     RECT  35.273 92.496 36.101 93.48 ;
     RECT  35.219 18.768 36.169 19.368 ;
     RECT  35.104 44.304 36.205 44.328 ;
     RECT  36.065 91.152 36.245 91.176 ;
     RECT  35.104 68.16 36.277 68.424 ;
     RECT  35.891 84.912 36.277 87.672 ;
     RECT  36.065 88.944 36.277 89.688 ;
     RECT  35.345 72.72 36.313 75.384 ;
     RECT  35.104 76.704 36.313 79.752 ;
     RECT  35.267 45.696 36.317 48.408 ;
     RECT  36.277 84.912 36.323 89.688 ;
     RECT  35.741 58.704 36.349 59.016 ;
     RECT  35.381 60.048 36.349 60.072 ;
     RECT  36.313 72.72 36.353 79.752 ;
     RECT  36.323 88.608 36.364 89.688 ;
     RECT  36.205 6.384 36.371 6.408 ;
     RECT  35.104 41.904 36.38 42.744 ;
     RECT  35.219 20.448 36.385 29.16 ;
     RECT  36.353 72.72 36.389 74.424 ;
     RECT  36.353 75.936 36.389 79.752 ;
     RECT  35.353 17.088 36.421 17.4 ;
     RECT  36.389 73.392 36.425 74.424 ;
     RECT  36.169 18.672 36.457 19.368 ;
     RECT  36.385 20.448 36.457 29.304 ;
     RECT  36.349 58.704 36.457 60.072 ;
     RECT  35.237 61.2 36.457 61.512 ;
     RECT  35.104 62.592 36.457 63.624 ;
     RECT  36.38 41.904 36.467 43.272 ;
     RECT  35.104 15.984 36.493 16.008 ;
     RECT  36.421 17.088 36.493 17.448 ;
     RECT  35.104 64.992 36.529 66.12 ;
     RECT  36.313 11.376 36.533 11.4 ;
     RECT  36.493 15.984 36.533 17.448 ;
     RECT  35.363 51.984 36.533 52.44 ;
     RECT  36.323 84.912 36.533 86.712 ;
     RECT  35.104 95.136 36.565 95.16 ;
     RECT  36.425 73.728 36.605 74.424 ;
     RECT  36.533 16.368 36.637 17.448 ;
     RECT  36.457 18.672 36.637 29.304 ;
     RECT  36.389 77.088 36.637 79.752 ;
     RECT  35.813 33.36 36.661 33.624 ;
     RECT  36.529 64.992 36.673 67.08 ;
     RECT  36.277 68.16 36.673 68.904 ;
     RECT  35.885 31.104 36.707 31.272 ;
     RECT  35.747 14.208 36.709 14.232 ;
     RECT  36.637 16.368 36.709 29.688 ;
     RECT  36.661 33.36 36.709 34.344 ;
     RECT  36.467 41.904 36.709 42.744 ;
     RECT  36.533 52.224 36.745 52.44 ;
     RECT  36.709 41.232 36.755 42.744 ;
     RECT  36.709 33.36 36.781 34.776 ;
     RECT  36.565 95.136 36.781 95.496 ;
     RECT  36.035 7.92 36.805 8.232 ;
     RECT  36.781 12.528 36.817 12.552 ;
     RECT  36.781 94.608 36.817 95.496 ;
     RECT  36.673 64.992 36.821 68.904 ;
     RECT  36.817 12.096 36.865 12.552 ;
     RECT  36.817 94.608 36.893 96.312 ;
     RECT  36.709 16.368 36.901 29.784 ;
     RECT  35.633 71.616 36.929 71.64 ;
     RECT  36.097 37.056 36.947 39.384 ;
     RECT  35.921 3.168 36.956 3.192 ;
     RECT  36.205 44.304 36.961 44.568 ;
     RECT  35.669 56.016 37.001 56.28 ;
     RECT  35.885 32.352 37.033 32.376 ;
     RECT  36.781 33.36 37.033 34.824 ;
     RECT  35.633 70.32 37.033 70.344 ;
     RECT  37.033 32.352 37.036 34.824 ;
     RECT  36.956 3.168 37.043 3.24 ;
     RECT  37.001 56.208 37.045 56.28 ;
     RECT  35.104 49.824 37.069 50.856 ;
     RECT  36.457 58.704 37.069 63.624 ;
     RECT  36.821 64.992 37.069 68.424 ;
     RECT  36.805 7.92 37.073 8.376 ;
     RECT  36.961 44.304 37.073 45 ;
     RECT  36.961 72.384 37.073 72.408 ;
     RECT  36.637 77.088 37.091 80.136 ;
     RECT  37.073 7.92 37.105 8.232 ;
     RECT  36.533 85.344 37.109 86.712 ;
     RECT  37.045 56.208 37.132 57.048 ;
     RECT  37.036 32.448 37.145 34.824 ;
     RECT  36.745 52.224 37.145 52.632 ;
     RECT  37.109 85.44 37.145 86.712 ;
     RECT  36.317 46.08 37.177 48.408 ;
     RECT  37.069 49.824 37.177 51 ;
     RECT  37.069 58.704 37.181 68.424 ;
     RECT  36.865 12.096 37.187 12.12 ;
     RECT  36.947 37.056 37.189 38.808 ;
     RECT  36.925 54.72 37.196 54.744 ;
     RECT  37.181 58.704 37.213 61.944 ;
     RECT  36.709 14.208 37.217 14.856 ;
     RECT  36.901 16.368 37.253 30.12 ;
     RECT  37.145 52.416 37.253 52.632 ;
     RECT  37.196 53.808 37.283 54.744 ;
     RECT  37.213 57.744 37.283 61.944 ;
     RECT  36.893 95.088 37.289 96.312 ;
     RECT  37.253 18.672 37.321 30.12 ;
     RECT  36.707 31.104 37.321 31.128 ;
     RECT  37.145 34.08 37.325 34.824 ;
     RECT  37.189 37.056 37.331 38.232 ;
     RECT  36.605 74.4 37.361 74.424 ;
     RECT  35.74 82.416 37.381 83.496 ;
     RECT  36.389 75.936 37.393 76.104 ;
     RECT  37.091 77.088 37.393 79.848 ;
     RECT  37.283 54.72 37.433 54.744 ;
     RECT  37.177 46.08 37.465 51 ;
     RECT  37.381 82.416 37.465 84.024 ;
     RECT  36.755 41.232 37.469 42.504 ;
     RECT  37.177 39.84 37.501 39.864 ;
     RECT  37.073 44.448 37.501 45 ;
     RECT  37.465 46.08 37.501 51.096 ;
     RECT  36.364 89.04 37.577 89.688 ;
     RECT  37.393 75.936 37.613 79.848 ;
     RECT  37.253 16.368 37.649 17.592 ;
     RECT  36.101 92.496 37.649 93.24 ;
     RECT  37.465 81.456 37.667 84.024 ;
     RECT  37.613 75.936 37.669 78.12 ;
     RECT  37.325 34.08 37.685 34.776 ;
     RECT  37.685 34.08 37.793 34.68 ;
     RECT  37.145 86.688 37.825 86.712 ;
     RECT  37.789 88.32 37.825 88.344 ;
     RECT  37.321 18.672 37.829 31.128 ;
     RECT  37.217 14.208 37.861 14.232 ;
     RECT  37.289 95.136 37.861 96.312 ;
     RECT  37.829 29.52 37.865 31.128 ;
     RECT  37.613 79.296 37.865 79.848 ;
     RECT  37.861 95.136 37.865 96.36 ;
     RECT  37.577 89.424 37.897 89.688 ;
     RECT  37.132 56.208 37.901 56.52 ;
     RECT  37.861 13.92 37.907 14.232 ;
     RECT  37.865 95.52 37.945 96.36 ;
     RECT  37.825 86.688 37.973 88.344 ;
     RECT  37.829 18.672 38.003 28.488 ;
     RECT  37.283 57.744 38.009 57.912 ;
     RECT  37.669 75.552 38.041 78.12 ;
     RECT  37.945 95.52 38.099 95.544 ;
     RECT  37.501 44.448 38.113 51.096 ;
     RECT  37.253 52.416 38.113 52.44 ;
     RECT  37.865 29.568 38.117 31.128 ;
     RECT  37.145 85.44 38.117 85.512 ;
     RECT  38.117 29.76 38.149 31.128 ;
     RECT  37.145 32.448 38.149 32.472 ;
     RECT  37.105 7.392 38.153 8.232 ;
     RECT  38.003 23.952 38.153 28.488 ;
     RECT  37.501 39.84 38.195 40.824 ;
     RECT  38.153 23.952 38.225 25.08 ;
     RECT  38.041 92.304 38.225 92.328 ;
     RECT  37.331 37.056 38.257 37.752 ;
     RECT  38.153 26.256 38.261 28.488 ;
     RECT  37.043 3.168 38.297 3.192 ;
     RECT  38.149 29.76 38.329 32.472 ;
     RECT  37.793 34.08 38.329 34.104 ;
     RECT  38.257 10.848 38.369 10.872 ;
     RECT  38.329 29.76 38.405 34.104 ;
     RECT  38.113 44.448 38.473 52.44 ;
     RECT  37.667 81.648 38.473 84.024 ;
     RECT  37.033 70.32 38.477 71.256 ;
     RECT  38.405 29.76 38.513 33.144 ;
     RECT  38.437 91.2 38.521 91.224 ;
     RECT  37.897 89.424 38.524 89.88 ;
     RECT  37.283 58.944 38.545 61.944 ;
     RECT  38.261 26.544 38.585 28.488 ;
     RECT  38.221 85.632 38.617 85.656 ;
     RECT  37.973 86.688 38.617 87.384 ;
     RECT  38.041 75.408 38.621 78.12 ;
     RECT  38.003 18.672 38.657 22.824 ;
     RECT  38.473 43.872 38.657 52.44 ;
     RECT  37.181 63.072 38.684 68.424 ;
     RECT  37.649 16.512 38.693 17.592 ;
     RECT  38.657 46.128 38.729 52.44 ;
     RECT  38.513 29.76 38.765 33 ;
     RECT  38.545 58.704 38.765 61.944 ;
     RECT  38.684 63.072 38.771 69.336 ;
     RECT  38.765 59.04 38.801 61.944 ;
     RECT  37.865 79.296 38.833 79.512 ;
     RECT  38.693 16.512 38.869 17.4 ;
     RECT  38.761 72.144 38.869 72.168 ;
     RECT  37.469 41.904 38.905 42.504 ;
     RECT  38.765 29.76 38.909 32.808 ;
     RECT  38.869 7.104 39.017 7.128 ;
     RECT  38.477 70.32 39.017 71.112 ;
     RECT  38.905 41.136 39.085 42.504 ;
     RECT  38.657 43.872 39.085 44.472 ;
     RECT  38.257 36.24 39.089 37.752 ;
     RECT  38.869 72.144 39.089 72.552 ;
     RECT  39.085 41.136 39.125 44.472 ;
     RECT  37.901 56.208 39.157 56.424 ;
     RECT  39.157 55.392 39.193 56.424 ;
     RECT  38.225 24.624 39.197 25.08 ;
     RECT  39.125 44.448 39.197 44.472 ;
     RECT  38.771 63.072 39.265 69.144 ;
     RECT  39.193 92.832 39.265 92.856 ;
     RECT  38.617 85.632 39.301 87.384 ;
     RECT  39.089 37.056 39.373 37.752 ;
     RECT  39.193 55.392 39.409 56.472 ;
     RECT  38.053 96.72 39.409 96.744 ;
     RECT  37.907 13.92 39.481 13.944 ;
     RECT  39.157 9.888 39.553 9.912 ;
     RECT  38.585 28.464 39.553 28.488 ;
     RECT  38.909 29.76 39.553 30.12 ;
     RECT  38.473 81.648 39.553 84.312 ;
     RECT  39.481 13.92 39.589 14.136 ;
     RECT  39.445 2.832 39.625 2.856 ;
     RECT  38.153 8.208 39.625 8.232 ;
     RECT  39.589 13.92 39.661 14.856 ;
     RECT  39.625 2.592 39.733 2.856 ;
     RECT  38.797 5.184 39.733 5.208 ;
     RECT  39.301 85.632 39.733 87.816 ;
     RECT  38.195 39.84 39.769 39.864 ;
     RECT  38.729 46.128 39.769 51.096 ;
     RECT  39.733 85.488 39.769 87.816 ;
     RECT  38.524 89.424 39.769 89.448 ;
     RECT  39.017 70.56 39.805 71.112 ;
     RECT  39.089 72.144 39.805 72.504 ;
     RECT  39.733 4.512 39.829 5.208 ;
     RECT  39.692 6.24 39.829 6.264 ;
     RECT  39.661 13.92 39.877 15.048 ;
     RECT  39.197 24.864 39.877 25.08 ;
     RECT  38.585 26.544 39.877 27.432 ;
     RECT  39.553 28.464 39.877 30.12 ;
     RECT  38.909 31.104 39.877 32.808 ;
     RECT  39.769 39.504 39.877 39.864 ;
     RECT  39.125 41.136 39.877 43.368 ;
     RECT  38.621 75.408 39.877 77.688 ;
     RECT  39.769 85.488 39.877 89.448 ;
     RECT  39.769 45.504 39.985 51.096 ;
     RECT  38.729 52.176 39.985 52.44 ;
     RECT  39.265 62.976 39.985 69.144 ;
     RECT  39.805 70.56 39.985 72.504 ;
     RECT  39.265 91.872 40.021 92.856 ;
     RECT  39.949 94.32 40.021 94.344 ;
     RECT  39.877 39.504 40.093 43.368 ;
     RECT  40.021 91.872 40.165 94.344 ;
     RECT  39.733 2.592 40.201 3.048 ;
     RECT  38.657 18.816 40.201 22.824 ;
     RECT  40.093 39.504 40.201 43.416 ;
     RECT  39.985 45.504 40.201 52.44 ;
     RECT  38.689 53.808 40.201 53.832 ;
     RECT  40.201 2.592 40.208 3.144 ;
     RECT  39.829 4.512 40.208 6.264 ;
     RECT  39.625 8.208 40.208 8.328 ;
     RECT  39.553 9.84 40.208 9.912 ;
     RECT  39.877 13.872 40.208 15.048 ;
     RECT  38.869 16.464 40.208 17.4 ;
     RECT  40.201 18.816 40.208 23.064 ;
     RECT  39.877 24.864 40.208 32.808 ;
     RECT  39.913 33.936 40.208 33.96 ;
     RECT  39.373 37.056 40.208 37.992 ;
     RECT  40.201 39.504 40.208 43.848 ;
     RECT  40.201 45.504 40.208 53.832 ;
     RECT  39.409 55.392 40.208 57.432 ;
     RECT  38.801 59.376 40.208 61.944 ;
     RECT  39.985 62.976 40.208 72.504 ;
     RECT  39.877 75.408 40.208 78.216 ;
     RECT  38.833 79.296 40.208 80.376 ;
     RECT  39.553 81.6 40.208 84.312 ;
     RECT  39.877 85.488 40.208 90.408 ;
     RECT  40.165 91.872 40.208 94.392 ;
     RECT  39.409 95.952 40.208 96.744 ;
     RECT  40.208 2.148 40.312 97.212 ;
     RECT  40.312 2.418 40.504 96.942 ;
     RECT  40.504 57.408 40.565 57.912 ;
     RECT  40.504 75.168 40.565 78.168 ;
     RECT  40.504 36.48 40.601 40.632 ;
     RECT  40.504 45.504 40.637 48.216 ;
     RECT  40.504 49.2 40.637 54.072 ;
     RECT  40.601 36.48 40.643 40.488 ;
     RECT  40.565 75.168 40.673 78.12 ;
     RECT  40.504 81.6 40.673 83.784 ;
     RECT  40.504 79.2 40.709 80.28 ;
     RECT  40.504 95.952 40.745 96.744 ;
     RECT  40.504 17.136 40.781 18.984 ;
     RECT  40.673 75.168 40.781 78.072 ;
     RECT  40.504 94.848 40.787 94.872 ;
     RECT  40.643 36.48 40.817 38.808 ;
     RECT  40.504 41.904 40.817 43.848 ;
     RECT  40.781 17.136 40.889 18.84 ;
     RECT  40.504 58.896 40.889 68.184 ;
     RECT  40.889 17.376 40.961 18.744 ;
     RECT  40.817 37.632 40.969 38.808 ;
     RECT  40.504 12.288 40.997 15.048 ;
     RECT  40.637 49.824 40.997 54.072 ;
     RECT  40.504 32.304 41.027 32.328 ;
     RECT  40.504 33.792 41.027 35.064 ;
     RECT  40.504 69.264 41.033 71.64 ;
     RECT  40.504 87.888 41.033 90.504 ;
     RECT  40.969 38.064 41.069 38.808 ;
     RECT  40.504 2.544 41.075 4.824 ;
     RECT  40.781 75.168 41.075 76.872 ;
     RECT  40.504 85.296 41.141 86.712 ;
     RECT  41.033 87.888 41.141 90.072 ;
     RECT  40.997 12.288 41.177 14.232 ;
     RECT  40.997 49.824 41.213 53.16 ;
     RECT  40.504 55.728 41.213 56.04 ;
     RECT  40.781 77.856 41.213 78.072 ;
     RECT  40.961 17.376 41.293 18.504 ;
     RECT  40.504 6.672 41.357 9.096 ;
     RECT  40.504 11.136 41.393 11.16 ;
     RECT  41.177 13.92 41.393 14.232 ;
     RECT  40.889 58.896 41.465 61.032 ;
     RECT  41.213 55.728 41.509 55.752 ;
     RECT  40.565 57.6 41.533 57.912 ;
     RECT  41.465 58.896 41.533 60.216 ;
     RECT  41.213 52.272 41.555 53.16 ;
     RECT  40.817 36.48 41.567 36.504 ;
     RECT  41.177 12.288 41.573 12.936 ;
     RECT  41.533 57.6 41.601 60.216 ;
     RECT  41.075 4.656 41.605 4.824 ;
     RECT  40.709 80.256 41.605 80.28 ;
     RECT  41.141 89.28 41.609 90.072 ;
     RECT  41.509 55.104 41.641 55.752 ;
     RECT  41.605 4.656 41.645 5.448 ;
     RECT  41.027 33.792 41.645 34.776 ;
     RECT  41.601 57.6 41.645 60.168 ;
     RECT  41.567 35.904 41.651 36.504 ;
     RECT  40.504 91.68 41.677 93.336 ;
     RECT  41.645 57.648 41.681 60.168 ;
     RECT  41.645 4.704 41.717 5.448 ;
     RECT  41.573 12.288 41.753 12.792 ;
     RECT  40.745 96.288 41.753 96.744 ;
     RECT  41.069 38.784 41.861 38.808 ;
     RECT  41.681 57.648 41.861 58.68 ;
     RECT  41.681 60.048 41.861 60.168 ;
     RECT  41.141 85.296 41.893 85.8 ;
     RECT  40.643 39.888 41.9 40.488 ;
     RECT  40.637 45.552 41.929 48.216 ;
     RECT  41.9 39.6 41.987 40.488 ;
     RECT  40.673 82.032 41.989 83.784 ;
     RECT  41.893 85.104 41.989 85.8 ;
     RECT  41.533 94.992 42.037 95.016 ;
     RECT  41.717 4.704 42.041 4.776 ;
     RECT  40.504 20.064 42.109 23.544 ;
     RECT  40.504 24.72 42.109 31.128 ;
     RECT  41.033 69.264 42.109 71.112 ;
     RECT  40.889 62.592 42.145 68.184 ;
     RECT  42.109 69.168 42.145 71.496 ;
     RECT  41.677 91.296 42.145 93.336 ;
     RECT  41.645 33.792 42.179 33.816 ;
     RECT  41.357 6.672 42.181 8.376 ;
     RECT  41.929 45.552 42.181 48.312 ;
     RECT  42.145 62.592 42.181 71.496 ;
     RECT  41.987 40.176 42.188 40.488 ;
     RECT  40.817 41.904 42.188 42.504 ;
     RECT  41.555 52.464 42.217 53.16 ;
     RECT  41.075 2.544 42.221 3.48 ;
     RECT  42.109 20.064 42.227 31.128 ;
     RECT  42.181 45.552 42.229 48.408 ;
     RECT  42.227 25.728 42.253 31.128 ;
     RECT  41.785 87.792 42.253 87.816 ;
     RECT  42.037 94.848 42.257 95.016 ;
     RECT  42.188 40.176 42.275 42.504 ;
     RECT  41.293 18.384 42.289 18.504 ;
     RECT  42.133 32.448 42.293 32.472 ;
     RECT  42.229 44.88 42.293 48.408 ;
     RECT  42.293 44.88 42.316 48.312 ;
     RECT  42.181 6.624 42.325 8.376 ;
     RECT  42.253 9.6 42.325 9.624 ;
     RECT  42.217 52.464 42.325 53.352 ;
     RECT  41.641 54.48 42.325 55.752 ;
     RECT  41.213 78.048 42.325 78.072 ;
     RECT  40.709 79.2 42.325 79.224 ;
     RECT  41.989 82.032 42.361 85.8 ;
     RECT  41.075 75.408 42.373 76.872 ;
     RECT  42.325 78.048 42.373 79.224 ;
     RECT  41.609 89.28 42.397 89.928 ;
     RECT  42.221 2.544 42.401 3.384 ;
     RECT  42.257 94.944 42.433 95.016 ;
     RECT  41.753 96.288 42.433 96.504 ;
     RECT  42.289 18.384 42.437 18.84 ;
     RECT  41.393 13.92 42.467 14.184 ;
     RECT  42.325 6.624 42.473 9.624 ;
     RECT  42.253 25.728 42.473 31.368 ;
     RECT  42.473 25.824 42.505 31.368 ;
     RECT  42.473 7.92 42.545 9.624 ;
     RECT  42.289 10.896 42.577 10.92 ;
     RECT  42.373 75.408 42.577 79.224 ;
     RECT  41.605 80.256 42.577 80.712 ;
     RECT  42.361 82.032 42.577 86.04 ;
     RECT  42.437 18.384 42.581 18.504 ;
     RECT  42.467 14.064 42.617 14.184 ;
     RECT  42.275 40.176 42.617 40.488 ;
     RECT  42.577 82.032 42.617 86.616 ;
     RECT  42.145 91.296 42.617 93.768 ;
     RECT  41.651 35.904 42.649 35.928 ;
     RECT  41.293 17.376 42.661 17.4 ;
     RECT  41.213 49.824 42.685 51.24 ;
     RECT  42.325 52.464 42.685 55.752 ;
     RECT  40.504 73.488 42.685 73.512 ;
     RECT  42.617 82.032 42.689 84.312 ;
     RECT  42.577 75.408 42.709 80.712 ;
     RECT  42.685 49.824 42.721 55.752 ;
     RECT  42.181 61.872 42.725 71.496 ;
     RECT  42.685 73.488 42.725 73.656 ;
     RECT  42.649 35.328 42.733 36.36 ;
     RECT  42.689 82.032 42.757 83.064 ;
     RECT  42.433 94.944 42.76 96.504 ;
     RECT  42.545 8.208 42.761 9.624 ;
     RECT  42.721 49.632 42.761 55.752 ;
     RECT  42.709 75.216 42.761 80.712 ;
     RECT  42.617 85.296 42.761 86.616 ;
     RECT  42.253 87.792 42.761 87.96 ;
     RECT  42.617 91.392 42.761 93.768 ;
     RECT  42.76 94.944 42.793 96.552 ;
     RECT  42.761 85.296 42.797 85.608 ;
     RECT  42.793 94.944 42.797 96.744 ;
     RECT  42.397 89.136 42.829 89.928 ;
     RECT  42.725 61.872 42.833 66.552 ;
     RECT  42.761 8.352 42.869 9.624 ;
     RECT  42.733 35.904 42.869 36.36 ;
     RECT  42.761 49.632 42.869 54.12 ;
     RECT  42.757 81.936 42.869 83.064 ;
     RECT  42.833 62.256 42.905 66.552 ;
     RECT  42.761 75.216 42.905 78.744 ;
     RECT  42.793 33.696 42.937 33.72 ;
     RECT  42.617 14.064 42.941 14.136 ;
     RECT  42.797 94.992 42.941 96.744 ;
     RECT  42.649 15.6 42.973 15.624 ;
     RECT  42.865 37.872 42.973 37.896 ;
     RECT  42.869 49.632 42.973 50.04 ;
     RECT  42.725 73.632 42.973 73.656 ;
     RECT  42.905 62.256 42.977 64.968 ;
     RECT  42.905 75.216 42.977 75.384 ;
     RECT  42.797 85.584 42.977 85.608 ;
     RECT  42.829 89.136 42.977 89.976 ;
     RECT  42.973 15.6 43.009 15.768 ;
     RECT  42.761 79.728 43.045 80.712 ;
     RECT  42.905 76.368 43.049 78.744 ;
     RECT  40.817 43.488 43.081 43.512 ;
     RECT  42.473 6.624 43.085 6.936 ;
     RECT  42.869 8.448 43.085 9.624 ;
     RECT  42.577 10.896 43.085 10.968 ;
     RECT  42.316 45.408 43.085 48.312 ;
     RECT  43.085 47.952 43.121 48.312 ;
     RECT  43.049 76.368 43.121 76.392 ;
     RECT  42.761 55.104 43.157 55.752 ;
     RECT  42.941 96 43.157 96.744 ;
     RECT  43.157 96.288 43.189 96.744 ;
     RECT  43.009 15.6 43.225 16.296 ;
     RECT  41.861 57.648 43.225 58.248 ;
     RECT  42.937 33.648 43.297 33.72 ;
     RECT  42.275 41.856 43.297 42.504 ;
     RECT  43.081 43.488 43.297 43.944 ;
     RECT  42.041 4.704 43.333 4.728 ;
     RECT  41.753 12.72 43.333 12.792 ;
     RECT  43.297 33.408 43.333 33.72 ;
     RECT  42.973 37.872 43.333 38.76 ;
     RECT  42.725 67.536 43.337 71.496 ;
     RECT  43.045 79.728 43.337 81.192 ;
     RECT  43.121 48 43.369 48.312 ;
     RECT  42.973 49.44 43.369 50.04 ;
     RECT  42.505 25.824 43.373 31.8 ;
     RECT  42.973 73.632 43.373 74.184 ;
     RECT  43.085 9.264 43.409 9.624 ;
     RECT  43.373 29.568 43.445 31.8 ;
     RECT  42.227 20.064 43.513 24.744 ;
     RECT  43.373 25.824 43.513 28.488 ;
     RECT  43.225 57.648 43.517 58.728 ;
     RECT  41.861 60.144 43.589 60.168 ;
     RECT  42.977 64.416 43.589 64.968 ;
     RECT  43.337 67.536 43.589 71.208 ;
     RECT  43.513 20.064 43.619 28.488 ;
     RECT  42.661 17.376 43.621 17.976 ;
     RECT  43.297 41.856 43.621 43.944 ;
     RECT  42.617 40.416 43.625 40.488 ;
     RECT  43.369 48 43.625 50.04 ;
     RECT  42.977 62.256 43.625 63.432 ;
     RECT  42.689 84.288 43.625 84.312 ;
     RECT  43.225 15.552 43.661 16.296 ;
     RECT  43.049 77.616 43.697 78.744 ;
     RECT  43.337 79.728 43.697 80.856 ;
     RECT  43.333 33.168 43.729 33.72 ;
     RECT  43.621 41.856 43.733 44.04 ;
     RECT  43.697 80.256 43.733 80.664 ;
     RECT  43.333 12.72 43.801 12.984 ;
     RECT  43.733 42.48 43.837 44.04 ;
     RECT  43.333 37.776 43.841 38.808 ;
     RECT  43.589 70.224 43.841 71.208 ;
     RECT  42.761 92.688 43.841 93.768 ;
     RECT  43.801 12.72 43.873 13.08 ;
     RECT  42.941 14.064 43.873 14.088 ;
     RECT  43.661 15.744 43.877 16.296 ;
     RECT  43.619 20.064 43.877 28.344 ;
     RECT  42.869 52.032 43.877 54.12 ;
     RECT  43.517 58.032 43.901 58.728 ;
     RECT  43.877 52.224 43.909 54.12 ;
     RECT  43.157 55.104 43.909 55.416 ;
     RECT  43.841 70.32 43.913 71.208 ;
     RECT  43.729 33.072 43.949 33.72 ;
     RECT  43.841 92.688 43.949 92.712 ;
     RECT  43.909 52.224 43.955 55.416 ;
     RECT  43.625 62.256 43.957 63.048 ;
     RECT  42.977 75.312 43.981 75.384 ;
     RECT  43.877 16.272 43.985 16.296 ;
     RECT  43.841 37.776 43.985 38.76 ;
     RECT  43.955 52.512 43.985 55.416 ;
     RECT  43.901 58.032 43.985 59.016 ;
     RECT  43.589 67.536 43.985 68.904 ;
     RECT  43.981 75.312 43.985 76.296 ;
     RECT  42.761 91.392 43.985 91.704 ;
     RECT  43.985 52.512 43.996 54.552 ;
     RECT  43.625 40.416 44.021 40.44 ;
     RECT  42.977 89.136 44.021 89.448 ;
     RECT  43.957 61.776 44.044 63.048 ;
     RECT  43.085 10.896 44.053 10.92 ;
     RECT  43.621 17.376 44.053 18.216 ;
     RECT  43.373 73.632 44.053 74.088 ;
     RECT  42.869 82.32 44.057 83.064 ;
     RECT  44.053 10.896 44.089 11.256 ;
     RECT  42.401 2.832 44.093 3.384 ;
     RECT  42.869 35.904 44.093 35.928 ;
     RECT  43.873 86.592 44.125 86.616 ;
     RECT  43.085 45.408 44.161 46.872 ;
     RECT  43.625 48 44.161 49.848 ;
     RECT  43.877 23.76 44.165 28.344 ;
     RECT  43.985 37.872 44.165 38.76 ;
     RECT  43.985 58.032 44.173 58.728 ;
     RECT  43.985 76.272 44.197 76.296 ;
     RECT  43.697 77.616 44.197 78.12 ;
     RECT  43.873 12.72 44.201 14.088 ;
     RECT  44.165 24.72 44.201 28.344 ;
     RECT  44.165 37.872 44.201 37.896 ;
     RECT  44.173 58.032 44.237 58.536 ;
     RECT  43.837 42.48 44.269 44.376 ;
     RECT  42.905 66.24 44.269 66.552 ;
     RECT  43.985 67.536 44.269 68.28 ;
     RECT  44.053 73.536 44.269 74.088 ;
     RECT  44.197 90.048 44.281 90.072 ;
     RECT  44.201 24.72 44.309 25.08 ;
     RECT  43.733 80.256 44.339 80.28 ;
     RECT  44.269 42.48 44.341 44.424 ;
     RECT  44.161 45.408 44.341 49.848 ;
     RECT  44.237 58.032 44.345 58.44 ;
     RECT  44.269 66.24 44.345 68.28 ;
     RECT  44.089 10.704 44.377 11.256 ;
     RECT  43.589 64.608 44.377 64.968 ;
     RECT  44.057 82.32 44.377 82.824 ;
     RECT  43.877 20.064 44.381 22.776 ;
     RECT  44.125 85.392 44.387 86.616 ;
     RECT  42.761 87.792 44.387 87.816 ;
     RECT  44.377 64.608 44.413 65.112 ;
     RECT  43.333 4.704 44.453 5.064 ;
     RECT  44.269 73.104 44.453 74.088 ;
     RECT  44.201 13.824 44.489 14.088 ;
     RECT  43.445 29.76 44.489 31.8 ;
     RECT  44.453 73.536 44.489 74.088 ;
     RECT  42.941 94.992 44.521 95.016 ;
     RECT  44.377 10.32 44.557 11.256 ;
     RECT  44.201 12.72 44.557 12.792 ;
     RECT  43.909 50.832 44.561 51 ;
     RECT  43.985 91.68 44.561 91.704 ;
     RECT  44.453 4.704 44.581 4.824 ;
     RECT  44.044 62.16 44.593 63.048 ;
     RECT  44.413 64.608 44.593 65.256 ;
     RECT  44.345 66.24 44.593 68.232 ;
     RECT  44.345 58.032 44.633 58.056 ;
     RECT  44.581 4.608 44.701 4.824 ;
     RECT  44.197 76.272 44.701 78.12 ;
     RECT  44.201 26.064 44.773 28.344 ;
     RECT  44.489 29.76 44.773 31.128 ;
     RECT  43.409 9.264 44.845 9.288 ;
     RECT  44.557 10.32 44.845 12.792 ;
     RECT  44.845 9.024 44.881 12.792 ;
     RECT  43.913 70.32 44.881 70.92 ;
     RECT  43.996 52.512 44.953 54.024 ;
     RECT  43.841 93.744 44.953 93.768 ;
     RECT  44.521 94.848 44.953 95.016 ;
     RECT  44.093 2.832 44.965 2.856 ;
     RECT  44.881 70.32 44.965 71.064 ;
     RECT  44.953 80.928 45.013 80.952 ;
     RECT  44.377 82.032 45.013 82.824 ;
     RECT  44.917 36.24 45.025 36.264 ;
     RECT  44.252 84 45.069 84.024 ;
     RECT  44.953 52.464 45.133 54.024 ;
     RECT  44.593 39.84 45.205 39.864 ;
     RECT  44.737 87.936 45.241 88.776 ;
     RECT  44.965 91.824 45.277 91.848 ;
     RECT  45.069 83.808 45.313 84.024 ;
     RECT  44.881 8.496 45.349 12.792 ;
     RECT  44.965 70.32 45.349 71.112 ;
     RECT  45.313 83.808 45.349 84.072 ;
     RECT  44.387 85.392 45.349 86.328 ;
     RECT  44.953 93.744 45.349 95.016 ;
     RECT  43.189 96.288 45.349 96.888 ;
     RECT  45.349 8.496 45.385 13.08 ;
     RECT  44.965 2.544 45.421 2.856 ;
     RECT  44.701 3.84 45.421 4.824 ;
     RECT  44.309 24.72 45.457 24.744 ;
     RECT  44.593 62.16 45.457 68.232 ;
     RECT  45.349 83.808 45.457 86.328 ;
     RECT  45.241 87.936 45.457 88.968 ;
     RECT  44.377 60.624 45.493 60.648 ;
     RECT  44.489 73.632 45.565 74.088 ;
     RECT  45.457 83.808 45.565 88.968 ;
     RECT  44.341 42.48 45.601 49.848 ;
     RECT  45.421 2.544 45.608 4.824 ;
     RECT  43.085 6.624 45.608 6.648 ;
     RECT  45.385 7.968 45.608 13.08 ;
     RECT  44.629 14.16 45.608 14.184 ;
     RECT  44.053 16.848 45.608 18.216 ;
     RECT  44.381 20.064 45.608 20.424 ;
     RECT  44.381 21.792 45.608 22.776 ;
     RECT  45.457 23.904 45.608 24.744 ;
     RECT  44.773 26.064 45.608 31.128 ;
     RECT  43.949 33.168 45.608 33.72 ;
     RECT  44.773 34.704 45.608 34.728 ;
     RECT  45.025 36.24 45.608 37.704 ;
     RECT  45.205 39.84 45.608 40.344 ;
     RECT  45.601 42.192 45.608 49.848 ;
     RECT  44.561 50.832 45.608 50.856 ;
     RECT  45.133 52.464 45.608 54.504 ;
     RECT  44.413 56.256 45.608 56.328 ;
     RECT  45.493 60.288 45.608 60.648 ;
     RECT  45.457 62.16 45.608 68.952 ;
     RECT  45.349 70.32 45.608 71.448 ;
     RECT  45.565 73.344 45.608 74.088 ;
     RECT  44.701 76.272 45.608 78.696 ;
     RECT  45.013 80.928 45.608 82.824 ;
     RECT  45.565 83.808 45.608 89.016 ;
     RECT  44.924 90.528 45.608 90.552 ;
     RECT  45.277 91.824 45.608 91.992 ;
     RECT  45.349 93.744 45.608 96.888 ;
     RECT  45.608 2.148 45.712 97.212 ;
     RECT  45.712 2.418 45.904 96.942 ;
     RECT  45.904 39.84 46.073 46.872 ;
     RECT  46.073 42.48 46.181 46.872 ;
     RECT  45.904 62.592 46.181 68.952 ;
     RECT  45.904 2.544 46.217 4.728 ;
     RECT  45.904 75.264 46.217 81.24 ;
     RECT  45.904 82.944 46.217 93.336 ;
     RECT  45.904 9.024 46.253 11.256 ;
     RECT  46.217 75.264 46.253 78.696 ;
     RECT  45.904 72.624 46.259 73.896 ;
     RECT  46.073 39.84 46.289 41.256 ;
     RECT  46.181 64.368 46.289 68.952 ;
     RECT  46.217 82.944 46.289 85.752 ;
     RECT  46.253 10.224 46.361 11.256 ;
     RECT  45.904 21.648 46.361 23.976 ;
     RECT  46.289 82.944 46.397 85.512 ;
     RECT  46.289 64.416 46.403 68.952 ;
     RECT  45.904 48.192 46.469 53.544 ;
     RECT  46.181 42.48 46.541 43.944 ;
     RECT  46.181 62.592 46.541 63.24 ;
     RECT  46.361 21.648 46.577 23.928 ;
     RECT  46.217 2.544 46.613 3.384 ;
     RECT  45.904 60.288 46.643 60.792 ;
     RECT  46.253 9.024 46.649 9.096 ;
     RECT  46.253 75.264 46.677 77.928 ;
     RECT  45.904 25.44 46.685 25.464 ;
     RECT  46.469 49.536 46.685 53.544 ;
     RECT  45.904 18.816 46.721 20.664 ;
     RECT  46.289 41.232 46.721 41.256 ;
     RECT  46.217 86.976 46.721 93.336 ;
     RECT  45.904 96.288 46.721 96.792 ;
     RECT  45.904 70.32 46.739 71.448 ;
     RECT  45.904 17.376 46.787 17.64 ;
     RECT  46.181 45.264 46.829 46.872 ;
     RECT  45.904 55.44 46.829 56.328 ;
     RECT  46.721 86.976 46.835 90.888 ;
     RECT  45.904 27.168 46.865 35.352 ;
     RECT  46.403 66.24 46.865 68.952 ;
     RECT  46.397 82.944 46.865 83.112 ;
     RECT  46.865 67.68 46.897 68.952 ;
     RECT  46.865 83.088 46.901 83.112 ;
     RECT  46.739 70.704 46.937 71.448 ;
     RECT  45.904 58.8 46.973 58.824 ;
     RECT  45.904 6.528 47.005 6.552 ;
     RECT  45.904 7.968 47.005 7.992 ;
     RECT  46.721 18.816 47.009 20.424 ;
     RECT  47.005 6.528 47.045 7.992 ;
     RECT  46.361 11.232 47.113 11.256 ;
     RECT  45.904 12.864 47.113 12.888 ;
     RECT  45.904 94.56 47.117 94.68 ;
     RECT  46.649 9.072 47.153 9.096 ;
     RECT  47.009 18.816 47.153 20.088 ;
     RECT  46.685 49.536 47.153 50.424 ;
     RECT  46.613 2.544 47.189 3.096 ;
     RECT  46.259 72.96 47.189 73.896 ;
     RECT  46.721 92.016 47.189 93.336 ;
     RECT  46.829 55.44 47.225 55.464 ;
     RECT  46.835 86.976 47.225 89.592 ;
     RECT  46.217 4.704 47.257 4.728 ;
     RECT  45.904 36.48 47.257 36.936 ;
     RECT  45.904 38.4 47.257 38.424 ;
     RECT  46.865 27.168 47.293 34.776 ;
     RECT  46.937 70.8 47.293 71.448 ;
     RECT  47.225 87.792 47.297 89.496 ;
     RECT  47.117 94.656 47.297 94.68 ;
     RECT  46.541 63.216 47.317 63.24 ;
     RECT  46.403 64.416 47.317 65.064 ;
     RECT  46.217 79.68 47.329 81.24 ;
     RECT  46.361 10.224 47.333 10.248 ;
     RECT  46.897 67.68 47.369 69.72 ;
     RECT  47.297 87.792 47.369 89.448 ;
     RECT  47.329 79.344 47.461 81.24 ;
     RECT  46.469 48.192 47.473 48.456 ;
     RECT  46.835 90.864 47.477 90.888 ;
     RECT  47.365 57.984 47.509 58.008 ;
     RECT  46.397 84.336 47.557 85.512 ;
     RECT  47.317 63.216 47.585 65.064 ;
     RECT  47.189 2.736 47.617 3.096 ;
     RECT  46.541 42.48 47.617 43.128 ;
     RECT  46.721 96.432 47.657 96.792 ;
     RECT  47.461 79.344 47.693 81.528 ;
     RECT  46.829 46.224 47.725 46.872 ;
     RECT  47.473 47.904 47.725 48.456 ;
     RECT  47.189 72.96 47.729 73.56 ;
     RECT  46.677 76.08 47.761 77.928 ;
     RECT  47.693 79.344 47.761 80.376 ;
     RECT  47.617 41.76 47.765 43.128 ;
     RECT  47.113 11.232 47.837 12.888 ;
     RECT  47.257 36.48 47.837 38.424 ;
     RECT  46.865 66.24 47.869 66.552 ;
     RECT  47.837 36.864 47.873 38.424 ;
     RECT  47.761 14.88 47.893 14.904 ;
     RECT  46.787 17.616 47.893 17.64 ;
     RECT  47.257 4.512 47.905 4.728 ;
     RECT  47.369 67.776 47.905 69.72 ;
     RECT  47.293 70.8 47.905 71.496 ;
     RECT  47.837 12 47.909 12.888 ;
     RECT  47.761 76.08 47.909 80.376 ;
     RECT  47.893 14.496 47.939 14.904 ;
     RECT  47.725 15.984 47.939 16.008 ;
     RECT  47.893 17.088 47.939 17.64 ;
     RECT  47.852 86.592 47.939 86.616 ;
     RECT  47.369 87.792 47.939 88.632 ;
     RECT  47.509 57.888 47.941 58.008 ;
     RECT  47.905 67.776 47.945 71.496 ;
     RECT  47.585 64.608 47.948 65.064 ;
     RECT  47.869 66.24 47.948 66.744 ;
     RECT  47.725 46.224 47.981 48.456 ;
     RECT  47.657 96.432 48.013 96.696 ;
     RECT  47.939 87.792 48.017 88.488 ;
     RECT  47.948 64.608 48.035 66.744 ;
     RECT  47.909 76.08 48.035 80.136 ;
     RECT  47.045 6.528 48.049 7.368 ;
     RECT  48.044 74.544 48.131 74.568 ;
     RECT  46.289 39.84 48.157 40.2 ;
     RECT  47.153 49.536 48.193 50.184 ;
     RECT  47.981 46.56 48.197 48.456 ;
     RECT  48.017 87.792 48.197 88.2 ;
     RECT  48.157 39.84 48.229 41.064 ;
     RECT  47.941 57.888 48.229 58.44 ;
     RECT  48.049 6.528 48.233 7.608 ;
     RECT  47.873 36.864 48.233 37.08 ;
     RECT  48.157 83.232 48.265 83.256 ;
     RECT  48.035 64.608 48.269 65.064 ;
     RECT  47.945 69.504 48.269 71.496 ;
     RECT  47.153 19.776 48.301 20.088 ;
     RECT  48.197 87.792 48.305 88.152 ;
     RECT  48.229 57.792 48.337 58.44 ;
     RECT  48.265 83.088 48.337 83.256 ;
     RECT  48.035 66.528 48.341 66.744 ;
     RECT  47.545 10.032 48.373 10.056 ;
     RECT  47.293 26.784 48.373 34.776 ;
     RECT  47.189 92.016 48.377 93.048 ;
     RECT  48.013 96.384 48.377 96.696 ;
     RECT  48.269 70.656 48.38 71.496 ;
     RECT  46.577 21.648 48.413 23.4 ;
     RECT  47.945 67.776 48.413 68.184 ;
     RECT  48.233 36.96 48.421 37.08 ;
     RECT  48.305 87.792 48.449 87.96 ;
     RECT  48.377 96.384 48.449 96.552 ;
     RECT  48.38 70.656 48.467 71.592 ;
     RECT  47.585 63.216 48.481 63.24 ;
     RECT  48.373 26.784 48.485 35.592 ;
     RECT  47.765 42.144 48.485 43.128 ;
     RECT  48.035 76.464 48.485 80.136 ;
     RECT  48.449 96.384 48.485 96.408 ;
     RECT  48.197 46.848 48.517 48.456 ;
     RECT  48.337 57.792 48.521 59.16 ;
     RECT  48.269 64.608 48.553 65.016 ;
     RECT  48.193 49.536 48.581 50.712 ;
     RECT  46.685 51.744 48.581 53.544 ;
     RECT  47.873 38.4 48.593 38.424 ;
     RECT  48.521 57.792 48.593 58.152 ;
     RECT  47.909 12.864 48.629 12.888 ;
     RECT  48.581 49.536 48.629 53.544 ;
     RECT  48.449 87.792 48.629 87.816 ;
     RECT  48.341 66.72 48.661 66.744 ;
     RECT  48.485 42.144 48.665 42.792 ;
     RECT  48.593 57.84 48.665 58.152 ;
     RECT  47.557 84.288 48.665 85.512 ;
     RECT  47.509 18.672 48.701 18.696 ;
     RECT  48.629 49.536 48.701 53.4 ;
     RECT  46.643 60.288 48.809 60.552 ;
     RECT  48.485 26.784 48.881 34.776 ;
     RECT  48.769 72.384 48.913 72.408 ;
     RECT  47.617 2.736 48.949 3.336 ;
     RECT  48.517 46.848 48.949 48.504 ;
     RECT  48.701 49.536 48.949 52.824 ;
     RECT  48.809 60.336 48.949 60.552 ;
     RECT  48.229 39.648 48.989 41.064 ;
     RECT  48.949 46.848 48.989 52.824 ;
     RECT  48.269 69.504 48.989 69.528 ;
     RECT  48.949 2.736 49.021 3.384 ;
     RECT  47.905 4.512 49.021 4.968 ;
     RECT  47.939 17.088 49.021 17.112 ;
     RECT  49.021 2.736 49.025 4.968 ;
     RECT  48.373 10.032 49.052 10.248 ;
     RECT  48.337 81.984 49.057 82.008 ;
     RECT  48.337 83.04 49.057 83.256 ;
     RECT  47.939 14.496 49.061 14.52 ;
     RECT  49.021 16.032 49.061 17.112 ;
     RECT  48.841 90.576 49.061 90.6 ;
     RECT  49.025 2.928 49.093 4.968 ;
     RECT  48.233 7.584 49.093 7.608 ;
     RECT  48.709 38.64 49.129 38.664 ;
     RECT  48.989 39.648 49.129 40.872 ;
     RECT  48.913 72.384 49.129 72.504 ;
     RECT  47.729 73.536 49.129 73.56 ;
     RECT  49.052 9.984 49.133 10.248 ;
     RECT  49.133 9.984 49.139 10.056 ;
     RECT  48.233 6.528 49.165 6.552 ;
     RECT  48.301 24.528 49.165 24.552 ;
     RECT  49.129 72.384 49.169 73.56 ;
     RECT  48.665 42.144 49.205 42.504 ;
     RECT  48.521 59.136 49.205 59.16 ;
     RECT  48.481 62.784 49.237 63.24 ;
     RECT  48.421 36.96 49.241 36.984 ;
     RECT  48.377 92.016 49.241 92.232 ;
     RECT  48.301 19.776 49.277 20.568 ;
     RECT  48.881 32.688 49.277 34.776 ;
     RECT  48.413 21.984 49.309 23.4 ;
     RECT  48.413 68.064 49.309 68.184 ;
     RECT  48.485 76.56 49.309 80.136 ;
     RECT  48.881 26.784 49.313 31.272 ;
     RECT  49.093 2.928 49.345 5.112 ;
     RECT  49.165 6.096 49.345 6.552 ;
     RECT  49.093 7.584 49.345 8.376 ;
     RECT  49.169 72.624 49.345 73.56 ;
     RECT  49.309 76.56 49.345 80.856 ;
     RECT  49.057 81.984 49.345 83.256 ;
     RECT  49.277 34.224 49.349 34.776 ;
     RECT  49.313 29.568 49.385 31.272 ;
     RECT  49.345 72.624 49.417 73.8 ;
     RECT  49.093 75.264 49.417 75.288 ;
     RECT  48.661 66.72 49.453 66.888 ;
     RECT  49.309 68.064 49.453 69.24 ;
     RECT  49.277 32.688 49.529 32.856 ;
     RECT  49.349 34.464 49.565 34.776 ;
     RECT  49.129 38.64 49.565 40.872 ;
     RECT  48.989 49.008 49.565 52.824 ;
     RECT  49.565 34.512 49.601 34.776 ;
     RECT  49.313 26.784 49.633 27.912 ;
     RECT  49.565 39.312 49.637 40.872 ;
     RECT  49.417 72.624 49.673 75.288 ;
     RECT  48.949 60.336 49.709 61.464 ;
     RECT  49.345 76.56 49.709 83.256 ;
     RECT  48.665 84.288 49.741 84.84 ;
     RECT  49.637 39.312 49.745 39.864 ;
     RECT  49.637 40.848 49.745 40.872 ;
     RECT  49.709 76.8 49.753 83.256 ;
     RECT  49.709 60.336 49.777 60.36 ;
     RECT  49.061 16.032 49.811 17.016 ;
     RECT  49.345 2.928 49.813 6.552 ;
     RECT  49.345 7.584 49.813 8.76 ;
     RECT  49.237 62.784 49.849 63.288 ;
     RECT  48.467 70.656 49.849 71.112 ;
     RECT  49.753 83.04 49.849 83.256 ;
     RECT  49.741 84.288 49.849 85.656 ;
     RECT  49.765 18.384 49.852 18.408 ;
     RECT  49.453 66.72 49.853 69.24 ;
     RECT  49.741 55.488 49.885 55.512 ;
     RECT  48.913 11.904 49.921 11.928 ;
     RECT  49.811 16.032 49.925 16.92 ;
     RECT  49.529 32.688 49.925 32.712 ;
     RECT  49.309 21.984 49.957 23.544 ;
     RECT  49.165 24.528 49.957 24.648 ;
     RECT  48.989 46.848 49.961 47.928 ;
     RECT  49.673 72.624 49.961 74.616 ;
     RECT  49.961 46.848 49.993 46.872 ;
     RECT  49.277 19.776 49.997 20.184 ;
     RECT  49.957 21.984 49.997 24.648 ;
     RECT  49.993 36.816 50.029 36.84 ;
     RECT  49.993 45.984 50.029 46.872 ;
     RECT  49.709 61.44 50.033 61.464 ;
     RECT  50.029 36.384 50.137 36.84 ;
     RECT  49.849 62.736 50.137 63.288 ;
     RECT  48.553 64.368 50.137 65.016 ;
     RECT  49.849 25.632 50.281 25.656 ;
     RECT  49.633 26.64 50.281 27.912 ;
     RECT  48.665 57.84 50.317 57.864 ;
     RECT  49.813 2.928 50.353 8.76 ;
     RECT  49.561 94.944 50.353 94.968 ;
     RECT  50.137 62.736 50.389 65.016 ;
     RECT  50.137 36.192 50.425 36.84 ;
     RECT  50.353 94.608 50.425 94.968 ;
     RECT  50.029 45.504 50.461 46.872 ;
     RECT  50.281 25.632 50.497 27.912 ;
     RECT  49.205 42.48 50.497 42.504 ;
     RECT  50.348 43.776 50.497 43.8 ;
     RECT  50.425 36.192 50.533 37.032 ;
     RECT  49.139 10.032 50.569 10.056 ;
     RECT  50.533 35.808 50.605 37.032 ;
     RECT  50.425 94.128 50.605 94.968 ;
     RECT  50.605 35.808 50.641 37.992 ;
     RECT  49.885 55.44 50.677 55.512 ;
     RECT  49.853 67.152 50.677 69.24 ;
     RECT  49.849 70.656 50.677 71.64 ;
     RECT  50.641 35.808 50.705 38.088 ;
     RECT  49.849 83.04 50.741 85.656 ;
     RECT  50.741 82.992 50.749 85.656 ;
     RECT  50.317 57.12 50.773 57.864 ;
     RECT  49.777 59.472 50.773 60.36 ;
     RECT  49.597 92.544 50.785 92.808 ;
     RECT  50.605 94.032 50.785 94.968 ;
     RECT  50.569 10.032 50.821 10.104 ;
     RECT  49.601 34.512 50.821 34.536 ;
     RECT  50.705 35.808 50.821 38.232 ;
     RECT  50.497 42.48 50.821 43.8 ;
     RECT  49.753 76.8 50.821 81.72 ;
     RECT  50.353 2.928 50.849 8.808 ;
     RECT  50.497 47.952 50.857 47.976 ;
     RECT  49.565 49.008 50.857 49.032 ;
     RECT  49.385 29.568 50.869 31.128 ;
     RECT  50.389 32.448 50.869 32.472 ;
     RECT  50.677 55.44 50.965 55.56 ;
     RECT  50.849 2.832 51.008 8.808 ;
     RECT  50.821 10.032 51.008 10.92 ;
     RECT  49.921 11.904 51.008 12.792 ;
     RECT  49.925 16.848 51.008 16.92 ;
     RECT  49.997 19.776 51.008 20.088 ;
     RECT  49.997 21.984 51.008 22.824 ;
     RECT  49.997 23.856 51.008 24.648 ;
     RECT  50.497 25.632 51.008 28.296 ;
     RECT  50.869 29.568 51.008 32.472 ;
     RECT  50.821 34.512 51.008 38.232 ;
     RECT  49.745 39.312 51.008 39.336 ;
     RECT  50.821 42.48 51.008 44.472 ;
     RECT  50.461 45.456 51.008 46.872 ;
     RECT  50.857 47.952 51.008 49.032 ;
     RECT  49.565 50.16 51.008 52.824 ;
     RECT  50.965 54.864 51.008 55.56 ;
     RECT  50.773 57.12 51.008 60.36 ;
     RECT  50.869 61.392 51.008 61.416 ;
     RECT  50.389 62.736 51.008 65.976 ;
     RECT  50.677 67.152 51.008 71.64 ;
     RECT  49.961 72.816 51.008 74.616 ;
     RECT  50.821 76.8 51.008 81.96 ;
     RECT  50.749 82.992 51.008 86.04 ;
     RECT  50.785 90.096 51.008 90.12 ;
     RECT  50.785 92.544 51.008 94.968 ;
     RECT  50.821 96.288 51.008 96.312 ;
     RECT  51.008 2.148 51.112 97.212 ;
     RECT  51.112 2.418 51.304 96.942 ;
     RECT  51.304 3.024 51.329 4.728 ;
     RECT  51.304 55.44 51.329 55.512 ;
     RECT  51.304 67.296 51.365 74.424 ;
     RECT  51.304 75.84 51.365 85.512 ;
     RECT  51.304 95.76 51.365 96.312 ;
     RECT  51.304 33.36 51.401 35.832 ;
     RECT  51.365 80.832 51.401 85.512 ;
     RECT  51.304 61.344 51.437 61.416 ;
     RECT  51.401 81.36 51.437 85.512 ;
     RECT  51.304 19.776 51.509 22.824 ;
     RECT  51.437 83.04 51.509 85.512 ;
     RECT  51.509 83.232 51.545 85.512 ;
     RECT  51.304 6.048 51.581 6.888 ;
     RECT  51.304 16.848 51.581 17.064 ;
     RECT  51.304 36.864 51.581 40.728 ;
     RECT  51.365 96.192 51.617 96.312 ;
     RECT  51.329 3.024 51.653 3.048 ;
     RECT  51.304 47.952 51.653 53.112 ;
     RECT  51.329 4.128 51.689 4.728 ;
     RECT  51.653 48 51.689 53.112 ;
     RECT  51.689 4.704 51.725 4.728 ;
     RECT  51.689 48 51.761 52.92 ;
     RECT  51.304 86.544 51.761 86.664 ;
     RECT  51.304 90.096 51.797 90.984 ;
     RECT  51.304 45.168 51.869 46.872 ;
     RECT  51.329 55.44 51.905 55.464 ;
     RECT  51.304 57.12 51.905 57.144 ;
     RECT  51.581 16.896 51.971 17.064 ;
     RECT  51.761 48 51.977 52.776 ;
     RECT  51.617 96.192 51.977 96.216 ;
     RECT  51.509 19.776 52.019 21.144 ;
     RECT  52.019 21.12 52.057 21.144 ;
     RECT  51.304 92.16 52.085 94.632 ;
     RECT  51.971 17.04 52.121 17.064 ;
     RECT  51.304 12.768 52.157 13.08 ;
     RECT  51.581 36.864 52.157 37.512 ;
     RECT  51.545 83.376 52.229 85.512 ;
     RECT  51.304 14.208 52.265 14.856 ;
     RECT  52.157 37.008 52.265 37.512 ;
     RECT  51.977 48 52.265 52.632 ;
     RECT  51.401 33.36 52.301 34.776 ;
     RECT  51.509 22.128 52.307 22.824 ;
     RECT  51.304 23.856 52.365 24.552 ;
     RECT  52.019 19.776 52.373 19.992 ;
     RECT  51.365 70.704 52.405 74.424 ;
     RECT  52.365 23.856 52.553 23.88 ;
     RECT  51.761 86.544 52.553 86.568 ;
     RECT  52.477 54.72 52.589 54.744 ;
     RECT  51.304 64.608 52.589 66.168 ;
     RECT  51.581 38.688 52.625 40.728 ;
     RECT  51.304 30.096 52.661 31.944 ;
     RECT  52.265 48 52.693 50.664 ;
     RECT  51.797 90.96 52.697 90.984 ;
     RECT  52.373 19.776 52.729 19.8 ;
     RECT  51.304 42.384 52.729 43.608 ;
     RECT  51.869 45.504 52.729 46.872 ;
     RECT  52.693 47.904 52.729 50.664 ;
     RECT  52.729 45.504 52.733 50.664 ;
     RECT  52.585 56.208 52.733 56.232 ;
     RECT  52.405 70.704 52.733 74.472 ;
     RECT  51.581 6.048 52.765 6.072 ;
     RECT  51.365 67.296 52.765 69.24 ;
     RECT  52.625 40.32 52.769 40.728 ;
     RECT  52.765 6.048 52.873 6.936 ;
     RECT  51.437 81.36 52.933 82.056 ;
     RECT  52.229 83.376 52.933 84.408 ;
     RECT  52.729 42.384 52.945 43.8 ;
     RECT  51.365 75.84 52.949 79.8 ;
     RECT  52.933 81.36 52.949 84.408 ;
     RECT  52.873 5.088 52.981 6.936 ;
     RECT  52.981 4.128 52.985 6.936 ;
     RECT  52.837 88.08 53.017 88.104 ;
     RECT  52.693 2.976 53.021 3 ;
     RECT  52.265 37.008 53.021 37.032 ;
     RECT  52.307 22.8 53.057 22.824 ;
     RECT  52.945 42.144 53.089 43.8 ;
     RECT  52.949 81.36 53.093 84.36 ;
     RECT  53.093 84.144 53.129 84.36 ;
     RECT  53.053 8.688 53.18 8.712 ;
     RECT  51.304 25.584 53.197 27.768 ;
     RECT  52.661 30.096 53.201 31.896 ;
     RECT  53.017 54.672 53.201 54.696 ;
     RECT  53.18 8.448 53.221 8.712 ;
     RECT  51.304 10.032 53.221 10.056 ;
     RECT  53.201 30.096 53.233 31.128 ;
     RECT  53.089 42.144 53.233 44.088 ;
     RECT  53.221 8.448 53.267 10.056 ;
     RECT  53.267 8.688 53.309 10.056 ;
     RECT  52.765 67.296 53.341 69.432 ;
     RECT  52.733 70.704 53.341 74.424 ;
     RECT  52.733 45.744 53.345 50.664 ;
     RECT  52.589 64.608 53.345 65.544 ;
     RECT  53.017 88.08 53.345 88.344 ;
     RECT  52.729 19.392 53.377 19.8 ;
     RECT  53.345 46.848 53.381 50.664 ;
     RECT  53.341 67.296 53.417 74.424 ;
     RECT  53.381 47.088 53.485 50.664 ;
     RECT  53.233 42.144 53.525 44.136 ;
     RECT  53.345 88.08 53.525 88.104 ;
     RECT  52.981 23.808 53.557 23.832 ;
     RECT  53.197 25.152 53.557 27.768 ;
     RECT  53.485 59.808 53.557 59.832 ;
     RECT  51.437 61.392 53.557 61.416 ;
     RECT  52.301 33.408 53.561 34.776 ;
     RECT  52.085 92.16 53.561 93.864 ;
     RECT  52.157 13.056 53.593 13.08 ;
     RECT  53.309 8.688 53.597 8.712 ;
     RECT  53.516 86.688 53.603 86.712 ;
     RECT  53.345 64.608 53.612 65.016 ;
     RECT  53.557 23.808 53.629 27.768 ;
     RECT  53.525 42.384 53.629 44.136 ;
     RECT  52.985 4.128 53.633 4.824 ;
     RECT  52.985 6.048 53.633 6.936 ;
     RECT  53.593 13.056 53.633 13.608 ;
     RECT  52.265 52.032 53.633 52.344 ;
     RECT  53.557 58.944 53.665 59.832 ;
     RECT  52.229 85.488 53.665 85.512 ;
     RECT  53.521 96.528 53.665 96.552 ;
     RECT  53.561 92.16 53.669 92.184 ;
     RECT  53.633 52.032 53.705 52.296 ;
     RECT  52.949 76.32 53.705 79.8 ;
     RECT  52.333 17.568 53.708 17.592 ;
     RECT  53.377 18.864 53.708 19.8 ;
     RECT  53.612 64.512 53.737 65.016 ;
     RECT  53.708 17.568 53.741 19.8 ;
     RECT  53.561 34.464 53.741 34.776 ;
     RECT  53.413 41.088 53.773 41.112 ;
     RECT  53.665 58.944 53.773 60.072 ;
     RECT  53.557 61.392 53.773 61.464 ;
     RECT  53.737 63.696 53.777 65.016 ;
     RECT  53.741 17.568 53.795 18.888 ;
     RECT  53.629 23.376 53.809 27.768 ;
     RECT  53.485 47.088 53.813 50.76 ;
     RECT  53.665 96.336 53.849 96.552 ;
     RECT  53.345 45.744 53.921 45.816 ;
     RECT  53.665 85.488 53.953 85.56 ;
     RECT  53.561 93.264 53.953 93.864 ;
     RECT  53.557 95.04 53.953 95.064 ;
     RECT  53.417 67.296 53.957 72.408 ;
     RECT  53.773 58.944 54.025 61.464 ;
     RECT  53.705 76.656 54.025 79.8 ;
     RECT  53.629 42.384 54.029 44.472 ;
     RECT  53.989 20.448 54.085 20.472 ;
     RECT  53.269 21.792 54.085 21.816 ;
     RECT  53.701 57.696 54.097 57.912 ;
     RECT  54.025 58.896 54.097 61.464 ;
     RECT  53.093 81.36 54.097 82.776 ;
     RECT  53.953 85.488 54.101 86.04 ;
     RECT  53.809 23.376 54.131 28.008 ;
     RECT  54.097 57.696 54.169 61.464 ;
     RECT  53.813 47.568 54.209 50.76 ;
     RECT  54.169 57.696 54.241 62.04 ;
     RECT  54.061 2.832 54.245 2.856 ;
     RECT  53.921 45.744 54.245 45.768 ;
     RECT  54.241 57.696 54.245 62.088 ;
     RECT  54.209 47.808 54.277 50.76 ;
     RECT  53.705 52.032 54.277 52.2 ;
     RECT  54.025 76.656 54.277 79.992 ;
     RECT  53.953 93.264 54.277 95.064 ;
     RECT  53.849 96.336 54.277 96.36 ;
     RECT  53.957 67.296 54.281 69.576 ;
     RECT  53.741 34.608 54.313 34.776 ;
     RECT  53.777 63.696 54.313 64.728 ;
     RECT  54.277 93.264 54.317 96.36 ;
     RECT  54.131 23.808 54.349 28.008 ;
     RECT  53.233 29.616 54.349 31.128 ;
     RECT  54.061 66.192 54.421 66.216 ;
     RECT  54.277 47.808 54.425 52.2 ;
     RECT  53.795 17.568 54.457 17.688 ;
     RECT  54.205 56.256 54.457 56.28 ;
     RECT  53.633 4.8 54.493 4.824 ;
     RECT  53.633 6.048 54.493 6.072 ;
     RECT  53.773 41.088 54.493 41.256 ;
     RECT  54.245 57.696 54.497 58.968 ;
     RECT  53.561 33.408 54.529 33.432 ;
     RECT  54.493 4.8 54.533 6.072 ;
     RECT  54.085 20.448 54.565 21.816 ;
     RECT  54.097 81.312 54.601 82.776 ;
     RECT  54.277 76.656 54.605 80.232 ;
     RECT  52.265 14.832 54.629 14.856 ;
     RECT  54.457 55.968 54.637 56.28 ;
     RECT  54.497 57.696 54.637 58.008 ;
     RECT  54.601 81.312 54.637 82.968 ;
     RECT  53.129 84.144 54.637 84.168 ;
     RECT  54.313 34.608 54.641 35.592 ;
     RECT  54.313 63.6 54.641 64.728 ;
     RECT  54.641 34.656 54.673 35.592 ;
     RECT  54.605 76.656 54.677 79.992 ;
     RECT  53.957 70.704 54.709 72.408 ;
     RECT  53.633 13.584 54.713 13.608 ;
     RECT  54.629 14.832 54.713 14.952 ;
     RECT  53.795 18.768 54.713 18.888 ;
     RECT  54.677 76.656 54.713 79.56 ;
     RECT  53.917 11.712 54.749 11.736 ;
     RECT  54.565 20.448 54.749 22.296 ;
     RECT  54.281 68.16 54.749 69.576 ;
     RECT  54.709 70.704 54.749 72.744 ;
     RECT  54.457 17.088 54.755 17.688 ;
     RECT  53.309 10.032 54.781 10.056 ;
     RECT  54.749 70.704 54.785 71.688 ;
     RECT  54.749 20.448 54.821 21.432 ;
     RECT  54.245 60.576 54.821 62.088 ;
     RECT  54.749 72.72 54.821 72.744 ;
     RECT  53.449 15.984 54.853 16.008 ;
     RECT  54.133 91.68 54.853 91.704 ;
     RECT  54.029 42.432 54.857 44.472 ;
     RECT  54.853 91.632 54.889 91.704 ;
     RECT  54.317 93.264 54.889 93.48 ;
     RECT  54.317 95.04 54.925 96.36 ;
     RECT  54.349 23.808 54.929 31.128 ;
     RECT  54.529 33.408 54.961 33.576 ;
     RECT  54.421 66.192 54.961 67.176 ;
     RECT  54.713 18.768 54.965 18.792 ;
     RECT  54.425 47.808 54.973 51.768 ;
     RECT  54.781 9.36 54.997 10.056 ;
     RECT  54.956 11.664 54.997 11.688 ;
     RECT  54.961 33.024 54.997 33.576 ;
     RECT  54.973 47.808 55.037 49.848 ;
     RECT  54.713 76.656 55.069 76.968 ;
     RECT  54.997 9.36 55.081 11.688 ;
     RECT  55.081 9.36 55.1 10.056 ;
     RECT  52.625 38.688 55.105 39.096 ;
     RECT  54.493 40.32 55.105 41.256 ;
     RECT  54.637 81.312 55.105 84.168 ;
     RECT  54.101 85.536 55.105 86.04 ;
     RECT  54.821 20.448 55.109 21.384 ;
     RECT  54.901 53.184 55.109 53.208 ;
     RECT  54.533 4.8 55.187 5.112 ;
     RECT  55.1 8.928 55.187 10.056 ;
     RECT  55.187 4.8 55.217 4.824 ;
     RECT  55.105 38.688 55.283 41.256 ;
     RECT  54.889 91.632 55.285 93.48 ;
     RECT  54.925 95.04 55.285 96.888 ;
     RECT  54.973 51.504 55.325 51.768 ;
     RECT  54.641 63.696 55.325 64.728 ;
     RECT  54.565 87.408 55.357 87.432 ;
     RECT  54.929 23.808 55.361 27.72 ;
     RECT  55.285 91.632 55.361 96.888 ;
     RECT  54.713 14.832 55.393 14.856 ;
     RECT  55.361 23.808 55.393 24.696 ;
     RECT  55.283 38.688 55.393 39.096 ;
     RECT  55.393 23.04 55.433 24.696 ;
     RECT  55.037 48.768 55.433 49.848 ;
     RECT  55.357 87.408 55.433 88.392 ;
     RECT  54.997 32.496 55.501 33.576 ;
     RECT  55.393 37.872 55.501 39.096 ;
     RECT  54.785 70.704 55.501 71.208 ;
     RECT  55.325 63.792 55.537 64.728 ;
     RECT  54.961 65.76 55.537 67.176 ;
     RECT  55.069 76.416 55.537 76.968 ;
     RECT  55.105 81.312 55.537 86.04 ;
     RECT  54.853 15.984 55.628 16.392 ;
     RECT  55.537 75.936 55.645 76.968 ;
     RECT  54.637 55.968 55.681 58.008 ;
     RECT  54.929 29.472 55.717 31.128 ;
     RECT  55.681 55.968 55.717 58.728 ;
     RECT  55.393 14.592 55.753 14.856 ;
     RECT  55.753 13.632 55.813 14.856 ;
     RECT  55.628 15.84 55.813 16.392 ;
     RECT  55.283 40.8 55.813 41.256 ;
     RECT  54.857 42.432 55.813 43.944 ;
     RECT  55.537 81.12 55.825 86.04 ;
     RECT  55.433 88.176 55.825 88.392 ;
     RECT  54.673 34.656 55.861 36.168 ;
     RECT  55.813 13.632 55.933 16.392 ;
     RECT  55.433 23.04 55.933 24.408 ;
     RECT  55.717 29.472 55.933 31.176 ;
     RECT  55.501 32.208 55.933 33.576 ;
     RECT  54.713 78.624 55.933 79.56 ;
     RECT  55.081 11.232 55.957 11.688 ;
     RECT  55.933 13.248 55.957 16.392 ;
     RECT  54.821 61.2 56.012 62.088 ;
     RECT  55.717 55.968 56.053 58.824 ;
     RECT  54.755 17.472 56.077 17.688 ;
     RECT  55.933 78.624 56.077 79.8 ;
     RECT  55.825 80.88 56.077 86.04 ;
     RECT  55.825 88.176 56.101 88.92 ;
     RECT  55.501 70.56 56.108 71.208 ;
     RECT  55.109 20.496 56.113 21.384 ;
     RECT  56.113 20.496 56.149 21.48 ;
     RECT  56.108 70.56 56.149 71.592 ;
     RECT  53.417 73.824 56.149 74.424 ;
     RECT  55.645 75.408 56.149 76.968 ;
     RECT  55.105 3.696 56.185 3.72 ;
     RECT  55.187 9.36 56.245 9.384 ;
     RECT  55.861 34.656 56.252 36.312 ;
     RECT  56.245 8.784 56.293 9.384 ;
     RECT  55.933 29.472 56.293 33.576 ;
     RECT  55.813 51.792 56.293 51.816 ;
     RECT  55.537 63.792 56.329 67.176 ;
     RECT  54.749 68.496 56.329 69.576 ;
     RECT  56.077 78.624 56.329 86.04 ;
     RECT  56.329 63.792 56.365 69.576 ;
     RECT  56.185 3.024 56.408 3.72 ;
     RECT  55.141 6.096 56.408 6.12 ;
     RECT  56.293 8.544 56.408 9.384 ;
     RECT  55.957 11.232 56.408 16.392 ;
     RECT  56.077 17.472 56.408 18.264 ;
     RECT  56.149 19.536 56.408 21.48 ;
     RECT  55.933 22.848 56.408 24.408 ;
     RECT  55.361 25.824 56.408 27.72 ;
     RECT  56.293 29.04 56.408 33.576 ;
     RECT  56.252 34.608 56.408 36.312 ;
     RECT  55.501 37.584 56.408 39.096 ;
     RECT  55.813 40.8 56.408 43.944 ;
     RECT  55.609 46.512 56.408 46.536 ;
     RECT  55.433 48.864 56.408 49.848 ;
     RECT  56.293 51.216 56.408 51.816 ;
     RECT  55.789 54.144 56.408 54.168 ;
     RECT  56.053 55.968 56.408 59.208 ;
     RECT  56.012 60.24 56.408 62.088 ;
     RECT  56.365 63.6 56.408 69.576 ;
     RECT  56.149 70.56 56.408 71.928 ;
     RECT  56.149 73.824 56.408 76.968 ;
     RECT  56.329 78.624 56.408 86.856 ;
     RECT  56.101 88.176 56.408 89.88 ;
     RECT  55.361 91.68 56.408 96.888 ;
     RECT  56.408 2.148 56.512 97.212 ;
     RECT  56.512 2.418 56.704 96.942 ;
     RECT  56.704 35.424 56.765 35.592 ;
     RECT  56.704 13.104 56.801 18.744 ;
     RECT  56.704 8.784 56.819 9.72 ;
     RECT  56.801 13.104 56.819 17.112 ;
     RECT  56.819 13.104 56.845 13.128 ;
     RECT  56.704 11.664 56.915 11.976 ;
     RECT  56.704 73.248 56.945 73.848 ;
     RECT  56.704 77.424 56.981 88.392 ;
     RECT  56.704 46.56 57.017 52.248 ;
     RECT  56.819 14.208 57.052 17.112 ;
     RECT  57.052 14.208 57.053 15 ;
     RECT  56.704 40.464 57.053 43.944 ;
     RECT  56.704 66.768 57.053 69 ;
     RECT  57.052 15.984 57.089 17.112 ;
     RECT  56.704 20.736 57.089 24.408 ;
     RECT  56.704 25.68 57.089 33.048 ;
     RECT  56.704 96.288 57.089 96.312 ;
     RECT  56.915 11.664 57.197 11.688 ;
     RECT  56.704 3.024 57.305 3.336 ;
     RECT  57.089 20.736 57.341 23.928 ;
     RECT  57.089 32.208 57.341 33.048 ;
     RECT  57.089 17.088 57.377 17.112 ;
     RECT  57.017 48.336 57.413 52.248 ;
     RECT  56.704 63.216 57.413 65.784 ;
     RECT  57.341 21.648 57.443 23.928 ;
     RECT  56.704 75.408 57.443 76.152 ;
     RECT  57.341 32.208 57.449 32.808 ;
     RECT  56.981 86.64 57.485 88.392 ;
     RECT  56.801 18.24 57.521 18.744 ;
     RECT  57.053 66.768 57.521 67.848 ;
     RECT  57.089 25.68 57.539 31.128 ;
     RECT  57.413 63.792 57.557 65.784 ;
     RECT  56.704 55.248 57.587 55.272 ;
     RECT  56.704 56.352 57.587 57 ;
     RECT  56.704 58.128 57.587 59.208 ;
     RECT  57.053 40.464 57.665 42.504 ;
     RECT  57.587 58.896 57.665 58.92 ;
     RECT  56.704 91.68 57.665 94.584 ;
     RECT  57.449 32.208 57.701 32.76 ;
     RECT  56.704 60.576 57.701 61.608 ;
     RECT  57.485 86.832 57.733 88.392 ;
     RECT  56.704 70.56 57.737 70.872 ;
     RECT  57.443 23.136 57.773 23.928 ;
     RECT  57.539 25.68 57.773 27.912 ;
     RECT  57.053 43.536 57.805 43.944 ;
     RECT  57.053 68.976 57.805 69 ;
     RECT  57.443 75.408 57.805 76.104 ;
     RECT  57.017 46.56 57.829 47.064 ;
     RECT  56.945 73.248 57.841 73.272 ;
     RECT  56.704 89.424 57.841 90.072 ;
     RECT  57.665 91.68 57.841 92.472 ;
     RECT  57.413 48.336 57.875 52.2 ;
     RECT  57.841 73.056 57.881 73.272 ;
     RECT  57.805 43.536 57.889 44.424 ;
     RECT  57.805 68.976 57.913 69.192 ;
     RECT  57.805 74.928 57.913 76.104 ;
     RECT  57.841 89.424 57.953 92.472 ;
     RECT  56.819 9.696 57.989 9.72 ;
     RECT  57.305 3.312 58.021 3.336 ;
     RECT  56.704 5.136 58.021 6.12 ;
     RECT  57.913 68.976 58.021 69.24 ;
     RECT  57.953 89.424 58.061 89.496 ;
     RECT  57.881 73.056 58.093 73.08 ;
     RECT  57.913 74.688 58.093 76.104 ;
     RECT  57.733 86.832 58.093 88.44 ;
     RECT  58.021 3.312 58.108 6.12 ;
     RECT  57.665 42.48 58.129 42.504 ;
     RECT  57.889 43.536 58.129 43.56 ;
     RECT  56.981 77.424 58.133 85.464 ;
     RECT  57.773 25.68 58.163 25.848 ;
     RECT  57.875 50.16 58.163 52.2 ;
     RECT  57.841 34.032 58.165 34.056 ;
     RECT  58.093 74.112 58.169 76.104 ;
     RECT  57.773 23.136 58.204 23.688 ;
     RECT  57.557 64.944 58.205 65.784 ;
     RECT  57.953 90.624 58.241 92.472 ;
     RECT  58.133 85.008 58.273 85.464 ;
     RECT  58.163 50.784 58.277 52.2 ;
     RECT  57.443 21.648 58.313 21.672 ;
     RECT  57.829 45.552 58.313 47.064 ;
     RECT  56.704 36.576 58.349 39.24 ;
     RECT  57.521 66.768 58.349 67.8 ;
     RECT  58.349 36.576 58.385 39.096 ;
     RECT  58.021 68.928 58.385 69.24 ;
     RECT  58.093 72.672 58.417 73.08 ;
     RECT  58.313 45.552 58.421 46.104 ;
     RECT  58.169 74.112 58.421 74.376 ;
     RECT  56.765 35.472 58.489 35.592 ;
     RECT  58.385 36.576 58.489 38.76 ;
     RECT  58.133 77.424 58.489 84.024 ;
     RECT  57.875 48.336 58.493 49.08 ;
     RECT  57.773 27.072 58.525 27.912 ;
     RECT  58.381 96.816 58.525 96.84 ;
     RECT  57.701 60.576 58.529 61.08 ;
     RECT  58.093 86.832 58.529 89.16 ;
     RECT  57.665 93.84 58.561 94.584 ;
     RECT  58.237 20.496 58.597 20.52 ;
     RECT  57.539 29.04 58.633 31.128 ;
     RECT  57.701 32.208 58.633 32.568 ;
     RECT  58.417 72.192 58.633 73.08 ;
     RECT  58.108 3.312 58.636 4.008 ;
     RECT  58.597 20.496 58.643 21.144 ;
     RECT  58.453 47.088 58.673 47.112 ;
     RECT  58.277 50.784 58.673 52.152 ;
     RECT  58.349 66.864 58.673 67.8 ;
     RECT  58.489 77.184 58.709 84.024 ;
     RECT  58.561 93.84 58.733 95.256 ;
     RECT  58.633 29.04 58.781 32.568 ;
     RECT  58.241 90.624 58.787 92.28 ;
     RECT  58.733 93.504 58.817 95.256 ;
     RECT  57.665 40.464 58.849 41.304 ;
     RECT  58.493 48.384 58.861 49.08 ;
     RECT  58.849 40.464 58.885 41.352 ;
     RECT  58.129 42.48 58.885 43.56 ;
     RECT  58.561 7.632 58.921 7.656 ;
     RECT  58.204 23.376 58.921 23.688 ;
     RECT  57.737 70.56 58.921 70.584 ;
     RECT  58.817 93.936 58.933 95.256 ;
     RECT  58.525 96.336 58.933 96.84 ;
     RECT  58.921 23.376 58.961 23.736 ;
     RECT  58.421 45.552 58.961 45.576 ;
     RECT  58.673 52.128 58.961 52.152 ;
     RECT  58.385 69.072 58.961 69.24 ;
     RECT  58.921 70.56 58.961 70.776 ;
     RECT  58.108 5.136 58.993 6.12 ;
     RECT  57.521 18.72 58.997 18.744 ;
     RECT  58.861 48.384 58.997 48.456 ;
     RECT  58.633 72 58.997 73.08 ;
     RECT  58.933 93.936 59.02 96.84 ;
     RECT  56.704 53.376 59.027 54.12 ;
     RECT  57.587 56.688 59.027 56.712 ;
     RECT  58.529 86.832 59.033 88.968 ;
     RECT  58.993 11.76 59.065 11.784 ;
     RECT  57.053 14.784 59.065 15 ;
     RECT  57.089 15.984 59.065 16.008 ;
     RECT  58.981 55.392 59.068 55.416 ;
     RECT  58.921 7.632 59.069 7.752 ;
     RECT  58.163 25.824 59.069 25.848 ;
     RECT  59.033 86.832 59.069 87.576 ;
     RECT  59.065 14.784 59.101 16.008 ;
     RECT  58.885 40.464 59.101 43.56 ;
     RECT  59.101 14.784 59.137 16.68 ;
     RECT  58.993 5.136 59.141 6.648 ;
     RECT  59.101 40.464 59.173 43.896 ;
     RECT  58.636 3.984 59.177 4.008 ;
     RECT  58.781 29.04 59.177 31.416 ;
     RECT  58.421 74.352 59.177 74.376 ;
     RECT  58.787 92.208 59.177 92.28 ;
     RECT  58.961 69.072 59.213 69.096 ;
     RECT  58.961 70.752 59.221 70.776 ;
     RECT  58.673 50.784 59.245 51.096 ;
     RECT  59.141 5.184 59.249 6.648 ;
     RECT  57.557 63.792 59.267 63.816 ;
     RECT  58.205 65.328 59.321 65.784 ;
     RECT  59.249 5.952 59.357 5.976 ;
     RECT  59.173 40.464 59.389 43.944 ;
     RECT  59.065 11.76 59.42 12.024 ;
     RECT  59.137 13.92 59.42 16.68 ;
     RECT  58.961 23.712 59.42 23.736 ;
     RECT  58.169 75.408 59.42 75.864 ;
     RECT  58.525 27.072 59.425 27.96 ;
     RECT  59.177 29.04 59.425 31.368 ;
     RECT  59.42 11.76 59.461 12.552 ;
     RECT  59.42 13.536 59.461 16.68 ;
     RECT  59.425 27.072 59.461 31.368 ;
     RECT  59.317 46.752 59.461 46.776 ;
     RECT  59.42 75.408 59.461 75.96 ;
     RECT  58.709 77.952 59.497 84.024 ;
     RECT  58.273 85.008 59.497 85.752 ;
     RECT  59.461 46.08 59.501 46.776 ;
     RECT  59.461 11.664 59.507 16.68 ;
     RECT  59.42 23.712 59.507 24.696 ;
     RECT  59.461 75.264 59.507 75.96 ;
     RECT  58.489 35.472 59.509 38.76 ;
     RECT  59.033 88.944 59.509 88.968 ;
     RECT  59.509 35.472 59.533 38.904 ;
     RECT  59.321 65.76 59.564 65.784 ;
     RECT  58.673 66.864 59.564 67.272 ;
     RECT  59.389 40.368 59.603 43.944 ;
     RECT  58.165 34.032 59.605 34.104 ;
     RECT  59.507 13.056 59.609 16.68 ;
     RECT  59.497 77.952 59.609 85.752 ;
     RECT  59.533 35.472 59.617 39.336 ;
     RECT  59.569 64.032 59.641 64.248 ;
     RECT  59.609 77.952 59.645 84.024 ;
     RECT  59.564 65.76 59.651 67.272 ;
     RECT  58.885 32.736 59.677 32.76 ;
     RECT  59.497 10.128 59.749 10.152 ;
     RECT  59.507 11.664 59.753 12.024 ;
     RECT  59.027 53.376 59.821 53.4 ;
     RECT  59.645 77.952 59.861 83.928 ;
     RECT  59.617 35.472 59.893 38.76 ;
     RECT  59.507 23.712 59.897 23.736 ;
     RECT  59.861 77.952 59.933 83.88 ;
     RECT  59.821 52.992 59.965 53.4 ;
     RECT  59.281 18.768 60.001 18.792 ;
     RECT  58.997 72.192 60.005 73.08 ;
     RECT  59.857 7.056 60.037 7.272 ;
     RECT  59.609 13.536 60.037 16.68 ;
     RECT  58.997 48.384 60.037 48.408 ;
     RECT  59.461 49.488 60.037 49.512 ;
     RECT  59.245 50.736 60.041 51.096 ;
     RECT  59.641 64.032 60.041 64.296 ;
     RECT  59.651 67.248 60.041 67.272 ;
     RECT  59.749 10.128 60.073 10.392 ;
     RECT  59.965 52.608 60.073 53.4 ;
     RECT  60.041 64.272 60.077 64.296 ;
     RECT  59.677 32.736 60.145 32.856 ;
     RECT  59.605 34.032 60.145 34.248 ;
     RECT  60.005 73.056 60.145 73.08 ;
     RECT  59.461 26.88 60.149 31.368 ;
     RECT  59.651 65.76 60.149 65.784 ;
     RECT  60.073 52.512 60.185 53.4 ;
     RECT  59.753 11.664 60.221 11.928 ;
     RECT  59.933 78.144 60.221 83.88 ;
     RECT  60.037 7.056 60.253 7.704 ;
     RECT  60.073 9.792 60.293 10.392 ;
     RECT  60.253 7.056 60.325 7.752 ;
     RECT  60.001 18.768 60.325 18.84 ;
     RECT  58.643 21.12 60.329 21.144 ;
     RECT  59.02 93.984 60.329 96.84 ;
     RECT  59.069 86.832 60.361 87.144 ;
     RECT  59.501 46.08 60.365 46.104 ;
     RECT  60.145 32.736 60.397 34.248 ;
     RECT  60.325 6.144 60.469 7.752 ;
     RECT  59.221 70.752 60.473 70.824 ;
     RECT  60.473 70.8 60.505 70.824 ;
     RECT  60.037 13.536 60.509 16.92 ;
     RECT  60.329 93.984 60.509 95.4 ;
     RECT  60.037 48.384 60.541 49.512 ;
     RECT  60.421 69.552 60.545 69.576 ;
     RECT  58.787 90.624 60.545 91.176 ;
     RECT  60.361 86.832 60.577 87.72 ;
     RECT  60.469 5.616 60.616 7.752 ;
     RECT  60.221 11.664 60.649 11.784 ;
     RECT  59.173 2.736 60.653 2.76 ;
     RECT  60.329 96.384 60.653 96.84 ;
     RECT  60.073 67.344 60.685 68.088 ;
     RECT  60.509 13.536 60.689 14.856 ;
     RECT  60.653 96.384 60.689 96.696 ;
     RECT  60.541 48.384 60.721 50.136 ;
     RECT  59.507 75.264 60.721 75.432 ;
     RECT  60.509 93.984 60.725 94.392 ;
     RECT  60.293 9.792 60.757 10.2 ;
     RECT  60.721 75.264 60.757 75.816 ;
     RECT  60.689 14.448 60.761 14.856 ;
     RECT  60.689 96.384 60.761 96.408 ;
     RECT  60.509 16.032 60.797 16.92 ;
     RECT  58.529 60.624 60.829 61.08 ;
     RECT  59.461 25.68 60.901 25.704 ;
     RECT  60.149 26.88 60.901 31.224 ;
     RECT  59.603 40.368 60.937 42.792 ;
     RECT  60.185 52.608 60.937 53.4 ;
     RECT  59.893 35.376 60.973 38.76 ;
     RECT  60.937 40.128 60.973 42.792 ;
     RECT  60.901 56.208 60.973 56.232 ;
     RECT  60.829 60.624 60.973 61.416 ;
     RECT  59.609 85.2 60.973 85.752 ;
     RECT  60.616 5.568 61.045 7.752 ;
     RECT  60.649 76.896 61.045 76.92 ;
     RECT  60.221 78.144 61.045 83.784 ;
     RECT  60.649 65.52 61.153 65.544 ;
     RECT  59.603 43.872 61.189 43.944 ;
     RECT  60.937 44.976 61.189 45 ;
     RECT  60.757 75.168 61.225 75.816 ;
     RECT  60.901 25.68 61.261 31.224 ;
     RECT  60.721 48.336 61.285 50.136 ;
     RECT  60.973 51.264 61.285 51.288 ;
     RECT  61.261 25.344 61.297 31.224 ;
     RECT  60.397 32.544 61.297 34.248 ;
     RECT  60.973 35.376 61.297 42.792 ;
     RECT  59.209 92.448 61.297 92.472 ;
     RECT  60.937 58.656 61.3 58.68 ;
     RECT  61.297 32.544 61.369 42.792 ;
     RECT  61.189 43.872 61.369 45 ;
     RECT  60.037 57.312 61.369 57.336 ;
     RECT  61.3 58.656 61.369 58.728 ;
     RECT  60.325 18.528 61.405 18.84 ;
     RECT  61.225 20.4 61.405 20.424 ;
     RECT  61.297 25.344 61.477 31.464 ;
     RECT  61.369 32.544 61.477 45 ;
     RECT  61.369 57.312 61.477 58.728 ;
     RECT  60.973 59.856 61.477 61.416 ;
     RECT  61.045 4.656 61.513 7.752 ;
     RECT  60.973 55.776 61.525 56.328 ;
     RECT  60.757 9.072 61.621 10.2 ;
     RECT  61.225 74.544 61.649 75.816 ;
     RECT  61.045 76.896 61.649 83.784 ;
     RECT  61.513 22.56 61.657 22.584 ;
     RECT  61.477 25.344 61.657 45 ;
     RECT  61.153 65.52 61.657 65.976 ;
     RECT  60.685 67.344 61.657 68.424 ;
     RECT  60.761 14.688 61.693 14.856 ;
     RECT  60.937 52.608 61.693 54.072 ;
     RECT  60.505 70.8 61.693 71.304 ;
     RECT  60.145 73.056 61.693 73.56 ;
     RECT  61.297 13.056 61.729 13.128 ;
     RECT  61.405 18.528 61.729 20.424 ;
     RECT  60.509 95.376 61.765 95.4 ;
     RECT  61.513 4.656 61.808 8.04 ;
     RECT  61.621 9.024 61.808 10.2 ;
     RECT  60.649 11.616 61.808 11.784 ;
     RECT  61.729 12.816 61.808 13.128 ;
     RECT  61.693 14.688 61.808 15.048 ;
     RECT  60.797 16.56 61.808 16.92 ;
     RECT  61.729 18.528 61.808 20.904 ;
     RECT  61.657 22.56 61.808 22.776 ;
     RECT  61.657 24.384 61.808 45 ;
     RECT  60.721 46.224 61.808 46.248 ;
     RECT  61.285 48.336 61.808 51.288 ;
     RECT  61.693 52.608 61.808 54.456 ;
     RECT  61.525 55.488 61.808 56.328 ;
     RECT  61.477 57.312 61.808 61.416 ;
     RECT  61.621 62.448 61.808 62.472 ;
     RECT  61.009 64.128 61.808 64.152 ;
     RECT  61.657 65.52 61.808 68.424 ;
     RECT  61.693 70.608 61.808 71.304 ;
     RECT  61.693 72.432 61.808 73.56 ;
     RECT  61.649 74.544 61.808 83.784 ;
     RECT  60.973 84.768 61.808 85.752 ;
     RECT  60.577 86.832 61.808 88.248 ;
     RECT  60.545 90.624 61.808 90.648 ;
     RECT  61.297 92.256 61.808 92.472 ;
     RECT  60.725 94.032 61.808 94.392 ;
     RECT  61.765 95.376 61.808 96.216 ;
     RECT  61.808 2.148 61.912 97.212 ;
     RECT  61.912 2.418 62.104 96.942 ;
     RECT  62.104 57.456 62.129 60.936 ;
     RECT  62.104 24.384 62.165 28.248 ;
     RECT  62.104 65.52 62.165 68.424 ;
     RECT  62.104 3.072 62.237 10.44 ;
     RECT  62.104 54.672 62.237 55.992 ;
     RECT  62.129 58.656 62.237 60.936 ;
     RECT  62.104 93.984 62.237 96.84 ;
     RECT  62.237 58.656 62.243 59.208 ;
     RECT  62.104 90.048 62.243 91.896 ;
     RECT  62.104 42.192 62.309 45 ;
     RECT  62.104 62.448 62.309 63.864 ;
     RECT  62.104 72.432 62.309 75.864 ;
     RECT  62.104 69.936 62.339 70.824 ;
     RECT  62.104 77.04 62.345 81.768 ;
     RECT  62.243 59.184 62.381 59.208 ;
     RECT  62.237 93.984 62.453 95.4 ;
     RECT  62.237 60.528 62.483 60.936 ;
     RECT  62.237 3.072 62.489 5.304 ;
     RECT  62.104 29.664 62.489 39.528 ;
     RECT  62.489 33.072 62.525 39.528 ;
     RECT  62.237 96.816 62.525 96.84 ;
     RECT  62.129 57.456 62.561 57.48 ;
     RECT  62.104 40.512 62.633 41.208 ;
     RECT  62.525 33.072 62.669 34.488 ;
     RECT  62.339 69.936 62.675 70.632 ;
     RECT  62.489 4.656 62.705 5.304 ;
     RECT  62.453 94.416 62.771 95.4 ;
     RECT  62.525 35.472 62.777 39.528 ;
     RECT  62.165 65.52 62.813 68.376 ;
     RECT  62.104 82.752 62.813 86.76 ;
     RECT  62.771 94.416 62.813 95.208 ;
     RECT  62.813 82.752 62.849 86.616 ;
     RECT  62.104 48.048 62.957 48.456 ;
     RECT  62.104 50.016 62.993 50.76 ;
     RECT  62.309 63.12 62.993 63.864 ;
     RECT  62.957 48.048 63.029 48.408 ;
     RECT  62.849 82.752 63.029 86.328 ;
     RECT  62.309 72.432 63.059 74.04 ;
     RECT  62.243 90.624 63.065 91.896 ;
     RECT  62.104 23.184 63.101 23.208 ;
     RECT  62.165 24.384 63.107 27.72 ;
     RECT  62.104 53.376 63.109 53.4 ;
     RECT  62.237 54.672 63.109 55.656 ;
     RECT  62.489 3.072 63.133 3.672 ;
     RECT  63.107 24.384 63.148 26.568 ;
     RECT  63.148 24.384 63.168 24.408 ;
     RECT  63.029 84.816 63.173 86.328 ;
     RECT  63.109 53.376 63.196 55.656 ;
     RECT  63.116 51.792 63.203 51.816 ;
     RECT  62.777 36.288 63.241 39.528 ;
     RECT  62.633 40.512 63.241 40.728 ;
     RECT  62.813 65.952 63.241 68.376 ;
     RECT  63.148 26.016 63.245 26.568 ;
     RECT  62.104 46.032 63.245 46.632 ;
     RECT  62.309 75.216 63.245 75.864 ;
     RECT  62.237 6.384 63.277 10.44 ;
     RECT  62.104 11.664 63.277 11.688 ;
     RECT  63.241 36.288 63.281 40.728 ;
     RECT  62.993 63.84 63.281 63.864 ;
     RECT  63.245 26.016 63.317 26.088 ;
     RECT  63.281 39.36 63.317 40.728 ;
     RECT  63.059 72.432 63.317 72.456 ;
     RECT  62.104 19.488 63.353 21.432 ;
     RECT  62.309 42.192 63.385 44.76 ;
     RECT  62.104 12.768 63.389 15.288 ;
     RECT  63.317 26.064 63.389 26.088 ;
     RECT  63.196 54.912 63.389 55.656 ;
     RECT  62.345 77.808 63.389 81.768 ;
     RECT  62.489 29.664 63.421 31.896 ;
     RECT  63.385 92.784 63.421 92.808 ;
     RECT  63.196 53.376 63.493 53.592 ;
     RECT  62.675 70.608 63.497 70.632 ;
     RECT  63.107 27.648 63.565 27.72 ;
     RECT  63.421 28.992 63.565 31.896 ;
     RECT  63.133 2.88 63.569 3.672 ;
     RECT  63.173 84.816 63.635 85.944 ;
     RECT  62.483 60.528 63.673 60.6 ;
     RECT  63.635 84.816 63.677 84.984 ;
     RECT  63.565 27.648 63.683 31.896 ;
     RECT  63.683 27.648 63.721 30.936 ;
     RECT  63.673 60.528 63.745 60.648 ;
     RECT  63.353 20.208 63.749 21.432 ;
     RECT  63.059 73.872 63.749 74.04 ;
     RECT  63.385 42.192 63.781 45 ;
     RECT  63.245 46.032 63.781 46.056 ;
     RECT  63.389 77.808 63.781 79.8 ;
     RECT  63.065 90.624 63.781 91.32 ;
     RECT  63.749 21.12 63.785 21.432 ;
     RECT  63.277 6.384 63.817 11.688 ;
     RECT  63.569 2.88 63.821 3.144 ;
     RECT  63.421 92.784 63.827 93.528 ;
     RECT  63.317 39.6 63.829 40.728 ;
     RECT  62.104 16.848 63.853 18.216 ;
     RECT  63.781 42.192 63.875 46.056 ;
     RECT  62.669 34.368 63.889 34.488 ;
     RECT  63.493 53.04 63.893 53.592 ;
     RECT  63.781 90.432 63.929 91.32 ;
     RECT  63.925 31.968 63.961 31.992 ;
     RECT  62.669 33.072 63.961 33.336 ;
     RECT  63.241 65.952 63.973 68.664 ;
     RECT  63.745 60.528 64.001 60.696 ;
     RECT  63.281 36.288 64.033 38.28 ;
     RECT  63.821 3.024 64.037 3.144 ;
     RECT  63.817 5.712 64.069 11.688 ;
     RECT  63.389 12.768 64.069 15.048 ;
     RECT  63.829 39.6 64.073 41.016 ;
     RECT  64.001 60.528 64.073 60.648 ;
     RECT  63.853 16.608 64.109 18.216 ;
     RECT  63.973 65.952 64.141 69.336 ;
     RECT  63.245 75.84 64.172 75.864 ;
     RECT  63.781 76.944 64.172 79.8 ;
     RECT  63.029 48.048 64.177 48.072 ;
     RECT  64.172 75.84 64.213 79.8 ;
     RECT  63.889 34.368 64.217 34.536 ;
     RECT  64.073 39.6 64.217 40.728 ;
     RECT  63.875 42.528 64.217 46.056 ;
     RECT  63.785 21.216 64.249 21.432 ;
     RECT  64.141 65.712 64.249 69.336 ;
     RECT  64.213 75.792 64.259 79.8 ;
     RECT  64.249 21.216 64.285 21.528 ;
     RECT  64.259 77.136 64.357 79.8 ;
     RECT  63.389 80.784 64.357 81.768 ;
     RECT  64.357 26.304 64.393 26.328 ;
     RECT  64.177 57.6 64.393 57.624 ;
     RECT  64.357 77.136 64.393 81.768 ;
     RECT  63.029 82.752 64.393 83.784 ;
     RECT  63.721 27.696 64.433 30.936 ;
     RECT  64.249 64.752 64.433 69.336 ;
     RECT  64.033 35.568 64.465 38.28 ;
     RECT  64.433 64.752 64.465 64.92 ;
     RECT  64.069 5.712 64.469 15.048 ;
     RECT  64.285 21.216 64.469 21.768 ;
     RECT  64.469 5.712 64.505 10.008 ;
     RECT  64.393 57.6 64.537 57.72 ;
     RECT  64.465 64.464 64.537 64.92 ;
     RECT  63.749 73.872 64.537 73.896 ;
     RECT  64.393 77.136 64.541 83.784 ;
     RECT  63.961 31.968 64.573 33.336 ;
     RECT  64.217 34.368 64.573 34.488 ;
     RECT  64.433 27.696 64.577 27.768 ;
     RECT  64.393 26.304 64.613 26.424 ;
     RECT  64.469 11.136 64.649 15.048 ;
     RECT  64.033 23.568 64.681 23.592 ;
     RECT  63.935 71.28 64.681 71.304 ;
     RECT  64.505 5.712 64.685 9.912 ;
     RECT  64.541 82.752 64.685 83.784 ;
     RECT  64.177 48.048 64.717 48.696 ;
     RECT  62.705 4.656 64.753 4.68 ;
     RECT  64.177 18.672 64.753 18.696 ;
     RECT  64.433 28.848 64.753 30.936 ;
     RECT  64.573 31.968 64.753 34.488 ;
     RECT  63.493 62.736 64.793 62.76 ;
     RECT  63.827 92.784 64.793 92.808 ;
     RECT  63.677 84.96 64.829 84.984 ;
     RECT  64.465 35.568 64.861 38.52 ;
     RECT  64.217 39.6 64.861 40.68 ;
     RECT  64.681 71.28 64.861 72.072 ;
     RECT  64.285 85.968 64.901 86.616 ;
     RECT  64.433 65.952 64.933 69.336 ;
     RECT  64.469 21.504 64.937 21.768 ;
     RECT  64.537 57.552 64.937 57.72 ;
     RECT  64.933 65.952 64.937 69.816 ;
     RECT  64.937 66.096 64.969 69.816 ;
     RECT  64.861 35.568 64.973 40.68 ;
     RECT  64.217 42.528 64.973 42.744 ;
     RECT  64.861 71.28 65.005 72.216 ;
     RECT  64.537 73.584 65.005 73.896 ;
     RECT  63.389 55.632 65.041 55.656 ;
     RECT  64.541 77.136 65.045 81.768 ;
     RECT  63.893 53.568 65.077 53.592 ;
     RECT  64.937 21.504 65.081 21.528 ;
     RECT  64.717 47.568 65.081 48.696 ;
     RECT  63.929 90.432 65.081 90.456 ;
     RECT  64.681 23.136 65.117 23.592 ;
     RECT  65.077 53.04 65.117 53.592 ;
     RECT  64.937 57.552 65.117 57.672 ;
     RECT  64.685 7.44 65.123 9.912 ;
     RECT  64.259 75.792 65.257 75.816 ;
     RECT  65.221 86.976 65.257 87 ;
     RECT  64.217 44.064 65.261 46.056 ;
     RECT  64.901 85.968 65.267 85.992 ;
     RECT  65.117 23.136 65.293 23.352 ;
     RECT  64.973 42.672 65.297 42.744 ;
     RECT  65.117 57.552 65.297 57.576 ;
     RECT  65.005 71.28 65.297 73.896 ;
     RECT  65.257 86.976 65.308 87.192 ;
     RECT  64.537 64.416 65.329 64.92 ;
     RECT  65.257 75.792 65.329 76.056 ;
     RECT  65.297 42.72 65.369 42.744 ;
     RECT  64.073 60.528 65.369 60.6 ;
     RECT  64.577 27.696 65.401 27.72 ;
     RECT  65.041 55.632 65.401 55.944 ;
     RECT  65.297 71.28 65.405 71.976 ;
     RECT  65.297 73.584 65.437 73.896 ;
     RECT  65.329 74.88 65.437 76.056 ;
     RECT  65.081 47.568 65.459 48.072 ;
     RECT  65.329 64.368 65.473 64.92 ;
     RECT  64.109 16.608 65.477 17.064 ;
     RECT  64.969 66.096 65.509 70.056 ;
     RECT  65.437 73.584 65.509 76.056 ;
     RECT  65.045 77.136 65.509 77.976 ;
     RECT  64.861 89.136 65.509 89.16 ;
     RECT  64.753 28.848 65.545 34.488 ;
     RECT  64.973 35.568 65.545 40.392 ;
     RECT  65.509 89.136 65.545 89.448 ;
     RECT  65.509 66.096 65.549 70.248 ;
     RECT  65.545 28.848 65.555 40.392 ;
     RECT  62.993 50.736 65.557 50.76 ;
     RECT  65.477 16.608 65.585 17.016 ;
     RECT  65.401 55.536 65.585 55.944 ;
     RECT  65.557 50.736 65.603 51.288 ;
     RECT  65.549 66.096 65.603 69 ;
     RECT  65.293 23.088 65.621 23.352 ;
     RECT  64.037 3.072 65.653 3.144 ;
     RECT  65.413 43.872 65.653 43.896 ;
     RECT  65.603 68.112 65.657 69 ;
     RECT  65.509 73.584 65.657 77.976 ;
     RECT  65.123 9.072 65.689 9.912 ;
     RECT  64.613 26.304 65.797 26.328 ;
     RECT  65.401 27.6 65.797 27.72 ;
     RECT  64.685 5.712 65.801 6.216 ;
     RECT  65.603 66.096 65.801 67.08 ;
     RECT  65.621 23.136 65.837 23.352 ;
     RECT  65.555 29.04 65.837 40.392 ;
     RECT  65.657 75.216 65.837 77.976 ;
     RECT  65.045 79.2 65.837 81.768 ;
     RECT  65.797 26.304 65.869 27.72 ;
     RECT  65.123 7.44 65.873 7.992 ;
     RECT  64.753 18.672 65.873 18.744 ;
     RECT  65.873 7.44 65.909 7.464 ;
     RECT  65.837 36 65.939 40.392 ;
     RECT  65.473 57.312 65.941 57.336 ;
     RECT  65.549 70.032 65.941 70.248 ;
     RECT  65.117 53.04 65.945 53.064 ;
     RECT  64.753 4.224 65.977 4.68 ;
     RECT  65.545 88.32 65.977 89.448 ;
     RECT  65.869 25.92 65.981 27.72 ;
     RECT  65.837 29.04 65.981 34.68 ;
     RECT  65.261 44.88 66.013 46.056 ;
     RECT  64.753 91.44 66.013 91.464 ;
     RECT  64.649 11.664 66.017 15.048 ;
     RECT  65.981 29.04 66.017 33.096 ;
     RECT  65.981 34.08 66.017 34.68 ;
     RECT  65.837 79.776 66.049 81.768 ;
     RECT  65.837 75.936 66.053 77.976 ;
     RECT  66.013 91.44 66.053 91.8 ;
     RECT  65.981 27.6 66.089 27.72 ;
     RECT  64.213 59.472 66.121 59.496 ;
     RECT  64.685 83.232 66.121 83.784 ;
     RECT  66.017 31.248 66.125 33.096 ;
     RECT  65.473 64.08 66.125 64.92 ;
     RECT  65.939 39.6 66.157 40.392 ;
     RECT  65.585 55.536 66.157 55.704 ;
     RECT  65.873 18.672 66.161 18.696 ;
     RECT  65.981 25.92 66.161 26.28 ;
     RECT  66.157 54.672 66.161 55.704 ;
     RECT  65.689 9.072 66.229 10.2 ;
     RECT  66.017 11.664 66.229 13.944 ;
     RECT  65.837 23.328 66.229 23.352 ;
     RECT  66.157 39.6 66.229 40.44 ;
     RECT  66.121 41.424 66.229 41.448 ;
     RECT  65.308 87.168 66.233 87.192 ;
     RECT  65.801 6 66.301 6.216 ;
     RECT  65.941 57.024 66.445 57.336 ;
     RECT  66.125 64.368 66.517 64.92 ;
     RECT  65.369 60.528 66.553 60.552 ;
     RECT  62.813 95.184 66.553 95.208 ;
     RECT  66.049 79.776 66.589 82.056 ;
     RECT  66.121 83.136 66.589 84.6 ;
     RECT  66.161 55.68 66.62 55.704 ;
     RECT  65.653 3.072 66.661 3.192 ;
     RECT  65.977 4.224 66.661 5.016 ;
     RECT  66.017 15.024 66.661 15.048 ;
     RECT  65.585 16.608 66.661 16.92 ;
     RECT  66.445 56.88 66.661 57.336 ;
     RECT  66.553 60.528 66.661 61.464 ;
     RECT  66.517 64.368 66.661 64.968 ;
     RECT  66.229 23.328 66.709 24.12 ;
     RECT  65.657 68.112 66.733 68.376 ;
     RECT  65.459 47.568 66.764 47.736 ;
     RECT  66.661 3.072 66.769 5.016 ;
     RECT  65.657 73.872 66.769 74.04 ;
     RECT  66.229 39.6 66.805 41.448 ;
     RECT  66.013 44.88 66.805 46.392 ;
     RECT  66.764 47.568 66.805 47.928 ;
     RECT  66.661 15.024 66.812 16.92 ;
     RECT  66.661 21.648 66.877 21.672 ;
     RECT  66.769 3.024 66.913 5.016 ;
     RECT  66.301 6 66.949 7.128 ;
     RECT  66.661 60.528 66.949 61.992 ;
     RECT  66.733 68.112 66.949 68.712 ;
     RECT  65.941 70.032 66.949 70.584 ;
     RECT  66.877 21.648 66.985 21.816 ;
     RECT  65.603 51.264 66.985 51.288 ;
     RECT  65.977 88.32 66.985 89.496 ;
     RECT  64.933 19.728 67.057 19.752 ;
     RECT  66.985 20.928 67.057 21.816 ;
     RECT  66.985 87.888 67.093 89.496 ;
     RECT  66.553 94.56 67.093 95.208 ;
     RECT  66.985 50.4 67.129 51.288 ;
     RECT  66.089 27.696 67.165 27.72 ;
     RECT  66.913 2.88 67.208 5.016 ;
     RECT  66.949 6 67.208 7.416 ;
     RECT  66.229 9.072 67.208 13.944 ;
     RECT  66.812 15.024 67.208 17.544 ;
     RECT  66.853 18.72 67.208 18.744 ;
     RECT  67.057 19.728 67.208 21.816 ;
     RECT  66.709 23.328 67.208 24.648 ;
     RECT  66.161 26.256 67.208 26.28 ;
     RECT  67.165 27.36 67.208 27.912 ;
     RECT  66.017 29.04 67.208 30.216 ;
     RECT  66.125 31.392 67.208 33.096 ;
     RECT  66.017 34.656 67.208 34.68 ;
     RECT  65.939 36 67.208 38.568 ;
     RECT  66.805 39.6 67.208 41.496 ;
     RECT  65.653 43.344 67.208 43.896 ;
     RECT  66.805 44.88 67.208 47.928 ;
     RECT  67.129 50.4 67.208 51.768 ;
     RECT  67.165 53.52 67.208 53.544 ;
     RECT  66.161 54.672 67.208 54.696 ;
     RECT  66.62 55.68 67.208 55.848 ;
     RECT  66.661 56.88 67.208 57.528 ;
     RECT  66.121 58.656 67.208 59.496 ;
     RECT  66.949 60.528 67.208 62.856 ;
     RECT  66.661 64.368 67.208 65.496 ;
     RECT  65.801 67.056 67.208 67.08 ;
     RECT  66.949 68.112 67.208 70.584 ;
     RECT  65.405 71.952 67.208 71.976 ;
     RECT  66.769 73.008 67.208 74.04 ;
     RECT  66.053 75.936 67.208 77.16 ;
     RECT  66.157 78.192 67.208 78.504 ;
     RECT  66.589 79.776 67.208 84.6 ;
     RECT  66.661 86.832 67.208 86.856 ;
     RECT  67.093 87.888 67.208 90.36 ;
     RECT  66.053 91.776 67.208 91.8 ;
     RECT  67.093 94.416 67.208 95.208 ;
     RECT  67.208 2.148 67.312 97.212 ;
     RECT  67.312 2.418 67.504 96.942 ;
     RECT  67.504 2.496 67.565 13.944 ;
     RECT  67.504 43.824 67.601 44.472 ;
     RECT  67.504 15.024 67.619 17.16 ;
     RECT  67.504 93.888 67.619 95.4 ;
     RECT  67.504 21.504 67.637 22.2 ;
     RECT  67.504 23.328 67.637 23.592 ;
     RECT  67.504 36.528 67.637 38.232 ;
     RECT  67.565 2.496 67.673 9.576 ;
     RECT  67.504 39.984 67.673 41.928 ;
     RECT  67.504 81.408 67.673 87.912 ;
     RECT  67.619 93.888 67.673 93.912 ;
     RECT  67.673 2.496 67.709 9.096 ;
     RECT  67.673 81.408 67.781 83.784 ;
     RECT  67.504 89.424 67.781 90.936 ;
     RECT  67.709 2.496 67.817 6.696 ;
     RECT  67.637 23.568 67.817 23.592 ;
     RECT  67.709 7.776 67.853 9.096 ;
     RECT  67.504 24.624 67.853 24.648 ;
     RECT  67.504 27.696 67.853 27.912 ;
     RECT  67.637 38.208 67.853 38.232 ;
     RECT  67.504 62.832 67.853 65.496 ;
     RECT  67.504 50.4 67.889 55.704 ;
     RECT  67.889 52.224 67.907 55.704 ;
     RECT  67.907 52.464 67.925 55.704 ;
     RECT  67.853 63.264 67.961 65.496 ;
     RECT  67.853 7.776 67.997 7.992 ;
     RECT  67.817 2.496 68.033 3.048 ;
     RECT  67.504 30.432 68.033 31.56 ;
     RECT  67.817 4.224 68.069 6.696 ;
     RECT  67.504 77.088 68.069 78.696 ;
     RECT  67.961 63.744 68.099 65.496 ;
     RECT  68.069 4.224 68.105 6.36 ;
     RECT  67.504 29.04 68.105 29.4 ;
     RECT  68.033 31.392 68.105 31.56 ;
     RECT  68.105 31.536 68.14 31.56 ;
     RECT  68.105 6 68.213 6.36 ;
     RECT  67.997 7.776 68.249 7.8 ;
     RECT  67.504 66.72 68.249 66.744 ;
     RECT  67.853 9.072 68.321 9.096 ;
     RECT  67.504 59.28 68.357 59.304 ;
     RECT  68.105 4.224 68.387 4.68 ;
     RECT  67.925 52.848 68.387 55.704 ;
     RECT  67.565 10.608 68.393 13.944 ;
     RECT  67.504 45.744 68.435 47.88 ;
     RECT  67.781 90.912 68.435 90.936 ;
     RECT  68.393 12.864 68.465 13.944 ;
     RECT  67.619 15.024 68.465 17.064 ;
     RECT  67.504 69.456 68.501 74.136 ;
     RECT  68.465 13.632 68.537 13.944 ;
     RECT  68.435 45.744 68.569 46.2 ;
     RECT  67.504 18.72 68.605 18.744 ;
     RECT  67.601 43.872 68.605 44.472 ;
     RECT  68.569 45.552 68.605 46.2 ;
     RECT  68.213 6 68.609 6.12 ;
     RECT  68.465 16.368 68.641 17.064 ;
     RECT  68.605 18.72 68.641 18.792 ;
     RECT  68.501 69.456 68.645 74.088 ;
     RECT  67.637 21.936 68.681 22.2 ;
     RECT  67.781 81.504 68.681 83.784 ;
     RECT  68.605 43.872 68.713 46.2 ;
     RECT  68.387 52.944 68.717 55.704 ;
     RECT  67.673 41.904 68.749 41.928 ;
     RECT  67.504 68.112 68.749 68.232 ;
     RECT  68.645 69.456 68.749 73.896 ;
     RECT  68.099 63.744 68.753 64.968 ;
     RECT  67.673 87.552 68.773 87.816 ;
     RECT  67.781 89.424 68.773 89.832 ;
     RECT  67.673 39.984 68.78 40.44 ;
     RECT  68.749 41.712 68.78 41.928 ;
     RECT  68.537 13.92 68.821 13.944 ;
     RECT  68.465 15.024 68.821 15.048 ;
     RECT  68.78 39.984 68.821 41.928 ;
     RECT  67.673 85.2 68.821 86.424 ;
     RECT  68.773 87.552 68.821 89.832 ;
     RECT  68.641 16.368 68.825 18.792 ;
     RECT  67.504 25.632 68.857 25.656 ;
     RECT  67.504 26.64 68.857 26.664 ;
     RECT  68.821 39.792 68.857 41.928 ;
     RECT  68.681 83.184 68.857 83.784 ;
     RECT  68.821 85.2 68.857 89.832 ;
     RECT  68.753 64.752 68.861 64.968 ;
     RECT  68.749 68.112 68.861 73.896 ;
     RECT  67.853 27.696 68.893 27.72 ;
     RECT  68.105 29.04 68.893 29.064 ;
     RECT  68.825 16.368 68.897 17.064 ;
     RECT  68.857 25.632 68.897 26.664 ;
     RECT  68.717 54.096 68.905 55.704 ;
     RECT  68.435 47.376 68.917 47.88 ;
     RECT  67.504 49.296 68.917 49.32 ;
     RECT  68.821 13.92 68.933 15.048 ;
     RECT  68.917 47.376 68.963 49.32 ;
     RECT  67.504 60.528 68.965 60.552 ;
     RECT  67.504 75.36 68.969 76.056 ;
     RECT  68.893 27.696 68.972 29.064 ;
     RECT  68.785 57.552 69.001 57.576 ;
     RECT  68.681 81.504 69.001 81.768 ;
     RECT  68.972 27.312 69.059 29.064 ;
     RECT  68.825 18.096 69.073 18.792 ;
     RECT  68.857 83.184 69.077 89.832 ;
     RECT  67.504 34.8 69.113 34.824 ;
     RECT  68.861 64.752 69.149 64.776 ;
     RECT  68.387 4.656 69.181 4.68 ;
     RECT  68.905 54.336 69.181 55.704 ;
     RECT  68.069 77.088 69.217 78.456 ;
     RECT  69.059 27.696 69.221 29.064 ;
     RECT  68.861 68.112 69.221 73.416 ;
     RECT  67.504 33.024 69.253 33.048 ;
     RECT  67.504 79.776 69.26 79.848 ;
     RECT  69.181 4.656 69.289 4.728 ;
     RECT  68.609 6 69.289 6.072 ;
     RECT  68.753 63.744 69.289 63.768 ;
     RECT  68.393 10.608 69.329 11.688 ;
     RECT  69.221 27.696 69.329 28.632 ;
     RECT  69.26 79.728 69.347 79.848 ;
     RECT  69.253 32.592 69.361 33.048 ;
     RECT  68.857 39.792 69.401 42.216 ;
     RECT  69.221 68.112 69.401 73.368 ;
     RECT  68.969 76.032 69.401 76.056 ;
     RECT  69.077 83.184 69.436 85.512 ;
     RECT  69.001 57.072 69.437 57.576 ;
     RECT  68.033 2.496 69.469 2.52 ;
     RECT  69.217 23.904 69.5 23.928 ;
     RECT  69.401 39.792 69.509 41.976 ;
     RECT  68.963 47.376 69.509 48.456 ;
     RECT  69.217 77.088 69.509 78.648 ;
     RECT  69.5 23.712 69.541 23.928 ;
     RECT  69.289 4.656 69.545 6.072 ;
     RECT  68.713 43.632 69.545 46.2 ;
     RECT  69.545 6 69.581 6.072 ;
     RECT  69.541 23.712 69.587 24.504 ;
     RECT  69.509 77.088 69.587 78.12 ;
     RECT  69.509 41.952 69.617 41.976 ;
     RECT  69.509 47.376 69.617 47.4 ;
     RECT  69.545 43.632 69.653 45.576 ;
     RECT  69.469 2.496 69.685 3.048 ;
     RECT  68.933 13.92 69.721 14.28 ;
     RECT  68.681 21.936 69.721 21.96 ;
     RECT  69.587 24.48 69.721 24.504 ;
     RECT  68.897 25.632 69.721 26.232 ;
     RECT  69.347 79.776 69.721 79.848 ;
     RECT  69.001 80.88 69.721 81.768 ;
     RECT  69.721 13.872 69.725 14.28 ;
     RECT  69.721 24.48 69.725 26.232 ;
     RECT  68.717 52.944 69.733 52.968 ;
     RECT  68.965 60.528 69.733 60.648 ;
     RECT  69.077 86.64 69.761 89.832 ;
     RECT  69.692 58.656 69.779 58.68 ;
     RECT  69.289 63.264 69.779 63.768 ;
     RECT  69.733 52.944 69.793 53.016 ;
     RECT  68.929 92.352 69.793 92.376 ;
     RECT  69.793 92.352 69.797 93.24 ;
     RECT  69.289 30.864 69.829 30.888 ;
     RECT  69.361 35.184 69.829 35.208 ;
     RECT  67.637 36.528 69.829 37.08 ;
     RECT  69.757 51.12 69.829 51.144 ;
     RECT  69.581 6.048 69.833 6.072 ;
     RECT  69.436 84.816 69.833 85.512 ;
     RECT  69.788 34.128 69.875 34.152 ;
     RECT  69.181 54.336 69.877 55.8 ;
     RECT  69.073 18.096 69.901 18.84 ;
     RECT  69.469 29.664 69.901 29.688 ;
     RECT  69.829 30.864 69.901 30.984 ;
     RECT  69.721 79.776 69.901 81.768 ;
     RECT  69.436 83.184 69.901 83.784 ;
     RECT  69.761 89.808 69.905 89.832 ;
     RECT  69.829 49.536 69.913 49.56 ;
     RECT  69.437 57.552 69.923 57.576 ;
     RECT  69.509 48.384 69.941 48.456 ;
     RECT  69.761 86.64 69.941 88.824 ;
     RECT  69.685 2.496 69.971 3.48 ;
     RECT  69.901 6.528 69.985 6.984 ;
     RECT  69.329 10.8 70.009 11.688 ;
     RECT  68.897 17.04 70.009 17.064 ;
     RECT  69.901 18.096 70.045 19.8 ;
     RECT  69.401 73.344 70.049 73.368 ;
     RECT  69.757 38.688 70.081 38.712 ;
     RECT  69.509 39.792 70.081 40.536 ;
     RECT  69.401 68.112 70.081 72.12 ;
     RECT  69.797 93.216 70.081 93.24 ;
     RECT  68.965 91.152 70.117 91.176 ;
     RECT  69.653 43.632 70.121 45.48 ;
     RECT  69.829 35.184 70.153 37.08 ;
     RECT  69.901 79.776 70.193 83.784 ;
     RECT  69.901 29.664 70.261 30.984 ;
     RECT  69.587 77.088 70.261 77.976 ;
     RECT  70.045 18.096 70.265 20.424 ;
     RECT  70.117 91.152 70.265 91.8 ;
     RECT  69.361 32.352 70.307 33.048 ;
     RECT  70.009 16.8 70.316 17.064 ;
     RECT  70.265 18.096 70.316 20.088 ;
     RECT  69.973 9.648 70.369 9.672 ;
     RECT  70.009 10.8 70.369 12.456 ;
     RECT  70.261 29.664 70.369 31.128 ;
     RECT  67.619 95.376 70.373 95.4 ;
     RECT  70.081 67.872 70.405 72.12 ;
     RECT  69.971 3.024 70.441 3.48 ;
     RECT  69.545 4.656 70.441 4.728 ;
     RECT  69.793 52.464 70.441 53.016 ;
     RECT  69.877 54.096 70.441 55.8 ;
     RECT  70.333 65.376 70.441 65.4 ;
     RECT  70.369 9.648 70.477 12.456 ;
     RECT  69.329 27.696 70.481 28.488 ;
     RECT  70.081 89.952 70.481 89.976 ;
     RECT  70.307 32.448 70.513 33.048 ;
     RECT  70.477 8.976 70.517 12.456 ;
     RECT  70.405 67.488 70.541 72.12 ;
     RECT  69.733 60.288 70.549 60.648 ;
     RECT  70.441 65.328 70.553 65.4 ;
     RECT  70.153 34.56 70.577 37.08 ;
     RECT  70.441 42.576 70.585 42.6 ;
     RECT  70.121 43.632 70.585 45.432 ;
     RECT  69.829 50.736 70.585 51.144 ;
     RECT  70.553 65.376 70.585 65.4 ;
     RECT  70.477 66.384 70.585 66.408 ;
     RECT  70.316 16.8 70.589 20.088 ;
     RECT  70.541 67.488 70.625 72.36 ;
     RECT  70.549 74.688 70.633 74.712 ;
     RECT  70.577 34.56 70.645 37.464 ;
     RECT  70.585 65.376 70.661 66.408 ;
     RECT  70.193 80.544 70.661 83.784 ;
     RECT  70.645 34.56 70.697 37.704 ;
     RECT  69.725 13.872 70.729 14.184 ;
     RECT  70.549 23.232 70.729 23.256 ;
     RECT  70.081 38.688 70.729 40.536 ;
     RECT  70.585 50.736 70.729 51.384 ;
     RECT  70.441 52.464 70.729 55.8 ;
     RECT  70.589 19.776 70.733 20.088 ;
     RECT  70.625 67.488 70.733 72.072 ;
     RECT  70.261 76.656 70.733 77.976 ;
     RECT  70.661 80.88 70.733 83.784 ;
     RECT  69.833 84.816 70.733 84.936 ;
     RECT  70.369 29.664 70.739 31.176 ;
     RECT  70.729 50.736 70.739 55.8 ;
     RECT  70.729 38.688 70.769 41.016 ;
     RECT  70.265 91.776 70.769 91.8 ;
     RECT  70.517 11.664 70.837 12.456 ;
     RECT  70.729 13.872 70.837 14.376 ;
     RECT  70.477 15.648 70.837 15.672 ;
     RECT  70.589 16.8 70.837 18.024 ;
     RECT  69.779 63.744 70.837 63.768 ;
     RECT  70.117 26.256 70.873 26.28 ;
     RECT  70.481 27.696 70.873 28.44 ;
     RECT  69.941 48.432 70.877 48.456 ;
     RECT  70.837 11.664 70.913 14.376 ;
     RECT  70.733 84.864 70.945 84.936 ;
     RECT  69.941 87.552 70.945 88.824 ;
     RECT  70.733 76.656 70.949 77.928 ;
     RECT  70.585 42.576 70.981 45.432 ;
     RECT  70.945 84.864 70.985 84.984 ;
     RECT  70.913 11.664 71.021 14.136 ;
     RECT  70.837 15.648 71.021 18.024 ;
     RECT  70.769 39.696 71.021 41.016 ;
     RECT  70.739 50.736 71.021 53.016 ;
     RECT  70.945 87.552 71.021 89.496 ;
     RECT  71.021 11.664 71.057 11.688 ;
     RECT  69.725 24.48 71.057 24.936 ;
     RECT  70.657 79.392 71.057 79.416 ;
     RECT  70.733 81.648 71.057 83.784 ;
     RECT  70.441 3.024 71.093 4.728 ;
     RECT  70.549 60.288 71.129 61.368 ;
     RECT  70.909 73.824 71.129 73.848 ;
     RECT  70.661 65.616 71.233 66.408 ;
     RECT  70.733 67.488 71.233 71.736 ;
     RECT  71.021 87.552 71.233 87.576 ;
     RECT  71.093 3.024 71.269 4.536 ;
     RECT  70.517 8.976 71.269 10.488 ;
     RECT  71.021 40.368 71.269 41.016 ;
     RECT  70.981 42 71.269 45.432 ;
     RECT  71.089 57.936 71.269 57.96 ;
     RECT  71.161 7.632 71.273 7.656 ;
     RECT  70.739 54.336 71.273 55.8 ;
     RECT  69.985 6.528 71.276 6.648 ;
     RECT  70.739 30.144 71.305 31.176 ;
     RECT  70.513 32.448 71.305 33.336 ;
     RECT  71.269 57.888 71.305 57.96 ;
     RECT  71.021 15.984 71.315 18.024 ;
     RECT  71.276 6.528 71.363 7.128 ;
     RECT  71.129 60.288 71.377 60.648 ;
     RECT  71.269 8.88 71.381 10.488 ;
     RECT  71.381 8.88 71.411 9 ;
     RECT  71.269 40.368 71.411 45.432 ;
     RECT  71.411 40.416 71.413 45.432 ;
     RECT  71.341 49.008 71.453 49.032 ;
     RECT  71.411 8.88 71.459 8.904 ;
     RECT  71.089 47.328 71.459 47.352 ;
     RECT  71.233 86.784 71.485 87.576 ;
     RECT  71.363 6.528 71.489 7.032 ;
     RECT  71.057 81.648 71.489 82.632 ;
     RECT  71.269 2.496 71.497 4.536 ;
     RECT  71.233 65.616 71.507 71.736 ;
     RECT  71.305 30.144 71.521 33.336 ;
     RECT  71.305 57.168 71.525 57.96 ;
     RECT  71.021 88.608 71.525 89.496 ;
     RECT  71.489 6.528 71.557 6.648 ;
     RECT  71.413 40.416 71.561 45.528 ;
     RECT  71.525 57.168 71.561 57.624 ;
     RECT  70.697 35.04 71.593 37.704 ;
     RECT  70.769 38.688 71.593 38.712 ;
     RECT  71.557 95.472 71.605 95.496 ;
     RECT  71.381 10.224 71.629 10.488 ;
     RECT  71.485 86.592 71.629 87.576 ;
     RECT  71.557 6.24 71.633 6.648 ;
     RECT  71.489 81.648 71.633 82.152 ;
     RECT  71.377 59.76 71.665 60.648 ;
     RECT  70.081 93.216 71.701 93.48 ;
     RECT  71.561 44.208 71.773 45.528 ;
     RECT  70.837 63.744 71.773 64.392 ;
     RECT  71.521 30.144 71.797 33.816 ;
     RECT  71.593 35.04 71.797 38.712 ;
     RECT  70.873 26.256 71.809 28.44 ;
     RECT  71.797 30.144 71.809 38.712 ;
     RECT  69.721 21.648 71.845 21.96 ;
     RECT  70.729 23.232 71.845 23.4 ;
     RECT  71.525 88.8 71.845 89.496 ;
     RECT  71.809 26.256 71.881 38.712 ;
     RECT  71.273 54.336 71.917 54.36 ;
     RECT  71.665 59.712 71.917 60.648 ;
     RECT  70.949 77.904 71.917 77.928 ;
     RECT  71.021 50.736 71.941 51.144 ;
     RECT  71.773 63.216 71.953 64.392 ;
     RECT  71.507 65.616 71.953 69.288 ;
     RECT  71.021 52.128 71.989 53.016 ;
     RECT  71.917 54.048 71.989 54.36 ;
     RECT  71.507 70.32 71.989 71.736 ;
     RECT  71.633 6.24 71.996 6.264 ;
     RECT  71.773 75.792 72.025 76.392 ;
     RECT  71.917 77.616 72.025 77.976 ;
     RECT  71.701 93.216 72.205 93.528 ;
     RECT  71.605 94.608 72.205 95.496 ;
     RECT  71.057 83.76 72.236 83.784 ;
     RECT  70.985 84.912 72.236 84.984 ;
     RECT  71.629 86.496 72.236 87.576 ;
     RECT  71.021 13.008 72.241 14.136 ;
     RECT  72.236 83.76 72.277 84.984 ;
     RECT  72.236 86.16 72.277 87.576 ;
     RECT  72.025 75.792 72.313 77.976 ;
     RECT  71.881 26.256 72.373 38.76 ;
     RECT  71.773 44.208 72.385 46.344 ;
     RECT  71.273 55.488 72.385 55.8 ;
     RECT  71.941 49.872 72.421 51.144 ;
     RECT  71.989 52.128 72.421 54.36 ;
     RECT  71.057 24.912 72.449 24.936 ;
     RECT  71.845 21.648 72.469 23.4 ;
     RECT  72.449 24.912 72.469 25.128 ;
     RECT  72.373 26.256 72.469 39 ;
     RECT  72.421 49.872 72.493 54.36 ;
     RECT  72.385 55.488 72.493 55.992 ;
     RECT  71.561 57.408 72.565 57.624 ;
     RECT  71.953 63.216 72.565 69.288 ;
     RECT  71.989 70.32 72.565 72.024 ;
     RECT  72.133 73.056 72.565 73.08 ;
     RECT  72.313 75.696 72.601 77.976 ;
     RECT  71.497 2.496 72.608 3.768 ;
     RECT  71.996 5.616 72.608 6.264 ;
     RECT  71.629 10.224 72.608 11.4 ;
     RECT  72.241 13.008 72.608 14.28 ;
     RECT  71.315 15.984 72.608 17.64 ;
     RECT  71.629 18.768 72.608 18.792 ;
     RECT  70.733 19.776 72.608 19.8 ;
     RECT  72.469 21.648 72.608 23.88 ;
     RECT  72.469 24.912 72.608 39 ;
     RECT  71.561 40.416 72.608 42.744 ;
     RECT  72.385 44.208 72.608 47.064 ;
     RECT  72.493 49.872 72.608 55.992 ;
     RECT  72.565 57.12 72.608 57.624 ;
     RECT  71.917 59.568 72.608 60.648 ;
     RECT  72.565 63.216 72.608 69.336 ;
     RECT  72.565 70.32 72.608 73.08 ;
     RECT  71.629 74.688 72.608 74.712 ;
     RECT  72.601 75.696 72.608 78.456 ;
     RECT  71.665 80.352 72.608 80.376 ;
     RECT  71.633 81.648 72.608 81.864 ;
     RECT  72.277 83.328 72.608 87.576 ;
     RECT  71.845 88.8 72.608 89.544 ;
     RECT  72.205 93.216 72.608 95.496 ;
     RECT  72.608 2.148 72.712 97.212 ;
     RECT  72.712 2.418 72.904 96.942 ;
     RECT  72.904 38.928 72.929 42.552 ;
     RECT  72.904 75.696 72.929 76.248 ;
     RECT  72.904 63.792 72.965 74.04 ;
     RECT  72.904 2.496 73.001 2.808 ;
     RECT  72.904 51.936 73.001 55.464 ;
     RECT  72.965 65.136 73.001 66.6 ;
     RECT  72.929 75.696 73.001 75.816 ;
     RECT  72.904 77.376 73.073 79.8 ;
     RECT  72.904 21.12 73.109 37.704 ;
     RECT  72.904 10.368 73.289 10.392 ;
     RECT  72.904 11.376 73.289 11.4 ;
     RECT  72.965 67.632 73.325 74.04 ;
     RECT  72.904 92.832 73.325 95.496 ;
     RECT  73.073 77.376 73.361 77.64 ;
     RECT  72.904 81.648 73.361 83.784 ;
     RECT  73.361 82.32 73.379 83.784 ;
     RECT  73.325 67.68 73.397 73.896 ;
     RECT  72.904 91.344 73.397 91.704 ;
     RECT  73.109 21.12 73.427 34.92 ;
     RECT  73.427 21.36 73.433 34.92 ;
     RECT  73.397 91.68 73.433 91.704 ;
     RECT  73.433 21.36 73.523 22.2 ;
     RECT  73.397 67.872 73.541 73.896 ;
     RECT  72.904 48.48 73.577 48.888 ;
     RECT  73.541 67.872 73.577 73.464 ;
     RECT  73.577 67.92 73.613 73.464 ;
     RECT  73.379 82.368 73.649 83.784 ;
     RECT  72.904 19.776 73.721 19.944 ;
     RECT  72.904 15.984 73.757 17.64 ;
     RECT  73.073 79.248 73.763 79.464 ;
     RECT  73.721 19.776 73.793 19.896 ;
     RECT  72.904 47.04 73.829 47.304 ;
     RECT  73.757 15.984 73.865 16.92 ;
     RECT  73.433 23.184 73.865 34.344 ;
     RECT  72.904 59.328 74.005 61.224 ;
     RECT  72.904 62.64 74.005 62.664 ;
     RECT  73.001 65.136 74.005 66.36 ;
     RECT  72.929 38.928 74.017 41.832 ;
     RECT  72.904 84.768 74.041 84.936 ;
     RECT  72.904 7.056 74.045 7.08 ;
     RECT  73.865 16.848 74.045 16.92 ;
     RECT  73.793 19.776 74.045 19.848 ;
     RECT  73.613 67.92 74.045 72.024 ;
     RECT  73.109 35.904 74.053 37.704 ;
     RECT  74.017 38.928 74.053 40.584 ;
     RECT  73.001 75.696 74.053 75.72 ;
     RECT  72.965 63.792 74.077 63.816 ;
     RECT  74.045 67.92 74.081 70.344 ;
     RECT  74.053 35.904 74.099 40.584 ;
     RECT  73.613 73.056 74.099 73.464 ;
     RECT  73.649 82.368 74.099 83.736 ;
     RECT  74.041 84.768 74.099 85.512 ;
     RECT  73.001 51.936 74.113 55.368 ;
     RECT  74.077 63.744 74.113 63.816 ;
     RECT  72.904 57.216 74.153 57.432 ;
     RECT  74.099 39.456 74.189 40.584 ;
     RECT  72.904 49.872 74.221 50.904 ;
     RECT  74.113 63.744 74.221 64.056 ;
     RECT  74.005 65.136 74.221 66.6 ;
     RECT  74.045 71.328 74.225 72.024 ;
     RECT  73.829 47.28 74.252 47.304 ;
     RECT  74.113 51.936 74.261 55.896 ;
     RECT  72.904 88.608 74.293 90.024 ;
     RECT  73.325 92.832 74.293 94.92 ;
     RECT  74.045 16.848 74.297 16.872 ;
     RECT  72.904 86.496 74.297 86.76 ;
     RECT  74.225 71.376 74.333 72.024 ;
     RECT  74.252 47.28 74.339 47.736 ;
     RECT  74.221 49.2 74.339 50.904 ;
     RECT  74.053 75.696 74.365 75.864 ;
     RECT  73.001 2.496 74.401 2.52 ;
     RECT  74.099 84.96 74.401 85.512 ;
     RECT  74.189 39.456 74.405 40.536 ;
     RECT  74.261 51.936 74.405 55.368 ;
     RECT  74.339 49.968 74.437 50.904 ;
     RECT  74.405 51.936 74.437 54.792 ;
     RECT  74.437 91.392 74.473 91.416 ;
     RECT  74.293 92.592 74.473 94.92 ;
     RECT  73.523 21.648 74.477 22.2 ;
     RECT  74.405 39.456 74.477 40.44 ;
     RECT  74.401 2.496 74.509 3.192 ;
     RECT  74.005 59.328 74.509 62.664 ;
     RECT  74.221 63.744 74.509 66.6 ;
     RECT  74.297 86.736 74.509 86.76 ;
     RECT  74.293 87.792 74.509 90.024 ;
     RECT  74.473 91.392 74.509 95.016 ;
     RECT  74.437 49.968 74.521 54.792 ;
     RECT  74.509 2.496 74.545 3.336 ;
     RECT  73.361 77.376 74.545 77.4 ;
     RECT  74.477 22.176 74.617 22.2 ;
     RECT  73.865 23.184 74.617 24.504 ;
     RECT  74.017 41.76 74.617 41.832 ;
     RECT  74.365 75.6 74.617 75.864 ;
     RECT  74.545 77.136 74.617 77.4 ;
     RECT  74.099 35.904 74.621 38.376 ;
     RECT  74.509 59.328 74.621 66.84 ;
     RECT  73.865 25.488 74.653 34.344 ;
     RECT  74.621 66.336 74.657 66.84 ;
     RECT  74.509 91.344 74.659 95.016 ;
     RECT  74.545 2.496 74.693 3.96 ;
     RECT  74.521 50.016 74.693 54.792 ;
     RECT  74.077 78.384 74.693 78.408 ;
     RECT  72.904 44.064 74.725 45.576 ;
     RECT  74.333 72 74.725 72.024 ;
     RECT  74.099 73.056 74.725 73.08 ;
     RECT  74.693 51.984 74.729 54.792 ;
     RECT  74.657 66.336 74.729 66.6 ;
     RECT  74.621 59.328 74.761 65.16 ;
     RECT  74.621 35.904 74.765 38.184 ;
     RECT  74.653 12.096 74.797 12.12 ;
     RECT  74.659 91.392 74.801 95.016 ;
     RECT  74.077 18.24 74.833 18.264 ;
     RECT  74.045 19.776 74.833 19.8 ;
     RECT  74.653 25.488 74.873 34.92 ;
     RECT  74.617 41.76 74.945 42.744 ;
     RECT  73.763 79.44 74.965 79.464 ;
     RECT  74.833 18.24 75.017 19.8 ;
     RECT  72.904 13.92 75.049 13.944 ;
     RECT  74.965 79.44 75.053 80.376 ;
     RECT  75.053 79.44 75.059 79.944 ;
     RECT  74.081 67.92 75.125 69.576 ;
     RECT  74.617 75.6 75.125 77.4 ;
     RECT  74.797 12 75.157 12.12 ;
     RECT  74.617 22.176 75.157 24.504 ;
     RECT  74.873 25.488 75.157 29.352 ;
     RECT  75.157 12 75.193 12.36 ;
     RECT  74.677 74.592 75.193 74.616 ;
     RECT  74.653 48.624 75.197 48.648 ;
     RECT  74.339 47.28 75.205 47.4 ;
     RECT  74.509 86.736 75.233 90.024 ;
     RECT  75.193 11.04 75.265 12.36 ;
     RECT  74.725 72 75.265 73.08 ;
     RECT  74.099 82.368 75.265 83.016 ;
     RECT  75.017 18.24 75.301 18.264 ;
     RECT  74.873 30.624 75.301 34.92 ;
     RECT  74.765 35.904 75.301 37.992 ;
     RECT  74.477 39.456 75.305 39.576 ;
     RECT  74.761 58.848 75.305 65.16 ;
     RECT  75.125 67.92 75.305 69.48 ;
     RECT  75.265 9.6 75.337 9.624 ;
     RECT  75.265 10.704 75.337 12.36 ;
     RECT  75.301 17.472 75.337 18.264 ;
     RECT  74.801 91.392 75.34 94.92 ;
     RECT  74.153 57.408 75.341 57.432 ;
     RECT  75.305 60.384 75.377 65.16 ;
     RECT  75.205 47.088 75.409 47.4 ;
     RECT  75.157 7.104 75.445 7.128 ;
     RECT  75.305 67.92 75.449 69.192 ;
     RECT  75.265 72 75.517 73.128 ;
     RECT  75.337 16.8 75.521 18.264 ;
     RECT  75.193 74.544 75.521 74.616 ;
     RECT  75.125 77.328 75.521 77.4 ;
     RECT  74.401 84.96 75.521 85.56 ;
     RECT  75.34 93.36 75.521 94.92 ;
     RECT  75.521 74.592 75.553 74.616 ;
     RECT  75.125 75.6 75.553 75.864 ;
     RECT  74.729 52.176 75.557 54.792 ;
     RECT  75.337 9.6 75.629 12.36 ;
     RECT  75.377 61.056 75.629 65.16 ;
     RECT  75.049 13.344 75.661 13.944 ;
     RECT  74.693 2.496 75.665 3.336 ;
     RECT  75.233 87.024 75.692 90.024 ;
     RECT  75.34 91.392 75.692 91.8 ;
     RECT  75.661 13.344 75.701 14.136 ;
     RECT  75.301 30.624 75.701 37.992 ;
     RECT  75.557 52.176 75.701 54.456 ;
     RECT  75.449 68.064 75.701 68.088 ;
     RECT  75.521 84.96 75.701 85.512 ;
     RECT  75.157 22.176 75.731 29.352 ;
     RECT  75.521 16.8 75.773 17.496 ;
     RECT  75.305 39.456 75.773 39.528 ;
     RECT  75.731 22.176 75.779 25.128 ;
     RECT  75.629 61.104 75.779 65.16 ;
     RECT  75.692 87.024 75.779 91.8 ;
     RECT  74.729 66.336 75.781 66.36 ;
     RECT  74.725 44.064 75.809 46.104 ;
     RECT  75.779 91.152 75.809 91.8 ;
     RECT  75.017 19.584 75.827 19.8 ;
     RECT  75.779 63.36 75.827 65.16 ;
     RECT  75.629 9.6 75.845 12.12 ;
     RECT  74.693 50.016 75.845 50.856 ;
     RECT  75.827 63.36 75.845 65.016 ;
     RECT  75.265 82.032 75.849 83.016 ;
     RECT  75.445 7.104 75.881 7.416 ;
     RECT  75.701 33.408 75.881 37.992 ;
     RECT  75.773 39.456 75.881 39.48 ;
     RECT  75.809 45.696 75.881 46.104 ;
     RECT  75.665 2.496 75.917 3.192 ;
     RECT  75.849 82.032 75.923 83.832 ;
     RECT  75.805 16.416 75.989 16.44 ;
     RECT  75.845 50.448 75.989 50.856 ;
     RECT  75.521 93.36 75.989 94.632 ;
     RECT  75.409 47.088 76.025 47.64 ;
     RECT  75.517 72 76.025 73.56 ;
     RECT  75.553 74.592 76.025 75.864 ;
     RECT  75.059 79.44 76.025 79.464 ;
     RECT  75.845 10.704 76.061 12.12 ;
     RECT  75.881 7.104 76.093 7.128 ;
     RECT  75.701 13.92 76.093 14.136 ;
     RECT  75.305 58.848 76.097 59.304 ;
     RECT  76.025 72.576 76.097 73.56 ;
     RECT  75.809 44.064 76.129 44.376 ;
     RECT  75.781 66.192 76.273 66.36 ;
     RECT  75.701 30.624 76.309 32.376 ;
     RECT  75.779 22.176 76.313 24.744 ;
     RECT  75.845 9.6 76.385 9.624 ;
     RECT  76.313 22.176 76.385 24.552 ;
     RECT  76.093 6.912 76.421 7.128 ;
     RECT  75.701 84.96 76.421 84.984 ;
     RECT  74.945 42.72 76.453 42.744 ;
     RECT  75.731 26.352 76.457 29.352 ;
     RECT  76.457 28.224 76.489 29.352 ;
     RECT  76.309 30.576 76.489 32.376 ;
     RECT  75.827 19.584 76.493 19.656 ;
     RECT  76.453 42.528 76.561 42.744 ;
     RECT  76.129 43.872 76.561 44.376 ;
     RECT  76.561 42.528 76.565 44.376 ;
     RECT  75.701 52.176 76.565 54.408 ;
     RECT  75.779 87.024 76.565 89.736 ;
     RECT  76.565 43.344 76.601 44.376 ;
     RECT  75.449 69.168 76.633 69.192 ;
     RECT  76.565 87.024 76.637 89.496 ;
     RECT  75.781 78.096 76.673 78.12 ;
     RECT  76.097 58.944 76.748 59.304 ;
     RECT  75.779 61.104 76.748 61.992 ;
     RECT  75.989 50.448 76.781 50.712 ;
     RECT  76.421 6.912 76.813 6.936 ;
     RECT  76.748 58.944 76.835 61.992 ;
     RECT  76.273 66.192 76.849 66.84 ;
     RECT  75.923 82.896 76.885 83.832 ;
     RECT  76.093 13.92 76.921 14.52 ;
     RECT  76.835 58.944 76.925 59.304 ;
     RECT  76.885 82.896 76.931 84.888 ;
     RECT  75.989 93.36 76.957 94.152 ;
     RECT  75.845 63.744 76.961 65.016 ;
     RECT  76.025 75.84 76.961 75.864 ;
     RECT  76.669 80.112 76.961 80.136 ;
     RECT  76.813 57.6 76.981 57.624 ;
     RECT  75.773 17.472 76.997 17.496 ;
     RECT  76.981 57.168 77.027 57.624 ;
     RECT  76.921 13.92 77.033 14.904 ;
     RECT  76.457 26.352 77.101 26.904 ;
     RECT  76.061 10.8 77.137 12.12 ;
     RECT  76.849 66.192 77.137 67.752 ;
     RECT  76.637 87.024 77.173 88.92 ;
     RECT  76.957 93.264 77.281 94.152 ;
     RECT  76.385 22.176 77.353 23.352 ;
     RECT  76.835 61.104 77.353 61.992 ;
     RECT  76.633 68.928 77.353 69.192 ;
     RECT  76.933 54.624 77.453 54.648 ;
     RECT  75.877 4.656 77.461 4.68 ;
     RECT  77.425 5.856 77.461 5.88 ;
     RECT  76.489 28.224 77.461 32.376 ;
     RECT  75.881 33.408 77.461 33.624 ;
     RECT  76.565 52.176 77.497 53.592 ;
     RECT  77.101 25.728 77.525 26.904 ;
     RECT  77.353 21.984 77.533 23.352 ;
     RECT  76.385 24.336 77.533 24.552 ;
     RECT  75.881 34.656 77.533 37.992 ;
     RECT  76.931 82.992 77.605 84.888 ;
     RECT  77.353 61.104 77.713 62.232 ;
     RECT  77.461 28.224 77.785 33.624 ;
     RECT  76.025 74.592 77.785 74.616 ;
     RECT  76.885 49.008 77.813 49.032 ;
     RECT  77.461 40.032 77.821 40.056 ;
     RECT  76.885 41.52 77.821 41.544 ;
     RECT  76.025 47.088 77.845 47.112 ;
     RECT  77.713 61.104 77.893 62.424 ;
     RECT  76.601 43.344 77.929 43.368 ;
     RECT  76.813 44.448 77.929 44.472 ;
     RECT  76.781 50.544 77.965 50.712 ;
     RECT  77.497 52.128 77.965 53.592 ;
     RECT  77.453 54.624 77.965 55.608 ;
     RECT  77.281 93.264 77.965 94.632 ;
     RECT  75.917 2.496 78.008 2.52 ;
     RECT  77.461 4.656 78.008 5.88 ;
     RECT  76.813 6.864 78.008 6.936 ;
     RECT  77.137 10.8 78.008 12.36 ;
     RECT  77.033 13.92 78.008 13.944 ;
     RECT  77.209 17.664 78.008 17.688 ;
     RECT  76.493 19.584 78.008 19.608 ;
     RECT  77.533 21.984 78.008 24.552 ;
     RECT  77.525 25.68 78.008 26.904 ;
     RECT  77.785 27.888 78.008 33.624 ;
     RECT  77.533 34.656 78.008 38.184 ;
     RECT  77.821 40.032 78.008 41.544 ;
     RECT  77.929 43.344 78.008 44.472 ;
     RECT  75.881 45.696 78.008 45.72 ;
     RECT  77.845 47.088 78.008 47.304 ;
     RECT  77.813 48.48 78.008 49.032 ;
     RECT  77.965 50.304 78.008 50.712 ;
     RECT  77.965 52.128 78.008 55.608 ;
     RECT  77.027 57.168 78.008 57.432 ;
     RECT  76.925 58.944 78.008 59.208 ;
     RECT  77.893 60.672 78.008 62.424 ;
     RECT  76.961 63.744 78.008 64.392 ;
     RECT  77.137 66.192 78.008 67.848 ;
     RECT  77.353 68.928 78.008 69.768 ;
     RECT  76.097 72.624 78.008 73.56 ;
     RECT  77.785 74.592 78.008 75.24 ;
     RECT  77.605 82.992 78.008 84.936 ;
     RECT  77.173 86.544 78.008 88.92 ;
     RECT  76.741 90.624 78.008 90.648 ;
     RECT  75.809 91.728 78.008 91.8 ;
     RECT  77.965 93.024 78.008 94.632 ;
     RECT  78.008 2.148 78.112 97.212 ;
     RECT  78.112 2.304 78.304 96.942 ;
     RECT  78.304 4.656 78.365 6.936 ;
     RECT  78.304 66.048 78.401 68.568 ;
     RECT  78.304 34.656 78.434 37.992 ;
     RECT  78.304 64.176 78.473 64.344 ;
     RECT  78.434 34.656 78.581 37.944 ;
     RECT  78.304 50.304 78.617 50.568 ;
     RECT  78.304 53.328 78.617 57.432 ;
     RECT  78.304 12.24 78.689 12.36 ;
     RECT  78.401 66.336 78.689 68.568 ;
     RECT  78.304 69.744 78.689 69.768 ;
     RECT  78.304 73.056 78.689 75.24 ;
     RECT  78.617 53.328 78.725 53.832 ;
     RECT  78.304 15.984 78.761 16.008 ;
     RECT  78.365 4.656 78.797 6.408 ;
     RECT  78.304 2.304 78.833 2.616 ;
     RECT  78.617 50.304 78.833 50.328 ;
     RECT  78.304 43.872 78.869 43.896 ;
     RECT  78.797 5.424 78.905 6.408 ;
     RECT  78.304 90.384 78.905 90.6 ;
     RECT  78.304 48.432 78.941 49.272 ;
     RECT  78.304 51.648 78.941 52.296 ;
     RECT  78.617 54.912 78.941 57.432 ;
     RECT  78.304 17.664 78.977 19.608 ;
     RECT  78.905 90.384 79.013 90.552 ;
     RECT  78.833 2.304 79.121 2.328 ;
     RECT  78.689 73.056 79.121 73.08 ;
     RECT  78.941 48.432 79.157 48.456 ;
     RECT  78.304 84.864 79.193 85.224 ;
     RECT  78.304 27.888 79.265 33.576 ;
     RECT  78.941 55.44 79.265 57.432 ;
     RECT  78.689 12.24 79.292 12.312 ;
     RECT  79.292 11.52 79.297 12.312 ;
     RECT  78.473 64.32 79.337 64.344 ;
     RECT  78.689 74.592 79.337 75.24 ;
     RECT  78.304 92.496 79.369 94.728 ;
     RECT  78.304 47.088 79.409 47.112 ;
     RECT  78.977 18 79.436 19.608 ;
     RECT  79.193 84.912 79.445 85.224 ;
     RECT  78.304 78.72 79.477 79.32 ;
     RECT  79.477 78.624 79.513 79.32 ;
     RECT  79.436 18 79.523 19.752 ;
     RECT  78.304 86.4 79.549 88.968 ;
     RECT  78.304 44.976 79.553 45.96 ;
     RECT  78.581 34.656 79.58 37.608 ;
     RECT  79.297 11.376 79.585 12.312 ;
     RECT  78.304 71.376 79.585 71.88 ;
     RECT  79.58 34.656 79.621 37.8 ;
     RECT  79.621 58.704 79.657 58.728 ;
     RECT  79.523 18.816 79.661 19.656 ;
     RECT  79.013 90.384 79.661 90.408 ;
     RECT  79.621 34.656 79.705 38.136 ;
     RECT  78.304 59.952 79.729 63.192 ;
     RECT  79.513 78.528 79.733 79.32 ;
     RECT  78.689 66.336 79.765 66.84 ;
     RECT  79.265 55.44 79.769 57.192 ;
     RECT  79.265 28.272 79.801 33.576 ;
     RECT  79.705 34.656 79.801 37.608 ;
     RECT  79.693 64.992 79.805 65.016 ;
     RECT  79.549 86.208 79.805 88.968 ;
     RECT  78.304 40.032 79.829 40.296 ;
     RECT  78.689 67.824 79.841 68.568 ;
     RECT  79.805 86.688 79.841 88.968 ;
     RECT  79.585 10.848 79.873 12.312 ;
     RECT  78.941 51.648 79.873 52.2 ;
     RECT  79.585 71.376 79.877 72.792 ;
     RECT  79.769 56.016 79.907 57.192 ;
     RECT  78.304 13.92 79.909 13.944 ;
     RECT  79.829 39.36 79.913 40.296 ;
     RECT  79.733 78.624 79.913 79.32 ;
     RECT  79.553 45.936 79.945 45.96 ;
     RECT  79.873 10.848 79.949 12.552 ;
     RECT  79.913 40.272 79.949 40.296 ;
     RECT  79.949 11.376 79.985 12.552 ;
     RECT  79.873 42.768 79.985 42.792 ;
     RECT  79.873 50.784 79.985 52.2 ;
     RECT  78.905 5.424 80.017 5.448 ;
     RECT  79.369 92.496 80.017 94.92 ;
     RECT  79.729 59.808 80.021 63.192 ;
     RECT  79.985 11.376 80.057 12.264 ;
     RECT  79.877 72.768 80.057 72.792 ;
     RECT  80.017 5.424 80.093 6.264 ;
     RECT  79.909 13.824 80.093 13.944 ;
     RECT  79.913 79.296 80.093 79.32 ;
     RECT  80.017 92.448 80.125 94.92 ;
     RECT  79.657 58.56 80.129 58.728 ;
     RECT  78.725 53.328 80.165 53.736 ;
     RECT  79.765 66.24 80.269 66.84 ;
     RECT  79.841 67.824 80.269 67.848 ;
     RECT  79.333 8.448 80.273 8.472 ;
     RECT  79.907 56.016 80.273 57.096 ;
     RECT  78.304 23.04 80.341 26.856 ;
     RECT  79.945 45.936 80.345 46.776 ;
     RECT  80.273 56.016 80.345 56.808 ;
     RECT  80.021 63.168 80.345 63.192 ;
     RECT  79.445 84.912 80.413 85.176 ;
     RECT  78.304 21.504 80.417 21.528 ;
     RECT  80.269 66.24 80.417 67.848 ;
     RECT  80.413 84.912 80.449 85.272 ;
     RECT  79.985 51.648 80.453 52.2 ;
     RECT  80.449 69.648 80.485 69.672 ;
     RECT  79.877 71.376 80.485 71.736 ;
     RECT  80.021 59.808 80.489 62.04 ;
     RECT  80.125 91.872 80.521 94.92 ;
     RECT  79.337 74.592 80.525 74.616 ;
     RECT  80.449 84.864 80.557 85.272 ;
     RECT  80.269 43.296 80.669 43.32 ;
     RECT  80.377 54.672 80.669 54.744 ;
     RECT  80.345 56.4 80.669 56.808 ;
     RECT  80.629 74.016 80.701 74.568 ;
     RECT  80.165 53.328 80.705 53.352 ;
     RECT  80.701 73.392 80.813 74.568 ;
     RECT  79.801 28.272 80.849 37.608 ;
     RECT  80.669 54.72 80.849 54.744 ;
     RECT  80.485 69.648 80.881 71.736 ;
     RECT  80.489 60.96 80.885 61.608 ;
     RECT  80.417 66.24 80.885 67.176 ;
     RECT  80.341 22.704 80.917 26.856 ;
     RECT  80.521 91.872 80.917 94.968 ;
     RECT  80.129 58.704 80.921 58.728 ;
     RECT  80.489 59.808 80.921 59.976 ;
     RECT  80.953 39.936 80.989 39.96 ;
     RECT  80.849 36.096 80.993 37.608 ;
     RECT  80.921 59.808 80.993 59.832 ;
     RECT  80.849 28.272 81.011 35.112 ;
     RECT  80.917 22.512 81.061 26.856 ;
     RECT  80.669 56.4 81.065 56.424 ;
     RECT  81.011 28.272 81.133 34.968 ;
     RECT  78.304 82.992 81.133 83.016 ;
     RECT  80.521 42.144 81.169 42.168 ;
     RECT  80.093 13.824 81.173 13.848 ;
     RECT  80.993 36.096 81.173 37.464 ;
     RECT  81.089 44.448 81.173 44.472 ;
     RECT  80.737 17.568 81.241 17.592 ;
     RECT  79.661 19.488 81.281 19.656 ;
     RECT  80.989 39.936 81.281 40.296 ;
     RECT  81.205 63.744 81.349 63.768 ;
     RECT  80.881 69.648 81.349 72.408 ;
     RECT  79.841 86.688 81.349 88.92 ;
     RECT  81.281 39.936 81.353 39.96 ;
     RECT  80.057 12.24 81.385 12.264 ;
     RECT  81.349 63.264 81.433 63.768 ;
     RECT  81.433 63.744 81.445 63.768 ;
     RECT  79.585 48.048 81.461 48.072 ;
     RECT  81.349 86.64 81.461 88.92 ;
     RECT  81.133 27.936 81.491 34.968 ;
     RECT  81.445 63.744 81.491 64.392 ;
     RECT  81.461 86.688 81.493 88.92 ;
     RECT  81.385 10.896 81.533 10.92 ;
     RECT  81.349 68.928 81.533 72.408 ;
     RECT  80.813 73.776 81.539 74.568 ;
     RECT  81.385 11.952 81.565 12.264 ;
     RECT  81.061 21.744 81.565 26.856 ;
     RECT  81.491 27.936 81.565 30.744 ;
     RECT  81.493 86.688 81.569 89.448 ;
     RECT  80.885 66.672 81.601 67.176 ;
     RECT  80.917 91.872 81.601 95.064 ;
     RECT  81.241 3.12 81.605 3.144 ;
     RECT  81.565 11.952 81.605 13.128 ;
     RECT  80.345 45.936 81.641 46.104 ;
     RECT  80.557 84.672 81.641 85.272 ;
     RECT  81.241 17.568 81.673 17.688 ;
     RECT  81.173 36.096 81.677 36.456 ;
     RECT  81.529 41.04 81.677 41.064 ;
     RECT  81.641 84.672 81.713 85.224 ;
     RECT  81.641 45.936 81.889 45.96 ;
     RECT  81.445 62.736 81.893 62.76 ;
     RECT  81.601 66.672 81.893 67.704 ;
     RECT  81.605 11.952 81.961 12.072 ;
     RECT  81.493 49.248 81.961 49.272 ;
     RECT  81.565 21.744 81.965 30.744 ;
     RECT  81.169 42.144 81.997 42.264 ;
     RECT  80.885 61.008 82.033 61.608 ;
     RECT  81.965 21.744 82.037 30.6 ;
     RECT  80.341 16.128 82.069 16.152 ;
     RECT  81.673 17.568 82.069 18.168 ;
     RECT  81.491 31.872 82.069 34.968 ;
     RECT  81.677 36.096 82.069 36.312 ;
     RECT  81.961 49.2 82.069 49.272 ;
     RECT  81.889 78.72 82.109 79.224 ;
     RECT  80.093 6.24 82.115 6.264 ;
     RECT  80.453 52.176 82.124 52.2 ;
     RECT  82.033 60.624 82.141 61.608 ;
     RECT  81.601 91.872 82.181 95.16 ;
     RECT  82.181 91.872 82.217 93.48 ;
     RECT  81.961 62.64 82.253 62.664 ;
     RECT  80.269 80.784 82.429 80.808 ;
     RECT  81.173 37.44 82.433 37.464 ;
     RECT  81.569 86.736 82.433 89.448 ;
     RECT  82.357 9.216 82.501 9.24 ;
     RECT  81.961 11.184 82.501 12.072 ;
     RECT  81.491 64.368 82.537 64.392 ;
     RECT  82.033 53.376 82.573 53.4 ;
     RECT  81.893 67.152 82.609 67.704 ;
     RECT  81.533 68.928 82.609 71.736 ;
     RECT  81.713 84.672 82.609 84.984 ;
     RECT  81.281 19.488 82.645 19.512 ;
     RECT  81.889 45.792 82.645 45.96 ;
     RECT  82.069 49.2 82.645 49.368 ;
     RECT  82.573 53.376 82.645 53.976 ;
     RECT  82.429 80.64 82.681 80.808 ;
     RECT  82.069 31.872 82.753 36.312 ;
     RECT  82.645 45.792 82.825 46.056 ;
     RECT  82.645 53.376 82.861 54.072 ;
     RECT  82.799 58.608 82.861 58.632 ;
     RECT  82.753 40.896 82.897 40.92 ;
     RECT  81.997 42.144 82.897 42.456 ;
     RECT  82.537 4.944 82.933 4.968 ;
     RECT  82.069 16.128 82.933 18.168 ;
     RECT  82.645 19.488 82.933 19.608 ;
     RECT  82.433 86.736 83.005 86.904 ;
     RECT  82.897 40.896 83.036 42.456 ;
     RECT  82.861 57.696 83.036 58.632 ;
     RECT  83.036 57.264 83.041 58.632 ;
     RECT  82.933 16.128 83.077 19.608 ;
     RECT  82.124 52.176 83.077 52.392 ;
     RECT  82.861 53.376 83.077 54.552 ;
     RECT  82.037 21.744 83.113 21.768 ;
     RECT  82.501 11.088 83.125 12.072 ;
     RECT  81.605 13.104 83.125 13.128 ;
     RECT  83.113 21.408 83.185 21.768 ;
     RECT  82.321 56.208 83.221 56.232 ;
     RECT  83.041 57.264 83.221 58.728 ;
     RECT  83.077 15.744 83.249 19.608 ;
     RECT  82.037 22.752 83.257 30.6 ;
     RECT  82.753 31.872 83.257 36.648 ;
     RECT  82.537 63.648 83.269 64.392 ;
     RECT  81.601 65.52 83.269 65.544 ;
     RECT  82.825 44.976 83.329 46.056 ;
     RECT  82.609 84.624 83.329 84.984 ;
     RECT  82.429 3.84 83.408 3.864 ;
     RECT  82.933 4.944 83.408 5.496 ;
     RECT  82.501 8.88 83.408 9.24 ;
     RECT  83.125 11.088 83.408 13.128 ;
     RECT  83.249 15.744 83.408 19.848 ;
     RECT  83.185 21.12 83.408 21.768 ;
     RECT  83.257 22.752 83.408 36.648 ;
     RECT  82.969 38.16 83.408 38.184 ;
     RECT  83.293 39.504 83.408 39.528 ;
     RECT  83.036 40.608 83.408 42.456 ;
     RECT  83.329 44.976 83.408 46.776 ;
     RECT  82.645 48.288 83.408 49.368 ;
     RECT  83.077 52.176 83.408 54.552 ;
     RECT  83.221 56.208 83.408 58.728 ;
     RECT  82.141 59.952 83.408 61.608 ;
     RECT  83.269 63.648 83.408 65.544 ;
     RECT  82.609 67.152 83.408 71.736 ;
     RECT  81.539 73.776 83.408 73.8 ;
     RECT  82.141 75.264 83.408 75.288 ;
     RECT  82.109 78.72 83.408 78.744 ;
     RECT  82.681 80.64 83.408 81.096 ;
     RECT  81.133 82.8 83.408 83.016 ;
     RECT  83.329 84.624 83.408 85.416 ;
     RECT  83.005 86.592 83.408 86.904 ;
     RECT  82.433 88.368 83.408 89.448 ;
     RECT  82.217 91.872 83.408 93.336 ;
     RECT  82.181 94.56 83.408 95.16 ;
     RECT  83.408 2.148 83.512 97.212 ;
     RECT  83.512 2.418 83.704 96.942 ;
     RECT  83.704 31.968 83.729 42.744 ;
     RECT  83.729 40.32 83.765 42.744 ;
     RECT  83.704 68.928 83.765 69.048 ;
     RECT  83.704 51.936 83.801 54.12 ;
     RECT  83.704 64.944 83.837 65.544 ;
     RECT  83.704 71.808 83.837 72.216 ;
     RECT  83.729 31.968 83.881 39.288 ;
     RECT  83.881 36.576 83.884 39.288 ;
     RECT  83.704 80.784 83.909 80.808 ;
     RECT  83.704 82.8 83.909 83.544 ;
     RECT  83.909 82.992 83.945 83.544 ;
     RECT  83.704 86.64 84.017 89.496 ;
     RECT  83.704 10.848 84.035 11.976 ;
     RECT  83.704 17.616 84.035 17.64 ;
     RECT  83.704 18.672 84.035 20.472 ;
     RECT  83.881 31.968 84.053 35.592 ;
     RECT  83.704 77.568 84.053 78.84 ;
     RECT  84.035 11.952 84.125 11.976 ;
     RECT  84.035 19.92 84.131 20.472 ;
     RECT  84.053 33.792 84.169 35.592 ;
     RECT  83.704 14.784 84.197 16.44 ;
     RECT  84.169 33.888 84.205 35.592 ;
     RECT  84.205 33.984 84.22 35.592 ;
     RECT  84.053 77.76 84.233 78.84 ;
     RECT  84.22 34.032 84.269 35.592 ;
     RECT  83.765 40.32 84.269 41.544 ;
     RECT  84.131 19.92 84.275 19.944 ;
     RECT  83.704 55.824 84.305 57.576 ;
     RECT  83.945 82.992 84.377 83.304 ;
     RECT  84.269 34.08 84.449 35.592 ;
     RECT  83.704 84.672 84.449 85.416 ;
     RECT  83.704 23.28 84.485 25.608 ;
     RECT  84.449 34.176 84.485 35.592 ;
     RECT  83.704 75.216 84.485 75.24 ;
     RECT  84.035 10.848 84.521 10.872 ;
     RECT  84.485 23.28 84.521 24.504 ;
     RECT  84.485 25.584 84.521 25.608 ;
     RECT  83.704 94.56 84.521 95.16 ;
     RECT  83.704 58.704 84.593 58.728 ;
     RECT  83.837 71.808 84.611 71.832 ;
     RECT  83.704 67.152 84.629 67.704 ;
     RECT  84.521 94.56 84.629 94.92 ;
     RECT  84.449 84.768 84.665 85.416 ;
     RECT  83.704 22.224 84.697 22.248 ;
     RECT  83.704 27.888 84.701 30.792 ;
     RECT  84.697 21.936 84.733 22.248 ;
     RECT  84.629 67.68 84.737 67.704 ;
     RECT  84.269 40.32 84.805 41.256 ;
     RECT  83.765 68.928 84.805 68.952 ;
     RECT  83.704 70.032 84.805 70.824 ;
     RECT  83.704 49.056 84.809 49.08 ;
     RECT  84.017 86.64 84.841 86.952 ;
     RECT  84.733 21.216 84.845 22.248 ;
     RECT  84.701 27.888 84.845 29.304 ;
     RECT  84.805 68.928 84.845 70.824 ;
     RECT  84.845 27.888 84.881 28.92 ;
     RECT  84.053 31.968 84.901 32.328 ;
     RECT  83.704 6 84.913 6.024 ;
     RECT  84.881 27.888 84.917 28.728 ;
     RECT  83.704 44.928 84.917 46.056 ;
     RECT  83.704 4.512 84.949 4.536 ;
     RECT  84.913 6 84.953 6.312 ;
     RECT  83.704 43.824 84.953 43.848 ;
     RECT  83.884 36.624 84.985 39.288 ;
     RECT  84.805 40.272 84.985 41.256 ;
     RECT  83.837 64.944 84.985 64.968 ;
     RECT  84.629 94.56 84.985 94.584 ;
     RECT  84.949 4.512 84.989 4.632 ;
     RECT  83.765 42.72 85.021 42.744 ;
     RECT  84.917 45.84 85.025 46.056 ;
     RECT  84.197 16.032 85.057 16.44 ;
     RECT  83.801 54.096 85.057 54.12 ;
     RECT  84.197 14.784 85.061 14.808 ;
     RECT  85.021 42.72 85.061 43.032 ;
     RECT  84.845 21.216 85.097 21.24 ;
     RECT  84.985 94.512 85.097 94.584 ;
     RECT  84.701 30.384 85.133 30.792 ;
     RECT  84.233 77.76 85.169 78.648 ;
     RECT  83.704 91.776 85.169 93.24 ;
     RECT  84.985 64.464 85.196 64.968 ;
     RECT  85.196 64.464 85.237 65.16 ;
     RECT  85.057 16.032 85.273 17.112 ;
     RECT  83.801 51.936 85.273 53.016 ;
     RECT  85.057 54.096 85.273 54.792 ;
     RECT  85.237 63.792 85.283 65.16 ;
     RECT  85.273 16.032 85.309 17.448 ;
     RECT  84.035 18.672 85.309 18.696 ;
     RECT  84.017 88.176 85.313 89.496 ;
     RECT  85.097 94.512 85.349 94.536 ;
     RECT  84.305 55.824 85.385 56.232 ;
     RECT  85.129 81.36 85.385 81.384 ;
     RECT  84.985 36.624 85.421 41.256 ;
     RECT  85.283 63.792 85.421 64.776 ;
     RECT  85.025 46.032 85.453 46.056 ;
     RECT  84.917 27.888 85.477 28.296 ;
     RECT  84.901 31.92 85.477 32.328 ;
     RECT  85.309 16.032 85.489 18.696 ;
     RECT  85.453 19.92 85.489 19.944 ;
     RECT  84.845 22.224 85.489 22.248 ;
     RECT  84.521 23.28 85.489 24.168 ;
     RECT  85.477 31.344 85.489 32.472 ;
     RECT  85.417 26.448 85.523 26.472 ;
     RECT  84.841 85.68 85.525 86.952 ;
     RECT  84.485 34.464 85.529 35.592 ;
     RECT  85.453 46.032 85.597 46.536 ;
     RECT  84.953 6.288 85.601 6.312 ;
     RECT  84.845 69.168 85.601 69.192 ;
     RECT  85.313 88.896 85.601 89.496 ;
     RECT  85.273 51.936 85.705 54.792 ;
     RECT  85.385 55.824 85.705 56.088 ;
     RECT  85.601 88.944 85.705 89.496 ;
     RECT  84.989 4.608 85.709 4.632 ;
     RECT  84.877 66.144 85.709 66.168 ;
     RECT  85.421 40.896 85.717 41.256 ;
     RECT  85.529 34.8 85.741 35.592 ;
     RECT  85.421 36.624 85.741 39.768 ;
     RECT  85.525 74.736 85.745 74.76 ;
     RECT  85.705 88.944 85.745 90.072 ;
     RECT  85.597 46.032 85.763 46.776 ;
     RECT  85.705 51.936 85.765 56.088 ;
     RECT  85.765 51.264 85.811 56.088 ;
     RECT  85.811 51.264 85.813 51.288 ;
     RECT  84.305 57.552 85.813 57.576 ;
     RECT  85.561 58.896 85.813 58.92 ;
     RECT  84.377 82.992 85.813 83.016 ;
     RECT  85.811 52.992 85.817 56.088 ;
     RECT  85.813 50.736 85.853 51.288 ;
     RECT  85.817 54.72 85.853 55.848 ;
     RECT  84.845 70.8 85.861 70.824 ;
     RECT  85.813 57.552 85.889 58.92 ;
     RECT  85.853 50.736 85.897 50.76 ;
     RECT  85.861 70.032 85.907 70.824 ;
     RECT  85.477 27.6 85.921 28.296 ;
     RECT  85.489 16.032 85.925 19.944 ;
     RECT  85.889 57.552 85.925 58.728 ;
     RECT  85.907 70.032 85.948 70.056 ;
     RECT  85.763 46.512 85.957 46.776 ;
     RECT  85.453 47.856 85.957 47.88 ;
     RECT  85.813 82.56 85.961 83.016 ;
     RECT  85.885 68.976 85.969 69 ;
     RECT  85.921 27.6 85.985 29.256 ;
     RECT  85.061 43.008 85.993 43.032 ;
     RECT  85.909 67.68 85.996 67.704 ;
     RECT  85.853 54.816 85.997 55.848 ;
     RECT  85.849 76.656 85.997 76.68 ;
     RECT  85.745 88.944 85.997 88.968 ;
     RECT  85.741 34.8 86.033 39.768 ;
     RECT  85.453 63.264 86.033 63.288 ;
     RECT  85.745 90.048 86.053 90.072 ;
     RECT  85.525 44.448 86.06 44.472 ;
     RECT  85.997 54.816 86.069 54.84 ;
     RECT  86.053 90.048 86.099 90.648 ;
     RECT  85.925 19.248 86.105 19.944 ;
     RECT  85.489 22.224 86.105 24.168 ;
     RECT  86.033 34.8 86.105 38.76 ;
     RECT  86.033 39.744 86.105 39.768 ;
     RECT  85.925 57.552 86.105 57.912 ;
     RECT  85.421 64.464 86.105 64.776 ;
     RECT  85.169 77.808 86.105 78.648 ;
     RECT  85.957 46.512 86.141 47.88 ;
     RECT  86.105 77.808 86.141 77.832 ;
     RECT  86.06 44.448 86.147 45.384 ;
     RECT  85.961 82.896 86.173 83.016 ;
     RECT  85.817 52.992 86.177 53.016 ;
     RECT  85.489 31.344 86.209 33.048 ;
     RECT  86.105 34.8 86.221 34.824 ;
     RECT  85.169 91.872 86.249 93.24 ;
     RECT  85.925 16.032 86.285 18.264 ;
     RECT  86.105 57.792 86.285 57.816 ;
     RECT  85.525 85.68 86.285 87.432 ;
     RECT  85.985 27.6 86.293 30.024 ;
     RECT  86.209 31.344 86.293 33.336 ;
     RECT  86.285 16.032 86.321 16.104 ;
     RECT  86.293 27.6 86.339 33.336 ;
     RECT  85.993 43.008 86.353 43.272 ;
     RECT  86.285 17.088 86.357 18.264 ;
     RECT  86.141 46.512 86.357 47.352 ;
     RECT  86.285 85.872 86.357 87.432 ;
     RECT  86.353 43.008 86.393 43.32 ;
     RECT  86.357 86.64 86.393 87.432 ;
     RECT  86.339 27.6 86.435 30.744 ;
     RECT  86.435 27.888 86.476 30.744 ;
     RECT  85.741 14.832 86.497 14.856 ;
     RECT  86.321 16.08 86.501 16.104 ;
     RECT  86.357 46.752 86.501 47.352 ;
     RECT  86.425 80.208 86.537 80.232 ;
     RECT  86.173 82.896 86.537 83.064 ;
     RECT  85.813 49.536 86.569 49.56 ;
     RECT  86.105 35.904 86.609 38.76 ;
     RECT  86.497 14.736 86.645 14.856 ;
     RECT  86.357 17.088 86.645 17.448 ;
     RECT  86.609 35.904 86.645 38.712 ;
     RECT  86.245 77.424 86.645 77.448 ;
     RECT  86.537 82.896 86.645 83.016 ;
     RECT  86.105 23.28 86.681 24.168 ;
     RECT  86.569 79.2 86.681 79.224 ;
     RECT  86.645 82.992 86.681 83.016 ;
     RECT  86.249 91.872 86.717 92.712 ;
     RECT  85.717 40.896 86.785 41.832 ;
     RECT  86.393 43.248 86.789 43.32 ;
     RECT  86.476 27.888 86.819 28.296 ;
     RECT  86.785 40.896 86.869 42.168 ;
     RECT  86.869 40.896 86.897 41.832 ;
     RECT  86.105 19.248 86.933 19.56 ;
     RECT  86.147 44.448 86.933 44.472 ;
     RECT  86.819 27.888 87.077 27.912 ;
     RECT  86.476 29.376 87.221 30.744 ;
     RECT  86.789 43.296 87.221 43.32 ;
     RECT  86.105 64.752 87.257 64.776 ;
     RECT  86.933 19.248 87.293 19.272 ;
     RECT  86.681 24.144 87.293 24.168 ;
     RECT  86.569 49.152 87.293 49.56 ;
     RECT  86.645 17.184 87.325 17.448 ;
     RECT  86.897 40.896 87.329 41.064 ;
     RECT  87.001 7.968 87.361 7.992 ;
     RECT  86.339 31.776 87.397 33.336 ;
     RECT  87.397 31.776 87.443 33.672 ;
     RECT  87.443 33.648 87.452 33.672 ;
     RECT  87.289 13.44 87.473 13.464 ;
     RECT  86.501 47.328 87.473 47.352 ;
     RECT  87.293 49.536 87.473 49.56 ;
     RECT  87.469 12 87.505 12.024 ;
     RECT  87.325 17.184 87.509 17.832 ;
     RECT  87.443 31.776 87.509 32.52 ;
     RECT  86.645 35.904 87.509 37.368 ;
     RECT  85.997 55.824 87.509 55.848 ;
     RECT  86.099 90.624 87.509 90.648 ;
     RECT  86.717 91.872 87.509 91.896 ;
     RECT  87.452 5.088 87.539 5.112 ;
     RECT  87.221 29.376 87.539 30.456 ;
     RECT  87.452 33.648 87.539 34.536 ;
     RECT  87.509 37.344 87.539 37.368 ;
     RECT  87.452 40.224 87.539 40.248 ;
     RECT  87.509 17.328 87.545 17.832 ;
     RECT  87.505 12 87.553 12.168 ;
     RECT  87.539 29.664 87.581 30.072 ;
     RECT  87.361 7.632 87.596 7.992 ;
     RECT  87.217 9.408 87.617 9.432 ;
     RECT  87.596 7.632 87.653 8.376 ;
     RECT  87.553 12.144 87.653 12.168 ;
     RECT  87.539 33.648 87.653 33.672 ;
     RECT  87.653 8.352 87.683 8.376 ;
     RECT  87.545 17.808 87.683 17.832 ;
     RECT  87.509 31.776 87.689 32.472 ;
     RECT  87.613 78.432 87.692 78.456 ;
     RECT  87.613 58.704 87.725 58.728 ;
     RECT  87.692 78 87.725 78.456 ;
     RECT  86.645 14.736 87.761 14.76 ;
     RECT  87.685 8.496 87.779 8.52 ;
     RECT  87.289 15.984 87.779 16.008 ;
     RECT  87.725 78 87.779 78.024 ;
     RECT  86.393 86.64 87.779 86.664 ;
     RECT  86.645 38.688 87.833 38.712 ;
     RECT  87.689 32.448 88.337 32.472 ;
    LAYER M5 ;
     RECT  19.392 0.016 19.704 0.131 ;
     RECT  20.736 0.016 21.048 0.563 ;
     RECT  6.144 0.016 18.36 0.611 ;
     RECT  6.24 0.611 18.36 1.763 ;
     RECT  19.488 0.131 19.704 1.763 ;
     RECT  20.832 0.563 21.048 1.763 ;
     RECT  20.928 1.763 20.952 1.811 ;
     RECT  19.488 1.763 19.608 1.859 ;
     RECT  6.624 1.763 18.36 2.137 ;
     RECT  2.4 2.137 2.52 2.151 ;
     RECT  24 2.137 24.12 2.151 ;
     RECT  29.4 2.137 29.52 2.151 ;
     RECT  34.8 2.137 34.92 2.151 ;
     RECT  40.2 2.137 40.32 2.151 ;
     RECT  45.6 2.137 45.72 2.151 ;
     RECT  51 2.137 51.12 2.151 ;
     RECT  56.4 2.137 56.52 2.151 ;
     RECT  61.8 2.137 61.92 2.151 ;
     RECT  67.2 2.137 67.32 2.151 ;
     RECT  72.6 2.137 72.72 2.151 ;
     RECT  78 2.137 78.12 2.151 ;
     RECT  83.4 2.137 83.52 2.151 ;
     RECT  34.8 2.151 35.112 2.245 ;
     RECT  6.624 2.137 18.912 2.291 ;
     RECT  40.2 2.151 40.512 2.533 ;
     RECT  45.6 2.151 45.912 2.533 ;
     RECT  44.976 2.533 45.912 2.821 ;
     RECT  51 2.151 51.312 2.821 ;
     RECT  44.592 2.821 45.912 2.867 ;
     RECT  7.104 2.291 18.912 2.915 ;
     RECT  2.4 2.151 2.712 3.109 ;
     RECT  40.2 2.533 40.872 3.253 ;
     RECT  40.2 3.253 41.064 3.397 ;
     RECT  7.584 2.915 17.448 3.443 ;
     RECT  7.8 3.443 15.672 3.491 ;
     RECT  16.8 3.443 17.448 3.491 ;
     RECT  9.696 3.491 15.672 3.587 ;
     RECT  16.992 3.491 17.448 3.587 ;
     RECT  16.992 3.587 17.16 3.683 ;
     RECT  24 2.151 24.312 3.685 ;
     RECT  12.48 3.587 15.672 3.875 ;
     RECT  50.88 2.821 51.312 3.877 ;
     RECT  9.696 3.587 11.16 4.019 ;
     RECT  15.264 3.875 15.672 4.019 ;
     RECT  58.56 3.301 58.584 4.019 ;
     RECT  9.696 4.019 9.72 4.067 ;
     RECT  15.552 4.019 15.576 4.067 ;
     RECT  34.8 2.245 35.352 4.115 ;
     RECT  50.832 3.877 51.312 4.117 ;
     RECT  2.4 3.109 2.904 4.163 ;
     RECT  67.2 2.151 67.512 4.213 ;
     RECT  40.2 3.397 41.64 4.355 ;
     RECT  24 3.685 24.408 4.403 ;
     RECT  40.2 4.355 40.512 4.501 ;
     RECT  11.136 4.019 11.16 4.595 ;
     RECT  12.48 3.875 13.752 4.595 ;
     RECT  44.592 2.867 44.616 4.643 ;
     RECT  12.624 4.595 13.752 4.691 ;
     RECT  50.688 4.117 51.312 4.741 ;
     RECT  33.024 4.837 33.048 5.125 ;
     RECT  58.032 4.261 58.056 5.171 ;
     RECT  17.136 3.683 17.16 5.413 ;
     RECT  16.656 5.413 17.16 5.459 ;
     RECT  41.616 4.355 41.64 5.459 ;
     RECT  34.8 4.115 35.208 5.605 ;
     RECT  71.424 4.501 71.448 5.605 ;
     RECT  72.6 2.151 72.912 5.605 ;
     RECT  12.624 4.691 13.608 5.651 ;
     RECT  32.832 5.125 33.048 5.747 ;
     RECT  12.624 5.651 13.512 5.845 ;
     RECT  24 4.403 24.312 5.845 ;
     RECT  34.8 5.605 35.544 5.845 ;
     RECT  24 5.845 25.08 5.893 ;
     RECT  83.4 2.151 83.712 5.989 ;
     RECT  23.856 5.893 25.08 6.035 ;
     RECT  50.64 4.741 51.312 6.131 ;
     RECT  23.856 6.035 24.888 6.181 ;
     RECT  39.744 4.501 40.512 6.275 ;
     RECT  71.424 5.605 72.912 6.275 ;
     RECT  12.048 5.845 13.512 6.323 ;
     RECT  34.032 5.845 35.544 6.373 ;
     RECT  37.008 3.205 37.032 6.373 ;
     RECT  71.424 6.275 71.448 6.709 ;
     RECT  20.88 3.061 20.904 6.757 ;
     RECT  12.048 6.323 12.072 6.851 ;
     RECT  34.032 6.373 37.032 6.899 ;
     RECT  69.936 2.485 69.96 6.995 ;
     RECT  71.328 6.709 71.448 7.139 ;
     RECT  20.88 6.757 21.144 7.187 ;
     RECT  4.176 7.093 4.2 7.283 ;
     RECT  16.656 5.459 16.68 7.285 ;
     RECT  23.76 6.181 24.888 7.381 ;
     RECT  29.4 2.151 29.712 7.381 ;
     RECT  15.84 7.285 16.68 7.523 ;
     RECT  11.52 7.381 11.544 7.765 ;
     RECT  64.08 7.285 64.104 7.811 ;
     RECT  9.936 7.237 9.96 7.813 ;
     RECT  11.376 7.765 11.544 7.813 ;
     RECT  16.176 7.523 16.68 7.861 ;
     RECT  34.08 6.899 37.032 8.003 ;
     RECT  7.8 3.491 8.112 8.053 ;
     RECT  29.4 7.381 30.408 8.195 ;
     RECT  9.936 7.813 11.544 8.197 ;
     RECT  39.84 6.275 40.512 8.243 ;
     RECT  87.504 5.077 87.528 8.341 ;
     RECT  33.024 5.747 33.048 8.389 ;
     RECT  34.08 8.003 36.84 8.389 ;
     RECT  33.024 8.389 36.84 8.435 ;
     RECT  5.904 5.029 5.928 8.483 ;
     RECT  87.504 8.341 87.672 8.485 ;
     RECT  56.4 2.151 56.712 8.533 ;
     RECT  7.8 8.053 8.232 8.579 ;
     RECT  9.792 8.197 11.544 8.677 ;
     RECT  56.304 8.533 56.712 8.773 ;
     RECT  63.648 7.861 63.672 8.869 ;
     RECT  71.424 7.139 71.448 8.869 ;
     RECT  9.792 8.677 11.592 8.915 ;
     RECT  71.28 8.869 71.448 8.915 ;
     RECT  9.792 8.915 9.96 8.963 ;
     RECT  71.28 8.915 71.4 9.011 ;
     RECT  13.2 6.323 13.512 9.061 ;
     RECT  22.896 7.381 24.888 9.107 ;
     RECT  53.232 8.437 53.256 9.107 ;
     RECT  16.176 7.861 17.256 9.155 ;
     RECT  23.76 9.107 24.888 9.443 ;
     RECT  10.944 8.915 11.592 9.491 ;
     RECT  4.176 9.445 4.2 9.683 ;
     RECT  16.176 9.155 16.68 9.731 ;
     RECT  56.256 8.773 56.808 9.731 ;
     RECT  12.864 9.061 13.512 9.779 ;
     RECT  49.104 8.341 49.128 10.019 ;
     RECT  55.152 5.077 55.176 10.021 ;
     RECT  54.72 10.021 55.176 10.067 ;
     RECT  63.648 8.869 64.104 10.067 ;
     RECT  33.648 8.435 36.84 10.165 ;
     RECT  71.376 9.011 71.4 10.213 ;
     RECT  72.6 6.275 72.912 10.213 ;
     RECT  45.6 2.867 45.912 10.309 ;
     RECT  9.936 8.963 9.96 10.597 ;
     RECT  20.88 7.187 20.904 10.597 ;
     RECT  24 9.443 24.888 10.645 ;
     RECT  20.88 10.597 21.576 10.787 ;
     RECT  28.224 8.485 28.248 10.835 ;
     RECT  71.376 10.213 72.912 10.883 ;
     RECT  50.832 6.131 51.312 10.931 ;
     RECT  29.4 8.195 29.712 11.029 ;
     RECT  24 10.645 24.984 11.219 ;
     RECT  45.504 10.309 45.912 11.267 ;
     RECT  33.072 10.165 36.84 11.363 ;
     RECT  2.4 4.163 2.712 11.365 ;
     RECT  10.944 9.491 10.968 11.365 ;
     RECT  9.792 10.597 9.96 11.461 ;
     RECT  83.4 5.989 84.024 11.509 ;
     RECT  79.344 11.365 79.368 11.555 ;
     RECT  9.696 11.461 9.96 11.699 ;
     RECT  54.72 10.067 55.032 11.699 ;
     RECT  7.8 8.579 8.112 11.749 ;
     RECT  56.256 9.731 56.712 11.797 ;
     RECT  7.68 11.749 8.112 11.891 ;
     RECT  56.256 11.797 56.808 11.941 ;
     RECT  18.6 2.915 18.912 11.989 ;
     RECT  30.816 11.893 30.84 12.035 ;
     RECT  87.504 8.485 87.768 12.035 ;
     RECT  33.648 11.363 36.84 12.085 ;
     RECT  24 11.219 24.936 12.323 ;
     RECT  56.256 11.941 56.904 12.325 ;
     RECT  10.944 11.365 11.592 12.421 ;
     RECT  33.648 12.085 37.176 12.517 ;
     RECT  9.792 11.699 9.96 12.563 ;
     RECT  67.2 4.213 68.376 12.563 ;
     RECT  9.792 12.563 9.816 12.659 ;
     RECT  83.136 11.509 84.024 12.755 ;
     RECT  18.6 11.989 19.368 12.851 ;
     RECT  18.6 12.851 19.032 13.043 ;
     RECT  33.504 12.517 37.176 13.045 ;
     RECT  71.376 10.883 71.4 13.045 ;
     RECT  72.6 10.883 72.912 13.045 ;
     RECT  26.448 13.189 26.472 13.573 ;
     RECT  27.936 11.941 27.96 13.573 ;
     RECT  54.72 11.699 54.744 13.573 ;
     RECT  26.448 13.573 27.96 13.619 ;
     RECT  16.656 9.731 16.68 13.621 ;
     RECT  55.968 12.325 56.904 13.621 ;
     RECT  65.088 8.341 65.112 13.621 ;
     RECT  26.448 13.619 27.384 13.667 ;
     RECT  71.376 13.045 72.912 13.715 ;
     RECT  65.088 13.621 65.256 13.717 ;
     RECT  67.2 12.563 67.8 13.763 ;
     RECT  33.024 13.045 37.176 13.909 ;
     RECT  42.432 6.613 42.456 13.955 ;
     RECT  65.088 13.717 65.304 14.099 ;
     RECT  40.2 8.243 40.512 14.101 ;
     RECT  65.088 14.099 65.256 14.195 ;
     RECT  29.28 11.029 29.712 14.197 ;
     RECT  51 10.931 51.312 14.197 ;
     RECT  40.2 14.101 41.064 14.243 ;
     RECT  63.648 10.067 63.672 14.627 ;
     RECT  65.088 14.195 65.112 14.723 ;
     RECT  28.8 14.197 29.712 14.773 ;
     RECT  27.36 13.667 27.384 14.867 ;
     RECT  54.672 13.573 54.744 14.867 ;
     RECT  54.672 14.867 54.696 14.963 ;
     RECT  55.776 13.621 56.904 15.061 ;
     RECT  16.656 13.621 16.824 15.301 ;
     RECT  33.024 13.909 37.896 15.349 ;
     RECT  59.472 11.701 59.496 15.349 ;
     RECT  55.776 15.061 57 15.829 ;
     RECT  31.824 14.101 31.848 15.877 ;
     RECT  32.88 15.349 37.896 15.877 ;
     RECT  67.2 13.763 67.512 15.925 ;
     RECT  59.28 15.349 59.496 15.973 ;
     RECT  22.512 15.589 22.536 16.019 ;
     RECT  28.8 14.773 30.648 16.019 ;
     RECT  47.904 14.485 47.928 16.019 ;
     RECT  87.648 12.035 87.768 16.019 ;
     RECT  59.28 15.973 60.072 16.067 ;
     RECT  83.4 12.755 84.024 16.117 ;
     RECT  72.6 13.715 72.912 16.357 ;
     RECT  55.68 15.829 57 16.403 ;
     RECT  31.824 15.877 37.896 16.405 ;
     RECT  15.84 15.301 16.824 16.501 ;
     RECT  31.536 16.405 37.896 16.501 ;
     RECT  71.376 13.715 71.4 16.501 ;
     RECT  72.6 16.357 73.704 16.501 ;
     RECT  25.92 15.973 25.944 16.595 ;
     RECT  70.368 14.101 70.392 16.789 ;
     RECT  71.376 16.501 73.704 16.789 ;
     RECT  66.672 15.925 67.512 16.933 ;
     RECT  24 12.323 24.744 16.981 ;
     RECT  82.08 6.229 82.104 17.075 ;
     RECT  55.824 16.403 57 17.123 ;
     RECT  83.184 16.117 84.024 17.123 ;
     RECT  66.672 16.933 67.608 17.171 ;
     RECT  86.592 17.077 86.616 17.219 ;
     RECT  45.6 11.267 45.912 17.365 ;
     RECT  24 16.981 25.128 17.605 ;
     RECT  26.208 17.029 26.232 17.605 ;
     RECT  40.2 14.243 40.512 17.605 ;
     RECT  47.904 17.077 47.928 17.651 ;
     RECT  70.368 16.789 73.704 17.651 ;
     RECT  54.72 17.077 54.744 17.699 ;
     RECT  55.824 17.123 56.904 17.699 ;
     RECT  56.16 17.699 56.904 17.843 ;
     RECT  87.648 16.019 87.672 17.843 ;
     RECT  15.072 16.501 16.824 17.891 ;
     RECT  70.368 17.651 72.912 18.035 ;
     RECT  70.368 18.035 70.392 18.131 ;
     RECT  10.944 12.421 11.832 18.275 ;
     RECT  24 17.605 26.232 18.275 ;
     RECT  56.4 17.843 56.904 18.323 ;
     RECT  49.776 16.837 49.8 18.419 ;
     RECT  13.2 9.779 13.512 18.517 ;
     RECT  83.4 17.123 84.024 18.661 ;
     RECT  31.536 16.501 38.232 18.707 ;
     RECT  10.944 18.275 11.784 18.851 ;
     RECT  45.6 17.365 46.776 18.851 ;
     RECT  53.76 17.989 53.784 18.899 ;
     RECT  13.2 18.517 13.608 19.045 ;
     RECT  13.104 19.045 13.608 19.091 ;
     RECT  38.976 18.949 39 19.333 ;
     RECT  40.2 17.605 41.256 19.333 ;
     RECT  24 18.275 24.744 19.427 ;
     RECT  31.536 18.707 37.32 19.427 ;
     RECT  31.824 19.427 37.32 19.475 ;
     RECT  51 14.197 51.96 19.765 ;
     RECT  75.792 19.573 75.816 19.811 ;
     RECT  71.856 18.035 72.912 19.813 ;
     RECT  83.28 18.661 84.024 19.859 ;
     RECT  71.856 19.813 73.416 19.861 ;
     RECT  83.4 19.859 84.024 19.909 ;
     RECT  13.104 19.091 13.512 20.003 ;
     RECT  33.024 19.475 37.32 20.005 ;
     RECT  22.944 16.933 22.968 20.099 ;
     RECT  26.208 18.275 26.232 20.099 ;
     RECT  33.024 20.005 37.896 20.147 ;
     RECT  28.8 16.019 29.712 20.389 ;
     RECT  38.976 19.333 41.256 20.435 ;
     RECT  7.8 11.891 8.112 20.485 ;
     RECT  50.88 19.765 51.96 20.533 ;
     RECT  15.072 17.891 15.864 20.675 ;
     RECT  56.4 18.323 56.712 20.725 ;
     RECT  4.8 15.493 4.824 20.821 ;
     RECT  28.416 20.389 29.712 20.821 ;
     RECT  4.56 20.821 4.824 20.867 ;
     RECT  31.824 19.475 31.848 21.109 ;
     RECT  33.456 20.147 37.896 21.109 ;
     RECT  28.416 20.821 30.216 21.155 ;
     RECT  50.88 20.533 52.008 21.155 ;
     RECT  58.608 20.485 58.632 21.155 ;
     RECT  71.856 19.861 73.512 21.395 ;
     RECT  9.36 20.821 9.384 21.397 ;
     RECT  7.68 20.485 8.112 21.443 ;
     RECT  79.488 17.989 79.512 21.539 ;
     RECT  31.824 21.109 37.896 21.637 ;
     RECT  10.944 18.851 11.592 21.683 ;
     RECT  66.672 17.171 67.512 21.683 ;
     RECT  13.2 20.003 13.512 22.117 ;
     RECT  50.88 21.155 51.312 22.117 ;
     RECT  20.88 10.787 20.904 22.165 ;
     RECT  44.112 21.109 44.136 22.259 ;
     RECT  38.976 20.435 40.512 22.309 ;
     RECT  38.976 22.309 40.632 22.355 ;
     RECT  71.856 21.395 72.912 22.451 ;
     RECT  56.4 20.725 57.048 22.597 ;
     RECT  26.736 21.973 26.76 22.741 ;
     RECT  11.568 21.683 11.592 22.835 ;
     RECT  31.824 21.637 37.992 22.835 ;
     RECT  50.88 22.117 52.296 22.835 ;
     RECT  9.12 21.397 9.384 22.931 ;
     RECT  26.256 22.741 26.76 22.931 ;
     RECT  56.4 22.597 57.432 23.125 ;
     RECT  4.56 20.867 4.584 23.173 ;
     RECT  4.56 23.173 5.064 23.219 ;
     RECT  28.416 21.155 29.712 23.317 ;
     RECT  42.672 17.941 42.696 23.317 ;
     RECT  67.2 21.683 67.512 23.317 ;
     RECT  82.176 23.269 82.2 23.317 ;
     RECT  83.4 19.909 84.264 23.317 ;
     RECT  26.256 22.931 26.28 23.411 ;
     RECT  40.2 22.355 40.632 23.411 ;
     RECT  54.096 21.397 54.12 23.411 ;
     RECT  80.352 22.693 80.376 23.411 ;
     RECT  82.176 23.317 84.264 23.411 ;
     RECT  82.176 23.411 83.712 23.413 ;
     RECT  13.2 22.117 14.28 23.555 ;
     RECT  56.4 23.125 58.152 23.653 ;
     RECT  42.624 23.317 42.696 23.701 ;
     RECT  60.048 16.067 60.072 23.701 ;
     RECT  78 2.151 78.312 23.797 ;
     RECT  56.304 23.653 58.152 23.843 ;
     RECT  77.76 23.797 78.312 23.893 ;
     RECT  5.04 23.219 5.064 23.987 ;
     RECT  9.36 22.931 9.384 24.227 ;
     RECT  42.624 23.701 42.744 24.323 ;
     RECT  74.352 22.165 74.376 24.325 ;
     RECT  75.744 22.693 75.768 24.325 ;
     RECT  32.832 22.835 37.992 24.371 ;
     RECT  42.624 24.323 42.696 24.373 ;
     RECT  61.8 2.151 62.112 24.373 ;
     RECT  18.6 13.043 18.912 24.469 ;
     RECT  20.16 22.165 20.904 24.469 ;
     RECT  77.76 23.893 78.648 24.469 ;
     RECT  69.552 23.701 69.576 24.515 ;
     RECT  74.352 24.325 75.768 24.515 ;
     RECT  50.88 22.835 51.312 24.517 ;
     RECT  77.568 24.469 78.648 24.563 ;
     RECT  13.2 23.555 13.608 24.659 ;
     RECT  66.72 23.317 67.512 24.659 ;
     RECT  81.36 23.413 83.712 24.659 ;
     RECT  42.192 24.373 42.696 24.803 ;
     RECT  71.904 22.451 72.912 24.947 ;
     RECT  30.72 24.469 30.744 25.091 ;
     RECT  32.832 24.371 37.8 25.139 ;
     RECT  75.264 24.515 75.768 25.139 ;
     RECT  40.2 23.411 40.512 25.141 ;
     RECT  40.2 25.141 40.968 25.669 ;
     RECT  32.832 25.139 33.096 25.715 ;
     RECT  50.88 24.517 52.296 25.715 ;
     RECT  56.4 23.843 58.152 25.715 ;
     RECT  59.472 23.701 60.072 25.715 ;
     RECT  77.568 24.563 78.312 25.715 ;
     RECT  81.84 24.659 83.712 25.715 ;
     RECT  34.416 25.139 37.8 25.765 ;
     RECT  38.976 22.355 39 25.765 ;
     RECT  42.672 24.803 42.696 26.053 ;
     RECT  31.824 22.835 31.848 26.149 ;
     RECT  32.832 25.715 32.856 26.149 ;
     RECT  72.48 24.947 72.912 26.197 ;
     RECT  2.4 11.365 3.48 26.243 ;
     RECT  42.624 26.053 42.696 26.291 ;
     RECT  75.264 25.139 75.72 26.291 ;
     RECT  40.2 25.669 41.16 26.435 ;
     RECT  34.416 25.765 39 26.531 ;
     RECT  40.2 26.435 40.968 26.771 ;
     RECT  61.8 24.373 63.096 26.771 ;
     RECT  50.88 25.715 51.312 26.819 ;
     RECT  72.48 26.197 73.896 26.819 ;
     RECT  77.616 25.715 78.312 26.867 ;
     RECT  60.048 25.715 60.072 27.061 ;
     RECT  61.8 26.771 62.112 27.061 ;
     RECT  75.696 26.291 75.72 27.107 ;
     RECT  42.672 26.291 42.696 27.205 ;
     RECT  31.824 26.149 32.856 27.347 ;
     RECT  34.416 26.531 37.608 27.493 ;
     RECT  38.976 26.531 39 27.493 ;
     RECT  85.488 26.437 85.512 27.589 ;
     RECT  85.488 27.589 86.424 27.635 ;
     RECT  82.656 25.715 83.712 27.733 ;
     RECT  34.416 27.493 39 27.779 ;
     RECT  34.416 27.779 37.464 27.875 ;
     RECT  31.824 27.347 31.848 27.877 ;
     RECT  74.448 27.157 74.472 27.877 ;
     RECT  82.608 27.733 83.712 27.877 ;
     RECT  45.6 18.851 45.912 28.261 ;
     RECT  86.016 27.635 86.424 28.261 ;
     RECT  40.2 26.771 40.92 28.357 ;
     RECT  45.6 28.261 46.104 28.405 ;
     RECT  2.4 26.243 2.904 28.451 ;
     RECT  42.672 27.205 43.608 28.499 ;
     RECT  69.024 27.301 69.048 28.499 ;
     RECT  56.4 25.715 57.528 28.547 ;
     RECT  13.2 24.659 13.512 28.645 ;
     RECT  14.64 27.877 14.664 28.645 ;
     RECT  82.608 27.877 84.6 28.739 ;
     RECT  27.84 23.317 29.712 28.789 ;
     RECT  31.344 27.877 31.848 28.789 ;
     RECT  63.648 27.637 63.672 28.981 ;
     RECT  82.608 28.739 83.712 28.981 ;
     RECT  18.6 24.469 20.904 29.027 ;
     RECT  56.4 28.547 56.712 29.029 ;
     RECT  58.8 27.781 58.824 29.029 ;
     RECT  60.048 27.061 62.112 29.029 ;
     RECT  74.448 27.877 75.336 29.029 ;
     RECT  80.256 28.405 80.28 29.123 ;
     RECT  10.8 29.077 10.824 29.219 ;
     RECT  27.84 28.789 31.848 29.219 ;
     RECT  67.2 24.659 67.512 29.365 ;
     RECT  72.48 26.819 72.912 29.365 ;
     RECT  86.016 28.261 86.808 29.365 ;
     RECT  86.016 29.365 87.528 29.411 ;
     RECT  13.2 28.645 14.664 29.461 ;
     RECT  24 19.427 24.312 29.509 ;
     RECT  78 26.867 78.312 29.509 ;
     RECT  79.968 29.221 79.992 29.509 ;
     RECT  56.304 29.029 56.712 29.605 ;
     RECT  58.8 29.029 62.112 29.605 ;
     RECT  58.752 29.605 62.112 29.651 ;
     RECT  60.048 29.651 62.112 29.699 ;
     RECT  63.648 28.981 63.72 29.747 ;
     RECT  39.984 28.357 40.92 29.795 ;
     RECT  86.016 29.411 86.424 29.795 ;
     RECT  81.984 28.981 83.712 29.891 ;
     RECT  78 29.509 79.992 30.035 ;
     RECT  86.016 29.795 86.328 30.035 ;
     RECT  13.2 29.461 14.808 30.083 ;
     RECT  82.656 29.891 83.712 30.085 ;
     RECT  70.704 29.653 70.728 30.179 ;
     RECT  72.144 29.365 72.912 30.179 ;
     RECT  67.2 29.365 67.848 30.181 ;
     RECT  27.84 29.219 30.504 30.275 ;
     RECT  34.416 27.875 37.368 30.275 ;
     RECT  56.304 29.605 57 30.275 ;
     RECT  58.752 29.651 58.824 30.275 ;
     RECT  72.48 30.179 72.912 30.275 ;
     RECT  78 30.035 79.224 30.275 ;
     RECT  82.656 30.085 84.648 30.323 ;
     RECT  27.84 30.275 29.712 30.469 ;
     RECT  27.072 30.469 29.712 30.565 ;
     RECT  13.2 30.083 14.712 30.611 ;
     RECT  22.176 29.605 22.2 30.611 ;
     RECT  82.656 30.323 83.712 30.611 ;
     RECT  45.6 28.405 46.2 30.613 ;
     RECT  26.784 30.565 29.712 30.707 ;
     RECT  31.824 29.219 31.848 30.709 ;
     RECT  32.832 27.347 32.856 30.709 ;
     RECT  51 26.819 51.312 30.709 ;
     RECT  31.824 30.709 32.856 30.755 ;
     RECT  76.896 29.605 76.92 30.757 ;
     RECT  78 30.275 79.08 30.757 ;
     RECT  27.072 30.707 29.712 30.803 ;
     RECT  70.608 30.661 70.632 30.803 ;
     RECT  65.52 28.837 65.544 30.805 ;
     RECT  66.576 30.181 67.848 30.805 ;
     RECT  76.896 30.757 79.08 30.851 ;
     RECT  74.064 29.029 75.336 30.901 ;
     RECT  18.6 29.027 20.184 31.285 ;
     RECT  72.6 30.275 72.912 31.285 ;
     RECT  74.064 30.901 75.624 31.285 ;
     RECT  14.544 30.611 14.712 31.379 ;
     RECT  72.6 31.285 75.624 31.379 ;
     RECT  86.304 30.035 86.328 31.379 ;
     RECT  56.304 30.275 56.952 31.523 ;
     RECT  65.52 30.805 67.848 31.525 ;
     RECT  84.912 30.757 84.936 31.669 ;
     RECT  30.816 30.421 30.84 31.861 ;
     RECT  31.824 30.755 32.76 31.861 ;
     RECT  61.8 29.699 62.112 31.861 ;
     RECT  24 29.509 24.696 31.907 ;
     RECT  63.648 29.747 63.672 31.907 ;
     RECT  45.6 30.613 46.728 31.909 ;
     RECT  76.944 30.851 79.08 31.955 ;
     RECT  84.912 31.669 85.512 31.955 ;
     RECT  65.52 31.525 68.088 31.957 ;
     RECT  87.408 29.411 87.528 32.195 ;
     RECT  40.2 29.795 40.92 32.293 ;
     RECT  30.816 31.861 33.096 32.387 ;
     RECT  76.944 31.955 76.968 32.387 ;
     RECT  13.2 30.611 13.512 32.437 ;
     RECT  14.544 31.379 14.568 32.437 ;
     RECT  42.672 28.499 42.696 32.437 ;
     RECT  50.688 30.709 51.312 32.437 ;
     RECT  72.6 31.379 75.24 32.437 ;
     RECT  85.488 31.955 85.512 32.437 ;
     RECT  85.488 32.437 86.184 32.483 ;
     RECT  71.808 32.437 75.24 32.531 ;
     RECT  81.456 30.949 81.48 32.677 ;
     RECT  31.44 32.387 33.096 32.867 ;
     RECT  60.048 29.699 60.072 32.869 ;
     RECT  61.8 31.861 62.424 32.869 ;
     RECT  60.048 32.869 62.424 33.059 ;
     RECT  64.944 31.957 68.088 33.059 ;
     RECT  17.088 32.965 17.112 33.061 ;
     RECT  16.992 33.061 17.112 33.107 ;
     RECT  45.6 31.909 47.304 33.107 ;
     RECT  78 31.955 79.08 33.205 ;
     RECT  80.976 32.677 81.48 33.205 ;
     RECT  31.536 32.867 33.096 33.539 ;
     RECT  13.2 32.437 14.568 33.683 ;
     RECT  31.584 33.539 33.096 33.683 ;
     RECT  87.408 32.195 87.432 33.683 ;
     RECT  83.28 30.611 83.712 33.781 ;
     RECT  42.144 32.437 42.696 33.827 ;
     RECT  83.28 33.781 84.12 33.877 ;
     RECT  83.28 33.877 84.168 34.019 ;
     RECT  50.4 32.437 51.312 34.069 ;
     RECT  65.52 33.059 67.512 34.115 ;
     RECT  71.808 32.531 73.896 34.165 ;
     RECT  75.024 32.531 75.24 34.165 ;
     RECT  83.28 34.019 84.12 34.211 ;
     RECT  15.84 20.675 15.864 34.259 ;
     RECT  71.808 34.165 75.24 34.355 ;
     RECT  18.6 31.285 20.616 34.405 ;
     RECT  33.072 33.683 33.096 34.549 ;
     RECT  34.416 30.275 37.32 34.549 ;
     RECT  33.072 34.549 37.32 34.595 ;
     RECT  27.84 30.803 29.712 34.645 ;
     RECT  76.368 33.397 76.392 34.645 ;
     RECT  78 33.205 81.48 34.645 ;
     RECT  18.384 34.405 20.616 34.691 ;
     RECT  76.368 34.645 81.48 34.835 ;
     RECT  86.16 32.483 86.184 34.835 ;
     RECT  74.256 34.355 75.24 34.931 ;
     RECT  76.368 34.835 81 35.123 ;
     RECT  18.6 34.691 19.32 35.219 ;
     RECT  42.672 33.827 42.696 35.363 ;
     RECT  76.368 35.123 80.232 35.363 ;
     RECT  13.2 33.683 13.512 35.557 ;
     RECT  14.544 33.683 14.568 35.557 ;
     RECT  48.72 33.589 48.744 35.557 ;
     RECT  69.84 30.949 70.296 35.605 ;
     RECT  13.2 35.557 14.568 35.699 ;
     RECT  16.992 33.107 17.016 35.699 ;
     RECT  61.8 33.059 62.424 35.699 ;
     RECT  4.368 28.405 4.392 35.747 ;
     RECT  72.6 34.355 73.032 35.797 ;
     RECT  27.84 34.645 30.504 35.845 ;
     RECT  31.584 33.683 31.848 35.845 ;
     RECT  40.2 32.293 41.016 35.893 ;
     RECT  61.8 35.699 62.232 35.893 ;
     RECT  69.84 35.605 70.632 35.893 ;
     RECT  71.712 35.797 73.032 35.893 ;
     RECT  69.84 35.893 73.032 35.939 ;
     RECT  77.04 35.363 80.232 35.939 ;
     RECT  20.496 34.691 20.616 35.987 ;
     RECT  20.496 35.987 20.568 36.179 ;
     RECT  69.84 35.939 71.4 36.275 ;
     RECT  83.28 34.211 83.712 36.275 ;
     RECT  72.432 35.939 73.032 36.323 ;
     RECT  72.6 36.323 73.032 36.373 ;
     RECT  74.256 34.931 74.712 36.373 ;
     RECT  72.6 36.373 74.712 36.419 ;
     RECT  83.4 36.275 83.712 36.421 ;
     RECT  40.2 35.893 41.64 36.515 ;
     RECT  83.4 36.421 83.832 36.611 ;
     RECT  61.104 35.893 62.232 36.659 ;
     RECT  65.52 34.115 65.544 36.709 ;
     RECT  33.696 34.595 37.32 36.803 ;
     RECT  65.184 36.709 65.544 36.805 ;
     RECT  66.576 34.115 67.512 36.805 ;
     RECT  87.504 34.501 87.528 36.853 ;
     RECT  65.184 36.805 67.512 36.901 ;
     RECT  13.2 35.699 14.52 36.947 ;
     RECT  86.544 36.853 87.528 36.995 ;
     RECT  61.632 36.659 62.232 36.997 ;
     RECT  64.08 36.949 64.104 36.997 ;
     RECT  78 35.939 80.232 37.045 ;
     RECT  81.36 36.373 81.384 37.045 ;
     RECT  27.84 35.845 31.848 37.091 ;
     RECT  34.416 36.803 37.32 37.091 ;
     RECT  48.384 35.557 48.744 37.091 ;
     RECT  78 37.045 81.384 37.187 ;
     RECT  7.8 21.443 8.112 37.189 ;
     RECT  80.88 37.187 81.384 37.283 ;
     RECT  78 37.187 79.896 37.427 ;
     RECT  70.608 36.275 71.4 37.475 ;
     RECT  7.488 37.189 8.112 37.573 ;
     RECT  38.976 27.779 39 37.667 ;
     RECT  40.2 36.515 40.92 37.667 ;
     RECT  70.656 37.475 71.4 37.715 ;
     RECT  61.632 36.997 64.104 37.907 ;
     RECT  65.184 36.901 67.704 38.147 ;
     RECT  79.632 37.427 79.896 38.147 ;
     RECT  13.2 36.947 13.512 38.149 ;
     RECT  18.6 35.219 18.912 38.149 ;
     RECT  31.584 37.091 31.848 38.243 ;
     RECT  34.8 37.091 37.32 38.243 ;
     RECT  60.048 33.059 60.072 38.243 ;
     RECT  65.904 38.147 67.704 38.243 ;
     RECT  58.8 30.275 58.824 38.245 ;
     RECT  63.12 37.907 64.104 38.291 ;
     RECT  36.144 38.243 37.176 38.435 ;
     RECT  20.544 36.179 20.568 38.483 ;
     RECT  13.104 38.149 13.512 38.485 ;
     RECT  14.496 36.947 14.52 38.531 ;
     RECT  61.632 37.907 62.112 38.531 ;
     RECT  86.4 38.149 86.424 38.627 ;
     RECT  72.6 36.419 74.088 38.677 ;
     RECT  56.304 31.523 56.712 38.723 ;
     RECT  7.44 37.573 8.112 38.819 ;
     RECT  18.6 38.149 19.512 38.819 ;
     RECT  36.912 38.435 37.176 38.819 ;
     RECT  40.2 37.667 40.728 38.819 ;
     RECT  61.68 38.531 62.112 38.819 ;
     RECT  7.488 38.819 8.112 39.011 ;
     RECT  72.384 38.677 74.088 39.011 ;
     RECT  58.8 38.245 59.544 39.301 ;
     RECT  70.8 37.715 71.4 39.301 ;
     RECT  36.912 38.819 36.936 39.395 ;
     RECT  79.872 38.147 79.896 39.395 ;
     RECT  48.72 37.091 48.744 39.781 ;
     RECT  65.904 38.243 67.512 39.875 ;
     RECT  31.584 38.243 31.656 40.019 ;
     RECT  64.08 38.291 64.104 40.019 ;
     RECT  70.128 39.301 71.4 40.019 ;
     RECT  41.952 39.589 41.976 40.165 ;
     RECT  41.952 40.165 42.264 40.211 ;
     RECT  87.504 36.995 87.528 40.259 ;
     RECT  78 37.427 78.408 40.307 ;
     RECT  48.528 39.781 48.744 40.405 ;
     RECT  70.176 40.019 71.4 40.547 ;
     RECT  72.6 39.011 74.088 40.547 ;
     RECT  83.4 36.611 83.712 40.597 ;
     RECT  37.632 39.829 37.656 40.789 ;
     RECT  55.248 39.877 55.272 40.789 ;
     RECT  56.4 38.723 56.712 40.789 ;
     RECT  37.632 40.789 38.184 40.835 ;
     RECT  55.248 40.789 56.712 40.835 ;
     RECT  48.528 40.405 48.984 40.883 ;
     RECT  83.088 40.597 83.712 40.979 ;
     RECT  16.992 39.253 17.016 40.981 ;
     RECT  16.992 40.981 17.112 41.027 ;
     RECT  31.632 40.019 31.656 41.075 ;
     RECT  66.576 39.875 67.512 41.075 ;
     RECT  72.6 40.547 73.992 41.075 ;
     RECT  24 31.907 24.312 41.077 ;
     RECT  25.536 38.725 25.56 41.077 ;
     RECT  17.088 41.027 17.112 41.123 ;
     RECT  68.832 39.781 68.856 41.219 ;
     RECT  70.8 40.547 71.4 41.363 ;
     RECT  12.24 38.485 13.512 41.653 ;
     RECT  55.824 40.835 56.712 41.699 ;
     RECT  7.8 39.011 8.112 41.749 ;
     RECT  43.872 30.133 43.896 41.845 ;
     RECT  42.24 40.211 42.264 41.891 ;
     RECT  40.2 38.819 40.632 41.939 ;
     RECT  63.84 40.981 63.864 42.181 ;
     RECT  24 41.077 25.56 42.227 ;
     RECT  63.648 42.181 63.864 42.227 ;
     RECT  38.16 40.835 38.184 42.419 ;
     RECT  61.8 38.819 62.112 42.517 ;
     RECT  33.408 39.973 33.432 42.661 ;
     RECT  33.024 42.661 33.432 42.707 ;
     RECT  61.8 42.517 62.664 42.707 ;
     RECT  36.72 41.221 36.744 42.709 ;
     RECT  6.96 41.749 8.112 42.755 ;
     RECT  36.432 42.709 36.744 42.755 ;
     RECT  43.392 41.845 43.896 42.803 ;
     RECT  50.4 34.069 52.152 42.803 ;
     RECT  36.432 42.755 36.456 43.283 ;
     RECT  4.56 43.093 4.584 43.285 ;
     RECT  31.344 42.469 31.368 43.331 ;
     RECT  86.832 42.133 86.856 43.331 ;
     RECT  25.536 42.227 25.56 43.333 ;
     RECT  25.536 43.333 26.232 43.379 ;
     RECT  63.648 42.227 63.672 43.379 ;
     RECT  43.392 42.803 43.416 43.523 ;
     RECT  50.4 42.803 51.312 43.811 ;
     RECT  70.8 41.363 71.304 43.861 ;
     RECT  72.6 41.075 73.848 44.099 ;
     RECT  22.128 38.437 22.152 44.197 ;
     RECT  21.888 44.197 22.152 44.243 ;
     RECT  34.8 38.243 35.112 44.293 ;
     RECT  4.56 43.285 5.304 44.339 ;
     RECT  58.8 39.301 59.592 44.389 ;
     RECT  81.36 37.283 81.384 44.437 ;
     RECT  85.728 41.797 85.752 44.437 ;
     RECT  27.84 37.091 29.712 44.483 ;
     RECT  50.832 43.811 51.312 44.483 ;
     RECT  70.464 43.861 71.448 44.485 ;
     RECT  12.24 41.653 13.656 44.579 ;
     RECT  5.28 44.339 5.304 44.723 ;
     RECT  12.24 44.579 13.512 44.723 ;
     RECT  31.488 43.861 31.512 44.725 ;
     RECT  33.024 42.707 33.048 44.725 ;
     RECT  31.488 44.725 33.048 44.771 ;
     RECT  42.24 43.477 42.264 44.915 ;
     RECT  69.504 44.485 71.448 44.915 ;
     RECT  78 40.307 78.312 44.965 ;
     RECT  70.8 44.915 71.448 45.059 ;
     RECT  71.424 45.059 71.448 45.061 ;
     RECT  72.6 44.099 72.912 45.061 ;
     RECT  71.424 45.061 72.912 45.347 ;
     RECT  34.8 44.293 35.256 45.395 ;
     RECT  85.728 44.437 86.136 45.395 ;
     RECT  13.2 44.723 13.512 45.541 ;
     RECT  24 42.227 24.312 45.541 ;
     RECT  78 44.965 78.744 45.635 ;
     RECT  32.304 44.771 33.048 45.683 ;
     RECT  45.6 33.107 46.728 45.733 ;
     RECT  81.12 44.437 81.384 46.115 ;
     RECT  23.712 45.541 24.312 46.117 ;
     RECT  37.92 45.157 37.944 46.117 ;
     RECT  67.2 41.075 67.512 46.165 ;
     RECT  45.024 45.733 46.728 46.211 ;
     RECT  69.504 44.915 69.528 46.211 ;
     RECT  26.208 43.379 26.232 46.259 ;
     RECT  28.464 44.483 29.712 46.309 ;
     RECT  40.2 41.939 40.512 46.597 ;
     RECT  6.768 44.677 6.792 46.787 ;
     RECT  28.464 46.309 30.6 46.787 ;
     RECT  37.92 46.117 38.088 46.787 ;
     RECT  85.728 45.395 85.752 46.787 ;
     RECT  38.064 46.787 38.088 46.835 ;
     RECT  36.72 46.645 36.744 46.837 ;
     RECT  13.2 45.541 13.656 46.931 ;
     RECT  36.72 46.837 36.84 46.979 ;
     RECT  67.2 46.165 68.424 47.029 ;
     RECT  36.816 46.979 36.84 47.075 ;
     RECT  66.816 47.029 68.424 47.075 ;
     RECT  78 45.635 78.312 47.269 ;
     RECT  71.424 45.347 71.448 47.363 ;
     RECT  23.232 46.117 24.312 47.603 ;
     RECT  75.216 47.077 75.24 47.701 ;
     RECT  28.464 46.787 29.712 47.797 ;
     RECT  37.632 47.797 37.656 47.845 ;
     RECT  27.888 47.797 29.712 47.891 ;
     RECT  10.8 47.221 10.824 47.939 ;
     RECT  21.888 44.243 21.912 47.939 ;
     RECT  66.816 47.075 67.512 47.939 ;
     RECT  65.424 43.861 65.448 48.083 ;
     RECT  40.032 46.597 40.512 48.325 ;
     RECT  57.84 44.389 59.592 48.419 ;
     RECT  37.632 47.845 37.992 48.515 ;
     RECT  48.528 40.883 48.552 48.515 ;
     RECT  77.856 47.269 78.312 48.515 ;
     RECT  6.096 48.229 6.12 48.707 ;
     RECT  56.4 41.699 56.712 48.853 ;
     RECT  33.024 45.683 33.048 48.899 ;
     RECT  55.872 48.853 56.712 49.043 ;
     RECT  25.296 47.557 25.32 49.091 ;
     RECT  27.888 47.891 27.912 49.091 ;
     RECT  57.84 48.419 58.824 49.091 ;
     RECT  57.84 49.091 57.864 49.235 ;
     RECT  74.304 47.701 75.24 49.235 ;
     RECT  68.928 48.373 68.952 49.331 ;
     RECT  37.632 48.515 37.848 49.379 ;
     RECT  39.504 48.325 40.512 49.525 ;
     RECT  56.4 49.043 56.712 49.813 ;
     RECT  0.192 4.021 0.216 49.859 ;
     RECT  72.6 45.347 72.912 49.861 ;
     RECT  39.264 49.525 40.512 50.101 ;
     RECT  7.8 42.755 8.112 50.245 ;
     RECT  22.992 48.949 23.016 50.629 ;
     RECT  24 47.603 24.312 50.629 ;
     RECT  49.872 50.149 49.896 50.723 ;
     RECT  61.8 42.707 62.112 50.725 ;
     RECT  69.84 49.525 69.864 50.771 ;
     RECT  74.448 49.235 75.24 50.771 ;
     RECT  85.824 49.525 85.848 50.771 ;
     RECT  48.624 50.677 48.648 50.819 ;
     RECT  58.128 50.149 58.152 50.819 ;
     RECT  67.2 47.939 67.512 50.821 ;
     RECT  2.4 28.451 2.712 50.917 ;
     RECT  39.264 50.101 40.968 50.963 ;
     RECT  37.632 49.379 37.656 51.011 ;
     RECT  39.264 50.963 40.512 51.107 ;
     RECT  71.952 49.861 72.912 51.109 ;
     RECT  2.4 50.917 2.808 51.205 ;
     RECT  33.696 50.101 33.72 51.299 ;
     RECT  61.296 50.725 62.112 51.299 ;
     RECT  65.568 50.725 65.592 51.299 ;
     RECT  74.448 50.771 74.52 51.347 ;
     RECT  21.648 50.965 21.672 51.635 ;
     RECT  29.4 47.891 29.712 51.733 ;
     RECT  54.912 50.677 54.936 51.781 ;
     RECT  56.4 49.813 56.808 51.781 ;
     RECT  74.496 51.347 74.52 51.923 ;
     RECT  85.776 51.253 85.8 52.211 ;
     RECT  67.2 50.821 67.608 52.213 ;
     RECT  81.36 46.115 81.384 52.357 ;
     RECT  74.592 52.261 74.616 52.403 ;
     RECT  34.8 45.395 35.112 52.405 ;
     RECT  7.8 50.245 8.232 52.451 ;
     RECT  71.712 51.109 72.912 52.453 ;
     RECT  2.4 51.205 3.576 52.549 ;
     RECT  71.52 52.453 72.912 52.595 ;
     RECT  67.2 52.213 67.896 52.837 ;
     RECT  2.4 52.549 3.864 52.981 ;
     RECT  18.6 38.819 18.912 52.981 ;
     RECT  70.704 52.933 70.728 52.981 ;
     RECT  81.36 52.357 82.2 52.981 ;
     RECT  83.4 40.979 83.712 52.981 ;
     RECT  54.912 51.781 56.808 53.219 ;
     RECT  22.992 50.629 24.312 53.363 ;
     RECT  2.304 52.981 3.864 53.365 ;
     RECT  55.824 53.219 56.808 53.557 ;
     RECT  63.168 51.781 63.192 53.557 ;
     RECT  20.592 51.781 20.616 53.941 ;
     RECT  31.296 53.029 31.32 54.085 ;
     RECT  67.2 52.837 68.376 54.085 ;
     RECT  69.744 52.981 70.728 54.085 ;
     RECT  55.824 53.557 57.576 54.179 ;
     RECT  29.4 51.733 30.168 54.373 ;
     RECT  28.848 54.373 30.168 54.419 ;
     RECT  43.92 50.965 43.944 54.563 ;
     RECT  31.296 54.085 32.136 54.611 ;
     RECT  76.944 52.837 76.968 54.613 ;
     RECT  78 48.515 78.312 54.613 ;
     RECT  76.944 54.613 78.312 54.659 ;
     RECT  34.8 52.405 35.352 54.661 ;
     RECT  67.2 54.085 70.728 54.755 ;
     RECT  67.2 54.755 67.992 54.803 ;
     RECT  85.728 54.709 85.752 54.853 ;
     RECT  18.6 52.981 19.416 54.899 ;
     RECT  85.728 54.853 85.8 54.995 ;
     RECT  20.592 53.941 21.144 55.187 ;
     RECT  56.4 54.179 57.576 55.283 ;
     RECT  63.12 53.557 63.192 55.331 ;
     RECT  61.8 51.299 62.112 55.477 ;
     RECT  79.872 53.461 79.896 55.573 ;
     RECT  77.472 54.659 78.312 55.619 ;
     RECT  63.168 55.331 63.192 55.667 ;
     RECT  85.776 54.995 85.8 55.667 ;
     RECT  67.2 54.803 67.704 55.715 ;
     RECT  28.848 54.419 30.024 55.813 ;
     RECT  67.2 55.715 67.512 55.813 ;
     RECT  32.112 54.611 32.136 55.907 ;
     RECT  28.848 55.813 30.264 56.101 ;
     RECT  37.248 53.797 37.272 56.245 ;
     RECT  34.8 54.661 35.592 56.291 ;
     RECT  56.4 55.283 56.808 56.341 ;
     RECT  6.624 52.405 6.648 56.389 ;
     RECT  23.328 53.363 24.312 56.483 ;
     RECT  5.712 56.389 6.648 56.531 ;
     RECT  28.848 56.101 30.36 56.531 ;
     RECT  6.624 56.531 6.648 56.579 ;
     RECT  2.304 53.365 3.912 56.627 ;
     RECT  58.992 54.085 59.016 56.723 ;
     RECT  56.4 56.341 57.576 57.011 ;
     RECT  37.056 56.245 37.272 57.059 ;
     RECT  79.632 55.573 79.896 57.059 ;
     RECT  28.896 56.531 30.36 57.445 ;
     RECT  61.536 55.477 62.112 57.445 ;
     RECT  61.536 57.445 62.232 57.491 ;
     RECT  69.744 54.755 69.912 57.587 ;
     RECT  72.48 52.595 72.912 57.635 ;
     RECT  16.56 57.589 16.584 57.731 ;
     RECT  18.6 54.899 18.912 58.117 ;
     RECT  51 44.483 51.312 58.117 ;
     RECT  56.4 57.011 56.808 58.117 ;
     RECT  28.896 57.445 30.936 58.163 ;
     RECT  2.4 56.627 3.912 58.645 ;
     RECT  66.672 55.813 67.512 58.691 ;
     RECT  37.248 57.059 37.272 58.693 ;
     RECT  44.112 58.021 44.136 58.693 ;
     RECT  50.88 58.117 51.312 58.693 ;
     RECT  37.152 58.693 37.272 58.739 ;
     RECT  43.92 58.693 44.136 58.739 ;
     RECT  2.4 58.645 4.296 58.835 ;
     RECT  76.992 57.157 77.016 58.979 ;
     RECT  43.92 58.739 43.944 59.027 ;
     RECT  56.4 58.117 57.576 59.173 ;
     RECT  56.064 59.173 57.576 59.219 ;
     RECT  3.84 58.835 4.296 59.459 ;
     RECT  50.784 58.693 51.312 59.555 ;
     RECT  34.8 56.291 35.112 59.797 ;
     RECT  11.088 52.405 11.112 59.891 ;
     RECT  29.4 58.163 30.936 59.891 ;
     RECT  37.152 58.739 37.176 60.181 ;
     RECT  40.2 51.107 40.512 60.181 ;
     RECT  41.52 52.261 41.544 60.181 ;
     RECT  40.2 60.181 41.544 60.227 ;
     RECT  56.064 59.219 56.808 60.275 ;
     RECT  76.8 59.269 76.824 60.275 ;
     RECT  18.6 58.117 19.368 60.277 ;
     RECT  20.592 55.187 20.616 60.277 ;
     RECT  45.6 46.211 46.728 60.277 ;
     RECT  24 56.483 24.312 60.373 ;
     RECT  69.744 57.587 69.768 60.373 ;
     RECT  34.8 59.797 35.208 60.419 ;
     RECT  18.6 60.277 20.616 60.467 ;
     RECT  29.4 59.891 30.36 60.467 ;
     RECT  13.2 46.931 13.512 60.709 ;
     RECT  75.264 60.517 75.288 60.853 ;
     RECT  61.8 57.491 62.232 60.901 ;
     RECT  6.576 59.797 6.6 60.949 ;
     RECT  37.152 60.181 37.272 60.949 ;
     RECT  79.872 57.059 79.896 60.949 ;
     RECT  37.152 60.949 37.368 60.997 ;
     RECT  3.84 59.459 3.912 61.043 ;
     RECT  19.92 60.467 20.616 61.043 ;
     RECT  81.36 52.981 83.712 61.043 ;
     RECT  59.232 60.613 59.256 61.045 ;
     RECT  17.328 58.501 17.352 61.091 ;
     RECT  74.688 60.853 75.288 61.093 ;
     RECT  74.688 61.093 75.768 61.139 ;
     RECT  13.2 60.709 14.04 61.235 ;
     RECT  37.008 60.997 37.368 61.331 ;
     RECT  69.744 60.373 70.584 61.379 ;
     RECT  50.88 59.555 51.312 61.427 ;
     RECT  79.872 60.949 80.376 61.429 ;
     RECT  79.824 61.429 80.376 61.475 ;
     RECT  74.688 61.139 74.712 61.619 ;
     RECT  3.84 61.043 3.864 61.667 ;
     RECT  6.576 60.949 6.696 61.667 ;
     RECT  29.4 60.467 29.712 61.669 ;
     RECT  37.152 61.331 37.368 61.715 ;
     RECT  6.576 61.667 6.6 61.717 ;
     RECT  6.288 61.717 6.6 61.763 ;
     RECT  29.4 61.669 30.648 61.811 ;
     RECT  11.952 60.565 11.976 61.859 ;
     RECT  9.888 60.133 9.912 62.195 ;
     RECT  42.624 52.981 42.648 62.195 ;
     RECT  27.792 61.765 27.816 62.243 ;
     RECT  30.816 61.909 30.84 62.291 ;
     RECT  75.744 61.139 75.768 62.435 ;
     RECT  43.968 61.765 43.992 62.579 ;
     RECT  81.36 61.043 82.2 62.675 ;
     RECT  30.864 62.581 30.888 63.013 ;
     RECT  31.872 61.525 31.896 63.013 ;
     RECT  13.2 61.235 13.512 63.061 ;
     RECT  30.864 63.013 31.896 63.157 ;
     RECT  79.824 61.475 79.848 63.203 ;
     RECT  14.832 62.677 14.856 63.205 ;
     RECT  16.032 61.765 16.056 63.205 ;
     RECT  13.104 63.061 13.512 63.251 ;
     RECT  69.744 61.379 69.768 63.299 ;
     RECT  81.36 62.675 81.48 63.299 ;
     RECT  45.6 60.277 47.352 63.779 ;
     RECT  13.2 63.251 13.512 63.781 ;
     RECT  14.832 63.205 16.056 63.781 ;
     RECT  22.8 60.901 22.824 63.781 ;
     RECT  24 60.373 24.504 63.781 ;
     RECT  72.6 57.635 72.912 63.781 ;
     RECT  74.592 63.157 74.616 63.781 ;
     RECT  61.8 60.901 62.472 63.829 ;
     RECT  40.2 60.227 41.304 63.923 ;
     RECT  18.6 60.467 18.912 63.973 ;
     RECT  20.592 61.043 20.616 63.973 ;
     RECT  13.2 63.781 16.056 64.019 ;
     RECT  72.384 63.781 74.616 64.067 ;
     RECT  59.232 61.045 59.832 64.259 ;
     RECT  42.48 62.533 42.504 64.261 ;
     RECT  42.48 64.261 42.648 64.307 ;
     RECT  29.4 61.811 29.712 64.309 ;
     RECT  30.864 63.157 32.52 64.309 ;
     RECT  81.456 63.299 81.48 64.403 ;
     RECT  4.368 63.205 4.392 64.595 ;
     RECT  13.2 64.019 15.144 64.595 ;
     RECT  56.4 60.275 56.808 64.691 ;
     RECT  71.088 64.357 71.112 64.693 ;
     RECT  72.384 64.067 73.752 64.693 ;
     RECT  37.248 61.715 37.368 64.885 ;
     RECT  18.6 63.973 20.616 64.933 ;
     RECT  67.2 58.691 67.512 64.933 ;
     RECT  29.4 64.309 32.52 64.979 ;
     RECT  15.12 64.595 15.144 65.027 ;
     RECT  37.248 64.885 38.328 65.027 ;
     RECT  42.624 64.307 42.648 65.027 ;
     RECT  53.664 64.501 53.688 65.027 ;
     RECT  40.2 63.923 40.68 65.317 ;
     RECT  37.248 65.027 37.608 65.603 ;
     RECT  40.2 65.317 40.776 65.701 ;
     RECT  39.024 65.701 39.048 65.891 ;
     RECT  13.2 64.595 13.512 66.085 ;
     RECT  18.6 64.933 20.808 66.131 ;
     RECT  71.088 64.693 73.752 66.179 ;
     RECT  85.248 63.781 85.272 66.179 ;
     RECT  22.8 63.781 24.504 66.227 ;
     RECT  75.792 63.781 75.816 66.227 ;
     RECT  18.6 66.131 20.76 66.275 ;
     RECT  79.776 66.229 79.8 66.371 ;
     RECT  29.4 64.979 30.888 66.565 ;
     RECT  18.6 66.275 19.56 66.611 ;
     RECT  40.2 65.701 41.064 66.659 ;
     RECT  59.232 64.259 59.256 66.661 ;
     RECT  13.2 66.085 14.28 66.755 ;
     RECT  67.2 64.933 68.088 66.755 ;
     RECT  37.248 65.603 37.272 67.043 ;
     RECT  18.6 66.611 18.912 67.189 ;
     RECT  51 61.427 51.312 67.189 ;
     RECT  29.088 66.565 30.888 67.283 ;
     RECT  59.232 66.661 59.64 67.283 ;
     RECT  20.688 66.275 20.76 67.331 ;
     RECT  23.328 66.227 24.504 67.331 ;
     RECT  65.568 66.085 65.592 67.331 ;
     RECT  24 67.331 24.504 67.427 ;
     RECT  16.224 66.325 16.248 67.429 ;
     RECT  40.2 66.659 41.016 67.523 ;
     RECT  15.696 67.429 16.248 67.571 ;
     RECT  2.4 58.835 2.712 67.669 ;
     RECT  32.448 64.979 32.52 67.669 ;
     RECT  83.28 61.043 83.712 67.669 ;
     RECT  18.48 67.189 18.912 67.717 ;
     RECT  20.688 67.331 20.712 67.763 ;
     RECT  7.8 52.451 8.112 67.765 ;
     RECT  71.424 66.179 73.752 67.765 ;
     RECT  27.168 66.661 27.192 67.859 ;
     RECT  29.4 67.283 30.888 67.907 ;
     RECT  24 67.427 24.456 68.003 ;
     RECT  2.4 67.669 3.192 68.243 ;
     RECT  18.48 67.717 19.656 68.243 ;
     RECT  31.92 67.669 32.52 68.291 ;
     RECT  42.192 66.613 42.216 68.291 ;
     RECT  50.544 67.189 51.312 68.435 ;
     RECT  21.888 67.285 21.912 68.675 ;
     RECT  4.704 67.765 4.728 68.867 ;
     RECT  13.2 66.755 13.512 68.869 ;
     RECT  50.88 68.435 51.312 68.963 ;
     RECT  31.92 68.291 31.944 69.011 ;
     RECT  71.28 67.765 73.752 69.011 ;
     RECT  85.92 67.669 85.944 69.011 ;
     RECT  15.696 67.571 15.816 69.013 ;
     RECT  82.656 67.669 83.712 69.059 ;
     RECT  71.472 69.011 73.752 69.203 ;
     RECT  13.2 68.869 13.704 69.251 ;
     RECT  71.472 69.203 71.496 69.491 ;
     RECT  15.696 69.013 15.864 69.587 ;
     RECT  60.432 67.333 60.456 69.587 ;
     RECT  7.488 67.765 8.112 69.683 ;
     RECT  12 68.965 12.024 69.685 ;
     RECT  6.288 61.763 6.312 69.731 ;
     RECT  61.8 63.829 62.664 69.971 ;
     RECT  34.8 60.419 35.112 70.069 ;
     RECT  68.976 69.733 69 70.307 ;
     RECT  43.776 68.245 43.8 70.451 ;
     RECT  28.224 69.493 28.248 70.547 ;
     RECT  2.4 68.243 2.712 70.549 ;
     RECT  56.4 64.691 56.712 70.549 ;
     RECT  15.696 69.587 15.816 70.645 ;
     RECT  40.2 67.523 40.512 70.645 ;
     RECT  45.6 63.779 46.728 70.645 ;
     RECT  11.712 69.685 12.024 70.739 ;
     RECT  44.976 70.645 46.728 70.789 ;
     RECT  82.32 70.645 82.344 70.789 ;
     RECT  83.4 69.059 83.712 70.789 ;
     RECT  61.8 69.971 62.328 70.835 ;
     RECT  82.032 70.789 82.344 70.835 ;
     RECT  85.872 70.021 85.896 70.835 ;
     RECT  48 64.597 48.024 70.885 ;
     RECT  48 70.885 48.456 70.931 ;
     RECT  44.976 70.789 46.776 71.075 ;
     RECT  22.416 70.309 22.44 71.077 ;
     RECT  24 68.003 24.312 71.077 ;
     RECT  38.736 69.301 38.76 71.123 ;
     RECT  41.616 70.021 41.64 71.123 ;
     RECT  44.976 71.075 46.248 71.123 ;
     RECT  29.4 67.907 29.712 71.221 ;
     RECT  30.864 67.907 30.888 71.221 ;
     RECT  39.936 70.645 40.512 71.315 ;
     RECT  63.984 69.301 64.008 71.315 ;
     RECT  82.032 70.835 82.056 71.315 ;
     RECT  2.4 70.549 3.384 71.363 ;
     RECT  18.6 68.243 19.656 71.603 ;
     RECT  48.432 70.931 48.456 71.603 ;
     RECT  22.416 71.077 24.312 71.651 ;
     RECT  54.144 70.933 54.168 71.843 ;
     RECT  83.4 70.789 84.6 71.843 ;
     RECT  15.696 70.645 16.392 71.891 ;
     RECT  56.16 70.549 56.712 71.939 ;
     RECT  72.6 69.203 73.752 71.989 ;
     RECT  11.712 70.739 11.736 72.179 ;
     RECT  2.4 71.363 2.904 72.467 ;
     RECT  61.8 70.835 62.112 72.565 ;
     RECT  45.6 71.123 46.248 72.659 ;
     RECT  15.792 71.891 16.392 72.707 ;
     RECT  28.272 70.837 28.296 72.851 ;
     RECT  29.4 71.221 30.888 73.091 ;
     RECT  34.8 70.069 35.208 73.381 ;
     RECT  30.864 73.091 30.888 73.477 ;
     RECT  23.376 71.651 24.312 73.525 ;
     RECT  61.8 72.565 63.048 73.525 ;
     RECT  18.6 71.603 19.608 73.571 ;
     RECT  23.376 73.525 24.552 73.571 ;
     RECT  51 68.963 51.312 73.909 ;
     RECT  30.864 73.477 31.416 74.147 ;
     RECT  18.6 73.571 18.912 74.389 ;
     RECT  48.096 73.525 48.12 74.579 ;
     RECT  61.584 73.525 63.048 74.579 ;
     RECT  81.504 73.765 81.528 74.579 ;
     RECT  72.6 71.989 74.088 74.581 ;
     RECT  56.4 71.939 56.712 74.629 ;
     RECT  34.8 73.381 35.88 74.723 ;
     RECT  70.56 72.085 70.584 74.723 ;
     RECT  20.544 74.629 20.568 74.867 ;
     RECT  24 73.571 24.552 74.915 ;
     RECT  15.792 72.707 16.056 74.963 ;
     RECT  27.792 74.197 27.816 75.109 ;
     RECT  30.864 74.147 31.032 75.109 ;
     RECT  11.28 73.477 11.304 75.155 ;
     RECT  40.2 71.315 40.512 75.157 ;
     RECT  45.6 72.659 45.912 75.253 ;
     RECT  59.232 67.283 59.256 75.253 ;
     RECT  42.72 75.205 42.744 75.397 ;
     RECT  56.304 74.629 56.712 75.397 ;
     RECT  42.384 75.397 42.744 75.443 ;
     RECT  56.304 75.397 58.152 75.443 ;
     RECT  72.6 74.581 74.712 75.589 ;
     RECT  27.744 75.109 27.816 75.683 ;
     RECT  2.4 72.467 2.712 75.781 ;
     RECT  61.8 74.579 63.048 75.781 ;
     RECT  15.792 74.963 15.912 75.827 ;
     RECT  40.2 75.157 41.064 75.827 ;
     RECT  61.68 75.781 63.048 75.875 ;
     RECT  72.6 75.589 75.048 75.875 ;
     RECT  67.2 66.755 67.512 75.925 ;
     RECT  17.328 75.109 17.352 75.971 ;
     RECT  56.4 75.443 58.152 75.971 ;
     RECT  59.232 75.253 59.496 75.971 ;
     RECT  22.224 74.629 22.248 76.211 ;
     RECT  45.6 75.253 46.632 76.259 ;
     RECT  24 74.915 24.312 76.357 ;
     RECT  66.384 75.925 67.512 76.451 ;
     RECT  40.2 75.827 40.512 76.549 ;
     RECT  34.8 74.723 35.832 76.739 ;
     RECT  64.224 75.781 64.248 76.739 ;
     RECT  49.248 76.597 49.272 76.883 ;
     RECT  48 76.069 48.024 76.885 ;
     RECT  72.6 75.875 73.752 76.885 ;
     RECT  29.4 73.091 29.712 76.933 ;
     RECT  12 76.117 12.024 76.979 ;
     RECT  2.4 75.781 2.808 77.075 ;
     RECT  7.8 69.683 8.112 77.365 ;
     RECT  9.696 75.109 9.72 77.411 ;
     RECT  61.68 75.875 62.112 77.413 ;
     RECT  24 76.357 25.08 77.555 ;
     RECT  33.6 77.077 33.624 77.555 ;
     RECT  42.384 75.443 42.408 77.555 ;
     RECT  13.2 69.251 13.512 77.557 ;
     RECT  14.544 76.309 14.568 77.557 ;
     RECT  39.312 76.549 40.512 77.603 ;
     RECT  72.048 76.885 73.752 77.987 ;
     RECT  75.024 75.875 75.048 78.085 ;
     RECT  69.552 77.461 69.576 78.131 ;
     RECT  30.864 75.109 31.32 78.181 ;
     RECT  13.2 77.557 14.568 78.227 ;
     RECT  27.744 75.683 27.768 78.277 ;
     RECT  29.136 76.933 29.712 78.277 ;
     RECT  27.744 78.277 29.712 78.419 ;
     RECT  47.472 76.885 48.024 78.469 ;
     RECT  61.584 77.413 62.112 78.613 ;
     RECT  5.808 77.461 5.976 78.659 ;
     RECT  7.68 77.365 8.112 78.659 ;
     RECT  42.768 78.085 42.792 78.659 ;
     RECT  47.472 78.469 48.408 78.707 ;
     RECT  24 77.555 24.312 79.189 ;
     RECT  26.016 78.373 26.04 79.189 ;
     RECT  24 79.189 26.04 79.235 ;
     RECT  72.6 77.987 73.752 79.283 ;
     RECT  61.584 78.613 62.904 79.331 ;
     RECT  75.024 78.085 75.816 79.475 ;
     RECT  56.4 75.971 57.864 79.525 ;
     RECT  51 73.909 51.864 79.571 ;
     RECT  34.8 76.739 35.112 79.621 ;
     RECT  5.952 78.659 5.976 79.717 ;
     RECT  9.696 78.373 9.72 79.717 ;
     RECT  47.472 78.707 48.168 79.811 ;
     RECT  72.6 79.283 73.032 79.811 ;
     RECT  37.68 75.541 37.704 79.813 ;
     RECT  27.744 78.419 27.768 79.859 ;
     RECT  75.024 79.475 75.048 79.955 ;
     RECT  56.4 79.525 57.96 80.051 ;
     RECT  2.4 77.075 2.712 80.053 ;
     RECT  37.056 79.813 37.704 80.147 ;
     RECT  13.2 78.227 14.328 80.149 ;
     RECT  15.792 75.827 15.816 80.149 ;
     RECT  61.8 79.331 62.904 80.291 ;
     RECT  30.864 78.181 31.8 80.293 ;
     RECT  72.6 79.811 72.912 80.341 ;
     RECT  34.656 79.621 35.112 80.387 ;
     RECT  13.2 80.149 15.816 80.435 ;
     RECT  30.864 80.293 31.992 80.531 ;
     RECT  7.8 78.659 8.112 80.629 ;
     RECT  29.4 78.419 29.712 80.677 ;
     RECT  30.864 80.531 30.888 80.677 ;
     RECT  13.2 80.435 15.144 80.723 ;
     RECT  9.696 79.717 10.248 80.771 ;
     RECT  34.8 80.387 35.112 80.917 ;
     RECT  44.304 80.245 44.328 80.917 ;
     RECT  45.6 76.259 45.912 80.917 ;
     RECT  7.8 80.629 8.568 81.059 ;
     RECT  22.608 77.893 22.632 81.205 ;
     RECT  22.272 81.205 22.632 81.251 ;
     RECT  37.68 80.147 37.704 81.445 ;
     RECT  44.304 80.917 45.912 81.491 ;
     RECT  5.664 79.717 5.976 81.539 ;
     RECT  31.968 80.531 31.992 81.539 ;
     RECT  47.472 79.811 47.592 81.539 ;
     RECT  71.808 80.341 72.912 81.683 ;
     RECT  65.28 80.389 65.304 81.731 ;
     RECT  7.8 81.059 8.112 81.925 ;
     RECT  74.976 80.341 75 82.021 ;
     RECT  2.4 80.053 3.192 82.069 ;
     RECT  10.224 80.771 10.248 82.115 ;
     RECT  72.6 81.683 72.912 82.309 ;
     RECT  74.976 82.021 75.912 82.403 ;
     RECT  34.8 80.917 35.496 82.405 ;
     RECT  13.2 80.723 14.328 82.451 ;
     RECT  22.272 81.251 22.296 82.451 ;
     RECT  37.632 81.445 37.704 82.451 ;
     RECT  18.48 74.389 18.912 82.499 ;
     RECT  67.2 76.451 67.512 82.501 ;
     RECT  40.2 77.603 40.512 82.597 ;
     RECT  72.6 82.309 73.368 82.597 ;
     RECT  49.68 81.445 49.704 82.691 ;
     RECT  56.4 80.051 57.864 82.691 ;
     RECT  32.448 82.021 32.472 82.739 ;
     RECT  44.304 81.491 44.328 82.789 ;
     RECT  45.6 81.491 45.912 82.789 ;
     RECT  75.792 82.403 75.912 82.931 ;
     RECT  28.368 82.837 28.392 82.979 ;
     RECT  34.8 82.405 35.544 82.981 ;
     RECT  37.632 82.451 37.656 82.981 ;
     RECT  7.68 81.925 8.112 83.027 ;
     RECT  59.232 75.971 59.256 83.173 ;
     RECT  2.4 82.069 3.72 83.219 ;
     RECT  58.704 83.173 59.256 83.219 ;
     RECT  37.392 82.981 37.656 83.267 ;
     RECT  72.6 82.597 74.088 83.317 ;
     RECT  72.288 83.317 74.088 83.363 ;
     RECT  24 79.235 25.08 83.459 ;
     RECT  66.672 82.501 67.512 83.459 ;
     RECT  52.944 82.645 52.968 83.795 ;
     RECT  58.704 83.219 58.728 83.795 ;
     RECT  44.304 82.789 45.912 83.843 ;
     RECT  69.312 78.421 69.336 83.843 ;
     RECT  75.888 82.931 75.912 83.843 ;
     RECT  5.376 81.733 5.4 84.035 ;
     RECT  37.392 83.267 37.416 84.035 ;
     RECT  44.304 83.843 44.328 84.035 ;
     RECT  12.096 83.989 12.12 84.037 ;
     RECT  13.2 82.451 13.512 84.037 ;
     RECT  39.792 82.597 40.512 84.323 ;
     RECT  42 82.549 42.024 84.323 ;
     RECT  45.6 83.843 45.912 84.325 ;
     RECT  29.4 80.677 30.888 84.373 ;
     RECT  18.6 82.499 18.912 84.421 ;
     RECT  29.4 84.373 30.984 84.515 ;
     RECT  34.8 82.981 35.688 84.517 ;
     RECT  30.72 84.515 30.984 84.611 ;
     RECT  76.896 82.885 76.92 84.611 ;
     RECT  47.568 81.539 47.592 84.709 ;
     RECT  72.288 83.363 72.912 84.757 ;
     RECT  74.064 83.363 74.088 84.757 ;
     RECT  72.288 84.757 74.088 84.803 ;
     RECT  21.36 82.981 21.384 84.851 ;
     RECT  12.096 84.037 13.608 84.947 ;
     RECT  32.544 84.325 32.568 85.139 ;
     RECT  63.6 84.805 63.624 85.235 ;
     RECT  59.808 85.189 59.832 85.285 ;
     RECT  59.472 85.285 59.832 85.331 ;
     RECT  15.984 82.405 16.008 85.477 ;
     RECT  24 83.459 24.984 85.477 ;
     RECT  15.36 85.477 16.008 85.523 ;
     RECT  23.712 85.477 24.984 85.765 ;
     RECT  30.72 84.611 30.84 85.957 ;
     RECT  23.712 85.765 25.176 86.005 ;
     RECT  34.8 84.517 35.88 86.005 ;
     RECT  40.2 84.323 40.512 86.005 ;
     RECT  30.72 85.957 31.32 86.099 ;
     RECT  39.024 85.621 39.048 86.195 ;
     RECT  33.84 86.005 35.88 86.197 ;
     RECT  78 55.619 78.312 86.581 ;
     RECT  87.744 77.989 87.768 86.675 ;
     RECT  53.568 85.477 53.592 86.723 ;
     RECT  13.056 84.947 13.608 86.771 ;
     RECT  7.8 83.027 8.112 86.965 ;
     RECT  65.232 85.957 65.256 87.011 ;
     RECT  7.68 86.965 8.112 87.107 ;
     RECT  31.296 86.099 31.32 87.157 ;
     RECT  40.08 86.005 40.512 87.157 ;
     RECT  17.952 84.421 18.912 87.251 ;
     RECT  69.36 84.277 69.384 87.251 ;
     RECT  30.912 87.157 31.32 87.347 ;
     RECT  72.288 84.803 73.608 87.541 ;
     RECT  32.88 86.197 35.88 87.587 ;
     RECT  23.712 86.005 25.272 87.589 ;
     RECT  34.8 87.587 35.88 87.637 ;
     RECT  11.52 87.541 11.544 87.683 ;
     RECT  13.056 86.771 13.512 87.779 ;
     RECT  80.304 84.901 80.328 87.779 ;
     RECT  39.312 87.157 40.512 87.827 ;
     RECT  44.352 86.581 44.376 87.827 ;
     RECT  77.232 86.581 78.312 87.827 ;
     RECT  67.2 83.459 67.512 87.877 ;
     RECT  23.712 87.589 25.848 88.067 ;
     RECT  23.712 88.067 25.272 88.115 ;
     RECT  30.912 87.347 31.176 88.403 ;
     RECT  68.784 87.781 68.808 88.595 ;
     RECT  34.8 87.637 36.312 88.643 ;
     RECT  47.568 84.709 47.928 88.643 ;
     RECT  71.856 87.541 73.608 88.643 ;
     RECT  24 88.115 25.272 88.739 ;
     RECT  45.6 84.325 46.008 88.741 ;
     RECT  13.2 87.779 13.512 88.885 ;
     RECT  56.4 82.691 56.712 88.885 ;
     RECT  83.4 71.843 83.712 88.885 ;
     RECT  47.568 88.643 47.592 88.933 ;
     RECT  59.472 85.331 59.496 88.979 ;
     RECT  44.976 88.741 46.008 89.077 ;
     RECT  47.136 88.933 47.592 89.077 ;
     RECT  24 88.739 24.456 89.363 ;
     RECT  82.128 87.685 82.152 89.363 ;
     RECT  27.792 88.069 27.816 89.413 ;
     RECT  29.4 84.515 29.712 89.413 ;
     RECT  37.632 86.677 37.656 89.413 ;
     RECT  31.152 88.403 31.176 89.461 ;
     RECT  67.104 87.877 67.512 89.461 ;
     RECT  27.792 89.413 29.712 89.507 ;
     RECT  31.056 89.461 31.176 89.507 ;
     RECT  83.4 88.885 84.168 89.507 ;
     RECT  71.856 88.643 73.368 89.555 ;
     RECT  37.632 89.413 37.896 89.699 ;
     RECT  18.6 87.251 18.912 89.701 ;
     RECT  37.872 89.699 37.896 89.845 ;
     RECT  40.08 87.827 40.512 89.845 ;
     RECT  56.304 88.885 56.712 89.845 ;
     RECT  13.2 88.885 14.232 89.941 ;
     RECT  15.36 85.523 15.384 89.941 ;
     RECT  13.2 89.941 15.384 89.987 ;
     RECT  34.8 88.643 35.88 89.989 ;
     RECT  31.056 89.507 31.08 90.037 ;
     RECT  44.976 89.077 47.592 90.037 ;
     RECT  13.2 89.987 15.192 90.083 ;
     RECT  24 89.363 24.408 90.083 ;
     RECT  27.888 89.507 29.712 90.083 ;
     RECT  39.936 89.845 40.512 90.083 ;
     RECT  44.208 90.037 47.592 90.083 ;
     RECT  61.8 80.291 62.232 90.083 ;
     RECT  67.104 89.461 68.424 90.371 ;
     RECT  40.08 90.083 40.512 90.419 ;
     RECT  44.208 90.083 46.008 90.563 ;
     RECT  27.888 90.083 27.912 90.613 ;
     RECT  34.8 89.989 35.928 90.659 ;
     RECT  57.888 84.133 57.912 90.659 ;
     RECT  86.064 90.037 86.088 90.659 ;
     RECT  30.768 90.037 31.08 90.707 ;
     RECT  67.2 90.371 68.424 90.947 ;
     RECT  30.96 90.707 31.08 91.043 ;
     RECT  75.744 89.461 75.768 91.187 ;
     RECT  2.4 83.219 3.192 91.235 ;
     RECT  37.872 89.845 38.472 91.235 ;
     RECT  29.088 90.083 29.712 91.331 ;
     RECT  18.288 89.701 18.912 91.571 ;
     RECT  74.688 88.597 74.712 91.717 ;
     RECT  40.2 90.419 40.512 91.765 ;
     RECT  26.112 89.461 26.136 91.811 ;
     RECT  44.208 90.563 45.912 91.859 ;
     RECT  6.576 84.181 6.6 91.907 ;
     RECT  47.184 90.083 47.592 92.387 ;
     RECT  2.4 91.235 3.048 92.435 ;
     RECT  27.744 90.613 27.912 92.963 ;
     RECT  30.96 91.043 30.984 92.963 ;
     RECT  34.8 90.659 35.88 92.963 ;
     RECT  7.8 87.107 8.112 93.013 ;
     RECT  74.688 91.717 75.288 93.251 ;
     RECT  40.2 91.765 40.824 93.299 ;
     RECT  7.8 93.013 8.472 93.301 ;
     RECT  80.928 93.205 80.952 93.347 ;
     RECT  72.6 89.555 72.912 93.445 ;
     RECT  75.264 93.251 75.288 93.491 ;
     RECT  32.88 87.587 32.904 93.539 ;
     RECT  34.8 92.963 35.208 93.539 ;
     RECT  58.752 91.717 58.776 93.539 ;
     RECT  63.792 90.421 63.816 93.539 ;
     RECT  67.2 90.947 67.512 93.877 ;
     RECT  61.8 90.083 62.112 94.405 ;
     RECT  10.032 94.021 10.056 94.451 ;
     RECT  15.168 90.083 15.192 94.501 ;
     RECT  7.68 93.301 8.472 94.549 ;
     RECT  67.2 93.877 67.608 94.549 ;
     RECT  7.68 94.549 8.856 94.645 ;
     RECT  14.736 94.501 15.192 94.645 ;
     RECT  47.184 92.387 47.208 94.691 ;
     RECT  10.8 94.597 10.824 94.739 ;
     RECT  14.64 94.645 15.192 94.787 ;
     RECT  14.64 94.787 14.856 94.835 ;
     RECT  27.744 92.963 27.768 94.835 ;
     RECT  40.2 93.299 40.512 94.837 ;
     RECT  29.4 91.331 29.712 95.125 ;
     RECT  14.832 94.835 14.856 95.171 ;
     RECT  66.576 94.549 67.608 95.219 ;
     RECT  61.8 94.405 62.76 95.411 ;
     RECT  67.2 95.219 67.608 95.411 ;
     RECT  71.616 93.445 72.912 95.507 ;
     RECT  37.872 91.235 37.896 95.509 ;
     RECT  7.104 94.645 8.856 96.229 ;
     RECT  6.912 96.229 8.856 96.277 ;
     RECT  10.032 95.509 10.056 96.371 ;
     RECT  30.816 95.125 30.84 96.371 ;
     RECT  37.872 95.509 38.088 96.371 ;
     RECT  40.2 94.837 40.776 96.371 ;
     RECT  56.112 89.845 56.712 96.371 ;
     RECT  58.944 93.925 58.968 96.371 ;
     RECT  28.512 95.125 29.712 96.467 ;
     RECT  44.208 91.859 44.232 96.467 ;
     RECT  38.064 96.371 38.088 96.755 ;
     RECT  6.816 96.277 8.856 96.901 ;
     RECT  14.784 96.805 14.808 96.947 ;
     RECT  6.72 96.901 8.856 96.949 ;
     RECT  2.4 92.435 2.712 97.209 ;
     RECT  13.2 90.083 13.512 97.209 ;
     RECT  18.6 91.571 18.912 97.209 ;
     RECT  24 90.083 24.312 97.209 ;
     RECT  29.4 96.467 29.712 97.209 ;
     RECT  34.8 93.539 35.112 97.209 ;
     RECT  40.2 96.371 40.512 97.209 ;
     RECT  45.6 91.859 45.912 97.209 ;
     RECT  51 79.571 51.312 97.209 ;
     RECT  56.4 96.371 56.712 97.209 ;
     RECT  61.8 95.411 62.112 97.209 ;
     RECT  67.2 95.411 67.512 97.209 ;
     RECT  72.6 95.507 72.912 97.209 ;
     RECT  78 87.827 78.312 97.209 ;
     RECT  83.4 89.507 83.712 97.209 ;
     RECT  2.4 97.209 2.52 97.223 ;
     RECT  13.2 97.209 13.32 97.223 ;
     RECT  18.6 97.209 18.72 97.223 ;
     RECT  24 97.209 24.12 97.223 ;
     RECT  29.4 97.209 29.52 97.223 ;
     RECT  34.8 97.209 34.92 97.223 ;
     RECT  40.2 97.209 40.32 97.223 ;
     RECT  45.6 97.209 45.72 97.223 ;
     RECT  51 97.209 51.12 97.223 ;
     RECT  56.4 97.209 56.52 97.223 ;
     RECT  61.8 97.209 61.92 97.223 ;
     RECT  67.2 97.209 67.32 97.223 ;
     RECT  72.6 97.209 72.72 97.223 ;
     RECT  78 97.209 78.12 97.223 ;
     RECT  83.4 97.209 83.52 97.223 ;
     RECT  6.24 96.949 8.856 97.381 ;
     RECT  5.472 97.381 8.856 97.429 ;
     RECT  5.088 97.429 8.856 99.205 ;
     RECT  5.088 99.205 9.144 99.251 ;
     RECT  5.088 99.251 8.088 99.344 ;
     RECT  18.408 0.016 19.344 0.132 ;
     RECT  19.752 0.016 20.688 0.132 ;
     RECT  18.36 0.132 19.488 1.859 ;
     RECT  19.704 0.132 20.736 0.563 ;
     RECT  19.704 0.563 20.832 1.763 ;
     RECT  19.608 1.763 20.928 1.811 ;
     RECT  19.608 1.811 20.904 1.859 ;
     RECT  18.36 1.859 18.912 2.137 ;
     RECT  20.88 1.859 20.904 3.061 ;
     RECT  44.616 2.867 45.6 4.643 ;
     RECT  17.448 2.915 18.6 3.587 ;
     RECT  15.672 3.443 16.8 3.491 ;
     RECT  15.672 3.491 16.992 3.683 ;
     RECT  11.16 3.587 12.48 4.595 ;
     RECT  17.16 3.587 18.6 5.459 ;
     RECT  15.672 3.683 17.136 4.019 ;
     RECT  13.752 3.875 15.264 4.019 ;
     RECT  9.72 4.019 11.136 4.067 ;
     RECT  15.576 4.019 17.136 4.067 ;
     RECT  16.656 4.067 17.136 5.413 ;
     RECT  35.208 4.115 35.352 5.605 ;
     RECT  56.712 4.261 58.032 5.171 ;
     RECT  40.512 4.355 41.616 5.459 ;
     RECT  24.312 4.403 24.408 5.845 ;
     RECT  69.96 4.501 71.424 6.709 ;
     RECT  71.448 4.501 72.6 5.605 ;
     RECT  12.048 4.595 12.624 5.845 ;
     RECT  55.176 5.077 56.4 8.533 ;
     RECT  35.544 5.605 37.008 6.373 ;
     RECT  33.048 5.845 34.032 6.899 ;
     RECT  82.104 6.229 83.4 11.509 ;
     RECT  71.448 6.275 72.6 8.915 ;
     RECT  12.072 6.323 13.2 6.851 ;
     RECT  69.96 6.709 71.328 6.995 ;
     RECT  33.048 6.899 34.08 8.389 ;
     RECT  2.712 7.093 4.176 7.283 ;
     RECT  9.96 7.765 11.376 7.813 ;
     RECT  64.08 7.811 64.104 7.861 ;
     RECT  17.256 7.861 18.6 9.155 ;
     RECT  63.672 7.861 64.104 8.341 ;
     RECT  63.672 8.341 65.088 8.869 ;
     RECT  28.248 8.485 29.4 10.835 ;
     RECT  55.176 8.533 56.304 8.773 ;
     RECT  55.176 8.773 56.256 10.067 ;
     RECT  64.104 8.869 65.088 10.067 ;
     RECT  9.96 8.915 10.944 12.563 ;
     RECT  71.4 8.915 72.6 10.213 ;
     RECT  11.592 9.061 12.864 9.491 ;
     RECT  2.712 9.445 4.176 9.683 ;
     RECT  55.032 10.067 56.256 11.699 ;
     RECT  63.672 10.067 65.088 14.627 ;
     RECT  28.224 10.835 29.4 11.029 ;
     RECT  71.4 10.883 72.6 13.045 ;
     RECT  28.224 11.029 29.28 11.941 ;
     RECT  33.504 11.363 33.648 12.517 ;
     RECT  78.312 11.365 79.344 11.555 ;
     RECT  82.104 11.509 83.136 12.755 ;
     RECT  54.744 11.699 56.256 12.325 ;
     RECT  29.712 11.893 30.816 12.035 ;
     RECT  27.96 11.941 29.28 13.619 ;
     RECT  19.368 11.989 20.88 12.851 ;
     RECT  54.744 12.325 55.968 13.621 ;
     RECT  11.832 12.421 13.2 18.275 ;
     RECT  9.816 12.563 10.944 12.659 ;
     RECT  82.104 12.755 83.4 16.117 ;
     RECT  26.472 13.189 27.936 13.573 ;
     RECT  27.384 13.619 29.28 14.197 ;
     RECT  54.744 13.621 55.776 14.867 ;
     RECT  71.4 13.715 72.6 16.501 ;
     RECT  31.848 14.101 33.024 15.349 ;
     RECT  70.392 14.101 71.376 16.789 ;
     RECT  27.384 14.197 28.8 14.867 ;
     RECT  30.648 14.773 31.824 16.019 ;
     RECT  54.696 14.867 55.776 14.963 ;
     RECT  55.68 14.963 55.776 15.829 ;
     RECT  31.848 15.349 32.88 15.877 ;
     RECT  3.48 15.493 4.8 20.821 ;
     RECT  22.536 15.589 24 16.019 ;
     RECT  24.744 15.973 25.92 16.595 ;
     RECT  22.944 16.019 24 16.933 ;
     RECT  31.536 16.019 31.824 16.405 ;
     RECT  47.904 16.019 47.928 17.077 ;
     RECT  82.104 16.117 83.184 17.075 ;
     RECT  55.68 16.403 55.824 17.077 ;
     RECT  24.744 16.595 25.944 16.981 ;
     RECT  49.8 16.837 51 18.419 ;
     RECT  22.968 16.933 24 20.099 ;
     RECT  25.128 16.981 25.944 17.029 ;
     RECT  25.128 17.029 26.208 17.605 ;
     RECT  54.744 17.077 55.824 17.699 ;
     RECT  86.616 17.077 87.648 17.219 ;
     RECT  46.776 17.365 47.904 17.651 ;
     RECT  41.256 17.941 42.672 20.435 ;
     RECT  78.312 17.989 79.488 21.539 ;
     RECT  70.392 18.035 71.856 18.131 ;
     RECT  11.784 18.275 13.2 18.851 ;
     RECT  24.744 18.275 26.208 19.427 ;
     RECT  50.88 18.419 51 19.765 ;
     RECT  13.608 18.517 15.072 19.091 ;
     RECT  37.32 18.707 38.232 18.949 ;
     RECT  11.592 18.851 13.2 19.045 ;
     RECT  37.32 18.949 38.976 20.005 ;
     RECT  39 18.949 40.2 19.333 ;
     RECT  11.592 19.045 13.104 20.003 ;
     RECT  31.848 19.475 33.024 20.147 ;
     RECT  37.896 20.005 38.976 21.637 ;
     RECT  31.848 20.147 33.456 21.109 ;
     RECT  58.632 20.485 60.048 21.155 ;
     RECT  3.48 20.821 4.56 23.219 ;
     RECT  8.112 20.821 9.36 21.397 ;
     RECT  42.696 21.109 44.112 22.259 ;
     RECT  44.136 21.109 45.6 22.259 ;
     RECT  51.312 21.155 52.008 22.117 ;
     RECT  72.912 21.395 73.512 22.165 ;
     RECT  8.112 21.397 9.12 22.931 ;
     RECT  37.992 21.637 38.976 24.371 ;
     RECT  18.912 22.165 20.16 24.469 ;
     RECT  72.912 22.165 74.352 24.515 ;
     RECT  42.696 22.259 42.744 23.701 ;
     RECT  39 22.355 40.2 28.357 ;
     RECT  74.376 22.693 75.744 24.325 ;
     RECT  31.848 22.835 32.832 26.149 ;
     RECT  8.112 22.931 9.36 24.227 ;
     RECT  82.2 23.269 83.4 23.317 ;
     RECT  58.152 23.701 59.472 25.715 ;
     RECT  37.8 24.371 38.976 25.765 ;
     RECT  29.712 24.469 30.72 25.091 ;
     RECT  30.744 24.469 31.824 25.091 ;
     RECT  42.192 24.803 42.672 25.141 ;
     RECT  33.096 25.139 34.416 25.715 ;
     RECT  40.968 25.141 42.672 25.669 ;
     RECT  41.16 25.669 42.672 26.053 ;
     RECT  41.16 26.053 42.624 26.291 ;
     RECT  73.896 26.197 75.264 26.291 ;
     RECT  41.16 26.291 42.672 26.435 ;
     RECT  73.896 26.291 75.696 26.819 ;
     RECT  37.608 26.531 38.976 27.493 ;
     RECT  74.448 26.819 75.696 27.107 ;
     RECT  74.448 27.107 75.336 27.157 ;
     RECT  74.472 27.157 75.336 27.877 ;
     RECT  67.512 27.301 69.024 28.499 ;
     RECT  31.848 27.347 32.832 30.709 ;
     RECT  85.488 27.635 86.016 27.877 ;
     RECT  37.464 27.779 38.976 27.875 ;
     RECT  57.528 27.781 58.8 28.547 ;
     RECT  58.824 27.781 60.048 29.029 ;
     RECT  13.512 27.877 14.64 28.645 ;
     RECT  14.664 27.877 15.84 29.461 ;
     RECT  84.6 27.877 86.016 28.739 ;
     RECT  39 28.357 39.984 29.795 ;
     RECT  2.904 28.405 4.368 28.451 ;
     RECT  67.512 28.499 67.848 29.365 ;
     RECT  56.712 28.547 57 29.605 ;
     RECT  58.752 28.547 58.8 29.605 ;
     RECT  83.712 28.739 86.016 30.035 ;
     RECT  72.912 29.029 74.064 31.285 ;
     RECT  30.504 29.219 31.824 30.275 ;
     RECT  86.424 29.411 87.408 29.795 ;
     RECT  14.808 29.461 15.84 30.083 ;
     RECT  76.92 29.605 78 30.757 ;
     RECT  58.824 29.651 60.048 38.243 ;
     RECT  70.728 29.653 72.144 30.179 ;
     RECT  39 29.795 40.2 37.667 ;
     RECT  86.328 29.795 87.408 31.379 ;
     RECT  83.712 30.035 86.304 30.085 ;
     RECT  14.712 30.083 15.84 31.379 ;
     RECT  84.648 30.085 86.304 30.323 ;
     RECT  42.696 30.133 43.872 35.363 ;
     RECT  65.544 30.181 66.576 30.805 ;
     RECT  29.712 30.275 31.824 30.421 ;
     RECT  83.712 30.323 86.304 30.757 ;
     RECT  29.712 30.421 30.816 32.387 ;
     RECT  30.84 30.421 31.824 31.861 ;
     RECT  13.512 30.611 14.544 32.437 ;
     RECT  32.76 30.755 32.856 31.861 ;
     RECT  83.712 30.757 84.912 31.955 ;
     RECT  84.936 30.757 86.304 31.379 ;
     RECT  76.896 30.851 76.944 30.901 ;
     RECT  75.624 30.901 76.944 31.379 ;
     RECT  14.568 31.379 15.84 34.259 ;
     RECT  84.936 31.379 87.408 31.669 ;
     RECT  85.512 31.669 87.408 32.437 ;
     RECT  33.096 31.861 34.416 34.549 ;
     RECT  62.424 31.861 63.648 31.907 ;
     RECT  76.968 31.955 78 32.387 ;
     RECT  41.016 32.437 42.144 33.827 ;
     RECT  70.296 32.437 71.808 34.355 ;
     RECT  86.184 32.437 87.408 33.683 ;
     RECT  73.896 32.531 75.024 34.165 ;
     RECT  15.864 32.965 17.088 33.061 ;
     RECT  17.112 32.965 18.6 33.107 ;
     RECT  15.864 33.061 16.992 34.259 ;
     RECT  17.016 33.107 18.6 34.405 ;
     RECT  75.24 33.397 76.368 34.931 ;
     RECT  31.536 33.539 31.584 34.645 ;
     RECT  13.512 33.683 14.544 35.557 ;
     RECT  31.848 33.683 33.072 34.595 ;
     RECT  86.184 33.683 87.432 34.501 ;
     RECT  65.544 34.115 66.576 36.805 ;
     RECT  70.296 34.355 72.6 35.605 ;
     RECT  73.032 34.355 74.256 36.373 ;
     RECT  17.016 34.405 18.384 34.691 ;
     RECT  86.184 34.501 87.504 34.835 ;
     RECT  30.504 34.645 31.584 35.845 ;
     RECT  19.32 34.691 20.496 35.219 ;
     RECT  80.232 35.123 81 36.373 ;
     RECT  70.632 35.605 72.6 35.797 ;
     RECT  62.232 35.699 62.424 36.997 ;
     RECT  70.632 35.797 71.712 35.893 ;
     RECT  60.072 35.893 61.104 36.659 ;
     RECT  71.4 35.939 72.432 36.323 ;
     RECT  71.4 36.323 72.6 38.677 ;
     RECT  80.232 36.373 81.36 37.045 ;
     RECT  13.512 36.947 14.496 38.531 ;
     RECT  64.104 36.949 65.184 38.147 ;
     RECT  86.544 36.995 87.504 38.149 ;
     RECT  79.896 37.187 80.88 37.283 ;
     RECT  79.896 37.283 81.36 39.395 ;
     RECT  78.408 37.427 79.632 38.147 ;
     RECT  62.112 37.907 63.12 38.291 ;
     RECT  78.408 38.147 79.872 39.395 ;
     RECT  19.512 38.149 20.544 38.483 ;
     RECT  86.424 38.149 87.504 38.627 ;
     RECT  35.112 38.243 36.144 38.435 ;
     RECT  58.824 38.243 59.592 38.245 ;
     RECT  59.544 38.245 59.592 39.301 ;
     RECT  71.4 38.677 72.384 39.011 ;
     RECT  56.304 38.723 56.4 39.877 ;
     RECT  24.312 38.725 25.536 41.077 ;
     RECT  40.632 38.819 40.728 39.589 ;
     RECT  71.4 39.011 72.6 41.363 ;
     RECT  40.632 39.589 41.952 40.211 ;
     RECT  67.512 39.781 68.832 41.219 ;
     RECT  68.856 39.781 70.128 40.019 ;
     RECT  55.272 39.877 56.4 40.789 ;
     RECT  33.432 39.973 34.8 42.707 ;
     RECT  68.856 40.019 70.176 40.547 ;
     RECT  48.984 40.405 50.4 40.883 ;
     RECT  37.632 40.835 38.16 41.221 ;
     RECT  17.112 40.981 18.6 41.123 ;
     RECT  36.744 41.221 38.16 42.419 ;
     RECT  71.304 41.363 72.6 43.861 ;
     RECT  42.264 41.845 43.392 41.891 ;
     RECT  85.752 42.133 86.832 43.331 ;
     RECT  24.312 42.227 25.536 43.379 ;
     RECT  62.664 42.517 63.648 42.707 ;
     RECT  35.112 42.709 36.432 43.283 ;
     RECT  35.112 43.283 35.256 44.293 ;
     RECT  85.752 43.331 86.136 44.437 ;
     RECT  42.264 43.477 43.392 43.523 ;
     RECT  31.512 43.861 33.024 44.725 ;
     RECT  71.448 43.861 72.6 45.061 ;
     RECT  56.712 44.389 57.84 49.235 ;
     RECT  13.512 44.579 13.656 45.541 ;
     RECT  5.304 44.677 6.768 44.723 ;
     RECT  6.792 44.677 7.8 46.787 ;
     RECT  69.528 44.915 70.8 45.059 ;
     RECT  71.448 45.347 72.6 47.363 ;
     RECT  21.912 46.117 23.232 47.603 ;
     RECT  68.424 46.165 69.504 46.211 ;
     RECT  36.744 46.645 37.92 46.787 ;
     RECT  36.744 46.787 38.064 46.835 ;
     RECT  36.744 46.835 38.088 46.837 ;
     RECT  36.84 46.837 38.088 47.075 ;
     RECT  65.448 47.029 66.816 47.939 ;
     RECT  37.632 47.075 38.088 47.797 ;
     RECT  67.512 47.075 68.424 48.373 ;
     RECT  24.312 47.557 25.296 49.091 ;
     RECT  21.912 47.603 24 47.939 ;
     RECT  72.912 47.701 74.304 49.235 ;
     RECT  37.656 47.797 38.088 47.845 ;
     RECT  37.992 47.845 38.088 48.325 ;
     RECT  27.912 47.891 29.4 49.091 ;
     RECT  22.992 47.939 24 48.949 ;
     RECT  37.992 48.325 39.504 48.515 ;
     RECT  67.512 48.373 68.928 49.331 ;
     RECT  37.848 48.515 39.504 49.379 ;
     RECT  23.016 48.949 24 50.629 ;
     RECT  57.864 49.091 58.152 49.235 ;
     RECT  56.712 49.235 58.152 49.813 ;
     RECT  67.512 49.331 67.608 50.821 ;
     RECT  39.264 49.379 39.504 49.525 ;
     RECT  56.808 49.813 58.152 50.149 ;
     RECT  33.72 50.101 34.8 51.299 ;
     RECT  49.896 50.149 51 50.723 ;
     RECT  56.808 50.149 58.128 50.819 ;
     RECT  48.648 50.677 49.872 50.723 ;
     RECT  54.936 50.677 56.4 51.781 ;
     RECT  74.52 50.771 74.616 51.923 ;
     RECT  40.512 50.963 40.968 52.261 ;
     RECT  21.672 50.965 22.992 51.635 ;
     RECT  62.112 51.781 63.168 53.557 ;
     RECT  74.592 51.923 74.616 52.261 ;
     RECT  40.512 52.261 41.52 60.181 ;
     RECT  82.2 52.357 83.4 52.981 ;
     RECT  6.648 52.405 7.8 56.579 ;
     RECT  76.968 52.837 78 54.613 ;
     RECT  19.416 52.981 20.592 54.899 ;
     RECT  41.544 52.981 42.624 60.227 ;
     RECT  42.648 52.981 43.92 54.563 ;
     RECT  68.376 52.981 69.744 54.085 ;
     RECT  30.168 53.029 31.296 54.419 ;
     RECT  79.896 53.461 81.36 60.949 ;
     RECT  62.112 53.557 63.12 55.331 ;
     RECT  57.576 54.085 58.992 55.283 ;
     RECT  30.024 54.419 31.296 54.611 ;
     RECT  30.024 54.611 30.36 55.813 ;
     RECT  56.808 55.283 58.992 56.341 ;
     RECT  62.112 55.331 63.168 55.667 ;
     RECT  78.312 55.573 79.632 57.059 ;
     RECT  30.264 55.813 30.36 56.101 ;
     RECT  35.592 56.245 37.056 56.291 ;
     RECT  57.576 56.341 58.992 56.723 ;
     RECT  56.808 57.011 57.576 58.117 ;
     RECT  77.016 57.157 78 58.979 ;
     RECT  42.648 58.021 44.112 58.693 ;
     RECT  44.136 58.021 45.6 58.739 ;
     RECT  19.368 58.117 20.592 60.277 ;
     RECT  17.352 58.501 18.6 61.091 ;
     RECT  42.648 58.693 43.92 59.027 ;
     RECT  37.176 58.739 37.272 60.181 ;
     RECT  2.712 58.835 3.84 61.667 ;
     RECT  76.992 58.979 78 59.269 ;
     RECT  76.824 59.269 78 60.275 ;
     RECT  6.6 59.797 7.8 60.949 ;
     RECT  41.304 60.227 42.624 62.195 ;
     RECT  18.912 60.467 19.92 61.043 ;
     RECT  29.712 60.467 30.36 61.525 ;
     RECT  11.976 60.565 13.2 61.859 ;
     RECT  22.824 60.901 24 63.781 ;
     RECT  6.696 60.949 7.8 61.667 ;
     RECT  80.376 60.949 81.36 61.475 ;
     RECT  82.2 61.043 83.28 62.675 ;
     RECT  74.712 61.139 75.744 61.619 ;
     RECT  13.512 61.235 14.04 62.677 ;
     RECT  78.312 61.429 79.824 63.203 ;
     RECT  79.848 61.475 81.36 63.203 ;
     RECT  29.712 61.525 31.872 61.669 ;
     RECT  6.6 61.667 7.8 61.763 ;
     RECT  30.648 61.669 31.872 61.811 ;
     RECT  6.312 61.763 7.8 67.765 ;
     RECT  42.648 61.765 43.968 62.195 ;
     RECT  29.712 61.811 31.872 61.909 ;
     RECT  13.104 61.859 13.2 63.061 ;
     RECT  29.712 61.909 30.816 62.291 ;
     RECT  30.84 61.909 31.872 62.291 ;
     RECT  41.304 62.195 43.968 62.533 ;
     RECT  29.712 62.291 31.872 62.581 ;
     RECT  75.744 62.435 75.768 63.157 ;
     RECT  41.304 62.533 42.48 63.923 ;
     RECT  42.504 62.533 43.968 62.579 ;
     RECT  29.712 62.581 30.864 64.309 ;
     RECT  30.888 62.581 31.872 63.013 ;
     RECT  13.512 62.677 14.832 63.781 ;
     RECT  14.856 62.677 16.032 63.205 ;
     RECT  74.616 63.157 75.768 63.781 ;
     RECT  46.728 63.779 47.352 64.597 ;
     RECT  74.616 63.781 75.792 64.067 ;
     RECT  40.68 63.923 40.776 65.317 ;
     RECT  71.112 64.357 72.384 64.693 ;
     RECT  13.512 64.595 15.12 65.027 ;
     RECT  46.728 64.597 48 70.789 ;
     RECT  13.512 65.027 14.28 66.085 ;
     RECT  39.048 65.701 40.2 65.891 ;
     RECT  20.76 66.131 20.808 67.285 ;
     RECT  22.8 66.227 23.328 67.285 ;
     RECT  78.312 66.229 79.776 66.371 ;
     RECT  19.56 66.275 20.688 66.611 ;
     RECT  18.912 66.611 20.688 67.717 ;
     RECT  41.064 66.613 42.192 66.659 ;
     RECT  41.016 66.659 42.192 67.523 ;
     RECT  59.256 67.283 59.64 67.333 ;
     RECT  20.76 67.285 21.888 67.331 ;
     RECT  21.912 67.285 23.328 67.331 ;
     RECT  20.712 67.331 21.888 67.763 ;
     RECT  59.256 67.333 60.432 69.587 ;
     RECT  60.456 67.333 61.8 69.587 ;
     RECT  15.816 67.571 15.864 69.013 ;
     RECT  30.888 67.669 31.92 69.011 ;
     RECT  19.656 67.717 20.688 67.763 ;
     RECT  3.192 67.765 4.704 68.243 ;
     RECT  6.312 67.765 7.488 69.683 ;
     RECT  29.712 67.907 30.864 71.221 ;
     RECT  12.024 68.965 13.2 70.739 ;
     RECT  71.496 69.203 72.6 69.491 ;
     RECT  38.76 69.301 40.2 70.645 ;
     RECT  62.664 69.301 63.984 69.971 ;
     RECT  28.248 69.493 29.4 70.547 ;
     RECT  15.816 69.587 15.864 70.645 ;
     RECT  6.312 69.683 7.8 69.731 ;
     RECT  67.512 69.733 68.976 70.307 ;
     RECT  40.512 70.021 41.616 71.123 ;
     RECT  28.272 70.547 29.4 70.837 ;
     RECT  38.76 70.645 39.936 71.123 ;
     RECT  82.344 70.645 83.4 70.835 ;
     RECT  11.736 70.739 13.2 72.179 ;
     RECT  46.776 70.789 48 70.931 ;
     RECT  84.6 70.789 85.872 70.835 ;
     RECT  82.056 70.835 83.4 71.315 ;
     RECT  28.296 70.837 29.4 72.851 ;
     RECT  29.712 73.091 30.864 80.677 ;
     RECT  31.032 74.147 31.32 75.109 ;
     RECT  61.68 74.579 61.8 75.781 ;
     RECT  24.312 74.915 24.552 76.357 ;
     RECT  15.912 74.963 16.056 75.109 ;
     RECT  15.912 75.109 17.328 75.827 ;
     RECT  17.352 75.109 18.48 75.971 ;
     RECT  41.064 75.397 42.384 75.827 ;
     RECT  58.152 75.397 59.232 75.971 ;
     RECT  27.768 75.683 27.816 76.933 ;
     RECT  63.048 75.781 64.224 75.875 ;
     RECT  15.816 75.827 17.328 75.971 ;
     RECT  73.752 75.875 75.024 79.283 ;
     RECT  57.864 75.971 59.232 79.525 ;
     RECT  46.632 76.069 48 76.259 ;
     RECT  12.024 76.117 13.2 76.979 ;
     RECT  47.472 76.259 48 76.885 ;
     RECT  13.512 76.309 14.544 77.557 ;
     RECT  14.568 76.309 15.792 78.227 ;
     RECT  48.024 76.597 49.248 76.883 ;
     RECT  27.768 76.933 29.136 78.277 ;
     RECT  33.624 77.077 34.8 77.555 ;
     RECT  9.696 77.411 9.72 78.373 ;
     RECT  22.632 77.893 24 81.251 ;
     RECT  14.328 78.227 15.792 80.149 ;
     RECT  5.808 78.659 5.952 79.717 ;
     RECT  74.976 79.283 75.024 79.955 ;
     RECT  57.96 79.525 59.232 80.051 ;
     RECT  74.976 79.955 75 80.341 ;
     RECT  57.864 80.051 59.232 82.691 ;
     RECT  37.632 80.147 37.68 81.445 ;
     RECT  44.328 80.245 45.6 80.917 ;
     RECT  30.888 80.531 31.968 81.539 ;
     RECT  8.568 80.629 9.696 80.771 ;
     RECT  49.704 81.445 51 82.691 ;
     RECT  44.328 81.491 45.6 82.789 ;
     RECT  40.512 82.549 42 84.323 ;
     RECT  56.712 82.691 59.232 83.173 ;
     RECT  28.392 82.837 29.4 82.979 ;
     RECT  75.912 82.885 76.896 83.843 ;
     RECT  76.92 82.885 78 84.611 ;
     RECT  7.68 83.027 7.8 84.181 ;
     RECT  56.712 83.173 58.704 83.795 ;
     RECT  72.912 83.363 74.064 84.757 ;
     RECT  56.712 83.795 57.912 84.133 ;
     RECT  44.328 83.843 45.6 84.035 ;
     RECT  12.12 83.989 13.2 84.037 ;
     RECT  56.712 84.133 57.888 90.659 ;
     RECT  6.6 84.181 7.8 86.965 ;
     RECT  39.792 84.323 40.2 85.621 ;
     RECT  29.712 84.515 30.72 86.099 ;
     RECT  30.84 84.611 30.984 85.957 ;
     RECT  62.232 84.805 63.6 85.235 ;
     RECT  39.048 85.621 40.2 86.005 ;
     RECT  39.048 86.005 40.08 86.195 ;
     RECT  29.712 86.099 31.296 87.157 ;
     RECT  39.312 86.195 40.08 87.157 ;
     RECT  44.376 86.581 45.6 87.827 ;
     RECT  6.6 86.965 7.68 87.107 ;
     RECT  6.6 87.107 7.8 91.907 ;
     RECT  29.712 87.157 30.912 88.403 ;
     RECT  11.544 87.541 13.056 87.683 ;
     RECT  36.312 87.637 37.632 88.643 ;
     RECT  82.152 87.685 83.4 89.363 ;
     RECT  67.512 87.781 68.784 88.595 ;
     RECT  44.976 87.827 45.6 88.741 ;
     RECT  29.712 88.403 31.152 89.461 ;
     RECT  67.512 88.595 68.424 89.461 ;
     RECT  73.608 88.597 74.688 88.643 ;
     RECT  35.88 88.643 35.928 89.989 ;
     RECT  73.368 88.643 74.688 89.555 ;
     RECT  14.232 88.885 15.36 89.941 ;
     RECT  46.008 88.933 47.136 89.077 ;
     RECT  29.712 89.461 31.056 90.037 ;
     RECT  74.712 89.461 75.744 91.187 ;
     RECT  27.792 89.507 27.888 90.613 ;
     RECT  38.472 89.845 39.936 90.083 ;
     RECT  29.712 90.037 30.768 90.707 ;
     RECT  27.912 90.083 29.088 91.331 ;
     RECT  46.008 90.083 47.184 90.563 ;
     RECT  45.912 90.563 47.184 94.691 ;
     RECT  29.712 90.707 30.96 92.963 ;
     RECT  74.712 91.187 75.288 91.717 ;
     RECT  27.912 91.331 29.4 92.963 ;
     RECT  44.232 91.859 45.6 96.467 ;
     RECT  7.68 91.907 7.8 93.301 ;
     RECT  10.032 94.451 10.056 94.549 ;
     RECT  13.512 94.501 14.736 94.645 ;
     RECT  8.856 94.549 10.056 94.597 ;
     RECT  8.856 94.597 10.8 94.739 ;
     RECT  13.512 94.645 14.64 94.835 ;
     RECT  8.856 94.739 10.056 95.509 ;
     RECT  13.512 94.835 14.832 95.171 ;
     RECT  29.712 95.125 30.816 96.371 ;
     RECT  8.856 95.509 10.032 96.371 ;
     RECT  13.512 96.805 14.784 96.947 ;
  END
END ot_s81_engram_sum
END LIBRARY
